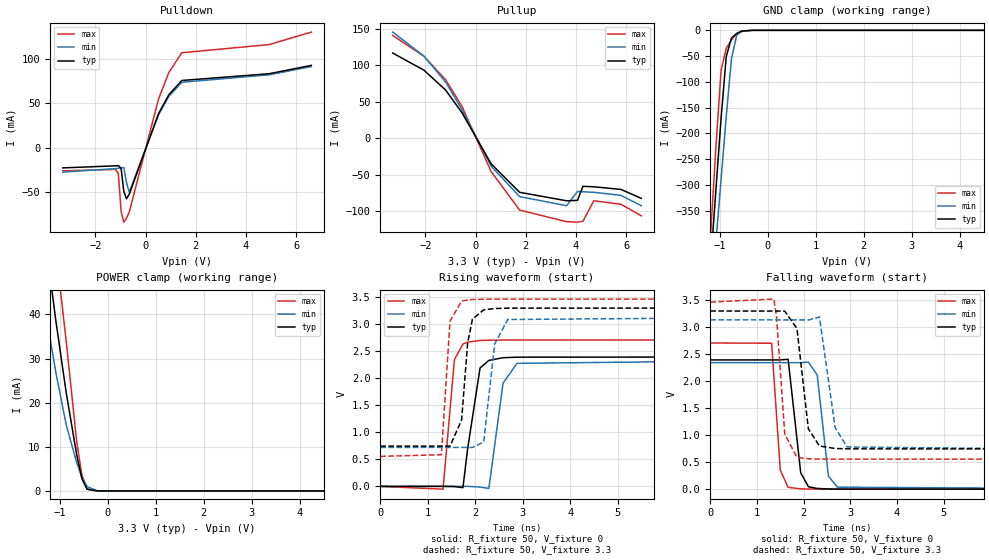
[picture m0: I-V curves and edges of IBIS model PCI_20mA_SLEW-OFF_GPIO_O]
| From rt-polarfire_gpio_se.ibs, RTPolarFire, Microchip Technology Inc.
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|   Model PCI_20mA_SLEW-OFF_GPIO_O
[Model]   PCI_20mA_SLEW-OFF_GPIO_O
Model_type   Output
Polarity   Non-Inverting
Enable   Active-High
Cref =   5p
Rref =   25
|   typ   min   max
C_comp_pullup   2.605e-12   2.605e-12   2.76e-12
C_comp_pulldown  2.605e-12   2.605e-12   2.76e-12
| Vmeas and Vref depend on the measuring edge
| Rising Edge, uncomment the following
Vmeas =   0.9405V
Vref =   0.000V
| Falling Edge, uncomment the following
|Vmeas =   2.0295V
|Vref =   3.300V
[Model Spec]
Vmeas_rising   0.9405V   0.8934V   0.9875V
Vref_rising   0.000V   0.000V   0.000V
Vmeas_falling   2.0295V   1.9280V   2.1309V
Vref_falling   3.300V   3.135V   3.465V
[Temperature Range]  25C   125C   -55C
[Voltage Range]  3.3   3.135   3.465
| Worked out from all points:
|   slope of the pulldown table from 0 to 0.495 V, typ, clamps not added: 13.4 ohm
|   slope of the pullup table from 0 to 0.495 V, typ, clamps not added: 17.3 ohm
|   GND clamp passes 1 mA (typ) near -0.51 V on its own axis
|   POWER clamp passes 1 mA (typ) near -0.46 V on its own axis
|   rising waveform, R_fixture 50, V_fixture 0: 20-80 % time 180ps typ, 197ps min, 133ps max; typ from 0 V to 2.39 V
|   rising waveform, R_fixture 50, V_fixture 3.3: 20-80 % time 145ps typ, 176ps min, 105ps max; typ from 0.745 V to 3.3 V
|   falling waveform, R_fixture 50, V_fixture 0: 20-80 % time 128ps typ, 151ps min, 93.3ps max; typ from 2.39 V to 0 V
|   falling waveform, R_fixture 50, V_fixture 3.3: 20-80 % time 192ps typ, 204ps min, 137ps max; typ from 3.3 V to 0.745 V
[GND Clamp]
| Voltage   I(typ)   I(min)   I(max)
-3.3V     -3.213A    -2.953A    -3.676A
-1.191V   -450mA     -534.3mA   -393.2mA
-1.083V   -310.2mA   -411.6mA   -227.5mA
-974.5mV  -170.4mA   -288.9mA   -76.97mA
-866.2mV  -50.48mA   -166.3mA   -34.78mA
-758mV    -15.08mA   -54.7mA    -18.33mA
-649.7mV  -5.883mA   -9.683mA   -6.874mA
-541.4mV  -1.389mA   -1.864mA   -1.426mA
-324.8mV  -3.553uA   -16.68uA   -1.172uA
6.6V      0A         0A         0A
[POWER Clamp]
| Voltage   I(typ)   I(min)   I(max)
-3.3V     320.3mA    256.6mA    387.1mA
-1.624V   89.11mA    65.97mA    116.9mA
-1.408V   67.23mA    48.87mA    90.32mA
-1.299V   57.08mA    41.04mA    77.84mA
-1.191V   47.51mA    33.68mA    65.79mA
-1.083V   38.51mA    26.79mA    54.52mA
-866.2mV  22.14mA    14.9mA     33.75mA
-649.7mV  8.213mA    6.429mA    11.19mA
-541.4mV  2.791mA    3.18mA     3.642mA
-433.1mV  359.8uA    981.3uA    499.4uA
-216.6mV  159.8nA    8.88uA     59.07nA
6.6V      0A         0A         0A
[Pullup]
| Voltage   I(typ)   I(min)   I(max)
-3.3V     117mA      145.7mA    141.1mA
-2.057V   93.5mA     112.8mA    112.5mA
-1.191V   66.14mA    77.19mA    80.37mA
-541.4mV  35.17mA    39.57mA    43.91mA
618.8mV   -34.87mA   -38.07mA   -45.43mA
1.753V    -73.94mA   -79.81mA   -98.31mA
3.625V    -85.57mA   -92.33mA   -114.2mA
4.058V    -84.98mA   -72.83mA   -114.9mA
4.275V    -65.71mA   -73.19mA   -113.6mA
4.708V    -66.38mA   -73.95mA   -85.52mA
5.79V     -69.97mA   -78.11mA   -90.3mA
6.6V      -82.26mA   -92.3mA    -106.2mA
[Pulldown]
| Voltage   I(typ)   I(min)   I(max)
-3.3V     -22.95mA   -27.7mA    -26.21mA
-1.191V   -20.65mA   -23.8mA    -24.73mA
-1.083V   -20.45mA   -23.29mA   -29.63mA
-974.5mV  -23.56mA   -22.74mA   -72.15mA
-866.2mV  -49.58mA   -22.71mA   -84.24mA
-758mV    -57.79mA   -39.9mA    -79.68mA
-649.7mV  -52.66mA   -50.34mA   -72.76mA
515.6mV   38.32mA    37.03mA    54.75mA
928.1mV   59.63mA    57.85mA    84.81mA
1.444V    75.7mA     73.69mA    107mA
4.924V    83.32mA    82.08mA    116.2mA
6.6V      92.71mA    91.43mA    130.3mA
[Ramp]
dV/dt_r   1.43642/0.180403n  1.40571/0.196944n  1.62438/0.132698n
dV/dt_f   1.53328/0.192092n  1.44881/0.204484n  1.74554/0.137438n
R_load = 50
[Rising Waveform]
R_fixture = 50
V_fixture = 0
V_fixture_min = 0
V_fixture_max = 0
| Time   V(typ)   V(min)   V(max)
0s        32.7nV     45.66nV    84.14nV
1.322ns   738.8uV    593.8uV    -51.47mV
1.562ns   -3.682mV   701.6uV    2.346V
1.741ns   -23.01mV   782uV      2.633V
1.84ns    694.5mV    826.4uV    2.669V
2.102ns   2.191V     -12.84mV   2.699V
2.287ns   2.33V      -37.77mV   2.704V
2.586ns   2.38V      1.91V      2.707V
2.88ns    2.39V      2.276V     2.707V
10ns      2.394V     2.343V     2.707V
[Rising Waveform]
R_fixture = 50
V_fixture = 3.3
V_fixture_min = 3.135
V_fixture_max = 3.465
| Time   V(typ)   V(min)   V(max)
0s        744.5mV    720.3mV    555.8mV
1.287ns   744.8mV    720.9mV    585.4mV
1.469ns   744.9mV    721mV      3.057V
1.713ns   1.229V     721.1mV    3.428V
1.84ns    2.649V     721.1mV    3.448V
1.941ns   3.093V     719.8mV    3.456V
2.178ns   3.265V     819.6mV    3.463V
2.41ns    3.29V      2.637V     3.464V
2.685ns   3.297V     3.087V     3.464V
10ns      3.3V       3.135V     3.465V
[Falling Waveform]
R_fixture = 50
V_fixture = 0
V_fixture_min = 0
V_fixture_max = 0
| Time   V(typ)   V(min)   V(max)
0s        2.394V     2.343V     2.707V
1.314ns   2.394V     2.343V     2.703V
1.499ns   2.394V     2.343V     354.8mV
1.668ns   2.405V     2.343V     33.62mV
1.937ns   303.7mV    2.343V     6.067mV
2.103ns   44.1mV     2.354V     2.356mV
2.291ns   13.39mV    2.114V     931.6uV
2.53ns    4.007mV    242.8mV    287.8uV
2.723ns   1.596mV    36.96mV    264.3uV
10ns      499.5nV    3.384uV    69.15nV
[Falling Waveform]
R_fixture = 50
V_fixture = 3.3
V_fixture_min = 3.135
V_fixture_max = 3.465
| Time   V(typ)   V(min)   V(max)
0s        3.3V       3.135V     3.465V
1.362ns   3.299V     3.135V     3.521V
1.418ns   3.299V     3.134V     3.206V
1.595ns   3.298V     3.134V     1.024V
1.857ns   2.974V     3.134V     587mV
2.101ns   1.118V     3.133V     562.9mV
2.338ns   799.5mV    3.19V      557.7mV
2.674ns   753.4mV    1.144V     556.4mV
2.929ns   747.2mV    781.5mV    556.4mV
10ns      744.5mV    720.3mV    555.8mV
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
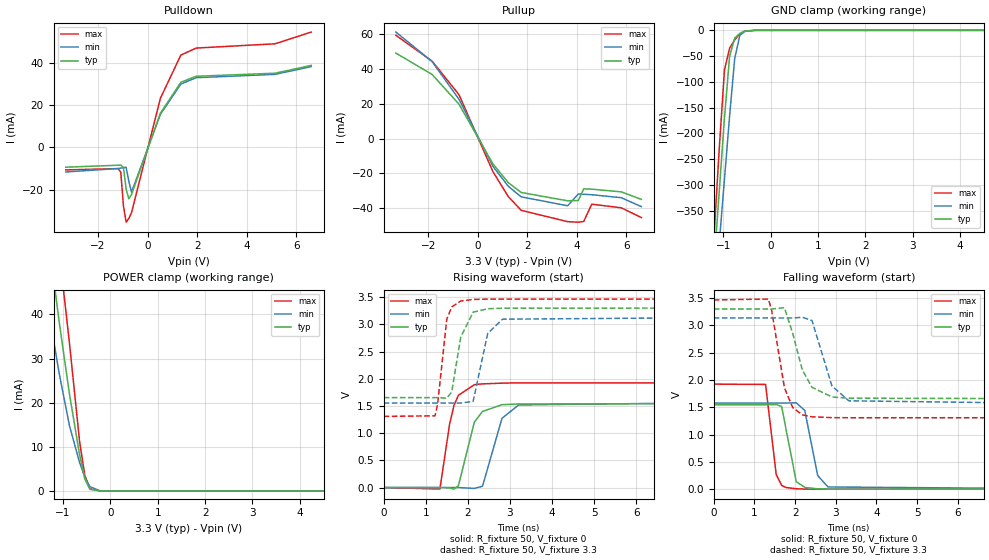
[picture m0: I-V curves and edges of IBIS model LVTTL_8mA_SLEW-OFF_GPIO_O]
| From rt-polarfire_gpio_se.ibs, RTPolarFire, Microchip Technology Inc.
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|   Model LVTTL_8mA_SLEW-OFF_GPIO_O
[Model]   LVTTL_8mA_SLEW-OFF_GPIO_O
Model_type   Output
Polarity   Non-Inverting
Enable   Active-High
Vmeas =   1.65
Cref =   5p
Rref =   1M
|   typ   min   max
C_comp_pullup   2.605e-12   2.605e-12   2.76e-12
C_comp_pulldown  2.605e-12   2.605e-12   2.76e-12
[Temperature Range]  25C   125C   -55C
[Voltage Range]  3.3   3.135   3.465
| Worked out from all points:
|   slope of the pulldown table from 0 to 0.495 V, typ, clamps not added: 31.7 ohm
|   slope of the pullup table from 0 to 0.495 V, typ, clamps not added: 41.2 ohm
|   GND clamp passes 1 mA (typ) near -0.51 V on its own axis
|   POWER clamp passes 1 mA (typ) near -0.46 V on its own axis
|   rising waveform, R_fixture 50, V_fixture 0: 20-80 % time 318ps typ, 351ps min, 255ps max; typ from 0 V to 1.55 V
|   rising waveform, R_fixture 50, V_fixture 3.3: 20-80 % time 225ps typ, 251ps min, 172ps max; typ from 1.65 V to 3.3 V
|   falling waveform, R_fixture 50, V_fixture 0: 20-80 % time 188ps typ, 234ps min, 146ps max; typ from 1.55 V to 0 V
|   falling waveform, R_fixture 50, V_fixture 3.3: 20-80 % time 392ps typ, 406ps min, 318ps max; typ from 3.3 V to 1.65 V
[GND Clamp]
| Voltage   I(typ)   I(min)   I(max)
-3.3V     -3.213A    -2.953A    -3.676A
-1.191V   -450mA     -534.3mA   -393.2mA
-1.083V   -310.2mA   -411.6mA   -227.5mA
-974.5mV  -170.4mA   -288.9mA   -76.97mA
-866.2mV  -50.48mA   -166.3mA   -34.78mA
-758mV    -15.08mA   -54.7mA    -18.33mA
-649.7mV  -5.883mA   -9.683mA   -6.874mA
-541.4mV  -1.389mA   -1.864mA   -1.426mA
-324.8mV  -3.553uA   -16.68uA   -1.172uA
6.6V      0A         0A         0A
[POWER Clamp]
| Voltage   I(typ)   I(min)   I(max)
-3.3V     320.3mA    256.6mA    387.1mA
-1.624V   89.11mA    65.97mA    116.9mA
-1.408V   67.23mA    48.87mA    90.32mA
-1.299V   57.08mA    41.04mA    77.84mA
-1.191V   47.51mA    33.68mA    65.79mA
-1.083V   38.51mA    26.79mA    54.52mA
-866.2mV  22.14mA    14.9mA     33.75mA
-649.7mV  8.213mA    6.429mA    11.19mA
-541.4mV  2.791mA    3.18mA     3.642mA
-433.1mV  359.8uA    981.3uA    499.4uA
-216.6mV  159.8nA    8.88uA     59.07nA
6.6V      0A         0A         0A
[Pullup]
| Voltage   I(typ)   I(min)   I(max)
-3.3V     49.01mA    61.08mA    59.23mA
-1.841V   36.8mA     44.17mA    44.41mA
-758mV    19.77mA    22.59mA    25.23mA
618.8mV   -14.64mA   -16.01mA   -19.11mA
1.238V    -25.28mA   -27.44mA   -33.37mA
1.753V    -30.9mA    -33.39mA   -41.12mA
3.625V    -35.67mA   -38.52mA   -47.62mA
4.058V    -35.49mA   -31.76mA   -47.93mA
4.275V    -28.78mA   -31.92mA   -47.51mA
4.599V    -29mA      -32.17mA   -37.61mA
5.79V     -30.53mA   -33.88mA   -39.68mA
6.6V      -34.85mA   -39.01mA   -45.28mA
[Pulldown]
| Voltage   I(typ)   I(min)   I(max)
-3.3V     -9.313mA   -11.56mA   -10.59mA
-1.191V   -8.379mA   -9.941mA   -9.988mA
-1.083V   -8.301mA   -9.731mA   -11.63mA
-974.5mV  -9.371mA   -9.502mA   -27.6mA
-866.2mV  -19.57mA   -9.359mA   -35.26mA
-758mV    -24.21mA   -15.94mA   -33.52mA
-649.7mV  -22.21mA   -21.08mA   -30.78mA
515.6mV   16.17mA    15.64mA    23.21mA
1.341V    30.74mA    29.91mA    43.59mA
1.959V    33.59mA    32.92mA    46.9mA
5.141V    35.03mA    34.49mA    48.92mA
6.6V      38.71mA    38.17mA    54.44mA
[Ramp]
dV/dt_r   0.927342/0.318482n  0.946258/0.350581n  1.15407/0.255484n
dV/dt_f   0.987634/0.391609n  0.948714/0.405637n  1.29419/0.317893n
R_load = 50
[Rising Waveform]
R_fixture = 50
V_fixture = 0
V_fixture_min = 0
V_fixture_max = 0
| Time   V(typ)   V(min)   V(max)
0s        62.35nV    86.49nV    169.2nV
1.336ns   -722.6uV   439.6uV    -26.56mV
1.565ns   -4.928mV   514.9uV    1.16V
1.67ns    -29.5mV    549.4uV    1.51V
1.775ns   32.86mV    584uV      1.696V
2.154ns   1.202V     -15.79mV   1.891V
2.348ns   1.399V     24.14mV    1.906V
2.81ns    1.523V     1.272V     1.919V
3.206ns   1.537V     1.519V     1.925V
10ns      1.546V     1.577V     1.923V
[Rising Waveform]
R_fixture = 50
V_fixture = 3.3
V_fixture_min = 3.135
V_fixture_max = 3.465
| Time   V(typ)   V(min)   V(max)
0s        1.654V     1.554V     1.308V
1.221ns   1.653V     1.554V     1.319V
1.28ns    1.653V     1.554V     1.524V
1.5ns     1.643V     1.554V     3.097V
1.617ns   1.758V     1.554V     3.32V
1.831ns   2.767V     1.554V     3.429V
2.125ns   3.224V     1.583V     3.458V
2.471ns   3.287V     2.832V     3.464V
2.823ns   3.297V     3.095V     3.465V
10ns      3.3V       3.135V     3.465V
[Falling Waveform]
R_fixture = 50
V_fixture = 0
V_fixture_min = 0
V_fixture_max = 0
| Time   V(typ)   V(min)   V(max)
0s        1.546V     1.577V     1.923V
1.274ns   1.546V     1.577V     1.918V
1.535ns   1.549V     1.577V     268.1mV
1.67ns    1.515V     1.577V     68.33mV
1.773ns   1.111V     1.577V     30.6mV
2.028ns   137.5mV    1.582V     7.279mV
2.238ns   31.68mV    1.441V     2.229mV
2.555ns   6.17mV     249.3mV    715.9uV
2.808ns   2.093mV    40.29mV    691.6uV
10ns      656.8nV    996.2nV    65.11nV
[Falling Waveform]
R_fixture = 50
V_fixture = 3.3
V_fixture_min = 3.135
V_fixture_max = 3.465
| Time   V(typ)   V(min)   V(max)
0s        3.3V       3.135V     3.465V
1.344ns   3.299V     3.135V     3.481V
1.422ns   3.299V     3.135V     3.278V
1.738ns   3.323V     3.134V     1.854V
1.941ns   2.851V     3.134V     1.494V
2.177ns   2.182V     3.148V     1.362V
2.415ns   1.865V     3.088V     1.325V
2.905ns   1.688V     1.89V      1.31V
3.319ns   1.666V     1.618V     1.308V
10ns      1.654V     1.554V     1.308V
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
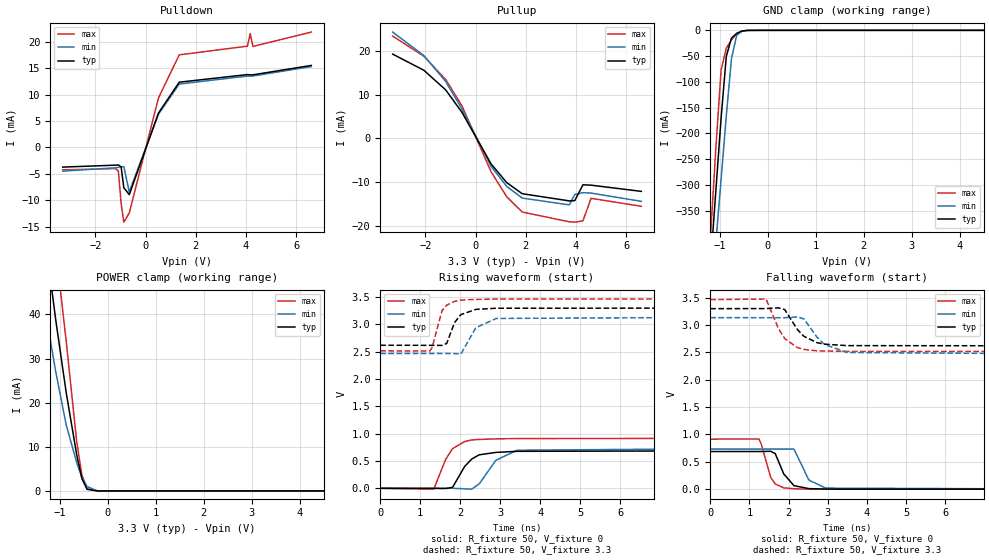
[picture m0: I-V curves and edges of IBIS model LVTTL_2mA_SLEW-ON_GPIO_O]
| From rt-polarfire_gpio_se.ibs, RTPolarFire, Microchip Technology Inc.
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|   Model LVTTL_2mA_SLEW-ON_GPIO_O
[Model]   LVTTL_2mA_SLEW-ON_GPIO_O
Model_type   Output
Polarity   Non-Inverting
Enable   Active-High
Vmeas =   1.65
Cref =   5p
Rref =   1M
|   typ   min   max
C_comp_pullup   2.605e-12   2.605e-12   2.76e-12
C_comp_pulldown  2.605e-12   2.605e-12   2.76e-12
[Temperature Range]  25C   125C   -55C
[Voltage Range]  3.3   3.135   3.465
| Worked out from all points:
|   slope of the pulldown table from 0 to 0.495 V, typ, clamps not added: 78.7 ohm
|   slope of the pullup table from 0 to 0.495 V, typ, clamps not added: 102 ohm
|   GND clamp passes 1 mA (typ) near -0.51 V on its own axis
|   POWER clamp passes 1 mA (typ) near -0.46 V on its own axis
|   rising waveform, R_fixture 50, V_fixture 0: 20-80 % time 399ps typ, 482ps min, 349ps max; typ from 0 V to 0.688 V
|   rising waveform, R_fixture 50, V_fixture 3.3: 20-80 % time 273ps typ, 335ps min, 228ps max; typ from 2.62 V to 3.3 V
|   falling waveform, R_fixture 50, V_fixture 0: 20-80 % time 283ps typ, 293ps min, 232ps max; typ from 0.688 V to 0 V
|   falling waveform, R_fixture 50, V_fixture 3.3: 20-80 % time 463ps typ, 510ps min, 411ps max; typ from 3.3 V to 2.62 V
[GND Clamp]
| Voltage   I(typ)   I(min)   I(max)
-3.3V     -3.213A    -2.953A    -3.676A
-1.191V   -450mA     -534.3mA   -393.2mA
-1.083V   -310.2mA   -411.6mA   -227.5mA
-974.5mV  -170.4mA   -288.9mA   -76.97mA
-866.2mV  -50.48mA   -166.3mA   -34.78mA
-758mV    -15.08mA   -54.7mA    -18.33mA
-649.7mV  -5.883mA   -9.683mA   -6.874mA
-541.4mV  -1.389mA   -1.864mA   -1.426mA
-433.1mV  -123uA     -242.9uA   -102.9uA
-108.3mV  -6.015nA   -50.2nA    -17.55nA
6.6V      0A         0A         0A
[POWER Clamp]
| Voltage   I(typ)   I(min)   I(max)
-3.3V     320.3mA    256.6mA    387.1mA
-1.624V   89.11mA    65.97mA    116.9mA
-1.408V   67.23mA    48.87mA    90.32mA
-1.299V   57.08mA    41.04mA    77.84mA
-1.191V   47.51mA    33.68mA    65.79mA
-1.083V   38.51mA    26.79mA    54.52mA
-866.2mV  22.14mA    14.9mA     33.75mA
-649.7mV  8.213mA    6.429mA    11.19mA
-541.4mV  2.791mA    3.18mA     3.642mA
-433.1mV  359.8uA    981.3uA    499.4uA
-216.6mV  159.8nA    8.88uA     59.07nA
6.6V      0A         0A         0A
[Pullup]
| Voltage   I(typ)   I(min)   I(max)
-3.3V     19.29mA    24.34mA    23.42mA
-2.057V   15.58mA    18.94mA    18.79mA
-1.191V   11.1mA     13.02mA    13.49mA
-541.4mV  5.944mA    6.707mA    7.425mA
618.8mV   -5.885mA   -6.429mA   -7.68mA
1.238V    -10.15mA   -11.01mA   -13.4mA
1.856V    -12.7mA    -13.7mA    -16.9mA
3.733V    -14.35mA   -15.27mA   -19.14mA
3.95V     -14.29mA   -12.89mA   -19.23mA
4.275V    -10.66mA   -12.46mA   -18.92mA
4.599V    -10.74mA   -12.56mA   -13.76mA
6.6V      -12.17mA   -14.45mA   -15.59mA
[Pulldown]
| Voltage   I(typ)   I(min)   I(max)
-3.3V     -3.739mA   -4.496mA   -4.257mA
-1.191V   -3.367mA   -3.865mA   -4.017mA
-1.083V   -3.336mA   -3.784mA   -4.528mA
-974.5mV  -3.682mA   -3.697mA   -10.54mA
-866.2mV  -7.63mA    -3.651mA   -14.16mA
-649.7mV  -8.948mA   -8.42mA    -12.42mA
515.6mV   6.515mA    6.284mA    9.374mA
1.341V    12.33mA    11.98mA    17.5mA
4.058V    13.77mA    13.49mA    19.15mA
4.166V    13.72mA    13.49mA    21.52mA
4.275V    13.72mA    13.5mA     19.1mA
6.6V      15.5mA     15.29mA    21.81mA
[Ramp]
dV/dt_r   0.412647/0.399265n  0.439639/0.482224n  0.548645/0.348717n
dV/dt_f   0.408761/0.462875n  0.400051/0.510466n  0.569027/0.410653n
R_load = 50
[Rising Waveform]
R_fixture = 50
V_fixture = 0
V_fixture_min = 0
V_fixture_max = 0
| Time   V(typ)   V(min)   V(max)
0s        102.4nV    141.1nV    300.9nV
1.338ns   -699.2uV   698.8uV    -15.06mV
1.632ns   -4.186mV   852.3uV    528.5mV
1.806ns   17.64mV    943.1uV    727.4mV
2.111ns   403.4mV    -9.759mV   857.3mV
2.285ns   536.2mV    -15.58mV   885.3mV
2.472ns   613.9mV    81.38mV    894.4mV
2.887ns   657mV      513.1mV    905mV
3.416ns   677.5mV    697.4mV    911.1mV
10ns      687.7mV    732.7mV    914.4mV
[Rising Waveform]
R_fixture = 50
V_fixture = 3.3
V_fixture_min = 3.135
V_fixture_max = 3.465
| Time   V(typ)   V(min)   V(max)
0s        2.619V     2.468V     2.517V
1.239ns   2.618V     2.468V     2.513V
1.295ns   2.618V     2.468V     2.579V
1.543ns   2.616V     2.468V     3.254V
1.66ns    2.653V     2.468V     3.354V
1.853ns   3.032V     2.468V     3.422V
2.012ns   3.18V      2.456V     3.447V
2.386ns   3.276V     2.939V     3.459V
2.896ns   3.297V     3.11V      3.465V
10ns      3.3V       3.135V     3.465V
[Falling Waveform]
R_fixture = 50
V_fixture = 0
V_fixture_min = 0
V_fixture_max = 0
| Time   V(typ)   V(min)   V(max)
0s        687.8mV    732.9mV    914.4mV
1.238ns   688mV      733.2mV    918mV
1.295ns   688.1mV    733.2mV    838mV
1.543ns   692.9mV    733.3mV    215.9mV
1.658ns   650.6mV    733.3mV    95.12mV
1.874ns   279.3mV    733.3mV    24.52mV
2.136ns   63.83mV    731.9mV    7.072mV
2.516ns   10.02mV    167.4mV    823.9uV
2.945ns   1.937mV    19.1mV     193.5nV
10ns      1.07uV     675nV      692.8nV
[Falling Waveform]
R_fixture = 50
V_fixture = 3.3
V_fixture_min = 3.135
V_fixture_max = 3.465
| Time   V(typ)   V(min)   V(max)
0s        3.3V       3.135V     3.465V
1.424ns   3.301V     3.134V     3.475V
1.735ns   3.315V     3.134V     2.944V
1.899ns   3.284V     3.134V     2.753V
2.224ns   2.918V     3.148V     2.587V
2.39ns    2.794V     3.113V     2.555V
2.724ns   2.678V     2.778V     2.528V
2.908ns   2.651V     2.65V      2.525V
3.49ns    2.624V     2.498V     2.52V
10ns      2.619V     2.468V     2.517V
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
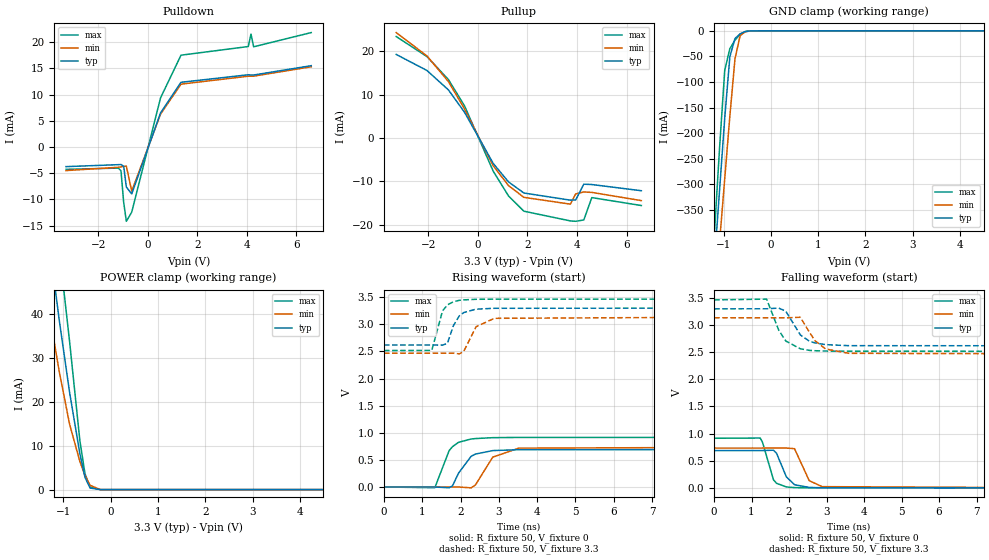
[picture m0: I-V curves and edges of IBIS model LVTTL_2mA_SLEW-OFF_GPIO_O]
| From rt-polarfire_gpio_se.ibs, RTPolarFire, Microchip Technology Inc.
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|   Model LVTTL_2mA_SLEW-OFF_GPIO_O
[Model]   LVTTL_2mA_SLEW-OFF_GPIO_O
Model_type   Output
Polarity   Non-Inverting
Enable   Active-High
Vmeas =   1.65
Cref =   5p
Rref =   1M
|   typ   min   max
C_comp_pullup   2.605e-12   2.605e-12   2.76e-12
C_comp_pulldown  2.605e-12   2.605e-12   2.76e-12
[Temperature Range]  25C   125C   -55C
[Voltage Range]  3.3   3.135   3.465
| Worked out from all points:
|   slope of the pulldown table from 0 to 0.495 V, typ, clamps not added: 78.7 ohm
|   slope of the pullup table from 0 to 0.495 V, typ, clamps not added: 102 ohm
|   GND clamp passes 1 mA (typ) near -0.51 V on its own axis
|   POWER clamp passes 1 mA (typ) near -0.46 V on its own axis
|   rising waveform, R_fixture 50, V_fixture 0: 20-80 % time 366ps typ, 429ps min, 334ps max; typ from 0 V to 0.688 V
|   rising waveform, R_fixture 50, V_fixture 3.3: 20-80 % time 263ps typ, 328ps min, 220ps max; typ from 2.62 V to 3.3 V
|   falling waveform, R_fixture 50, V_fixture 0: 20-80 % time 276ps typ, 273ps min, 224ps max; typ from 0.688 V to 0 V
|   falling waveform, R_fixture 50, V_fixture 3.3: 20-80 % time 419ps typ, 431ps min, 381ps max; typ from 3.3 V to 2.62 V
[GND Clamp]
| Voltage   I(typ)   I(min)   I(max)
-3.3V     -3.213A    -2.953A    -3.676A
-1.191V   -450mA     -534.3mA   -393.2mA
-1.083V   -310.2mA   -411.6mA   -227.5mA
-974.5mV  -170.4mA   -288.9mA   -76.97mA
-866.2mV  -50.48mA   -166.3mA   -34.78mA
-758mV    -15.08mA   -54.7mA    -18.33mA
-649.7mV  -5.883mA   -9.683mA   -6.874mA
-541.4mV  -1.389mA   -1.864mA   -1.426mA
-433.1mV  -123uA     -242.9uA   -102.9uA
-108.3mV  -6.015nA   -50.2nA    -17.55nA
6.6V      0A         0A         0A
[POWER Clamp]
| Voltage   I(typ)   I(min)   I(max)
-3.3V     320.3mA    256.6mA    387.1mA
-1.624V   89.11mA    65.97mA    116.9mA
-1.408V   67.23mA    48.87mA    90.32mA
-1.299V   57.08mA    41.04mA    77.84mA
-1.191V   47.51mA    33.68mA    65.79mA
-1.083V   38.51mA    26.79mA    54.52mA
-866.2mV  22.14mA    14.9mA     33.75mA
-649.7mV  8.213mA    6.429mA    11.19mA
-541.4mV  2.791mA    3.18mA     3.642mA
-433.1mV  359.8uA    981.3uA    499.4uA
-216.6mV  159.8nA    8.88uA     59.07nA
6.6V      0A         0A         0A
[Pullup]
| Voltage   I(typ)   I(min)   I(max)
-3.3V     19.29mA    24.34mA    23.42mA
-2.057V   15.58mA    18.94mA    18.79mA
-1.191V   11.1mA     13.02mA    13.49mA
-541.4mV  5.944mA    6.707mA    7.425mA
618.8mV   -5.885mA   -6.429mA   -7.68mA
1.238V    -10.15mA   -11.01mA   -13.4mA
1.856V    -12.7mA    -13.7mA    -16.9mA
3.733V    -14.35mA   -15.27mA   -19.14mA
3.95V     -14.29mA   -12.89mA   -19.23mA
4.275V    -10.66mA   -12.46mA   -18.92mA
4.599V    -10.74mA   -12.56mA   -13.76mA
6.6V      -12.17mA   -14.45mA   -15.59mA
[Pulldown]
| Voltage   I(typ)   I(min)   I(max)
-3.3V     -3.739mA   -4.496mA   -4.257mA
-1.191V   -3.367mA   -3.865mA   -4.017mA
-1.083V   -3.336mA   -3.784mA   -4.528mA
-974.5mV  -3.682mA   -3.697mA   -10.54mA
-866.2mV  -7.63mA    -3.651mA   -14.16mA
-649.7mV  -8.948mA   -8.42mA    -12.42mA
515.6mV   6.515mA    6.284mA    9.374mA
1.341V    12.33mA    11.98mA    17.5mA
4.058V    13.77mA    13.49mA    19.15mA
4.166V    13.72mA    13.49mA    21.52mA
4.275V    13.72mA    13.5mA     19.1mA
6.6V      15.5mA     15.29mA    21.81mA
[Ramp]
dV/dt_r   0.412661/0.366321n  0.439675/0.429222n  0.548636/0.334481n
dV/dt_f   0.408767/0.418814n  0.400054/0.431471n  0.56906/0.380593n
R_load = 50
[Rising Waveform]
R_fixture = 50
V_fixture = 0
V_fixture_min = 0
V_fixture_max = 0
| Time   V(typ)   V(min)   V(max)
0s        102.4nV    141.2nV    300.9nV
1.328ns   -749.7uV   87.49uV    -13.26mV
1.702ns   -13.89mV   112.1uV    671.9mV
1.791ns   22.24mV    117.9uV    745.1mV
1.946ns   254.5mV    128.1uV    824mV
2.276ns   565.9mV    -15.92mV   885.4mV
2.389ns   607.5mV    38.93mV    893.2mV
2.84ns    671.7mV    550.1mV    909.7mV
3.52ns    687.9mV    716.6mV    914.5mV
10ns      687.8mV    732.8mV    914.4mV
[Rising Waveform]
R_fixture = 50
V_fixture = 3.3
V_fixture_min = 3.135
V_fixture_max = 3.465
| Time   V(typ)   V(min)   V(max)
0s        2.619V     2.468V     2.517V
1.248ns   2.618V     2.468V     2.518V
1.529ns   2.617V     2.468V     3.247V
1.656ns   2.648V     2.468V     3.358V
1.815ns   2.979V     2.468V     3.418V
1.968ns   3.157V     2.456V     3.443V
2.081ns   3.217V     2.5V       3.451V
2.403ns   3.28V      2.955V     3.462V
2.883ns   3.296V     3.111V     3.464V
10ns      3.3V       3.135V     3.465V
[Falling Waveform]
R_fixture = 50
V_fixture = 0
V_fixture_min = 0
V_fixture_max = 0
| Time   V(typ)   V(min)   V(max)
0s        687.8mV    732.9mV    914.4mV
1.231ns   688.1mV    733.5mV    918.5mV
1.292ns   688.1mV    733.5mV    839.7mV
1.584ns   694mV      733.7mV    149.4mV
1.665ns   639.9mV    733.7mV    84.77mV
1.928ns   202.6mV    733.8mV    16.61mV
2.146ns   57.58mV    722mV      4.942mV
2.537ns   7.953mV    132.9mV    518.6uV
2.882ns   1.573mV    22.32mV    494.6uV
10ns      534.1nV    3.759uV    203.4nV
[Falling Waveform]
R_fixture = 50
V_fixture = 3.3
V_fixture_min = 3.135
V_fixture_max = 3.465
| Time   V(typ)   V(min)   V(max)
0s        3.3V       3.135V     3.465V
1.401ns   3.301V     3.135V     3.479V
1.724ns   3.314V     3.134V     2.907V
1.914ns   3.256V     3.134V     2.706V
2.3ns     2.82V      3.145V     2.564V
2.544ns   2.702V     2.868V     2.534V
2.694ns   2.671V     2.711V     2.528V
2.976ns   2.64V      2.56V      2.522V
3.596ns   2.621V     2.48V      2.519V
10ns      2.619V     2.468V     2.517V
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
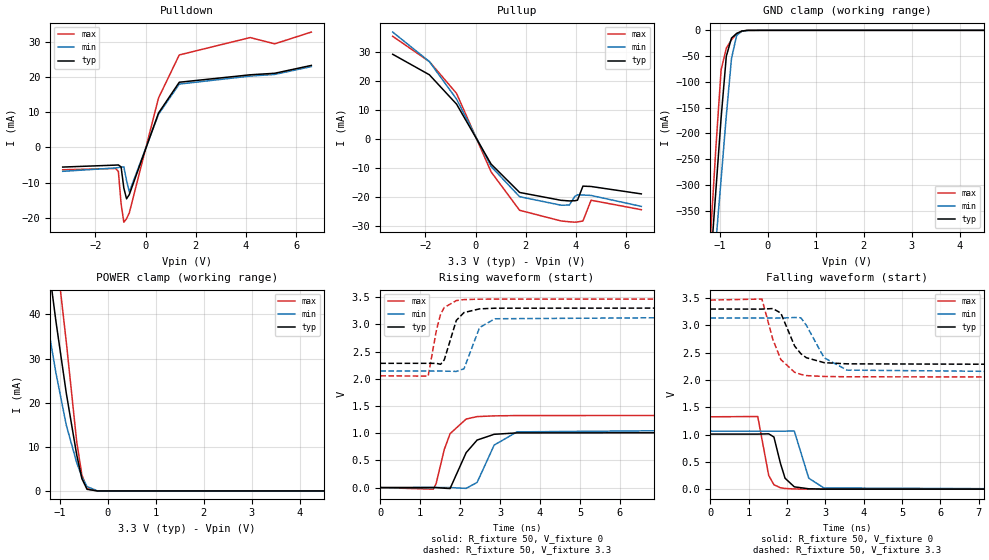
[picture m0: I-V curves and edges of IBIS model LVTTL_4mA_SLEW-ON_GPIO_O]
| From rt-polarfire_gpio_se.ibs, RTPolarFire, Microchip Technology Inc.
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|   Model LVTTL_4mA_SLEW-ON_GPIO_O
[Model]   LVTTL_4mA_SLEW-ON_GPIO_O
Model_type   Output
Polarity   Non-Inverting
Enable   Active-High
Vmeas =   1.65
Cref =   5p
Rref =   1M
|   typ   min   max
C_comp_pullup   2.605e-12   2.605e-12   2.76e-12
C_comp_pulldown  2.605e-12   2.605e-12   2.76e-12
[Temperature Range]  25C   125C   -55C
[Voltage Range]  3.3   3.135   3.465
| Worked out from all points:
|   slope of the pulldown table from 0 to 0.495 V, typ, clamps not added: 52.5 ohm
|   slope of the pullup table from 0 to 0.495 V, typ, clamps not added: 68.4 ohm
|   GND clamp passes 1 mA (typ) near -0.51 V on its own axis
|   POWER clamp passes 1 mA (typ) near -0.46 V on its own axis
|   rising waveform, R_fixture 50, V_fixture 0: 20-80 % time 399ps typ, 445ps min, 345ps max; typ from 0 V to 1.01 V
|   rising waveform, R_fixture 50, V_fixture 3.3: 20-80 % time 275ps typ, 310ps min, 222ps max; typ from 2.28 V to 3.3 V
|   falling waveform, R_fixture 50, V_fixture 0: 20-80 % time 226ps typ, 263ps min, 179ps max; typ from 1.01 V to 0 V
|   falling waveform, R_fixture 50, V_fixture 3.3: 20-80 % time 444ps typ, 516ps min, 401ps max; typ from 3.3 V to 2.28 V
[GND Clamp]
| Voltage   I(typ)   I(min)   I(max)
-3.3V     -3.213A    -2.953A    -3.676A
-1.191V   -450mA     -534.3mA   -393.2mA
-1.083V   -310.2mA   -411.6mA   -227.5mA
-974.5mV  -170.4mA   -288.9mA   -76.97mA
-866.2mV  -50.48mA   -166.3mA   -34.78mA
-758mV    -15.08mA   -54.7mA    -18.33mA
-649.7mV  -5.883mA   -9.683mA   -6.874mA
-541.4mV  -1.389mA   -1.864mA   -1.426mA
-433.1mV  -123uA     -242.9uA   -102.9uA
-108.3mV  -6.015nA   -50.2nA    -17.55nA
6.6V      0A         0A         0A
[POWER Clamp]
| Voltage   I(typ)   I(min)   I(max)
-3.3V     320.3mA    256.6mA    387.1mA
-1.624V   89.11mA    65.97mA    116.9mA
-1.408V   67.23mA    48.87mA    90.32mA
-1.299V   57.08mA    41.04mA    77.84mA
-1.191V   47.51mA    33.68mA    65.79mA
-1.083V   38.51mA    26.79mA    54.52mA
-866.2mV  22.14mA    14.9mA     33.75mA
-649.7mV  8.213mA    6.429mA    11.19mA
-541.4mV  2.791mA    3.18mA     3.642mA
-433.1mV  359.8uA    981.3uA    499.4uA
-216.6mV  159.8nA    8.88uA     59.07nA
6.6V      0A         0A         0A
[Pullup]
| Voltage   I(typ)   I(min)   I(max)
-3.3V     29.06mA    36.71mA    35.25mA
-1.841V   22mA       26.56mA    26.55mA
-758mV    11.88mA    13.59mA    15.58mA
618.8mV   -8.81mA    -9.622mA   -11.5mA
1.753V    -18.58mA   -20.04mA   -24.72mA
3.408V    -21.29mA   -22.98mA   -28.41mA
3.733V    -21.5mA    -22.92mA   -28.69mA
3.95V     -21.43mA   -19.97mA   -28.83mA
4.058V    -21.25mA   -19.36mA   -28.75mA
4.275V    -16.4mA    -19.46mA   -28.42mA
4.599V    -16.52mA   -19.61mA   -21.26mA
6.6V      -19.07mA   -23.38mA   -24.52mA
[Pulldown]
| Voltage   I(typ)   I(min)   I(max)
-3.3V     -5.571mA   -6.776mA   -6.334mA
-1.191V   -5.015mA   -5.825mA   -5.974mA
-1.083V   -4.968mA   -5.703mA   -6.818mA
-974.5mV  -5.532mA   -5.57mA    -16.01mA
-866.2mV  -11.51mA   -5.506mA   -21.2mA
-758mV    -14.57mA   -9.382mA   -20.2mA
-649.7mV  -13.39mA   -12.63mA   -18.59mA
515.6mV   9.754mA    9.406mA    14.02mA
1.341V    18.48mA    17.96mA    26.22mA
4.166V    20.59mA    20.23mA    31.15mA
5.141V    21.02mA    20.7mA     29.37mA
6.6V      23.25mA    22.92mA    32.7mA
[Ramp]
dV/dt_r   0.605268/0.399125n  0.637881/0.44472n  0.795438/0.344913n
dV/dt_f   0.609728/0.443928n  0.595968/0.516012n  0.846508/0.400802n
R_load = 50
[Rising Waveform]
R_fixture = 50
V_fixture = 0
V_fixture_min = 0
V_fixture_max = 0
| Time   V(typ)   V(min)   V(max)
0s        84.25nV    116.6nV    238.6nV
1.327ns   808uV      670.1uV    -29.1mV
1.396ns   850uV      704.9uV    66.21mV
1.603ns   -11.51mV   809.4uV    700.7mV
1.748ns   -17.71mV   882.6uV    991.5mV
2.15ns    641.7mV    -14.78mV   1.26V
2.425ns   873.5mV    95.2mV     1.305V
2.852ns   979.3mV    781mV      1.318V
3.424ns   1.005V     1.024V     1.324V
10ns      1.009V     1.063V     1.326V
[Rising Waveform]
R_fixture = 50
V_fixture = 3.3
V_fixture_min = 3.135
V_fixture_max = 3.465
| Time   V(typ)   V(min)   V(max)
0s        2.284V     2.142V     2.054V
1.199ns   2.284V     2.142V     2.049V
1.407ns   2.283V     2.142V     2.897V
1.511ns   2.266V     2.142V     3.188V
1.602ns   2.347V     2.141V     3.31V
1.904ns   3.073V     2.135V     3.437V
2.096ns   3.217V     2.184V     3.455V
2.486ns   3.285V     2.941V     3.463V
2.872ns   3.297V     3.103V     3.464V
10ns      3.3V       3.135V     3.465V
[Falling Waveform]
R_fixture = 50
V_fixture = 0
V_fixture_min = 0
V_fixture_max = 0
| Time   V(typ)   V(min)   V(max)
0s        1.009V     1.063V     1.326V
1.238ns   1.009V     1.063V     1.331V
1.524ns   1.014V     1.063V     250.6mV
1.66ns    955.1mV    1.063V     81.43mV
1.83ns    472.2mV    1.063V     25.46mV
1.951ns   199.6mV    1.063V     13.04mV
2.191ns   42.81mV    1.065V     3.979mV
2.569ns   6.823mV    200.5mV    606.4uV
2.963ns   1.044mV    22.38mV    11.67uV
10ns      663.1nV    1.862uV    174.9nV
[Falling Waveform]
R_fixture = 50
V_fixture = 3.3
V_fixture_min = 3.135
V_fixture_max = 3.465
| Time   V(typ)   V(min)   V(max)
0s        3.3V       3.135V     3.465V
1.347ns   3.299V     3.135V     3.483V
1.632ns   3.309V     3.134V     2.744V
1.84ns    3.226V     3.134V     2.375V
2.199ns   2.623V     3.145V     2.141V
2.364ns   2.481V     3.14V      2.103V
2.506ns   2.408V     3.001V     2.081V
2.968ns   2.318V     2.408V     2.065V
3.566ns   2.296V     2.181V     2.059V
10ns      2.284V     2.142V     2.054V
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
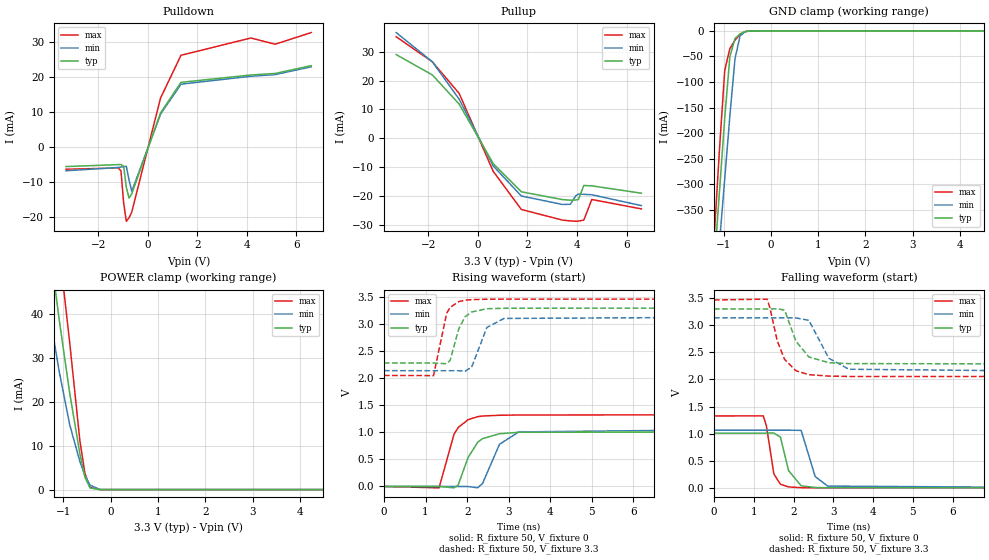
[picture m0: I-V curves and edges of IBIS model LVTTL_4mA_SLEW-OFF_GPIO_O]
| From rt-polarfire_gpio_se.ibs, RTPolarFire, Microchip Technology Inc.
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|   Model LVTTL_4mA_SLEW-OFF_GPIO_O
[Model]   LVTTL_4mA_SLEW-OFF_GPIO_O
Model_type   Output
Polarity   Non-Inverting
Enable   Active-High
Vmeas =   1.65
Cref =   5p
Rref =   1M
|   typ   min   max
C_comp_pullup   2.605e-12   2.605e-12   2.76e-12
C_comp_pulldown  2.605e-12   2.605e-12   2.76e-12
[Temperature Range]  25C   125C   -55C
[Voltage Range]  3.3   3.135   3.465
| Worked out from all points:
|   slope of the pulldown table from 0 to 0.495 V, typ, clamps not added: 52.5 ohm
|   slope of the pullup table from 0 to 0.495 V, typ, clamps not added: 68.4 ohm
|   GND clamp passes 1 mA (typ) near -0.51 V on its own axis
|   POWER clamp passes 1 mA (typ) near -0.46 V on its own axis
|   rising waveform, R_fixture 50, V_fixture 0: 20-80 % time 367ps typ, 406ps min, 319ps max; typ from 0 V to 1.01 V
|   rising waveform, R_fixture 50, V_fixture 3.3: 20-80 % time 265ps typ, 300ps min, 212ps max; typ from 2.28 V to 3.3 V
|   falling waveform, R_fixture 50, V_fixture 0: 20-80 % time 211ps typ, 246ps min, 165ps max; typ from 1.01 V to 0 V
|   falling waveform, R_fixture 50, V_fixture 3.3: 20-80 % time 391ps typ, 464ps min, 363ps max; typ from 3.3 V to 2.28 V
[GND Clamp]
| Voltage   I(typ)   I(min)   I(max)
-3.3V     -3.213A    -2.953A    -3.676A
-1.191V   -450mA     -534.3mA   -393.2mA
-1.083V   -310.2mA   -411.6mA   -227.5mA
-974.5mV  -170.4mA   -288.9mA   -76.97mA
-866.2mV  -50.48mA   -166.3mA   -34.78mA
-758mV    -15.08mA   -54.7mA    -18.33mA
-649.7mV  -5.883mA   -9.683mA   -6.874mA
-541.4mV  -1.389mA   -1.864mA   -1.426mA
-433.1mV  -123uA     -242.9uA   -102.9uA
-108.3mV  -6.015nA   -50.2nA    -17.55nA
6.6V      0A         0A         0A
[POWER Clamp]
| Voltage   I(typ)   I(min)   I(max)
-3.3V     320.3mA    256.6mA    387.1mA
-1.624V   89.11mA    65.97mA    116.9mA
-1.408V   67.23mA    48.87mA    90.32mA
-1.299V   57.08mA    41.04mA    77.84mA
-1.191V   47.51mA    33.68mA    65.79mA
-1.083V   38.51mA    26.79mA    54.52mA
-866.2mV  22.14mA    14.9mA     33.75mA
-649.7mV  8.213mA    6.429mA    11.19mA
-541.4mV  2.791mA    3.18mA     3.642mA
-433.1mV  359.8uA    981.3uA    499.4uA
-216.6mV  159.8nA    8.88uA     59.07nA
6.6V      0A         0A         0A
[Pullup]
| Voltage   I(typ)   I(min)   I(max)
-3.3V     29.06mA    36.71mA    35.25mA
-1.841V   22mA       26.56mA    26.55mA
-758mV    11.88mA    13.59mA    15.58mA
618.8mV   -8.81mA    -9.622mA   -11.5mA
1.753V    -18.58mA   -20.04mA   -24.72mA
3.408V    -21.29mA   -22.98mA   -28.41mA
3.733V    -21.5mA    -22.92mA   -28.69mA
3.95V     -21.43mA   -19.97mA   -28.83mA
4.058V    -21.25mA   -19.36mA   -28.75mA
4.275V    -16.4mA    -19.46mA   -28.42mA
4.599V    -16.52mA   -19.61mA   -21.26mA
6.6V      -19.07mA   -23.38mA   -24.52mA
[Pulldown]
| Voltage   I(typ)   I(min)   I(max)
-3.3V     -5.571mA   -6.776mA   -6.334mA
-1.191V   -5.015mA   -5.825mA   -5.974mA
-1.083V   -4.968mA   -5.703mA   -6.818mA
-974.5mV  -5.532mA   -5.57mA    -16.01mA
-866.2mV  -11.51mA   -5.506mA   -21.2mA
-758mV    -14.57mA   -9.382mA   -20.2mA
-649.7mV  -13.39mA   -12.63mA   -18.59mA
515.6mV   9.754mA    9.406mA    14.02mA
1.341V    18.48mA    17.96mA    26.22mA
4.166V    20.59mA    20.23mA    31.15mA
5.141V    21.02mA    20.7mA     29.37mA
6.6V      23.25mA    22.92mA    32.7mA
[Ramp]
dV/dt_r   0.605265/0.366908n  0.637891/0.406036n  0.795425/0.319266n
dV/dt_f   0.60978/0.39101n  0.595826/0.464402n  0.846543/0.362924n
R_load = 50
[Rising Waveform]
R_fixture = 50
V_fixture = 0
V_fixture_min = 0
V_fixture_max = 0
| Time   V(typ)   V(min)   V(max)
0s        84.25nV    116.7nV    238.6nV
1.325ns   843.8uV    -373.1uV   -25.79mV
1.685ns   -25.86mV   -474.6uV   966.5mV
1.785ns   27.37mV    -502.7uV   1.09V
2.022ns   534.7mV    -1.868mV   1.235V
2.254ns   817.6mV    -23.79mV   1.291V
2.37ns    884.2mV    53.45mV    1.303V
2.778ns   974.9mV    780.9mV    1.317V
3.242ns   1.002V     1.009V     1.322V
10ns      1.009V     1.063V     1.326V
[Rising Waveform]
R_fixture = 50
V_fixture = 3.3
V_fixture_min = 3.135
V_fixture_max = 3.465
| Time   V(typ)   V(min)   V(max)
0s        2.284V     2.142V     2.054V
1.192ns   2.283V     2.141V     2.05V
1.509ns   2.27V      2.141V     3.205V
1.592ns   2.334V     2.141V     3.312V
1.798ns   2.914V     2.141V     3.419V
1.949ns   3.136V     2.13V      3.445V
2.11ns    3.228V     2.209V     3.456V
2.474ns   3.287V     2.94V      3.463V
2.888ns   3.296V     3.108V     3.465V
10ns      3.3V       3.135V     3.465V
[Falling Waveform]
R_fixture = 50
V_fixture = 0
V_fixture_min = 0
V_fixture_max = 0
| Time   V(typ)   V(min)   V(max)
0s        1.009V     1.063V     1.326V
1.238ns   1.009V     1.063V     1.327V
1.318ns   1.009V     1.063V     1.139V
1.504ns   1.011V     1.063V     256.6mV
1.67ns    934.1mV    1.063V     65.26mV
1.873ns   319.6mV    1.063V     17.19mV
2.19ns    38.34mV    1.06V      3.334mV
2.544ns   7.152mV    207.7mV    672.7uV
2.859ns   1.822mV    32.26mV    644.4uV
10ns      1.187uV    -2.251uV   1.012uV
[Falling Waveform]
R_fixture = 50
V_fixture = 3.3
V_fixture_min = 3.135
V_fixture_max = 3.465
| Time   V(typ)   V(min)   V(max)
0s        3.3V       3.135V     3.465V
1.334ns   3.299V     3.135V     3.48V
1.404ns   3.299V     3.134V     3.323V
1.589ns   3.302V     3.134V     2.711V
1.775ns   3.277V     3.134V     2.367V
2.057ns   2.706V     3.134V     2.16V
2.384ns   2.413V     3.089V     2.087V
2.888ns   2.308V     2.389V     2.061V
3.392ns   2.291V     2.187V     2.054V
10ns      2.284V     2.142V     2.054V
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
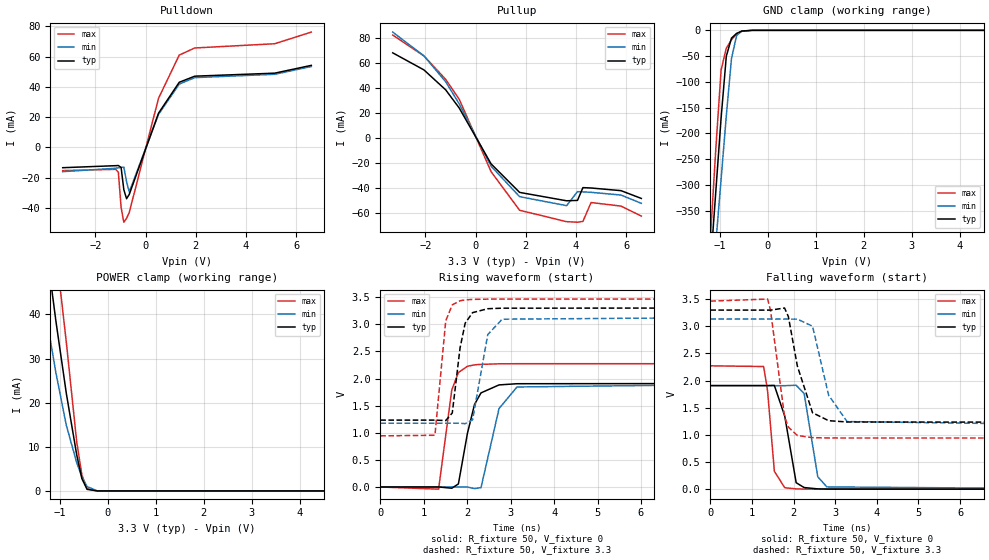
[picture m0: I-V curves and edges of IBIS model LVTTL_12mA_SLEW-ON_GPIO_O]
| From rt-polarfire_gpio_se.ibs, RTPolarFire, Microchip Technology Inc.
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|   Model LVTTL_12mA_SLEW-ON_GPIO_O
[Model]   LVTTL_12mA_SLEW-ON_GPIO_O
Model_type   Output
Polarity   Non-Inverting
Enable   Active-High
Vmeas =   1.65
Cref =   5p
Rref =   1M
|   typ   min   max
C_comp_pullup   2.605e-12   2.605e-12   2.76e-12
C_comp_pulldown  2.605e-12   2.605e-12   2.76e-12
[Temperature Range]  25C   125C   -55C
[Voltage Range]  3.3   3.135   3.465
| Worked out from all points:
|   slope of the pulldown table from 0 to 0.495 V, typ, clamps not added: 22.7 ohm
|   slope of the pullup table from 0 to 0.495 V, typ, clamps not added: 29.5 ohm
|   GND clamp passes 1 mA (typ) near -0.51 V on its own axis
|   POWER clamp passes 1 mA (typ) near -0.46 V on its own axis
|   rising waveform, R_fixture 50, V_fixture 0: 20-80 % time 293ps typ, 322ps min, 217ps max; typ from 0 V to 1.91 V
|   rising waveform, R_fixture 50, V_fixture 3.3: 20-80 % time 205ps typ, 244ps min, 153ps max; typ from 1.23 V to 3.3 V
|   falling waveform, R_fixture 50, V_fixture 0: 20-80 % time 195ps typ, 218ps min, 143ps max; typ from 1.91 V to 0 V
|   falling waveform, R_fixture 50, V_fixture 3.3: 20-80 % time 350ps typ, 384ps min, 255ps max; typ from 3.3 V to 1.23 V
[GND Clamp]
| Voltage   I(typ)   I(min)   I(max)
-3.3V     -3.213A    -2.953A    -3.676A
-1.191V   -450mA     -534.3mA   -393.2mA
-1.083V   -310.2mA   -411.6mA   -227.5mA
-974.5mV  -170.4mA   -288.9mA   -76.97mA
-866.2mV  -50.48mA   -166.3mA   -34.78mA
-758mV    -15.08mA   -54.7mA    -18.33mA
-649.7mV  -5.883mA   -9.683mA   -6.874mA
-541.4mV  -1.389mA   -1.864mA   -1.426mA
-324.8mV  -3.553uA   -16.68uA   -1.172uA
6.6V      0A         0A         0A
[POWER Clamp]
| Voltage   I(typ)   I(min)   I(max)
-3.3V     320.3mA    256.6mA    387.1mA
-1.624V   89.11mA    65.97mA    116.9mA
-1.408V   67.23mA    48.87mA    90.32mA
-1.299V   57.08mA    41.04mA    77.84mA
-1.191V   47.51mA    33.68mA    65.79mA
-1.083V   38.51mA    26.79mA    54.52mA
-866.2mV  22.14mA    14.9mA     33.75mA
-649.7mV  8.213mA    6.429mA    11.19mA
-541.4mV  2.791mA    3.18mA     3.642mA
-433.1mV  359.8uA    981.3uA    499.4uA
-216.6mV  159.8nA    8.88uA     59.07nA
6.6V      0A         0A         0A
[Pullup]
| Voltage   I(typ)   I(min)   I(max)
-3.3V     68.42mA    85.02mA    82.67mA
-2.057V   54.76mA    66mA       65.95mA
-1.191V   38.81mA    45.28mA    47.19mA
-649.7mV  24.23mA    27.51mA    31.21mA
618.8mV   -20.47mA   -22.34mA   -26.7mA
1.753V    -43.26mA   -46.67mA   -57.54mA
3.625V    -49.97mA   -53.87mA   -66.69mA
4.058V    -49.66mA   -42.65mA   -67.1mA
4.275V    -39.44mA   -42.86mA   -66.44mA
4.599V    -39.74mA   -43.19mA   -51.37mA
5.79V     -41.86mA   -45.38mA   -54.22mA
6.6V      -48.08mA   -52.01mA   -62.21mA
[Pulldown]
| Voltage   I(typ)   I(min)   I(max)
-3.3V     -13.44mA   -16.05mA   -15.36mA
-1.191V   -12.1mA    -13.8mA    -14.51mA
-1.083V   -11.99mA   -13.51mA   -16.51mA
-974.5mV  -13.34mA   -13.19mA   -39.74mA
-866.2mV  -27.94mA   -13.07mA   -49.44mA
-758mV    -33.94mA   -22.54mA   -46.94mA
-649.7mV  -31.06mA   -29.46mA   -43.03mA
515.6mV   22.6mA     21.8mA     32.41mA
1.341V    43mA       41.8mA     60.98mA
1.959V    47.03mA    46.07mA    65.66mA
5.141V    49.02mA    48.28mA    68.46mA
6.6V      54.17mA    53.41mA    76.16mA
[Ramp]
dV/dt_r   1.14513/0.293085n  1.14431/0.322193n  1.36379/0.216957n
dV/dt_f   1.2401/0.349781n  1.17517/0.384319n  1.51351/0.255478n
R_load = 50
[Rising Waveform]
R_fixture = 50
V_fixture = 0
V_fixture_min = 0
V_fixture_max = 0
| Time   V(typ)   V(min)   V(max)
0s        49.36nV    68.84nV    130.7nV
1.342ns   822.1uV    554.7uV    -40.16mV
1.645ns   -22.76mV   680uV      1.787V
1.798ns   56.13mV    743.2uV    2.109V
2.006ns   989.6mV    -390.7uV   2.226V
2.169ns   1.522V     -29.14mV   2.252V
2.318ns   1.735V     -12.72mV   2.261V
2.733ns   1.882V     1.446V     2.271V
3.147ns   1.904V     1.844V     2.273V
10ns      1.909V     1.907V     2.273V
[Rising Waveform]
R_fixture = 50
V_fixture = 3.3
V_fixture_min = 3.135
V_fixture_max = 3.465
| Time   V(typ)   V(min)   V(max)
0s        1.233V     1.176V     942.5mV
1.258ns   1.233V     1.176V     953.9mV
1.507ns   1.225V     1.176V     3.065V
1.657ns   1.365V     1.176V     3.358V
1.836ns   2.564V     1.176V     3.434V
1.954ns   3.021V     1.167V     3.449V
2.125ns   3.215V     1.24V      3.459V
2.474ns   3.287V     2.811V     3.464V
2.806ns   3.297V     3.094V     3.465V
10ns      3.3V       3.135V     3.465V
[Falling Waveform]
R_fixture = 50
V_fixture = 0
V_fixture_min = 0
V_fixture_max = 0
| Time   V(typ)   V(min)   V(max)
0s        1.909V     1.907V     2.273V
1.282ns   1.909V     1.907V     2.26V
1.376ns   1.909V     1.907V     1.812V
1.539ns   1.912V     1.907V     330.1mV
1.789ns   1.345V     1.907V     26.02mV
2.063ns   118.5mV    1.915V     5.113mV
2.254ns   30.05mV    1.761V     2.026mV
2.582ns   4.959mV    228.5mV    671uV
2.799ns   2.002mV    41.98mV    651.4uV
10ns      602.2nV    2.1uV      -46.19nV
[Falling Waveform]
R_fixture = 50
V_fixture = 3.3
V_fixture_min = 3.135
V_fixture_max = 3.465
| Time   V(typ)   V(min)   V(max)
0s        3.3V       3.135V     3.465V
1.378ns   3.299V     3.134V     3.503V
1.445ns   3.299V     3.134V     3.303V
1.784ns   3.338V     3.134V     1.335V
1.876ns   3.179V     3.134V     1.143V
2.091ns   2.27V      3.133V     989.2mV
2.456ns   1.408V     3.003V     949.8mV
2.842ns   1.262V     1.733V     943.6mV
3.284ns   1.238V     1.246V     942.6mV
10ns      1.233V     1.176V     942.5mV
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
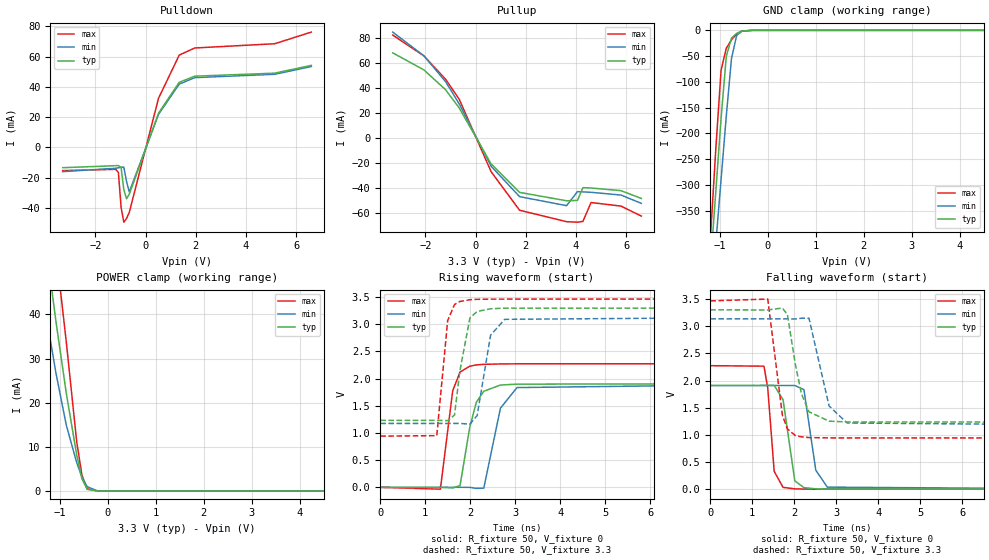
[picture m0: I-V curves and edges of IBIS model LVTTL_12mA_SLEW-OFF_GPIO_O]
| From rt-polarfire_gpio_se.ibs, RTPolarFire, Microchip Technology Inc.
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|   Model LVTTL_12mA_SLEW-OFF_GPIO_O
[Model]   LVTTL_12mA_SLEW-OFF_GPIO_O
Model_type   Output
Polarity   Non-Inverting
Enable   Active-High
Vmeas =   1.65
Cref =   5p
Rref =   1M
|   typ   min   max
C_comp_pullup   2.605e-12   2.605e-12   2.76e-12
C_comp_pulldown  2.605e-12   2.605e-12   2.76e-12
[Temperature Range]  25C   125C   -55C
[Voltage Range]  3.3   3.135   3.465
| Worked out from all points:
|   slope of the pulldown table from 0 to 0.495 V, typ, clamps not added: 22.7 ohm
|   slope of the pullup table from 0 to 0.495 V, typ, clamps not added: 29.5 ohm
|   GND clamp passes 1 mA (typ) near -0.51 V on its own axis
|   POWER clamp passes 1 mA (typ) near -0.46 V on its own axis
|   rising waveform, R_fixture 50, V_fixture 0: 20-80 % time 270ps typ, 289ps min, 203ps max; typ from 0 V to 1.91 V
|   rising waveform, R_fixture 50, V_fixture 3.3: 20-80 % time 189ps typ, 228ps min, 141ps max; typ from 1.23 V to 3.3 V
|   falling waveform, R_fixture 50, V_fixture 0: 20-80 % time 173ps typ, 195ps min, 127ps max; typ from 1.91 V to 0 V
|   falling waveform, R_fixture 50, V_fixture 3.3: 20-80 % time 308ps typ, 328ps min, 226ps max; typ from 3.3 V to 1.23 V
[GND Clamp]
| Voltage   I(typ)   I(min)   I(max)
-3.3V     -3.213A    -2.953A    -3.676A
-1.191V   -450mA     -534.3mA   -393.2mA
-1.083V   -310.2mA   -411.6mA   -227.5mA
-974.5mV  -170.4mA   -288.9mA   -76.97mA
-866.2mV  -50.48mA   -166.3mA   -34.78mA
-758mV    -15.08mA   -54.7mA    -18.33mA
-649.7mV  -5.883mA   -9.683mA   -6.874mA
-541.4mV  -1.389mA   -1.864mA   -1.426mA
-324.8mV  -3.553uA   -16.68uA   -1.172uA
6.6V      0A         0A         0A
[POWER Clamp]
| Voltage   I(typ)   I(min)   I(max)
-3.3V     320.3mA    256.6mA    387.1mA
-1.624V   89.11mA    65.97mA    116.9mA
-1.408V   67.23mA    48.87mA    90.32mA
-1.299V   57.08mA    41.04mA    77.84mA
-1.191V   47.51mA    33.68mA    65.79mA
-1.083V   38.51mA    26.79mA    54.52mA
-866.2mV  22.14mA    14.9mA     33.75mA
-649.7mV  8.213mA    6.429mA    11.19mA
-541.4mV  2.791mA    3.18mA     3.642mA
-433.1mV  359.8uA    981.3uA    499.4uA
-216.6mV  159.8nA    8.88uA     59.07nA
6.6V      0A         0A         0A
[Pullup]
| Voltage   I(typ)   I(min)   I(max)
-3.3V     68.42mA    85.02mA    82.67mA
-2.057V   54.76mA    66mA       65.95mA
-1.191V   38.81mA    45.28mA    47.19mA
-649.7mV  24.23mA    27.51mA    31.21mA
618.8mV   -20.47mA   -22.34mA   -26.7mA
1.753V    -43.26mA   -46.67mA   -57.54mA
3.625V    -49.97mA   -53.87mA   -66.69mA
4.058V    -49.66mA   -42.65mA   -67.1mA
4.275V    -39.44mA   -42.86mA   -66.44mA
4.599V    -39.74mA   -43.19mA   -51.37mA
5.79V     -41.86mA   -45.38mA   -54.22mA
6.6V      -48.08mA   -52.01mA   -62.21mA
[Pulldown]
| Voltage   I(typ)   I(min)   I(max)
-3.3V     -13.44mA   -16.05mA   -15.36mA
-1.191V   -12.1mA    -13.8mA    -14.51mA
-1.083V   -11.99mA   -13.51mA   -16.51mA
-974.5mV  -13.34mA   -13.19mA   -39.74mA
-866.2mV  -27.94mA   -13.07mA   -49.44mA
-758mV    -33.94mA   -22.54mA   -46.94mA
-649.7mV  -31.06mA   -29.46mA   -43.03mA
515.6mV   22.6mA     21.8mA     32.41mA
1.341V    43mA       41.8mA     60.98mA
1.959V    47.03mA    46.07mA    65.66mA
5.141V    49.02mA    48.28mA    68.46mA
6.6V      54.17mA    53.41mA    76.16mA
[Ramp]
dV/dt_r   1.14514/0.269635n  1.14431/0.289013n  1.36378/0.202975n
dV/dt_f   1.2401/0.307596n  1.17517/0.3281n  1.51351/0.226016n
R_load = 50
[Rising Waveform]
R_fixture = 50
V_fixture = 0
V_fixture_min = 0
V_fixture_max = 0
| Time   V(typ)   V(min)   V(max)
0s        49.37nV    68.85nV    130.7nV
1.335ns   726.1uV    657.7uV    -33.53mV
1.609ns   -10.41mV   792.7uV    1.778V
1.772ns   33.39mV    873uV      2.121V
1.986ns   1.1V       254.4uV    2.229V
2.133ns   1.565V     -19.42mV   2.253V
2.299ns   1.768V     -14.45mV   2.264V
2.669ns   1.883V     1.457V     2.271V
3.037ns   1.899V     1.836V     2.273V
10ns      1.909V     1.907V     2.273V
[Rising Waveform]
R_fixture = 50
V_fixture = 3.3
V_fixture_min = 3.135
V_fixture_max = 3.465
| Time   V(typ)   V(min)   V(max)
0s        1.233V     1.176V     942.5mV
1.255ns   1.233V     1.176V     951.4mV
1.497ns   1.228V     1.176V     3.071V
1.649ns   1.33V      1.176V     3.365V
1.766ns   2.132V     1.176V     3.42V
1.991ns   3.118V     1.164V     3.453V
2.151ns   3.237V     1.321V     3.46V
2.451ns   3.287V     2.802V     3.464V
2.765ns   3.297V     3.092V     3.464V
10ns      3.3V       3.135V     3.465V
[Falling Waveform]
R_fixture = 50
V_fixture = 0
V_fixture_min = 0
V_fixture_max = 0
| Time   V(typ)   V(min)   V(max)
0s        1.909V     1.907V     2.273V
1.277ns   1.909V     1.908V     2.264V
1.366ns   1.909V     1.908V     1.871V
1.52ns    1.91V      1.908V     328.3mV
1.731ns   1.648V     1.908V     32.86mV
2.011ns   153.1mV    1.908V     6.246mV
2.228ns   28.49mV    1.832V     1.883mV
2.51ns    6.193mV    350.6mV    599.3uV
2.783ns   1.912mV    37.27mV    577.5uV
10ns      103.8nV    3.461uV    30.82nV
[Falling Waveform]
R_fixture = 50
V_fixture = 3.3
V_fixture_min = 3.135
V_fixture_max = 3.465
| Time   V(typ)   V(min)   V(max)
0s        3.3V       3.135V     3.465V
1.368ns   3.299V     3.135V     3.499V
1.715ns   3.334V     3.134V     1.362V
1.835ns   3.213V     3.134V     1.109V
2.023ns   2.301V     3.133V     986.7mV
2.168ns   1.759V     3.146V     963.6mV
2.348ns   1.424V     3.146V     950.1mV
2.826ns   1.252V     1.532V     943.4mV
3.253ns   1.237V     1.218V     942.7mV
10ns      1.233V     1.176V     942.5mV
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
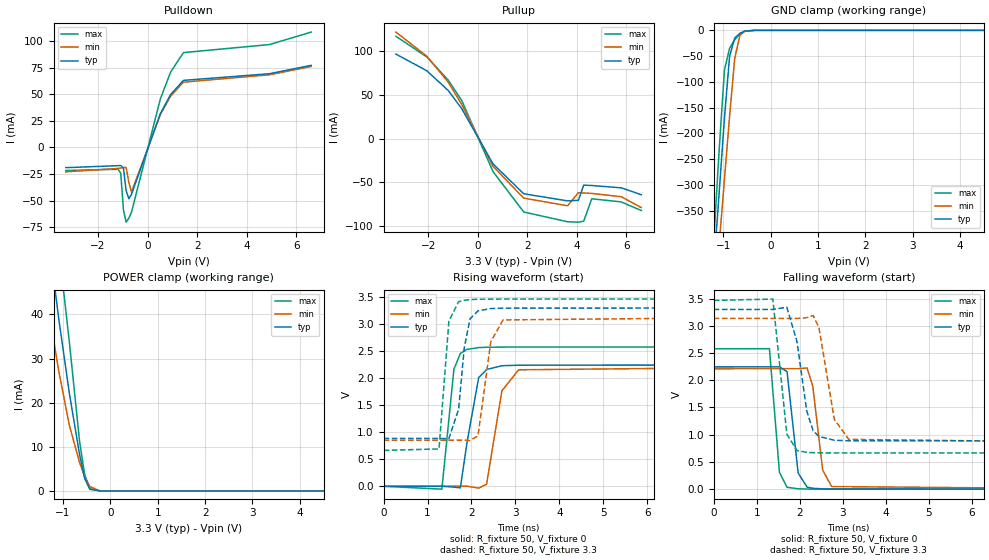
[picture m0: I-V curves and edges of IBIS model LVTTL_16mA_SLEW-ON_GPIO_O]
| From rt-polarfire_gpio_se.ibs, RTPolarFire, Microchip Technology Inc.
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|   Model LVTTL_16mA_SLEW-ON_GPIO_O
[Model]   LVTTL_16mA_SLEW-ON_GPIO_O
Model_type   Output
Polarity   Non-Inverting
Enable   Active-High
Vmeas =   1.65
Cref =   5p
Rref =   1M
|   typ   min   max
C_comp_pullup   2.605e-12   2.605e-12   2.76e-12
C_comp_pulldown  2.605e-12   2.605e-12   2.76e-12
[Temperature Range]  25C   125C   -55C
[Voltage Range]  3.3   3.135   3.465
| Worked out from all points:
|   slope of the pulldown table from 0 to 0.495 V, typ, clamps not added: 16 ohm
|   slope of the pullup table from 0 to 0.495 V, typ, clamps not added: 20.7 ohm
|   GND clamp passes 1 mA (typ) near -0.51 V on its own axis
|   POWER clamp passes 1 mA (typ) near -0.46 V on its own axis
|   rising waveform, R_fixture 50, V_fixture 0: 20-80 % time 230ps typ, 258ps min, 166ps max; typ from 0 V to 2.25 V
|   rising waveform, R_fixture 50, V_fixture 3.3: 20-80 % time 178ps typ, 219ps min, 128ps max; typ from 0.886 V to 3.3 V
|   falling waveform, R_fixture 50, V_fixture 0: 20-80 % time 161ps typ, 189ps min, 118ps max; typ from 2.25 V to 0 V
|   falling waveform, R_fixture 50, V_fixture 3.3: 20-80 % time 266ps typ, 289ps min, 188ps max; typ from 3.3 V to 0.886 V
[GND Clamp]
| Voltage   I(typ)   I(min)   I(max)
-3.3V     -3.213A    -2.953A    -3.676A
-1.191V   -450mA     -534.3mA   -393.2mA
-1.083V   -310.2mA   -411.6mA   -227.5mA
-974.5mV  -170.4mA   -288.9mA   -76.97mA
-866.2mV  -50.48mA   -166.3mA   -34.78mA
-758mV    -15.08mA   -54.7mA    -18.33mA
-649.7mV  -5.883mA   -9.683mA   -6.874mA
-541.4mV  -1.389mA   -1.864mA   -1.426mA
-324.8mV  -3.553uA   -16.68uA   -1.172uA
6.6V      0A         0A         0A
[POWER Clamp]
| Voltage   I(typ)   I(min)   I(max)
-3.3V     320.3mA    256.6mA    387.1mA
-1.624V   89.11mA    65.97mA    116.9mA
-1.408V   67.23mA    48.87mA    90.32mA
-1.299V   57.08mA    41.04mA    77.84mA
-1.191V   47.51mA    33.68mA    65.79mA
-1.083V   38.51mA    26.79mA    54.52mA
-866.2mV  22.14mA    14.9mA     33.75mA
-649.7mV  8.213mA    6.429mA    11.19mA
-541.4mV  2.791mA    3.18mA     3.642mA
-433.1mV  359.8uA    981.3uA    499.4uA
-216.6mV  159.8nA    8.88uA     59.07nA
6.6V      0A         0A         0A
[Pullup]
| Voltage   I(typ)   I(min)   I(max)
-3.3V     96.7mA     121.9mA    117.1mA
-2.057V   77.69mA    94.34mA    93.54mA
-1.191V   55.09mA    64.6mA     66.93mA
-649.7mV  34.39mA    39.18mA    43.79mA
618.8mV   -29.1mA    -31.83mA   -37.93mA
1.856V    -63.18mA   -68.18mA   -84.08mA
3.625V    -71.34mA   -76.94mA   -95.22mA
4.058V    -70.72mA   -62mA      -95.73mA
4.275V    -53.34mA   -62.31mA   -94.51mA
4.599V    -53.73mA   -62.8mA    -68.94mA
5.79V     -56.41mA   -66.57mA   -72.51mA
6.6V      -64.26mA   -79.04mA   -82.43mA
[Pulldown]
| Voltage   I(typ)   I(min)   I(max)
-3.3V     -18.99mA   -22.92mA   -21.67mA
-1.191V   -17.09mA   -19.69mA   -20.45mA
-1.083V   -16.93mA   -19.27mA   -24.29mA
-974.5mV  -19.39mA   -18.82mA   -58.87mA
-866.2mV  -40.74mA   -18.76mA   -70.29mA
-758mV    -48.24mA   -32.79mA   -66.58mA
-649.7mV  -44.03mA   -41.99mA   -60.89mA
515.6mV   32.05mA    30.96mA    45.84mA
928.1mV   49.81mA    48.32mA    70.9mA
1.444V    63.16mA    61.48mA    89.29mA
4.924V    69.44mA    68.42mA    96.89mA
6.6V      77.31mA    76.24mA    108.6mA
[Ramp]
dV/dt_r   1.34716/0.230165n  1.32688/0.257736n  1.54626/0.165524n
dV/dt_f   1.44849/0.266104n  1.369/0.28897n  1.68016/0.187817n
R_load = 50
[Rising Waveform]
R_fixture = 50
V_fixture = 0
V_fixture_min = 0
V_fixture_max = 0
| Time   V(typ)   V(min)   V(max)
0s        37.81nV    52.78nV    98.13nV
1.326ns   914.1uV    549uV      -53.4mV
1.6ns     -15.29mV   662.4uV    2.168V
1.747ns   -29.4mV    723.3uV    2.458V
1.898ns   809.5mV    1.408mV    2.534V
2.164ns   2.01V      -33.05mV   2.567V
2.344ns   2.161V     37.58mV    2.573V
2.693ns   2.231V     1.767V     2.576V
3.074ns   2.241V     2.156V     2.577V
10ns      2.245V     2.211V     2.577V
[Rising Waveform]
R_fixture = 50
V_fixture = 3.3
V_fixture_min = 3.135
V_fixture_max = 3.465
| Time   V(typ)   V(min)   V(max)
0s        885.8mV    853.3mV    664.7mV
1.261ns   885.1mV    853.2mV    690.8mV
1.486ns   881.3mV    853.2mV    3.06V
1.707ns   1.425V     853.2mV    3.416V
1.836ns   2.567V     853.2mV    3.443V
1.968ns   3.1V       845.7mV    3.455V
2.149ns   3.247V     934.8mV    3.462V
2.44ns    3.289V     2.676V     3.464V
2.719ns   3.297V     3.079V     3.465V
10ns      3.3V       3.135V     3.465V
[Falling Waveform]
R_fixture = 50
V_fixture = 0
V_fixture_min = 0
V_fixture_max = 0
| Time   V(typ)   V(min)   V(max)
0s        2.245V     2.211V     2.577V
1.295ns   2.246V     2.212V     2.579V
1.528ns   2.246V     2.212V     307.7mV
1.705ns   2.158V     2.212V     34.51mV
1.963ns   297.2mV    2.212V     6.953mV
2.171ns   37.63mV    2.225V     2.28mV
2.304ns   17.04mV    1.889V     1.028mV
2.534ns   5.095mV    351mV      363.9uV
2.742ns   1.766mV    48.16mV    309.6uV
10ns      495.6nV    2.981uV    -50.28nV
[Falling Waveform]
R_fixture = 50
V_fixture = 3.3
V_fixture_min = 3.135
V_fixture_max = 3.465
| Time   V(typ)   V(min)   V(max)
0s        3.3V       3.135V     3.465V
1.374ns   3.299V     3.134V     3.49V
1.7ns     3.34V      3.134V     1.012V
1.936ns   2.71V      3.134V     708.9mV
2.162ns   1.44V      3.148V     676.2mV
2.311ns   1.072V     3.19V      670mV
2.446ns   967.4mV    2.972V     667.1mV
2.804ns   898.9mV    1.284V     665.4mV
3.141ns   888.2mV    914.1mV    665.4mV
10ns      885.8mV    853.3mV    664.7mV
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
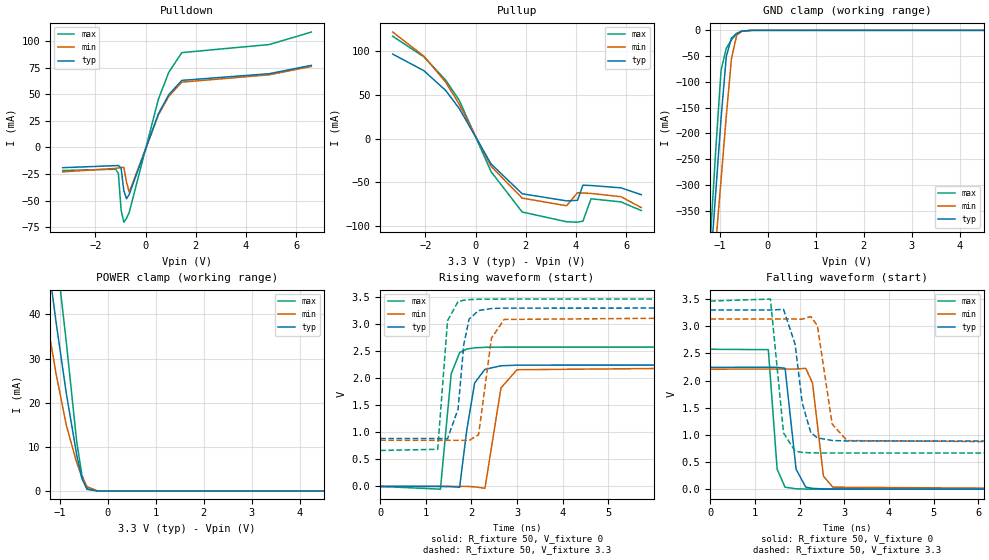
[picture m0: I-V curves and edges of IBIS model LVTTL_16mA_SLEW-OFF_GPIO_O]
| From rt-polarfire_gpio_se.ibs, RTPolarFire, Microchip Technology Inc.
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|   Model LVTTL_16mA_SLEW-OFF_GPIO_O
[Model]   LVTTL_16mA_SLEW-OFF_GPIO_O
Model_type   Output
Polarity   Non-Inverting
Enable   Active-High
Vmeas =   1.65
Cref =   5p
Rref =   1M
|   typ   min   max
C_comp_pullup   2.605e-12   2.605e-12   2.76e-12
C_comp_pulldown  2.605e-12   2.605e-12   2.76e-12
[Temperature Range]  25C   125C   -55C
[Voltage Range]  3.3   3.135   3.465
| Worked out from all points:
|   slope of the pulldown table from 0 to 0.495 V, typ, clamps not added: 16 ohm
|   slope of the pullup table from 0 to 0.495 V, typ, clamps not added: 20.7 ohm
|   GND clamp passes 1 mA (typ) near -0.51 V on its own axis
|   POWER clamp passes 1 mA (typ) near -0.46 V on its own axis
|   rising waveform, R_fixture 50, V_fixture 0: 20-80 % time 208ps typ, 229ps min, 152ps max; typ from 0 V to 2.25 V
|   rising waveform, R_fixture 50, V_fixture 3.3: 20-80 % time 164ps typ, 202ps min, 118ps max; typ from 0.886 V to 3.3 V
|   falling waveform, R_fixture 50, V_fixture 0: 20-80 % time 144ps typ, 164ps min, 105ps max; typ from 2.25 V to 0 V
|   falling waveform, R_fixture 50, V_fixture 3.3: 20-80 % time 230ps typ, 238ps min, 164ps max; typ from 3.3 V to 0.886 V
[GND Clamp]
| Voltage   I(typ)   I(min)   I(max)
-3.3V     -3.213A    -2.953A    -3.676A
-1.191V   -450mA     -534.3mA   -393.2mA
-1.083V   -310.2mA   -411.6mA   -227.5mA
-974.5mV  -170.4mA   -288.9mA   -76.97mA
-866.2mV  -50.48mA   -166.3mA   -34.78mA
-758mV    -15.08mA   -54.7mA    -18.33mA
-649.7mV  -5.883mA   -9.683mA   -6.874mA
-541.4mV  -1.389mA   -1.864mA   -1.426mA
-324.8mV  -3.553uA   -16.68uA   -1.172uA
6.6V      0A         0A         0A
[POWER Clamp]
| Voltage   I(typ)   I(min)   I(max)
-3.3V     320.3mA    256.6mA    387.1mA
-1.624V   89.11mA    65.97mA    116.9mA
-1.408V   67.23mA    48.87mA    90.32mA
-1.299V   57.08mA    41.04mA    77.84mA
-1.191V   47.51mA    33.68mA    65.79mA
-1.083V   38.51mA    26.79mA    54.52mA
-866.2mV  22.14mA    14.9mA     33.75mA
-649.7mV  8.213mA    6.429mA    11.19mA
-541.4mV  2.791mA    3.18mA     3.642mA
-433.1mV  359.8uA    981.3uA    499.4uA
-216.6mV  159.8nA    8.88uA     59.07nA
6.6V      0A         0A         0A
[Pullup]
| Voltage   I(typ)   I(min)   I(max)
-3.3V     96.7mA     121.9mA    117.1mA
-2.057V   77.69mA    94.34mA    93.54mA
-1.191V   55.09mA    64.6mA     66.93mA
-649.7mV  34.39mA    39.18mA    43.79mA
618.8mV   -29.1mA    -31.83mA   -37.93mA
1.856V    -63.18mA   -68.18mA   -84.08mA
3.625V    -71.34mA   -76.94mA   -95.22mA
4.058V    -70.72mA   -62mA      -95.73mA
4.275V    -53.34mA   -62.31mA   -94.51mA
4.599V    -53.73mA   -62.8mA    -68.94mA
5.79V     -56.41mA   -66.57mA   -72.51mA
6.6V      -64.26mA   -79.04mA   -82.43mA
[Pulldown]
| Voltage   I(typ)   I(min)   I(max)
-3.3V     -18.99mA   -22.92mA   -21.67mA
-1.191V   -17.09mA   -19.69mA   -20.45mA
-1.083V   -16.93mA   -19.27mA   -24.29mA
-974.5mV  -19.39mA   -18.82mA   -58.87mA
-866.2mV  -40.74mA   -18.76mA   -70.29mA
-758mV    -48.24mA   -32.79mA   -66.58mA
-649.7mV  -44.03mA   -41.99mA   -60.89mA
515.6mV   32.05mA    30.96mA    45.84mA
928.1mV   49.81mA    48.32mA    70.9mA
1.444V    63.16mA    61.48mA    89.29mA
4.924V    69.44mA    68.42mA    96.89mA
6.6V      77.31mA    76.24mA    108.6mA
[Ramp]
dV/dt_r   1.34716/0.207758n  1.32689/0.228954n  1.54626/0.152075n
dV/dt_f   1.44849/0.23043n  1.36901/0.238458n  1.68015/0.16379n
R_load = 50
[Rising Waveform]
R_fixture = 50
V_fixture = 0
V_fixture_min = 0
V_fixture_max = 0
| Time   V(typ)   V(min)   V(max)
0s        37.81nV    52.79nV    98.12nV
1.319ns   832uV      496.2uV    -50.72mV
1.555ns   -4.605mV   584.9uV    2.083V
1.74ns    -15.44mV   654.5uV    2.476V
1.896ns   1.037V     1.185mV    2.541V
2.069ns   1.914V     -8.314mV   2.563V
2.295ns   2.165V     -33.6mV    2.573V
2.646ns   2.231V     1.822V     2.576V
2.998ns   2.243V     2.158V     2.577V
10ns      2.245V     2.211V     2.577V
[Rising Waveform]
R_fixture = 50
V_fixture = 3.3
V_fixture_min = 3.135
V_fixture_max = 3.465
| Time   V(typ)   V(min)   V(max)
0s        885.8mV    853.3mV    664.7mV
1.259ns   885.3mV    853.2mV    686.9mV
1.475ns   883mV      853.2mV    3.065V
1.706ns   1.431V     853.1mV    3.42V
1.831ns   2.62V      853.1mV    3.444V
1.947ns   3.094V     849.6mV    3.455V
2.155ns   3.253V     955.9mV    3.462V
2.439ns   3.29V      2.744V     3.464V
2.717ns   3.297V     3.088V     3.465V
10ns      3.3V       3.135V     3.465V
[Falling Waveform]
R_fixture = 50
V_fixture = 0
V_fixture_min = 0
V_fixture_max = 0
| Time   V(typ)   V(min)   V(max)
0s        2.245V     2.211V     2.577V
1.3ns     2.246V     2.212V     2.57V
1.497ns   2.246V     2.212V     369.2mV
1.675ns   2.227V     2.212V     35.91mV
1.922ns   366.7mV    2.212V     7.155mV
2.137ns   38.29mV    2.227V     2.216mV
2.289ns   15.15mV    1.956V     919.4uV
2.534ns   4.367mV    240.5mV    833.1uV
2.745ns   1.654mV    35.82mV    809.6uV
10ns      69.69nV    2.667uV    66.36nV
[Falling Waveform]
R_fixture = 50
V_fixture = 3.3
V_fixture_min = 3.135
V_fixture_max = 3.465
| Time   V(typ)   V(min)   V(max)
0s        3.3V       3.135V     3.465V
1.347ns   3.3V       3.135V     3.502V
1.64ns    3.312V     3.135V     1.037V
1.899ns   2.671V     3.134V     699.9mV
2.06ns    1.585V     3.132V     678mV
2.251ns   1.041V     3.181V     669.4mV
2.4ns     945mV      3.008V     667.1mV
2.73ns    896.2mV    1.198V     665.7mV
3.062ns   888.5mV    894.8mV    665.7mV
10ns      885.9mV    853.3mV    664.7mV
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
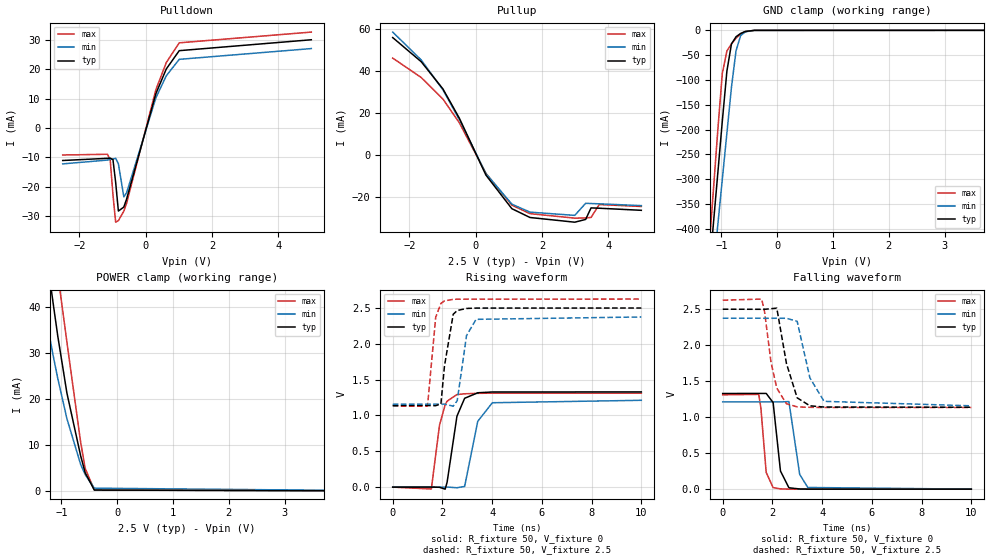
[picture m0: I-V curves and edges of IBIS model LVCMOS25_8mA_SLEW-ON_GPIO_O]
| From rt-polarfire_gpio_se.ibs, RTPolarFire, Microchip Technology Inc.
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|   Model LVCMOS25_8mA_SLEW-ON_GPIO_O
[Model]   LVCMOS25_8mA_SLEW-ON_GPIO_O
Model_type   Output
Polarity   Non-Inverting
Enable   Active-High
Vmeas =   1.25
Cref =   5p
Rref =   1M
|   typ   min   max
C_comp_pullup   2.605e-12   2.605e-12   2.76e-12
C_comp_pulldown  2.605e-12   2.605e-12   2.76e-12
[Temperature Range]  25C   125C   -55C
[Voltage Range]  2.5   2.375   2.625
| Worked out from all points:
|   slope of the pulldown table from 0 to 0.375 V, typ, clamps not added: 27.6 ohm
|   slope of the pullup table from 0 to 0.375 V, typ, clamps not added: 33.1 ohm
|   GND clamp passes 1 mA (typ) near -0.51 V on its own axis
|   POWER clamp passes 1 mA (typ) near -0.47 V on its own axis
|   rising waveform, R_fixture 50, V_fixture 0: 20-80 % time 368ps typ, 440ps min, 327ps max; typ from 0 V to 1.33 V
|   rising waveform, R_fixture 50, V_fixture 2.5: 20-80 % time 252ps typ, 308ps min, 214ps max; typ from 1.14 V to 2.5 V
|   falling waveform, R_fixture 50, V_fixture 0: 20-80 % time 243ps typ, 276ps min, 184ps max; typ from 1.33 V to 0 V
|   falling waveform, R_fixture 50, V_fixture 2.5: 20-80 % time 455ps typ, 538ps min, 414ps max; typ from 2.5 V to 1.14 V
[GND Clamp]
| Voltage   I(typ)   I(min)   I(max)
-2.5V     -2.154A    -2.028A    -2.413A
-1.23V    -500.9mA   -578.9mA   -453.4mA
-1.148V   -394.9mA   -486mA     -327.9mA
-1.066V   -289mA     -393mA     -202.4mA
-984.4mV  -183.1mA   -300.1mA   -86.85mA
-902.3mV  -82.21mA   -207.2mA   -41.59mA
-820.3mV  -27.37mA   -114.5mA   -27.29mA
-738.3mV  -12.87mA   -40.96mA   -15.82mA
-656.2mV  -6.285mA   -10.74mA   -7.396mA
-574.2mV  -2.342mA   -3.102mA   -2.493mA
-410.2mV  -62.85uA   -143.8uA   -47.39uA
5V        0A         0A         0A
[POWER Clamp]
| Voltage   I(typ)   I(min)   I(max)
-2.5V     191.3mA    149.5mA    238.1mA
-1.559V   79.6mA     58.4mA     105.4mA
-1.395V   63.37mA    46mA       85.27mA
-1.312V   55.59mA    40.21mA    75.31mA
-1.23V    48.04mA    34.68mA    65.5mA
-1.148V   40.77mA    29.43mA    56.09mA
-1.066V   33.71mA    24.49mA    47.24mA
-902.3mV  21.31mA    15.73mA    32.4mA
-656.2mV  7.665mA    5.781mA    10.63mA
-574.2mV  3.929mA    3.551mA    4.901mA
-410.2mV  189.8uA    599.4uA    178.9uA
5V        0A         0A         0A
[Pullup]
| Voltage   I(typ)   I(min)   I(max)
-2.5V     55.91mA    58.52mA    46.13mA
-1.641V   44.41mA    45.26mA    36.88mA
-984.4mV  31.41mA    31mA       26.59mA
-492.2mV  17.56mA    16.84mA    15.36mA
312.5mV   -9.641mA   -8.923mA   -8.839mA
1.094V    -25.65mA   -23.49mA   -23.96mA
1.641V    -29.85mA   -27.3mA    -28.02mA
2.992V    -32.09mA   -28.84mA   -30.16mA
3.32V     -30.78mA   -23.1mA    -30.06mA
3.484V    -25.28mA   -23.19mA   -29.82mA
3.73V     -25.43mA   -23.33mA   -23.68mA
5V        -26.43mA   -24.2mA    -24.6mA
[Pulldown]
| Voltage   I(typ)   I(min)   I(max)
-2.5V     -11.02mA   -12.17mA   -9.146mA
-1.148V   -10.28mA   -10.87mA   -8.91mA
-1.066V   -10.22mA   -10.69mA   -10.98mA
-984.4mV  -10.71mA   -10.5mA    -22.57mA
-902.3mV  -18.47mA   -10.29mA   -31.94mA
-820.3mV  -28.16mA   -12.12mA   -31.42mA
-656.2mV  -26.81mA   -23.34mA   -28.17mA
-574.2mV  -24.16mA   -22.01mA   -25.59mA
312.5mV   11.69mA    10.29mA    13.04mA
625mV     20.03mA    17.72mA    22.21mA
1.016V    26.23mA    23.29mA    28.89mA
5V        29.93mA    26.94mA    32.53mA
[Ramp]
dV/dt_r   0.797444/0.367991n  0.727439/0.43974n  0.786886/0.326725n
dV/dt_f   0.81699/0.454794n  0.730232/0.538366n  0.894846/0.414257n
R_load = 50
[Rising Waveform]
R_fixture = 50
V_fixture = 0
V_fixture_min = 0
V_fixture_max = 0
| Time   V(typ)   V(min)   V(max)
0s        15.23nV    65.48nV    18.54nV
1.554ns   678.2uV    642.3uV    -25.66mV
1.883ns   -2.121mV   778.3uV    865.9mV
2.11ns    -28.39mV   872.1uV    1.15V
2.189ns   70.21mV    904.8uV    1.2V
2.584ns   990.5mV    -8.753mV   1.292V
2.893ns   1.24V      9.588mV    1.303V
3.42ns    1.317V     918.1mV    1.309V
4.008ns   1.328V     1.178V     1.312V
10ns      1.329V     1.212V     1.311V
[Rising Waveform]
R_fixture = 50
V_fixture = 2.5
V_fixture_min = 2.375
V_fixture_max = 2.625
| Time   V(typ)   V(min)   V(max)
0s        1.138V     1.158V     1.134V
1.4ns     1.139V     1.158V     1.133V
1.73ns    1.137V     1.159V     2.372V
1.939ns   1.161V     1.159V     2.563V
2.082ns   1.691V     1.159V     2.6V
2.434ns   2.413V     1.13V      2.621V
2.596ns   2.465V     1.207V     2.623V
2.97ns    2.494V     2.116V     2.624V
3.355ns   2.499V     2.342V     2.624V
10ns      2.5V       2.375V     2.625V
[Falling Waveform]
R_fixture = 50
V_fixture = 0
V_fixture_min = 0
V_fixture_max = 0
| Time   V(typ)   V(min)   V(max)
0s        1.329V     1.212V     1.311V
1.449ns   1.33V      1.212V     1.317V
1.535ns   1.33V      1.212V     1.13V
1.749ns   1.33V      1.212V     232.8mV
2.028ns   1.203V     1.212V     21.13mV
2.323ns   252.6mV    1.212V     3.904mV
2.663ns   19.41mV    1.217V     643uV
3.097ns   2.78mV     204.9mV    499.3uV
3.422ns   785.1uV    23.52mV    475.8uV
10ns      1.624uV    3.067uV    698.2nV
[Falling Waveform]
R_fixture = 50
V_fixture = 2.5
V_fixture_min = 2.375
V_fixture_max = 2.625
| Time   V(typ)   V(min)   V(max)
0s        2.5V       2.375V     2.625V
1.568ns   2.499V     2.375V     2.641V
1.685ns   2.499V     2.374V     2.462V
1.943ns   2.507V     2.374V     1.762V
2.176ns   2.515V     2.374V     1.403V
2.564ns   1.746V     2.374V     1.187V
2.995ns   1.269V     2.332V     1.143V
3.507ns   1.158V     1.546V     1.137V
4.077ns   1.141V     1.22V      1.135V
10ns      1.138V     1.158V     1.134V
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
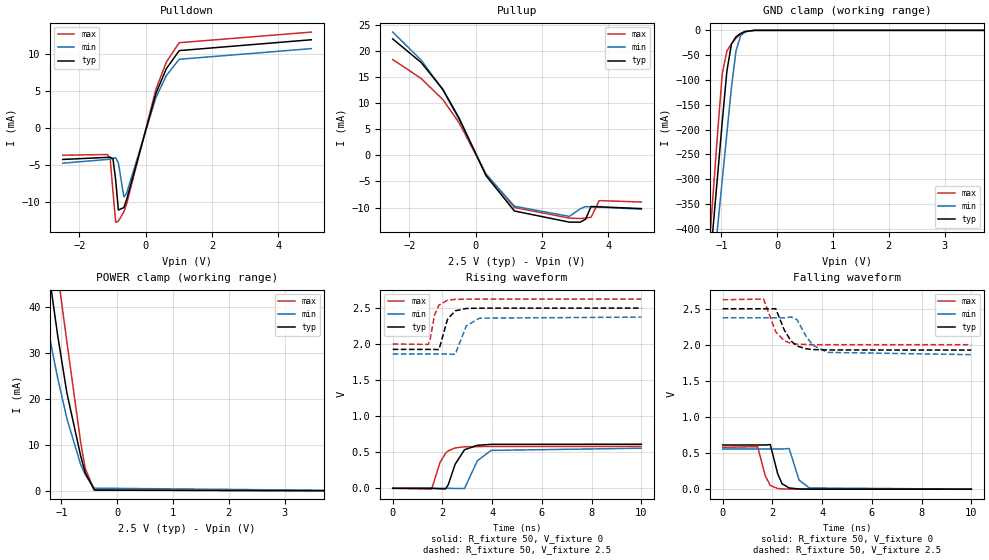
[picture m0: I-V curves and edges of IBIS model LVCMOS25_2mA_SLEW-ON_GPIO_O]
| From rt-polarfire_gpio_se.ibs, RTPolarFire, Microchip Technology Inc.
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|   Model LVCMOS25_2mA_SLEW-ON_GPIO_O
[Model]   LVCMOS25_2mA_SLEW-ON_GPIO_O
Model_type   Output
Polarity   Non-Inverting
Enable   Active-High
Vmeas =   1.25
Cref =   5p
Rref =   1M
|   typ   min   max
C_comp_pullup   2.605e-12   2.605e-12   2.76e-12
C_comp_pulldown  2.605e-12   2.605e-12   2.76e-12
[Temperature Range]  25C   125C   -55C
[Voltage Range]  2.5   2.375   2.625
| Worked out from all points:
|   slope of the pulldown table from 0 to 0.375 V, typ, clamps not added: 68.5 ohm
|   slope of the pullup table from 0 to 0.375 V, typ, clamps not added: 82.3 ohm
|   GND clamp passes 1 mA (typ) near -0.51 V on its own axis
|   POWER clamp passes 1 mA (typ) near -0.47 V on its own axis
|   rising waveform, R_fixture 50, V_fixture 0: 20-80 % time 443ps typ, 491ps min, 374ps max; typ from 0 V to 0.612 V
|   rising waveform, R_fixture 50, V_fixture 2.5: 20-80 % time 323ps typ, 369ps min, 252ps max; typ from 1.93 V to 2.5 V
|   falling waveform, R_fixture 50, V_fixture 0: 20-80 % time 270ps typ, 304ps min, 265ps max; typ from 0.612 V to 0 V
|   falling waveform, R_fixture 50, V_fixture 2.5: 20-80 % time 498ps typ, 611ps min, 436ps max; typ from 2.5 V to 1.93 V
[GND Clamp]
| Voltage   I(typ)   I(min)   I(max)
-2.5V     -2.154A    -2.028A    -2.413A
-1.23V    -500.9mA   -578.9mA   -453.4mA
-1.148V   -394.9mA   -486mA     -327.9mA
-1.066V   -289mA     -393mA     -202.4mA
-984.4mV  -183.1mA   -300.1mA   -86.85mA
-902.3mV  -82.21mA   -207.2mA   -41.59mA
-820.3mV  -27.37mA   -114.5mA   -27.29mA
-738.3mV  -12.87mA   -40.96mA   -15.82mA
-656.2mV  -6.285mA   -10.74mA   -7.396mA
-574.2mV  -2.342mA   -3.102mA   -2.493mA
-410.2mV  -62.85uA   -143.8uA   -47.39uA
5V        0A         0A         0A
[POWER Clamp]
| Voltage   I(typ)   I(min)   I(max)
-2.5V     191.3mA    149.5mA    238.1mA
-1.559V   79.6mA     58.4mA     105.4mA
-1.395V   63.37mA    46mA       85.27mA
-1.312V   55.59mA    40.21mA    75.31mA
-1.23V    48.04mA    34.68mA    65.5mA
-1.148V   40.77mA    29.43mA    56.09mA
-1.066V   33.71mA    24.49mA    47.24mA
-902.3mV  21.31mA    15.73mA    32.4mA
-656.2mV  7.665mA    5.781mA    10.63mA
-574.2mV  3.929mA    3.551mA    4.901mA
-410.2mV  189.8uA    599.4uA    178.9uA
5V        0A         0A         0A
[Pullup]
| Voltage   I(typ)   I(min)   I(max)
-2.5V     22.26mA    23.57mA    18.32mA
-1.641V   17.75mA    18.22mA    14.69mA
-984.4mV  12.59mA    12.48mA    10.63mA
-492.2mV  7.057mA    6.778mA    6.167mA
312.5mV   -3.874mA   -3.584mA   -3.572mA
1.172V    -10.66mA   -9.748mA   -9.981mA
2.828V    -12.79mA   -11.69mA   -12.02mA
3.156V    -12.8mA    -10.25mA   -12.1mA
3.32V     -12.22mA   -9.816mA   -12mA
3.484V    -9.804mA   -9.857mA   -11.86mA
3.73V     -9.86mA    -9.92mA    -8.668mA
5V        -10.2mA    -10.3mA    -8.938mA
[Pulldown]
| Voltage   I(typ)   I(min)   I(max)
-2.5V     -4.252mA   -4.758mA   -3.676mA
-1.148V   -3.97mA    -4.25mA    -3.583mA
-1.066V   -3.946mA   -4.182mA   -4.258mA
-984.4mV  -4.157mA   -4.108mA   -8.591mA
-902.3mV  -7.055mA   -4.027mA   -12.76mA
-820.3mV  -11.11mA   -4.713mA   -12.62mA
-656.2mV  -10.78mA   -9.317mA   -11.36mA
-574.2mV  -9.731mA   -8.852mA   -10.34mA
312.5mV   4.706mA    4.139mA    5.267mA
625mV     8.048mA    7.115mA    8.942mA
1.016V    10.51mA    9.332mA    11.58mA
5V        11.98mA    10.78mA    13.02mA
[Ramp]
dV/dt_r   0.367135/0.443285n  0.333758/0.491248n  0.348653/0.373674n
dV/dt_f   0.343513/0.497822n  0.306579/0.610953n  0.373865/0.435902n
R_load = 50
[Rising Waveform]
R_fixture = 50
V_fixture = 0
V_fixture_min = 0
V_fixture_max = 0
| Time   V(typ)   V(min)   V(max)
0s        25.93nV    108.4nV    32.28nV
1.566ns   854.9uV    -287.7uV   -11.93mV
1.902ns   -6.935mV   -349.5uV   358.1mV
2.129ns   -7.727mV   -391.2uV   488.2mV
2.237ns   51.19mV    -411uV     519.3mV
2.51ns    333.4mV    -2.294mV   559.9mV
2.888ns   534.9mV    -2.673mV   576.4mV
3.403ns   596.2mV    381.5mV    579.1mV
3.956ns   609.7mV    525.5mV    580mV
10ns      611.9mV    556.3mV    581.1mV
[Rising Waveform]
R_fixture = 50
V_fixture = 2.5
V_fixture_min = 2.375
V_fixture_max = 2.625
| Time   V(typ)   V(min)   V(max)
0s        1.927V     1.863V     2.002V
1.43ns    1.927V     1.863V     1.996V
1.503ns   1.927V     1.863V     2.062V
1.681ns   1.926V     1.863V     2.403V
1.862ns   1.924V     1.863V     2.542V
2.202ns   2.342V     1.863V     2.609V
2.513ns   2.462V     1.857V     2.621V
2.959ns   2.494V     2.252V     2.624V
3.488ns   2.499V     2.36V      2.625V
10ns      2.5V       2.375V     2.625V
[Falling Waveform]
R_fixture = 50
V_fixture = 0
V_fixture_min = 0
V_fixture_max = 0
| Time   V(typ)   V(min)   V(max)
0s        611.9mV    556.2mV    581.1mV
1.405ns   611.9mV    556.2mV    588mV
1.711ns   611.9mV    556.2mV    185.1mV
1.913ns   617.8mV    556.2mV    51.43mV
2.21ns    215.9mV    556.2mV    9.433mV
2.387ns   74.05mV    556.2mV    4.121mV
2.674ns   16.92mV    562.4mV    1.156mV
3.072ns   2.799mV    124.4mV    301uV
3.487ns   668uV      16.89mV    283uV
10ns      1.268uV    4.381uV    365.8nV
[Falling Waveform]
R_fixture = 50
V_fixture = 2.5
V_fixture_min = 2.375
V_fixture_max = 2.625
| Time   V(typ)   V(min)   V(max)
0s        2.5V       2.375V     2.625V
1.644ns   2.499V     2.375V     2.634V
2.133ns   2.5V       2.374V     2.18V
2.48ns    2.202V     2.374V     2.056V
2.746ns   2.054V     2.387V     2.02V
2.992ns   1.983V     2.348V     2.01V
3.359ns   1.945V     2.115V     2.005V
3.623ns   1.935V     1.995V     2.002V
4.218ns   1.929V     1.895V     2.002V
10ns      1.927V     1.864V     2.002V
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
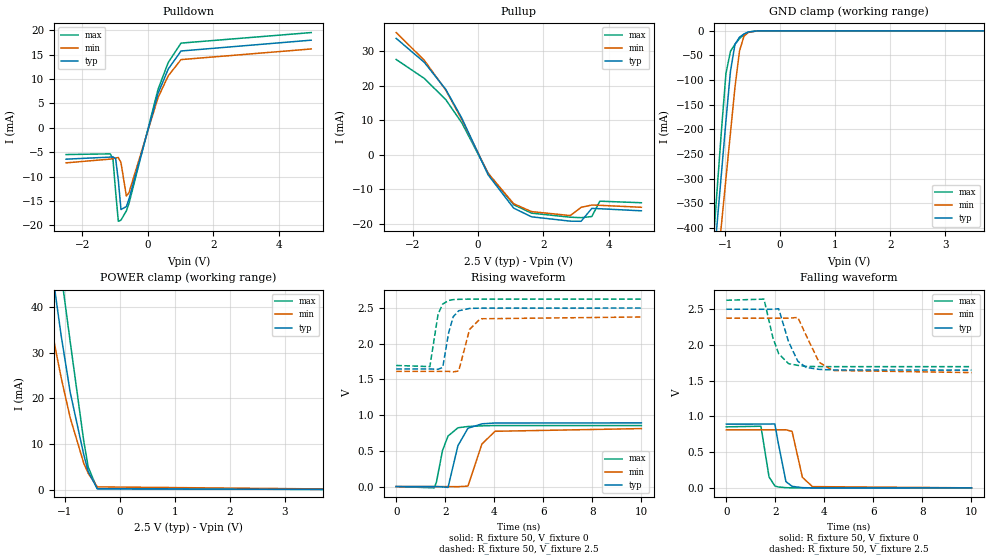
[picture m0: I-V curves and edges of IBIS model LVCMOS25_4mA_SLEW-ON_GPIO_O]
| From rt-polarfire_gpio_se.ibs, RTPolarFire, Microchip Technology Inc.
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|   Model LVCMOS25_4mA_SLEW-ON_GPIO_O
[Model]   LVCMOS25_4mA_SLEW-ON_GPIO_O
Model_type   Output
Polarity   Non-Inverting
Enable   Active-High
Vmeas =   1.25
Cref =   5p
Rref =   1M
|   typ   min   max
C_comp_pullup   2.605e-12   2.605e-12   2.76e-12
C_comp_pulldown  2.605e-12   2.605e-12   2.76e-12
[Temperature Range]  25C   125C   -55C
[Voltage Range]  2.5   2.375   2.625
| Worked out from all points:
|   slope of the pulldown table from 0 to 0.375 V, typ, clamps not added: 45.8 ohm
|   slope of the pullup table from 0 to 0.375 V, typ, clamps not added: 55 ohm
|   GND clamp passes 1 mA (typ) near -0.51 V on its own axis
|   POWER clamp passes 1 mA (typ) near -0.47 V on its own axis
|   rising waveform, R_fixture 50, V_fixture 0: 20-80 % time 419ps typ, 502ps min, 366ps max; typ from 0 V to 0.892 V
|   rising waveform, R_fixture 50, V_fixture 2.5: 20-80 % time 291ps typ, 353ps min, 255ps max; typ from 1.65 V to 2.5 V
|   falling waveform, R_fixture 50, V_fixture 0: 20-80 % time 250ps typ, 309ps min, 205ps max; typ from 0.892 V to 0 V
|   falling waveform, R_fixture 50, V_fixture 2.5: 20-80 % time 492ps typ, 606ps min, 430ps max; typ from 2.5 V to 1.65 V
[GND Clamp]
| Voltage   I(typ)   I(min)   I(max)
-2.5V     -2.154A    -2.028A    -2.413A
-1.23V    -500.9mA   -578.9mA   -453.4mA
-1.148V   -394.9mA   -486mA     -327.9mA
-1.066V   -289mA     -393mA     -202.4mA
-984.4mV  -183.1mA   -300.1mA   -86.85mA
-902.3mV  -82.21mA   -207.2mA   -41.59mA
-820.3mV  -27.37mA   -114.5mA   -27.29mA
-738.3mV  -12.87mA   -40.96mA   -15.82mA
-656.2mV  -6.285mA   -10.74mA   -7.396mA
-574.2mV  -2.342mA   -3.102mA   -2.493mA
-410.2mV  -62.85uA   -143.8uA   -47.39uA
5V        0A         0A         0A
[POWER Clamp]
| Voltage   I(typ)   I(min)   I(max)
-2.5V     191.3mA    149.5mA    238.1mA
-1.559V   79.6mA     58.4mA     105.4mA
-1.395V   63.37mA    46mA       85.27mA
-1.312V   55.59mA    40.21mA    75.31mA
-1.23V    48.04mA    34.68mA    65.5mA
-1.148V   40.77mA    29.43mA    56.09mA
-1.066V   33.71mA    24.49mA    47.24mA
-902.3mV  21.31mA    15.73mA    32.4mA
-656.2mV  7.665mA    5.781mA    10.63mA
-574.2mV  3.929mA    3.551mA    4.901mA
-410.2mV  189.8uA    599.4uA    178.9uA
5V        0A         0A         0A
[Pullup]
| Voltage   I(typ)   I(min)   I(max)
-2.5V     33.62mA    35.3mA     27.53mA
-1.641V   26.71mA    27.3mA     22.06mA
-984.4mV  18.9mA     18.7mA     15.94mA
-492.2mV  10.57mA    10.16mA    9.235mA
312.5mV   -5.798mA   -5.376mA   -5.337mA
1.094V    -15.4mA    -14.13mA   -14.41mA
1.641V    -17.91mA   -16.4mA    -16.85mA
2.828V    -19.16mA   -17.55mA   -18.02mA
3.156V    -19.2mA    -15.17mA   -18.15mA
3.484V    -15.48mA   -14.5mA    -17.82mA
3.73V     -15.57mA   -14.59mA   -13.39mA
5V        -16.17mA   -15.15mA   -13.84mA
[Pulldown]
| Voltage   I(typ)   I(min)   I(max)
-2.5V     -6.418mA   -7.171mA   -5.47mA
-1.148V   -5.991mA   -6.404mA   -5.329mA
-1.066V   -5.955mA   -6.302mA   -6.421mA
-984.4mV  -6.289mA   -6.19mA    -13.05mA
-902.3mV  -10.75mA   -6.068mA   -19.15mA
-820.3mV  -16.74mA   -7.131mA   -18.91mA
-656.2mV  -16.13mA   -13.98mA   -17mA
-574.2mV  -14.55mA   -13.25mA   -15.46mA
312.5mV   7.039mA    6.195mA    7.88mA
625mV     12.05mA    10.66mA    13.39mA
1.016V    15.75mA    13.99mA    17.37mA
5V        17.97mA    16.17mA    19.53mA
[Ramp]
dV/dt_r   0.535034/0.418696n  0.487047/0.502073n  0.512258/0.366468n
dV/dt_f   0.511775/0.492134n  0.457165/0.606083n  0.557426/0.429998n
R_load = 50
[Rising Waveform]
R_fixture = 50
V_fixture = 0
V_fixture_min = 0
V_fixture_max = 0
| Time   V(typ)   V(min)   V(max)
0s        21.03nV    89nV       25.85nV
1.554ns   -523uV     -481.6uV   -18.45mV
1.642ns   -552.6uV   -508.9uV   63.95mV
1.889ns   -5.074mV   -585.5uV   504.9mV
2.114ns   -12.18mV   -655.2uV   707.7mV
2.519ns   573.7mV    -2.18mV    823.2mV
2.926ns   816.2mV    6.673mV    841mV
3.496ns   878.5mV    596.4mV    850.1mV
4.032ns   889.9mV    773.9mV    854.5mV
10ns      891.7mV    811.7mV    853.8mV
[Rising Waveform]
R_fixture = 50
V_fixture = 2.5
V_fixture_min = 2.375
V_fixture_max = 2.625
| Time   V(typ)   V(min)   V(max)
0s        1.647V     1.613V     1.696V
1.373ns   1.647V     1.613V     1.68V
1.709ns   1.642V     1.613V     2.417V
1.897ns   1.669V     1.613V     2.556V
2.139ns   2.154V     1.613V     2.606V
2.327ns   2.379V     1.606V     2.618V
2.55ns    2.462V     1.619V     2.622V
2.995ns   2.495V     2.203V     2.625V
3.431ns   2.499V     2.35V      2.625V
10ns      2.5V       2.375V     2.625V
[Falling Waveform]
R_fixture = 50
V_fixture = 0
V_fixture_min = 0
V_fixture_max = 0
| Time   V(typ)   V(min)   V(max)
0s        891.7mV    811.7mV    853.8mV
1.411ns   892.4mV    811.7mV    862.4mV
1.742ns   892.6mV    811.7mV    152.6mV
1.979ns   895mV      811.7mV    28.11mV
2.106ns   649.3mV    811.7mV    12.89mV
2.431ns   87.39mV    813mV      2.767mV
2.682ns   21.12mV    789.7mV    695.8uV
3.103ns   2.77mV     147.7mV    18.75uV
3.511ns   299.6uV    17.58mV    17.67uV
10ns      985.3nV    5.3uV      528.9nV
[Falling Waveform]
R_fixture = 50
V_fixture = 2.5
V_fixture_min = 2.375
V_fixture_max = 2.625
| Time   V(typ)   V(min)   V(max)
0s        2.5V       2.375V     2.625V
1.537ns   2.499V     2.374V     2.641V
1.9ns     2.499V     2.374V     2.1V
2.134ns   2.507V     2.374V     1.878V
2.539ns   2.044V     2.374V     1.738V
2.915ns   1.772V     2.385V     1.714V
3.258ns   1.685V     2.131V     1.7V
3.784ns   1.658V     1.758V     1.697V
4.336ns   1.65V      1.643V     1.696V
10ns      1.647V     1.613V     1.696V
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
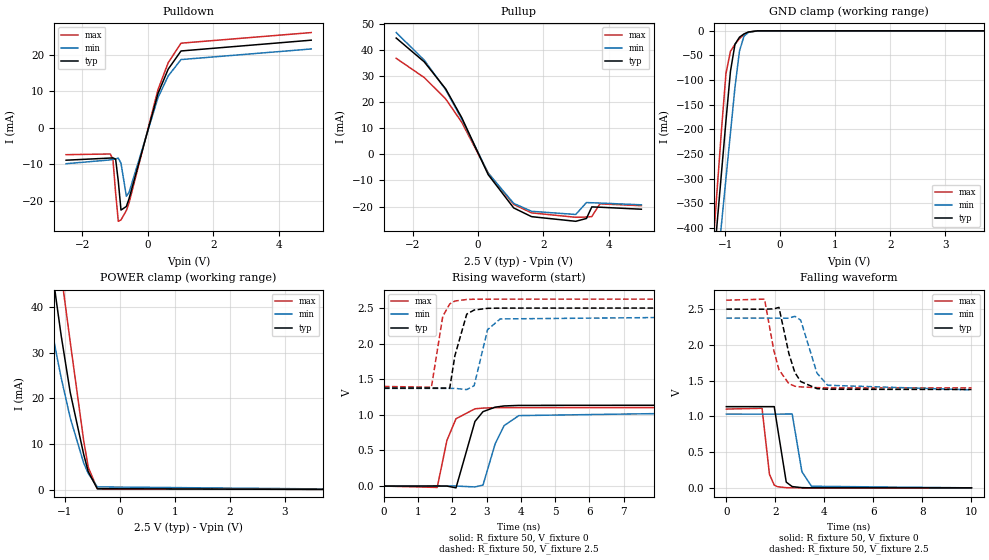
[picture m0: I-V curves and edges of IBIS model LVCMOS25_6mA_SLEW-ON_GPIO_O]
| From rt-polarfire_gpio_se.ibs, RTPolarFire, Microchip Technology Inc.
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|   Model LVCMOS25_6mA_SLEW-ON_GPIO_O
[Model]   LVCMOS25_6mA_SLEW-ON_GPIO_O
Model_type   Output
Polarity   Non-Inverting
Enable   Active-High
Vmeas =   1.25
Cref =   5p
Rref =   1M
|   typ   min   max
C_comp_pullup   2.605e-12   2.605e-12   2.76e-12
C_comp_pulldown  2.605e-12   2.605e-12   2.76e-12
[Temperature Range]  25C   125C   -55C
[Voltage Range]  2.5   2.375   2.625
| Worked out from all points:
|   slope of the pulldown table from 0 to 0.375 V, typ, clamps not added: 34.4 ohm
|   slope of the pullup table from 0 to 0.375 V, typ, clamps not added: 41.3 ohm
|   GND clamp passes 1 mA (typ) near -0.51 V on its own axis
|   POWER clamp passes 1 mA (typ) near -0.47 V on its own axis
|   rising waveform, R_fixture 50, V_fixture 0: 20-80 % time 394ps typ, 455ps min, 341ps max; typ from 0 V to 1.14 V
|   rising waveform, R_fixture 50, V_fixture 2.5: 20-80 % time 259ps typ, 297ps min, 226ps max; typ from 1.38 V to 2.5 V
|   falling waveform, R_fixture 50, V_fixture 0: 20-80 % time 244ps typ, 299ps min, 189ps max; typ from 1.14 V to 0 V
|   falling waveform, R_fixture 50, V_fixture 2.5: 20-80 % time 484ps typ, 580ps min, 429ps max; typ from 2.5 V to 1.38 V
[GND Clamp]
| Voltage   I(typ)   I(min)   I(max)
-2.5V     -2.154A    -2.028A    -2.413A
-1.23V    -500.9mA   -578.9mA   -453.4mA
-1.148V   -394.9mA   -486mA     -327.9mA
-1.066V   -289mA     -393mA     -202.4mA
-984.4mV  -183.1mA   -300.1mA   -86.85mA
-902.3mV  -82.21mA   -207.2mA   -41.59mA
-820.3mV  -27.37mA   -114.5mA   -27.29mA
-738.3mV  -12.87mA   -40.96mA   -15.82mA
-656.2mV  -6.285mA   -10.74mA   -7.396mA
-574.2mV  -2.342mA   -3.102mA   -2.493mA
-410.2mV  -62.85uA   -143.8uA   -47.39uA
5V        0A         0A         0A
[POWER Clamp]
| Voltage   I(typ)   I(min)   I(max)
-2.5V     191.3mA    149.5mA    238.1mA
-1.559V   79.6mA     58.4mA     105.4mA
-1.395V   63.37mA    46mA       85.27mA
-1.312V   55.59mA    40.21mA    75.31mA
-1.23V    48.04mA    34.68mA    65.5mA
-1.148V   40.77mA    29.43mA    56.09mA
-1.066V   33.71mA    24.49mA    47.24mA
-902.3mV  21.31mA    15.73mA    32.4mA
-656.2mV  7.665mA    5.781mA    10.63mA
-574.2mV  3.929mA    3.551mA    4.901mA
-410.2mV  189.8uA    599.4uA    178.9uA
5V        0A         0A         0A
[Pullup]
| Voltage   I(typ)   I(min)   I(max)
-2.5V     44.71mA    46.81mA    36.92mA
-1.641V   35.55mA    36.22mA    29.52mA
-984.4mV  25.15mA    24.81mA    21.29mA
-492.2mV  14.07mA    13.49mA    12.3mA
312.5mV   -7.724mA   -7.142mA   -7.098mA
1.094V    -20.54mA   -18.79mA   -19.18mA
1.641V    -23.89mA   -21.83mA   -22.43mA
2.992V    -25.67mA   -23.05mA   -24.13mA
3.32V     -24.58mA   -18.48mA   -24.05mA
3.484V    -20.14mA   -18.55mA   -23.86mA
3.73V     -20.26mA   -18.66mA   -18.96mA
5V        -21.03mA   -19.34mA   -19.68mA
[Pulldown]
| Voltage   I(typ)   I(min)   I(max)
-2.5V     -8.854mA   -9.811mA   -7.342mA
-1.148V   -8.264mA   -8.766mA   -7.153mA
-1.066V   -8.214mA   -8.624mA   -8.697mA
-984.4mV  -8.557mA   -8.47mA    -17.78mA
-902.3mV  -14.63mA   -8.3mA     -25.55mA
-820.3mV  -22.48mA   -9.656mA   -25.18mA
-656.2mV  -21.5mA    -18.69mA   -22.6mA
-574.2mV  -19.39mA   -17.66mA   -20.54mA
312.5mV   9.376mA    8.254mA    10.47mA
625mV     16.05mA    14.2mA     17.81mA
1.016V    21mA       18.65mA    23.13mA
5V        23.95mA    21.55mA    26.03mA
[Ramp]
dV/dt_r   0.681421/0.393607n  0.619126/0.454709n  0.661218/0.341423n
dV/dt_f   0.674518/0.483712n  0.602245/0.580292n  0.735818/0.428847n
R_load = 50
[Rising Waveform]
R_fixture = 50
V_fixture = 0
V_fixture_min = 0
V_fixture_max = 0
| Time   V(typ)   V(min)   V(max)
0s        17.65nV    75.39nV    21.59nV
1.555ns   875.4uV    540.3uV    -19.17mV
1.839ns   289.7uV    639uV      641.5mV
2.104ns   -25.01mV   731uV      945.7mV
2.657ns   907.6mV    -12.27mV   1.085V
2.892ns   1.045V     13.89mV    1.095V
3.247ns   1.108V     593.2mV    1.101V
3.507ns   1.125V     848.2mV    1.101V
3.937ns   1.133V     989.5mV    1.102V
10ns      1.136V     1.032V     1.102V
[Rising Waveform]
R_fixture = 50
V_fixture = 2.5
V_fixture_min = 2.375
V_fixture_max = 2.625
| Time   V(typ)   V(min)   V(max)
0s        1.376V     1.371V     1.399V
1.386ns   1.376V     1.372V     1.388V
1.717ns   1.376V     1.372V     2.383V
1.921ns   1.375V     1.372V     2.558V
2.071ns   1.83V      1.372V     2.598V
2.417ns   2.414V     1.355V     2.62V
2.633ns   2.472V     1.409V     2.624V
3.026ns   2.496V     2.197V     2.624V
3.395ns   2.499V     2.347V     2.625V
10ns      2.5V       2.375V     2.625V
[Falling Waveform]
R_fixture = 50
V_fixture = 0
V_fixture_min = 0
V_fixture_max = 0
| Time   V(typ)   V(min)   V(max)
0s        1.136V     1.032V     1.102V
1.457ns   1.136V     1.031V     1.113V
1.759ns   1.136V     1.031V     189.6mV
1.954ns   1.136V     1.031V     38.87mV
2.085ns   848.8mV    1.031V     16.02mV
2.444ns   80.2mV     1.033V     2.252mV
2.686ns   17.88mV    1.033V     906.3uV
3.082ns   2.923mV    226.8mV    -65.25uV
3.473ns   475.9uV    22.31mV    -61.53uV
10ns      1.363uV    4.606uV    573.9nV
[Falling Waveform]
R_fixture = 50
V_fixture = 2.5
V_fixture_min = 2.375
V_fixture_max = 2.625
| Time   V(typ)   V(min)   V(max)
0s        2.5V       2.375V     2.625V
1.558ns   2.499V     2.375V     2.64V
1.934ns   2.504V     2.374V     1.927V
2.147ns   2.524V     2.374V     1.652V
2.552ns   1.877V     2.373V     1.457V
2.795ns   1.614V     2.4V       1.422V
3.034ns   1.487V     2.345V     1.412V
3.696ns   1.388V     1.606V     1.402V
4.133ns   1.379V     1.435V     1.398V
10ns      1.376V     1.371V     1.399V
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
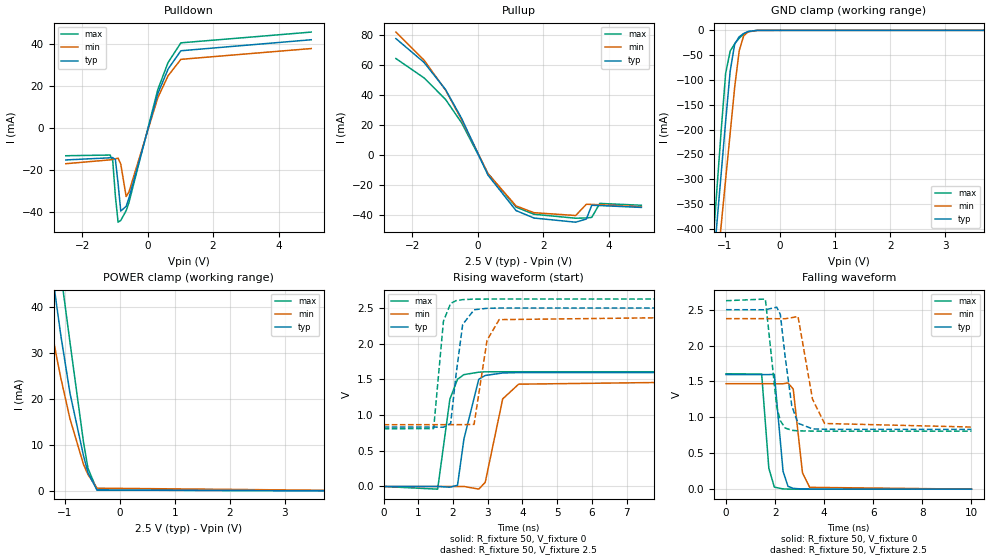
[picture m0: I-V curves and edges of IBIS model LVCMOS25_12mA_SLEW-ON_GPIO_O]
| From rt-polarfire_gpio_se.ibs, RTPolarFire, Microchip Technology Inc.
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|   Model LVCMOS25_12mA_SLEW-ON_GPIO_O
[Model]   LVCMOS25_12mA_SLEW-ON_GPIO_O
Model_type   Output
Polarity   Non-Inverting
Enable   Active-High
Vmeas =   1.25
Cref =   5p
Rref =   1M
|   typ   min   max
C_comp_pullup   2.605e-12   2.605e-12   2.76e-12
C_comp_pulldown  2.605e-12   2.605e-12   2.76e-12
[Temperature Range]  25C   125C   -55C
[Voltage Range]  2.5   2.375   2.625
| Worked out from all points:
|   slope of the pulldown table from 0 to 0.375 V, typ, clamps not added: 19.8 ohm
|   slope of the pullup table from 0 to 0.375 V, typ, clamps not added: 23.7 ohm
|   GND clamp passes 1 mA (typ) near -0.51 V on its own axis
|   POWER clamp passes 1 mA (typ) near -0.47 V on its own axis
|   rising waveform, R_fixture 50, V_fixture 0: 20-80 % time 296ps typ, 366ps min, 269ps max; typ from 0 V to 1.6 V
|   rising waveform, R_fixture 50, V_fixture 2.5: 20-80 % time 229ps typ, 276ps min, 184ps max; typ from 0.833 V to 2.5 V
|   falling waveform, R_fixture 50, V_fixture 0: 20-80 % time 210ps typ, 269ps min, 180ps max; typ from 1.6 V to 0 V
|   falling waveform, R_fixture 50, V_fixture 2.5: 20-80 % time 366ps typ, 456ps min, 317ps max; typ from 2.5 V to 0.833 V
[GND Clamp]
| Voltage   I(typ)   I(min)   I(max)
-2.5V     -2.154A    -2.028A    -2.413A
-1.23V    -500.9mA   -578.9mA   -453.4mA
-1.148V   -394.9mA   -486mA     -327.9mA
-1.066V   -289mA     -393mA     -202.4mA
-984.4mV  -183.1mA   -300.1mA   -86.85mA
-902.3mV  -82.21mA   -207.2mA   -41.59mA
-820.3mV  -27.37mA   -114.5mA   -27.29mA
-738.3mV  -12.87mA   -40.96mA   -15.82mA
-656.2mV  -6.285mA   -10.74mA   -7.396mA
-574.2mV  -2.342mA   -3.102mA   -2.493mA
-410.2mV  -62.85uA   -143.8uA   -47.39uA
5V        0A         0A         0A
[POWER Clamp]
| Voltage   I(typ)   I(min)   I(max)
-2.5V     191.3mA    149.5mA    238.1mA
-1.559V   79.6mA     58.4mA     105.4mA
-1.395V   63.37mA    46mA       85.27mA
-1.312V   55.59mA    40.21mA    75.31mA
-1.23V    48.04mA    34.68mA    65.5mA
-1.148V   40.77mA    29.43mA    56.09mA
-1.066V   33.71mA    24.49mA    47.24mA
-902.3mV  21.31mA    15.73mA    32.4mA
-656.2mV  7.665mA    5.781mA    10.63mA
-574.2mV  3.929mA    3.551mA    4.901mA
-410.2mV  189.8uA    599.4uA    178.9uA
5V        0A         0A         0A
[Pullup]
| Voltage   I(typ)   I(min)   I(max)
-2.5V     77.74mA    82.08mA    64.41mA
-1.641V   61.82mA    63.38mA    51.5mA
-984.4mV  43.73mA    43.34mA    37.13mA
-492.2mV  24.44mA    23.52mA    21.45mA
312.5mV   -13.44mA   -12.47mA   -12.35mA
1.172V    -37.16mA   -34.04mA   -34.81mA
1.719V    -42.12mA   -38.55mA   -39.59mA
2.992V    -44.89mA   -40.43mA   -42.24mA
3.32V     -42.78mA   -32.91mA   -42.06mA
3.484V    -33.59mA   -33.04mA   -41.7mA
3.73V     -33.78mA   -33.25mA   -32.34mA
5V        -35.02mA   -34.62mA   -33.59mA
[Pulldown]
| Voltage   I(typ)   I(min)   I(max)
-2.5V     -15.27mA   -17.06mA   -13.27mA
-1.148V   -14.25mA   -15.23mA   -12.94mA
-1.066V   -14.16mA   -14.99mA   -15.57mA
-984.4mV  -15.08mA   -14.72mA   -32.54mA
-902.3mV  -26.47mA   -14.42mA   -44.87mA
-820.3mV  -39.57mA   -17.22mA   -44.04mA
-656.2mV  -37.32mA   -32.66mA   -39.4mA
-574.2mV  -33.6mA    -30.67mA   -35.75mA
312.5mV   16.27mA    14.35mA    18.22mA
625mV     27.94mA    24.74mA    31.05mA
1.016V    36.65mA    32.56mA    40.41mA
5V        41.89mA    37.71mA    45.53mA
[Ramp]
dV/dt_r   0.957456/0.296222n  0.881546/0.365612n  0.96434/0.268759n
dV/dt_f   1.0004/0.365865n  0.905863/0.455827n  1.09002/0.317441n
R_load = 50
[Rising Waveform]
R_fixture = 50
V_fixture = 0
V_fixture_min = 0
V_fixture_max = 0
| Time   V(typ)   V(min)   V(max)
0s        11.97nV    51.88nV    14.39nV
1.556ns   668.8uV    351.4uV    -37.46mV
1.908ns   -9.888mV   430.9uV    1.222V
2.129ns   17.51mV    480.8uV    1.502V
2.313ns   663.8mV    522.3uV    1.567V
2.74ns    1.501V     -36.8mV    1.601V
2.927ns   1.555V     57.64mV    1.606V
3.431ns   1.59V      1.227V     1.607V
3.89ns    1.595V     1.433V     1.607V
10ns      1.596V     1.469V     1.607V
[Rising Waveform]
R_fixture = 50
V_fixture = 2.5
V_fixture_min = 2.375
V_fixture_max = 2.625
| Time   V(typ)   V(min)   V(max)
0s        832.7mV    865.2mV    808.3mV
1.441ns   832.4mV    865.7mV    811.1mV
1.723ns   830.1mV    865.8mV    2.315V
1.931ns   883.9mV    865.9mV    2.565V
2.087ns   1.568V     865.9mV    2.603V
2.277ns   2.269V     866.1mV    2.617V
2.606ns   2.475V     869.4mV    2.624V
2.98ns    2.496V     2.049V     2.625V
3.329ns   2.499V     2.337V     2.625V
10ns      2.5V       2.375V     2.625V
[Falling Waveform]
R_fixture = 50
V_fixture = 0
V_fixture_min = 0
V_fixture_max = 0
| Time   V(typ)   V(min)   V(max)
0s        1.596V     1.469V     1.607V
1.451ns   1.596V     1.469V     1.603V
1.743ns   1.596V     1.469V     292mV
1.968ns   1.599V     1.468V     27.98mV
2.323ns   247.6mV    1.468V     3.519mV
2.523ns   39.18mV    1.48V      1.226mV
2.737ns   11.2mV     1.395V     893.7uV
3.114ns   2.03mV     228.4mV    847.3uV
3.407ns   684.2uV    25.4mV     811.2uV
10ns      560.1nV    3.948uV    27.48nV
[Falling Waveform]
R_fixture = 50
V_fixture = 2.5
V_fixture_min = 2.375
V_fixture_max = 2.625
| Time   V(typ)   V(min)   V(max)
0s        2.5V       2.375V     2.625V
1.602ns   2.499V     2.375V     2.648V
2.065ns   2.535V     2.374V     1.145V
2.21ns    2.437V     2.374V     954.5mV
2.411ns   1.837V     2.374V     851.3mV
2.679ns   1.158V     2.389V     820mV
2.933ns   917.9mV    2.406V     812.3mV
3.524ns   839.9mV    1.253V     808.6mV
4.015ns   833.9mV    914.9mV    808.2mV
10ns      832.7mV    865.2mV    808.3mV
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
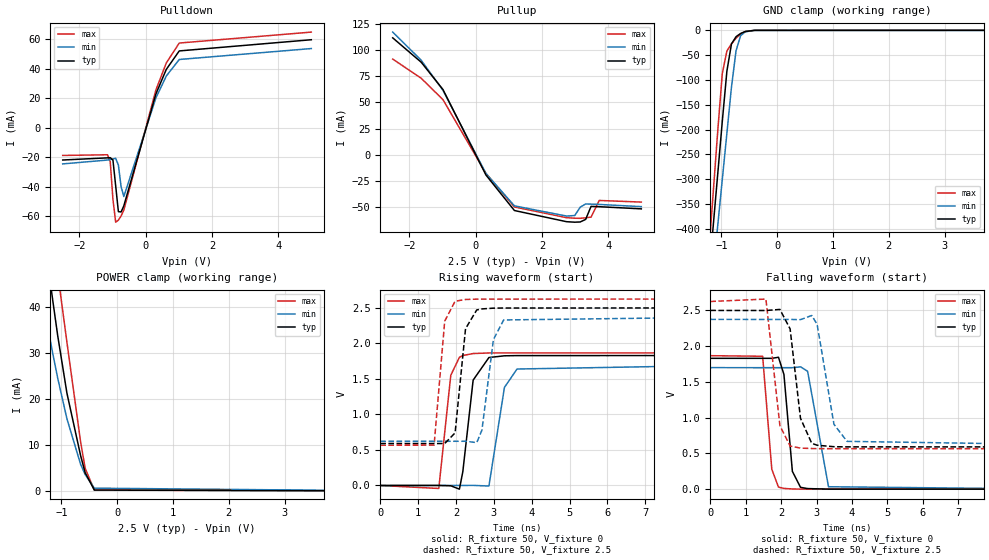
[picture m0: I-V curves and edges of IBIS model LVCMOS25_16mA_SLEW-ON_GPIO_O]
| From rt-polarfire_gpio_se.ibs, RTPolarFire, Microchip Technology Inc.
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|   Model LVCMOS25_16mA_SLEW-ON_GPIO_O
[Model]   LVCMOS25_16mA_SLEW-ON_GPIO_O
Model_type   Output
Polarity   Non-Inverting
Enable   Active-High
Vmeas =   1.25
Cref =   5p
Rref =   1M
|   typ   min   max
C_comp_pullup   2.605e-12   2.605e-12   2.76e-12
C_comp_pulldown  2.605e-12   2.605e-12   2.76e-12
[Temperature Range]  25C   125C   -55C
[Voltage Range]  2.5   2.375   2.625
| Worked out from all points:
|   slope of the pulldown table from 0 to 0.375 V, typ, clamps not added: 14 ohm
|   slope of the pullup table from 0 to 0.375 V, typ, clamps not added: 16.7 ohm
|   GND clamp passes 1 mA (typ) near -0.51 V on its own axis
|   POWER clamp passes 1 mA (typ) near -0.47 V on its own axis
|   rising waveform, R_fixture 50, V_fixture 0: 20-80 % time 231ps typ, 280ps min, 202ps max; typ from 0 V to 1.83 V
|   rising waveform, R_fixture 50, V_fixture 2.5: 20-80 % time 208ps typ, 250ps min, 158ps max; typ from 0.591 V to 2.5 V
|   falling waveform, R_fixture 50, V_fixture 0: 20-80 % time 182ps typ, 237ps min, 149ps max; typ from 1.83 V to 0 V
|   falling waveform, R_fixture 50, V_fixture 2.5: 20-80 % time 272ps typ, 348ps min, 237ps max; typ from 2.5 V to 0.591 V
[GND Clamp]
| Voltage   I(typ)   I(min)   I(max)
-2.5V     -2.154A    -2.028A    -2.413A
-1.23V    -500.9mA   -578.9mA   -453.4mA
-1.148V   -394.9mA   -486mA     -327.9mA
-1.066V   -289mA     -393mA     -202.4mA
-984.4mV  -183.1mA   -300.1mA   -86.85mA
-902.3mV  -82.21mA   -207.2mA   -41.59mA
-820.3mV  -27.37mA   -114.5mA   -27.29mA
-738.3mV  -12.87mA   -40.96mA   -15.82mA
-656.2mV  -6.285mA   -10.74mA   -7.396mA
-574.2mV  -2.342mA   -3.102mA   -2.493mA
-410.2mV  -62.85uA   -143.8uA   -47.39uA
5V        0A         0A         0A
[POWER Clamp]
| Voltage   I(typ)   I(min)   I(max)
-2.5V     191.3mA    149.5mA    238.1mA
-1.559V   79.6mA     58.4mA     105.4mA
-1.395V   63.37mA    46mA       85.27mA
-1.312V   55.59mA    40.21mA    75.31mA
-1.23V    48.04mA    34.68mA    65.5mA
-1.148V   40.77mA    29.43mA    56.09mA
-1.066V   33.71mA    24.49mA    47.24mA
-902.3mV  21.31mA    15.73mA    32.4mA
-656.2mV  7.665mA    5.781mA    10.63mA
-574.2mV  3.929mA    3.551mA    4.901mA
-410.2mV  189.8uA    599.4uA    178.9uA
5V        0A         0A         0A
[Pullup]
| Voltage   I(typ)   I(min)   I(max)
-2.5V     111.6mA    117.1mA    91.37mA
-1.641V   88.39mA    90.27mA    73.1mA
-984.4mV  62.36mA    61.65mA    52.73mA
312.5mV   -19.13mA   -17.73mA   -17.55mA
1.172V    -52.99mA   -48.54mA   -49.6mA
2.746V    -63.65mA   -58.27mA   -59.81mA
2.992V    -64.11mA   -57.76mA   -60.31mA
3.156V    -63.9mA    -49.84mA   -60.42mA
3.32V     -61.47mA   -46.73mA   -59.92mA
3.484V    -49.07mA   -46.91mA   -59.28mA
3.73V     -49.35mA   -47.2mA    -43.4mA
5V        -51.4mA    -49.28mA   -44.94mA
[Pulldown]
| Voltage   I(typ)   I(min)   I(max)
-2.5V     -21.8mA    -24.45mA   -18.71mA
-1.148V   -20.34mA   -21.82mA   -18.24mA
-1.066V   -20.22mA   -21.47mA   -23.02mA
-984.4mV  -21.89mA   -21.08mA   -48.54mA
-902.3mV  -39.28mA   -20.66mA   -64mA
-820.3mV  -56.85mA   -25.18mA   -62.59mA
-738.3mV  -57.05mA   -39.96mA   -59.76mA
-656.2mV  -52.91mA   -46.58mA   -55.8mA
312.5mV   23.07mA    20.37mA    25.78mA
625mV     39.7mA     35.19mA    44.07mA
1.016V    52.23mA    46.42mA    57.57mA
5V        59.82mA    53.84mA    65.01mA
[Ramp]
dV/dt_r   1.09823/0.231334n  1.01996/0.280189n  1.11997/0.202472n
dV/dt_f   1.1454/0.272269n  1.05182/0.34815n  1.23508/0.236867n
R_load = 50
[Rising Waveform]
R_fixture = 50
V_fixture = 0
V_fixture_min = 0
V_fixture_max = 0
| Time   V(typ)   V(min)   V(max)
0s        9.068nV    39.59nV    10.85nV
1.546ns   623.5uV    621.1uV    -42.01mV
1.863ns   -3.976mV   748.4uV    1.552V
2.091ns   -51.72mV   840uV      1.805V
2.181ns   193.9mV    876.1uV    1.83V
2.454ns   1.484V     1.542mV    1.858V
2.871ns   1.802V     -7.547mV   1.866V
3.281ns   1.826V     1.381V     1.867V
3.613ns   1.829V     1.64V      1.867V
10ns      1.83V      1.7V       1.867V
[Rising Waveform]
R_fixture = 50
V_fixture = 2.5
V_fixture_min = 2.375
V_fixture_max = 2.625
| Time   V(typ)   V(min)   V(max)
0s        591mV      622mV      566.5mV
1.422ns   590.8mV    622.4mV    568.4mV
1.702ns   590.7mV    622.5mV    2.313V
1.977ns   741mV      622.6mV    2.595V
2.253ns   2.208V     622.7mV    2.619V
2.549ns   2.472V     603.7mV    2.624V
2.686ns   2.486V     779.7mV    2.624V
2.989ns   2.497V     2.054V     2.624V
3.261ns   2.499V     2.331V     2.624V
10ns      2.5V       2.375V     2.625V
[Falling Waveform]
R_fixture = 50
V_fixture = 0
V_fixture_min = 0
V_fixture_max = 0
| Time   V(typ)   V(min)   V(max)
0s        1.83V      1.7V       1.867V
1.478ns   1.83V      1.699V     1.859V
1.736ns   1.83V      1.699V     278.7mV
1.925ns   1.845V     1.699V     28.67mV
2.079ns   1.604V     1.699V     10.38mV
2.317ns   249.1mV    1.699V     2.674mV
2.547ns   25.59mV    1.711V     750.6uV
2.747ns   8.235mV    1.649V     706.3uV
3.337ns   627.2uV    33.93mV    648.9uV
10ns      206nV      3.318uV    -14.57nV
[Falling Waveform]
R_fixture = 50
V_fixture = 2.5
V_fixture_min = 2.375
V_fixture_max = 2.625
| Time   V(typ)   V(min)   V(max)
0s        2.5V       2.375V     2.625V
1.57ns    2.499V     2.374V     2.659V
1.965ns   2.514V     2.374V     888.3mV
2.253ns   2.242V     2.374V     603mV
2.546ns   991.7mV    2.371V     574.4mV
2.864ns   641.1mV    2.429V     568.3mV
3.016ns   614.7mV    2.304V     566.8mV
3.491ns   593.9mV    906.8mV    566.8mV
3.859ns   591.8mV    668.7mV    566.8mV
10ns      591mV      622mV      566.5mV
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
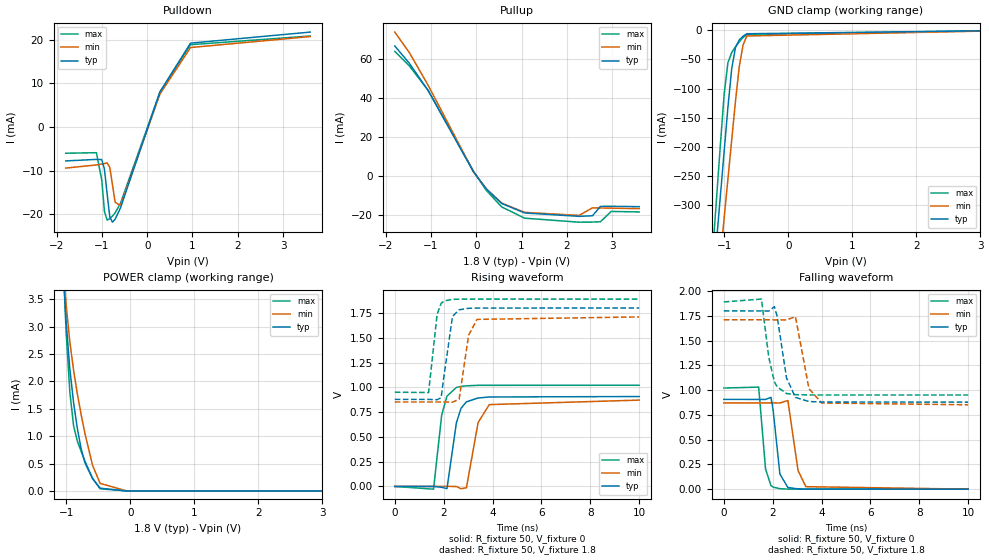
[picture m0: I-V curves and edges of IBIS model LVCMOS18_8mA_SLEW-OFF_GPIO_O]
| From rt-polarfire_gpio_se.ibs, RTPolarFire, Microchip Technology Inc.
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|   Model LVCMOS18_8mA_SLEW-OFF_GPIO_O
[Model]   LVCMOS18_8mA_SLEW-OFF_GPIO_O
Model_type   Output
Polarity   Non-Inverting
Enable   Active-High
Vmeas =   0.9
Cref =   5p
Rref =   1M
|   typ   min   max
C_comp_pullup   2.605e-12   2.605e-12   2.76e-12
C_comp_pulldown  2.605e-12   2.605e-12   2.76e-12
[Temperature Range]  25C   125C   -55C
[Voltage Range]  1.8   1.71   1.89
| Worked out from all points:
|   slope of the pulldown table from 0 to 0.27 V, typ, clamps not added: 34.9 ohm
|   slope of the pullup table from 0 to 0.27 V, typ, clamps not added: 33.9 ohm
|   GND clamp passes 1 mA (typ) near -0.52 V on its own axis
|   POWER clamp passes 1 mA (typ) near -0.81 V on its own axis
|   rising waveform, R_fixture 50, V_fixture 0: 20-80 % time 357ps typ, 417ps min, 305ps max; typ from 0 V to 0.907 V
|   rising waveform, R_fixture 50, V_fixture 1.8: 20-80 % time 264ps typ, 317ps min, 230ps max; typ from 0.878 V to 1.8 V
|   falling waveform, R_fixture 50, V_fixture 0: 20-80 % time 230ps typ, 285ps min, 183ps max; typ from 0.907 V to 0 V
|   falling waveform, R_fixture 50, V_fixture 1.8: 20-80 % time 368ps typ, 391ps min, 333ps max; typ from 1.8 V to 0.878 V
[GND Clamp]
| Voltage   I(typ)   I(min)   I(max)
-1.8V     -1.238A    -1.225A    -1.327A
-1.181V   -437.3mA   -523.2mA   -378.1mA
-1.122V   -361mA     -456.2mA   -287.7mA
-1.063V   -284.7mA   -389.3mA   -197.3mA
-1.004V   -208.5mA   -322.4mA   -110.3mA
-945mV    -132.4mA   -255.5mA   -55.69mA
-885.9mV  -66.33mA   -188.6mA   -38.3mA
-826.9mV  -29.63mA   -121.9mA   -28.32mA
-767.8mV  -16.36mA   -62.59mA   -19.64mA
-708.7mV  -10.12mA   -25.53mA   -12.4mA
-649.7mV  -5.882mA   -9.682mA   -6.873mA
3.6V      0A         0A         0A
[POWER Clamp]
| Voltage   I(typ)   I(min)   I(max)
-1.8V     45.61mA    34mA       62.13mA
-1.063V   4.301mA    4.351mA    4.537mA
-1.004V   3.099mA    3.407mA    2.918mA
-945mV    2.226mA    2.718mA    1.799mA
-885.9mV  1.604mA    2.194mA    1.183mA
-826.9mV  1.131mA    1.765mA    904.1uA
-767.8mV  765.5uA    1.388mA    720.7uA
-708.7mV  512.4uA    1.046mA    541.9uA
-590.6mV  225.1uA    468.8uA    230.2uA
-472.5mV  50.43uA    137.9uA    39.22uA
-59.06mV  411.6pA    7.346nA    87.23nA
3.6V      0A         0A         0A
[Pullup]
| Voltage   I(typ)   I(min)   I(max)
-1.8V     66.93mA    74.07mA    64.14mA
-1.477V   57.94mA    63.48mA    56.62mA
-1.063V   43.98mA    46.69mA    44.07mA
-59.06mV  2.017mA    2.039mA    2.32mA
225mV     -6.802mA   -6.745mA   -7.553mA
562.5mV   -14.19mA   -14mA      -15.98mA
1.069V    -19.09mA   -18.77mA   -21.77mA
2.272V    -20.83mA   -20.35mA   -23.84mA
2.568V    -20.53mA   -16.45mA   -23.77mA
2.745V    -15.68mA   -16.51mA   -23.6mA
2.981V    -15.64mA   -16.61mA   -18.3mA
3.6V      -15.85mA   -16.86mA   -18.55mA
[Pulldown]
| Voltage   I(typ)   I(min)   I(max)
-1.8V     -7.803mA   -9.44mA    -6.039mA
-1.122V   -7.452mA   -8.722mA   -5.916mA
-1.004V   -7.497mA   -8.508mA   -12.21mA
-945mV    -9.727mA   -8.39mA    -19.38mA
-885.9mV  -15.31mA   -8.264mA   -21.35mA
-826.9mV  -20.64mA   -9.278mA   -21.03mA
-767.8mV  -21.84mA   -13.27mA   -20.45mA
-708.7mV  -21.14mA   -17.28mA   -19.69mA
-590.6mV  -18.57mA   -18.02mA   -17.51mA
281.2mV   8.019mA    7.536mA    7.984mA
956.3mV   19.19mA    18.18mA    18.83mA
3.6V      21.72mA    20.7mA     20.82mA
[Ramp]
dV/dt_r   0.543994/0.35722n  0.522482/0.416882n  0.612384/0.305255n
dV/dt_f   0.552949/0.36822n  0.514969/0.39086n  0.56363/0.333288n
R_load = 50
[Rising Waveform]
R_fixture = 50
V_fixture = 0
V_fixture_min = 0
V_fixture_max = 0
| Time   V(typ)   V(min)   V(max)
0s        15.84nV    40.24nV    21.01nV
1.587ns   -846.4uV   661.3uV    -27.53mV
1.919ns   -8.376mV   799.6uV    720.5mV
2.135ns   -22.19mV   889.6uV    910.2mV
2.52ns    641mV      -800.3uV   998.5mV
2.713ns   789.2mV    -22.73mV   1.009V
2.931ns   853.1mV    -13.98mV   1.015V
3.41ns    892.1mV    644.9mV    1.02V
3.868ns   902.4mV    825.5mV    1.02V
10ns      906.7mV    870.8mV    1.021V
[Rising Waveform]
R_fixture = 50
V_fixture = 1.8
V_fixture_min = 1.71
V_fixture_max = 1.89
| Time   V(typ)   V(min)   V(max)
0s        878.4mV    851.7mV    950.6mV
1.383ns   877.9mV    851.6mV    947.1mV
1.732ns   874.7mV    851.6mV    1.734V
1.897ns   895.8mV    851.6mV    1.846V
2.024ns   1.133V     851.6mV    1.872V
2.363ns   1.715V     849.9mV    1.887V
2.634ns   1.782V     880.2mV    1.889V
3.022ns   1.797V     1.526V     1.89V
3.368ns   1.799V     1.685V     1.89V
10ns      1.8V       1.71V      1.89V
[Falling Waveform]
R_fixture = 50
V_fixture = 0
V_fixture_min = 0
V_fixture_max = 0
| Time   V(typ)   V(min)   V(max)
0s        906.6mV    870.9mV    1.021V
1.427ns   905.8mV    870.3mV    1.03V
1.708ns   905.7mV    870.2mV    203.4mV
1.929ns   926.7mV    870.2mV    36.77mV
2.017ns   801.7mV    870.1mV    20.86mV
2.295ns   152.5mV    870mV      4.632mV
2.622ns   16.85mV    894.9mV    924.2uV
3.038ns   2.905mV    187.3mV    136.9uV
3.358ns   964.6uV    25.27mV    -26.87uV
10ns      337.4nV    1.646uV    -540.1nV
[Falling Waveform]
R_fixture = 50
V_fixture = 1.8
V_fixture_min = 1.71
V_fixture_max = 1.89
| Time   V(typ)   V(min)   V(max)
0s        1.8V       1.71V      1.89V
1.541ns   1.799V     1.71V      1.919V
1.84ns    1.798V     1.71V      1.332V
2.071ns   1.842V     1.709V     1.083V
2.181ns   1.747V     1.709V     1.034V
2.566ns   1.123V     1.709V     965.2mV
2.932ns   926.3mV    1.741V     953.6mV
3.485ns   884.4mV    1.014V     951.2mV
4.005ns   879.7mV    869.9mV    950.4mV
10ns      878.4mV    851.7mV    950.6mV
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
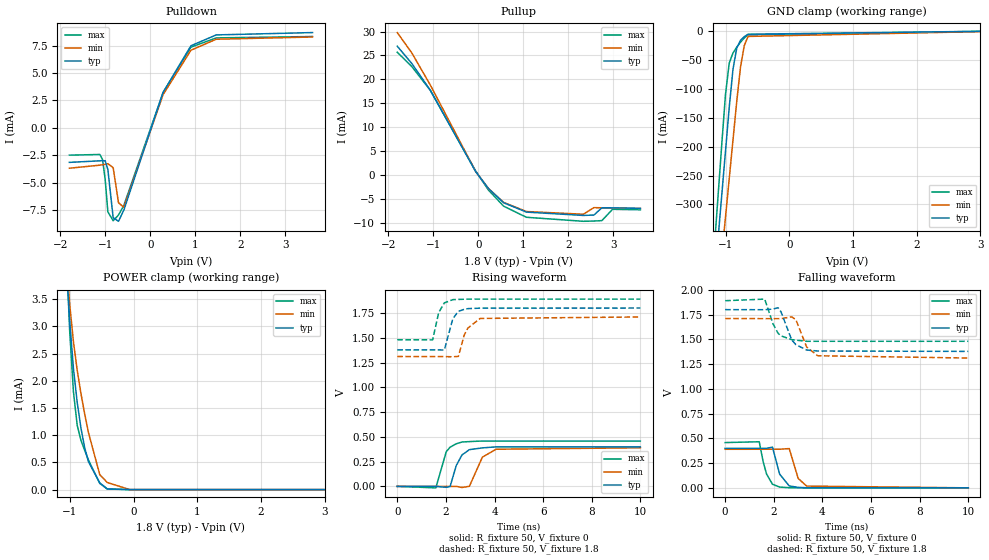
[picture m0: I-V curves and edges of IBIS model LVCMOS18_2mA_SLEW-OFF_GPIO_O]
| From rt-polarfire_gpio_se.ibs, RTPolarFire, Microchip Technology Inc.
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|   Model LVCMOS18_2mA_SLEW-OFF_GPIO_O
[Model]   LVCMOS18_2mA_SLEW-OFF_GPIO_O
Model_type   Output
Polarity   Non-Inverting
Enable   Active-High
Vmeas =   0.9
Cref =   5p
Rref =   1M
|   typ   min   max
C_comp_pullup   2.605e-12   2.605e-12   2.76e-12
C_comp_pulldown  2.605e-12   2.605e-12   2.76e-12
[Temperature Range]  25C   125C   -55C
[Voltage Range]  1.8   1.71   1.89
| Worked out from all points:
|   slope of the pulldown table from 0 to 0.27 V, typ, clamps not added: 86.6 ohm
|   slope of the pullup table from 0 to 0.27 V, typ, clamps not added: 84.3 ohm
|   GND clamp passes 1 mA (typ) near -0.52 V on its own axis
|   POWER clamp passes 1 mA (typ) near -0.81 V on its own axis
|   rising waveform, R_fixture 50, V_fixture 0: 20-80 % time 398ps typ, 475ps min, 353ps max; typ from 0 V to 0.399 V
|   rising waveform, R_fixture 50, V_fixture 1.8: 20-80 % time 285ps typ, 397ps min, 248ps max; typ from 1.38 V to 1.8 V
|   falling waveform, R_fixture 50, V_fixture 0: 20-80 % time 308ps typ, 299ps min, 288ps max; typ from 0.399 V to 0 V
|   falling waveform, R_fixture 50, V_fixture 1.8: 20-80 % time 445ps typ, 463ps min, 392ps max; typ from 1.8 V to 1.38 V
[GND Clamp]
| Voltage   I(typ)   I(min)   I(max)
-1.8V     -1.238A    -1.225A    -1.327A
-1.181V   -437.3mA   -523.2mA   -378.1mA
-1.122V   -361mA     -456.2mA   -287.7mA
-1.063V   -284.7mA   -389.3mA   -197.3mA
-1.004V   -208.5mA   -322.4mA   -110.3mA
-945mV    -132.4mA   -255.5mA   -55.69mA
-885.9mV  -66.33mA   -188.6mA   -38.3mA
-826.9mV  -29.63mA   -121.9mA   -28.32mA
-767.8mV  -16.36mA   -62.59mA   -19.64mA
-708.7mV  -10.12mA   -25.53mA   -12.4mA
-649.7mV  -5.882mA   -9.682mA   -6.873mA
3.6V      0A         0A         0A
[POWER Clamp]
| Voltage   I(typ)   I(min)   I(max)
-1.8V     45.61mA    34mA       62.13mA
-1.063V   4.301mA    4.351mA    4.537mA
-1.004V   3.099mA    3.407mA    2.918mA
-945mV    2.226mA    2.718mA    1.799mA
-885.9mV  1.604mA    2.194mA    1.183mA
-826.9mV  1.131mA    1.765mA    904.1uA
-767.8mV  765.5uA    1.388mA    720.7uA
-708.7mV  512.4uA    1.046mA    541.9uA
-531.6mV  123.5uA    275.3uA    113.6uA
-413.4mV  12.94uA    130.5uA    10.43uA
-59.06mV  411.5pA    7.346nA    72.69nA
3.6V      0A         0A         0A
[Pullup]
| Voltage   I(typ)   I(min)   I(max)
-1.8V     26.94mA    29.78mA    25.68mA
-1.477V   23.34mA    25.54mA    22.7mA
-1.063V   17.72mA    18.8mA     17.7mA
-59.06mV  811.8uA    820.8uA    945.5uA
225mV     -2.733mA   -2.711mA   -3.035mA
562.5mV   -5.692mA   -5.62mA    -6.411mA
1.069V    -7.641mA   -7.522mA   -8.72mA
2.332V    -8.336mA   -8.083mA   -9.558mA
2.568V    -8.253mA   -6.714mA   -9.501mA
2.745V    -6.743mA   -6.742mA   -9.417mA
2.981V    -6.755mA   -6.786mA   -7.062mA
3.6V      -6.855mA   -6.886mA   -7.155mA
[Pulldown]
| Voltage   I(typ)   I(min)   I(max)
-1.8V     -3.136mA   -3.669mA   -2.478mA
-1.122V   -2.994mA   -3.391mA   -2.418mA
-1.063V   -2.981mA   -3.351mA   -2.878mA
-1.004V   -2.993mA   -3.309mA   -4.712mA
-945mV    -3.783mA   -3.264mA   -7.642mA
-826.9mV  -8.174mA   -3.615mA   -8.453mA
-708.7mV  -8.503mA   -6.808mA   -7.929mA
-590.6mV  -7.483mA   -7.233mA   -7.064mA
281.2mV   3.23mA     3.027mA    3.219mA
900mV     7.483mA    7.078mA    7.356mA
1.462V    8.472mA    8.079mA    8.201mA
3.6V      8.686mA    8.282mA    8.327mA
[Ramp]
dV/dt_r   0.239231/0.397911n  0.233742/0.475108n  0.27432/0.353201n
dV/dt_f   0.252982/0.445005n  0.239648/0.463313n  0.246191/0.392247n
R_load = 50
[Rising Waveform]
R_fixture = 50
V_fixture = 0
V_fixture_min = 0
V_fixture_max = 0
| Time   V(typ)   V(min)   V(max)
0s        25.24nV    63.27nV    33.46nV
1.586ns   -343uV     -145.7uV   -14.91mV
2.016ns   -9.387mV   -185.2uV   350.4mV
2.175ns   -118.5uV   -199.8uV   396.1mV
2.427ns   210.9mV    -223uV     430mV
2.665ns   317.8mV    -11.17mV   448.1mV
2.967ns   370.8mV    1.021mV    452.2mV
3.5ns     388.5mV    294.9mV    457.8mV
4.064ns   398.8mV    374.9mV    457.7mV
10ns      398.7mV    389.6mV    457.2mV
[Rising Waveform]
R_fixture = 50
V_fixture = 1.8
V_fixture_min = 1.71
V_fixture_max = 1.89
| Time   V(typ)   V(min)   V(max)
0s        1.378V     1.311V     1.48V
1.455ns   1.378V     1.31V      1.479V
1.704ns   1.378V     1.31V      1.754V
1.936ns   1.376V     1.31V      1.852V
2.288ns   1.694V     1.308V     1.885V
2.515ns   1.767V     1.312V     1.887V
2.753ns   1.787V     1.526V     1.889V
2.902ns   1.794V     1.597V     1.89V
3.409ns   1.799V     1.695V     1.89V
10ns      1.8V       1.71V      1.89V
[Falling Waveform]
R_fixture = 50
V_fixture = 0
V_fixture_min = 0
V_fixture_max = 0
| Time   V(typ)   V(min)   V(max)
0s        398.7mV    389.6mV    457.2mV
1.402ns   399mV      389.9mV    465.6mV
1.571ns   399.1mV    389.9mV    255.9mV
1.704ns   399.1mV    390mV      139.2mV
1.947ns   411.2mV    390mV      36.16mV
2.24ns    139.1mV    390.1mV    8.057mV
2.635ns   19.5mV     396.6mV    1.226mV
3.003ns   4.51mV     95.34mV    361uV
3.352ns   1.022mV    17.79mV    -113.6uV
10ns      1.026uV    4.801uV    -228.3nV
[Falling Waveform]
R_fixture = 50
V_fixture = 1.8
V_fixture_min = 1.71
V_fixture_max = 1.89
| Time   V(typ)   V(min)   V(max)
0s        1.8V       1.71V      1.89V
1.628ns   1.799V     1.709V     1.906V
1.967ns   1.806V     1.709V     1.657V
2.177ns   1.819V     1.709V     1.561V
2.298ns   1.778V     1.709V     1.535V
2.734ns   1.496V     1.727V     1.497V
2.909ns   1.446V     1.699V     1.492V
3.353ns   1.392V     1.422V     1.48V
3.805ns   1.382V     1.334V     1.48V
10ns      1.378V     1.311V     1.48V
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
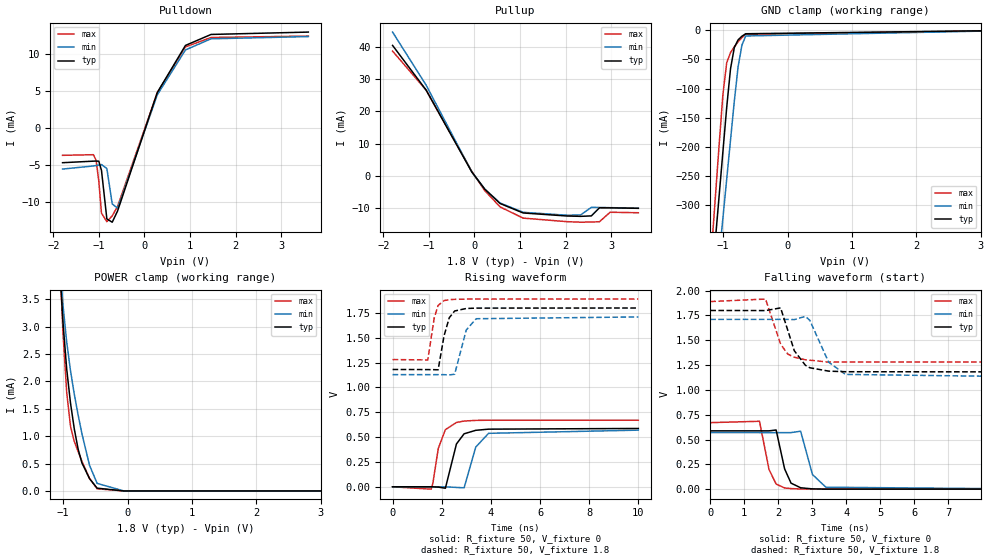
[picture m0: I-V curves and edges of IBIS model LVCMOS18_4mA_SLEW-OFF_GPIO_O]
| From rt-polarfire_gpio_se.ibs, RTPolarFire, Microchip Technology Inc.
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|   Model LVCMOS18_4mA_SLEW-OFF_GPIO_O
[Model]   LVCMOS18_4mA_SLEW-OFF_GPIO_O
Model_type   Output
Polarity   Non-Inverting
Enable   Active-High
Vmeas =   0.9
Cref =   5p
Rref =   1M
|   typ   min   max
C_comp_pullup   2.605e-12   2.605e-12   2.76e-12
C_comp_pulldown  2.605e-12   2.605e-12   2.76e-12
[Temperature Range]  25C   125C   -55C
[Voltage Range]  1.8   1.71   1.89
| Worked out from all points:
|   slope of the pulldown table from 0 to 0.27 V, typ, clamps not added: 57.9 ohm
|   slope of the pullup table from 0 to 0.27 V, typ, clamps not added: 56.2 ohm
|   GND clamp passes 1 mA (typ) near -0.52 V on its own axis
|   POWER clamp passes 1 mA (typ) near -0.81 V on its own axis
|   rising waveform, R_fixture 50, V_fixture 0: 20-80 % time 391ps typ, 463ps min, 352ps max; typ from 0 V to 0.587 V
|   rising waveform, R_fixture 50, V_fixture 1.8: 20-80 % time 314ps typ, 371ps min, 221ps max; typ from 1.18 V to 1.8 V
|   falling waveform, R_fixture 50, V_fixture 0: 20-80 % time 237ps typ, 290ps min, 250ps max; typ from 0.587 V to 0 V
|   falling waveform, R_fixture 50, V_fixture 1.8: 20-80 % time 400ps typ, 498ps min, 398ps max; typ from 1.8 V to 1.18 V
[GND Clamp]
| Voltage   I(typ)   I(min)   I(max)
-1.8V     -1.238A    -1.225A    -1.327A
-1.181V   -437.3mA   -523.2mA   -378.1mA
-1.122V   -361mA     -456.2mA   -287.7mA
-1.063V   -284.7mA   -389.3mA   -197.3mA
-1.004V   -208.5mA   -322.4mA   -110.3mA
-945mV    -132.4mA   -255.5mA   -55.69mA
-885.9mV  -66.33mA   -188.6mA   -38.3mA
-826.9mV  -29.63mA   -121.9mA   -28.32mA
-767.8mV  -16.36mA   -62.59mA   -19.64mA
-708.7mV  -10.12mA   -25.53mA   -12.4mA
-649.7mV  -5.882mA   -9.682mA   -6.873mA
3.6V      0A         0A         0A
[POWER Clamp]
| Voltage   I(typ)   I(min)   I(max)
-1.8V     45.61mA    34mA       62.13mA
-1.063V   4.301mA    4.351mA    4.537mA
-1.004V   3.099mA    3.407mA    2.918mA
-945mV    2.226mA    2.718mA    1.799mA
-885.9mV  1.604mA    2.194mA    1.183mA
-826.9mV  1.131mA    1.765mA    904.1uA
-767.8mV  765.5uA    1.388mA    720.7uA
-708.7mV  512.4uA    1.046mA    541.9uA
-590.6mV  225.1uA    468.8uA    230.2uA
-472.5mV  50.43uA    137.9uA    39.22uA
-59.06mV  411.5pA    7.346nA    87.23nA
3.6V      0A         0A         0A
[Pullup]
| Voltage   I(typ)   I(min)   I(max)
-1.8V     40.36mA    44.48mA    38.6mA
-1.063V   26.55mA    28.08mA    26.54mA
-59.06mV  1.217mA    1.226mA    1.397mA
225mV     -4.098mA   -4.053mA   -4.543mA
562.5mV   -8.54mA    -8.405mA   -9.6mA
1.069V    -11.47mA   -11.26mA   -13.06mA
2.036V    -12.41mA   -12.17mA   -14.16mA
2.332V    -12.51mA   -12.08mA   -14.32mA
2.568V    -12.37mA   -9.728mA   -14.27mA
2.745V    -9.879mA   -9.765mA   -14.18mA
2.981V    -9.884mA   -9.828mA   -11.24mA
3.6V      -10.03mA   -9.968mA   -11.4mA
[Pulldown]
| Voltage   I(typ)   I(min)   I(max)
-1.8V     -4.669mA   -5.53mA    -3.669mA
-1.122V   -4.459mA   -5.111mA   -3.585mA
-1.063V   -4.44mA    -5.051mA   -4.34mA
-1.004V   -4.469mA   -4.987mA   -7.138mA
-945mV    -5.704mA   -4.919mA   -11.51mA
-826.9mV  -12.29mA   -5.465mA   -12.66mA
-708.7mV  -12.73mA   -10.26mA   -11.87mA
-590.6mV  -11.2mA    -10.83mA   -10.57mA
281.2mV   4.836mA    4.532mA    4.816mA
900mV     11.22mA    10.61mA    11.02mA
1.462V    12.71mA    12.12mA    12.3mA
3.6V      13.03mA    12.42mA    12.49mA
[Ramp]
dV/dt_r   0.352358/0.39114n  0.342183/0.463171n  0.40212/0.352417n
dV/dt_f   0.371254/0.399559n  0.348385/0.498442n  0.365259/0.397639n
R_load = 50
[Rising Waveform]
R_fixture = 50
V_fixture = 0
V_fixture_min = 0
V_fixture_max = 0
| Time   V(typ)   V(min)   V(max)
0s        21.05nV    53.17nV    27.92nV
1.57ns    -510.4uV   -469.7uV   -24.02mV
1.638ns   -532.5uV   -490.1uV   32.99mV
1.86ns    -3.214mV   -556.5uV   385.6mV
2.149ns   -14.65mV   -643uV     575.3mV
2.599ns   430.9mV    -6.668mV   647.4mV
2.911ns   533.5mV    -10.16mV   661.8mV
3.385ns   568.6mV    400mV      668.5mV
3.907ns   580.2mV    538.2mV    670.2mV
10ns      587.3mV    570.3mV    670.2mV
[Rising Waveform]
R_fixture = 50
V_fixture = 1.8
V_fixture_min = 1.71
V_fixture_max = 1.89
| Time   V(typ)   V(min)   V(max)
0s        1.181V     1.129V     1.281V
1.432ns   1.18V      1.129V     1.277V
1.695ns   1.179V     1.129V     1.701V
1.854ns   1.178V     1.129V     1.826V
2.095ns   1.52V      1.129V     1.875V
2.307ns   1.702V     1.126V     1.884V
2.526ns   1.77V      1.133V     1.887V
2.997ns   1.795V     1.578V     1.89V
3.402ns   1.799V     1.692V     1.89V
10ns      1.8V       1.71V      1.89V
[Falling Waveform]
R_fixture = 50
V_fixture = 0
V_fixture_min = 0
V_fixture_max = 0
| Time   V(typ)   V(min)   V(max)
0s        587.2mV    570.3mV    670.2mV
1.446ns   587.3mV    569.8mV    683.7mV
1.726ns   587.4mV    569.7mV    198mV
1.935ns   595.9mV    569.7mV    51.53mV
2.184ns   204.7mV    569.6mV    12.05mV
2.373ns   60.5mV     569.5mV    5.695mV
2.655ns   14mV       583.8mV    1.503mV
3.003ns   2.64mV     147.2mV    87.25uV
3.397ns   786.1uV    19.53mV    -137.6uV
10ns      1.496uV    1.773uV    -709.4nV
[Falling Waveform]
R_fixture = 50
V_fixture = 1.8
V_fixture_min = 1.71
V_fixture_max = 1.89
| Time   V(typ)   V(min)   V(max)
0s        1.8V       1.71V      1.89V
1.624ns   1.799V     1.71V      1.915V
2.067ns   1.826V     1.71V      1.461V
2.275ns   1.603V     1.71V      1.361V
2.47ns    1.394V     1.708V     1.329V
2.795ns   1.248V     1.741V     1.303V
2.924ns   1.223V     1.701V     1.299V
3.478ns   1.189V     1.279V     1.28V
3.972ns   1.183V     1.156V     1.281V
10ns      1.181V     1.129V     1.281V
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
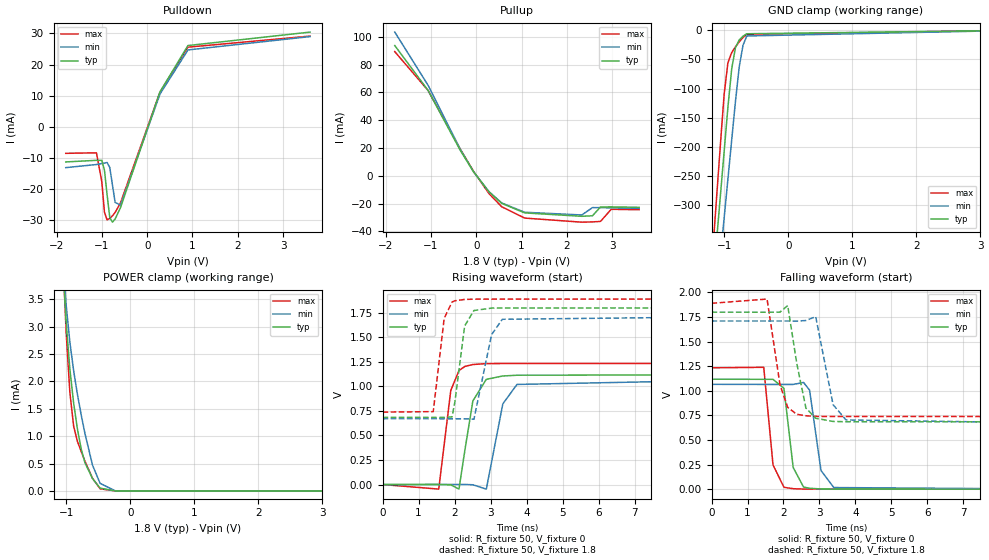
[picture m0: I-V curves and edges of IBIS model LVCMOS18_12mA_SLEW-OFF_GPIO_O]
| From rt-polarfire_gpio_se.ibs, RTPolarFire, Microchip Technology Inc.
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|   Model LVCMOS18_12mA_SLEW-OFF_GPIO_O
[Model]   LVCMOS18_12mA_SLEW-OFF_GPIO_O
Model_type   Output
Polarity   Non-Inverting
Enable   Active-High
Vmeas =   0.9
Cref =   5p
Rref =   1M
|   typ   min   max
C_comp_pullup   2.605e-12   2.605e-12   2.76e-12
C_comp_pulldown  2.605e-12   2.605e-12   2.76e-12
[Temperature Range]  25C   125C   -55C
[Voltage Range]  1.8   1.71   1.89
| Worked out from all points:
|   slope of the pulldown table from 0 to 0.27 V, typ, clamps not added: 25 ohm
|   slope of the pullup table from 0 to 0.27 V, typ, clamps not added: 24.2 ohm
|   GND clamp passes 1 mA (typ) near -0.52 V on its own axis
|   POWER clamp passes 1 mA (typ) near -0.81 V on its own axis
|   rising waveform, R_fixture 50, V_fixture 0: 20-80 % time 301ps typ, 342ps min, 247ps max; typ from 0 V to 1.12 V
|   rising waveform, R_fixture 50, V_fixture 1.8: 20-80 % time 230ps typ, 306ps min, 188ps max; typ from 0.684 V to 1.8 V
|   falling waveform, R_fixture 50, V_fixture 0: 20-80 % time 217ps typ, 246ps min, 177ps max; typ from 1.12 V to 0 V
|   falling waveform, R_fixture 50, V_fixture 1.8: 20-80 % time 283ps typ, 328ps min, 283ps max; typ from 1.8 V to 0.684 V
[GND Clamp]
| Voltage   I(typ)   I(min)   I(max)
-1.8V     -1.238A    -1.225A    -1.327A
-1.181V   -437.3mA   -523.2mA   -378.1mA
-1.122V   -361mA     -456.2mA   -287.7mA
-1.063V   -284.7mA   -389.3mA   -197.3mA
-1.004V   -208.5mA   -322.4mA   -110.3mA
-945mV    -132.4mA   -255.5mA   -55.69mA
-885.9mV  -66.33mA   -188.6mA   -38.3mA
-826.9mV  -29.63mA   -121.9mA   -28.32mA
-767.8mV  -16.36mA   -62.59mA   -19.64mA
-708.7mV  -10.12mA   -25.53mA   -12.4mA
-649.7mV  -5.882mA   -9.682mA   -6.873mA
3.6V      0A         0A         0A
[POWER Clamp]
| Voltage   I(typ)   I(min)   I(max)
-1.8V     45.61mA    34mA       62.13mA
-1.063V   4.301mA    4.351mA    4.537mA
-1.004V   3.099mA    3.407mA    2.918mA
-945mV    2.226mA    2.718mA    1.799mA
-885.9mV  1.604mA    2.194mA    1.183mA
-826.9mV  1.131mA    1.765mA    904.1uA
-767.8mV  765.5uA    1.388mA    720.7uA
-708.7mV  512.4uA    1.046mA    541.9uA
-590.6mV  225.1uA    468.8uA    230.2uA
-472.5mV  50.43uA    137.9uA    39.22uA
-236.2mV  31.79nA    2.799uA    286.2nA
3.6V      0A         0A         0A
[Pullup]
| Voltage   I(typ)   I(min)   I(max)
-1.8V     93.7mA     103.4mA    89.33mA
-1.063V   61.42mA    65.07mA    61.36mA
-354.4mV  18.39mA    19.13mA    19.29mA
-59.06mV  2.816mA    2.843mA    3.141mA
281.2mV   -11.55mA   -11.44mA   -12.84mA
562.5mV   -19.84mA   -19.56mA   -22.31mA
1.069V    -26.72mA   -26.26mA   -30.45mA
2.332V    -29.17mA   -28.22mA   -33.41mA
2.568V    -28.79mA   -22.89mA   -33.19mA
2.745V    -22.47mA   -22.95mA   -32.87mA
2.981V    -22.39mA   -23.1mA    -24.13mA
3.6V      -22.71mA   -23.44mA   -24.44mA
[Pulldown]
| Voltage   I(typ)   I(min)   I(max)
-1.8V     -11.28mA   -13.11mA   -8.516mA
-1.122V   -10.76mA   -12.11mA   -8.349mA
-1.004V   -10.76mA   -11.81mA   -17.55mA
-945mV    -13.88mA   -11.65mA   -27.42mA
-885.9mV  -21.9mA    -11.47mA   -29.89mA
-826.9mV  -29.15mA   -13.09mA   -29.41mA
-767.8mV  -30.63mA   -18.75mA   -28.58mA
-708.7mV  -29.59mA   -24.29mA   -27.5mA
-590.6mV  -25.96mA   -25.13mA   -24.42mA
281.2mV   11.21mA    10.51mA    11.13mA
900mV     26.1mA     24.69mA    25.58mA
3.6V      30.42mA    28.98mA    29.14mA
[Ramp]
dV/dt_r   0.670621/0.301311n  0.639435/0.342135n  0.740278/0.246713n
dV/dt_f   0.669523/0.283156n  0.623581/0.327939n  0.691057/0.282837n
R_load = 50
[Rising Waveform]
R_fixture = 50
V_fixture = 0
V_fixture_min = 0
V_fixture_max = 0
| Time   V(typ)   V(min)   V(max)
0s        12.66nV    32.43nV    16.84nV
1.561ns   857.6uV    493.9uV    -46.34mV
1.895ns   -3.045mV   599.5uV    958mV
2.123ns   -46.08mV   671.7uV    1.162V
2.29ns    357.5mV    724.5uV    1.204V
2.509ns   852.1mV    -2.388mV   1.223V
2.882ns   1.072V     -47.17mV   1.232V
3.341ns   1.106V     821.9mV    1.233V
3.734ns   1.114V     1.02V      1.233V
10ns      1.118V     1.066V     1.234V
[Rising Waveform]
R_fixture = 50
V_fixture = 1.8
V_fixture_min = 1.71
V_fixture_max = 1.89
| Time   V(typ)   V(min)   V(max)
0s        684.1mV    670.7mV    738.2mV
1.408ns   683.9mV    670.3mV    742.9mV
1.712ns   683.8mV    670.2mV    1.694V
1.931ns   689mV      670.1mV    1.86V
2.012ns   848.4mV    670.1mV    1.873V
2.28ns    1.615V     670mV      1.886V
2.538ns   1.773V     665.6mV    1.889V
3.029ns   1.798V     1.528V     1.889V
3.327ns   1.799V     1.684V     1.889V
10ns      1.8V       1.71V      1.89V
[Falling Waveform]
R_fixture = 50
V_fixture = 0
V_fixture_min = 0
V_fixture_max = 0
| Time   V(typ)   V(min)   V(max)
0s        1.118V     1.066V     1.234V
1.452ns   1.117V     1.065V     1.239V
1.71ns    1.117V     1.065V     246.9mV
2.014ns   1.025V     1.065V     19.22mV
2.271ns   220.8mV    1.065V     4.65mV
2.559ns   21.63mV    1.085V     1.173mV
2.727ns   8.853mV    1.008V     688.3uV
3.045ns   2.255mV    189.8mV    32.71uV
3.401ns   362.6uV    16.43mV    31.06uV
10ns      899.5nV    6.37uV     593.2nV
[Falling Waveform]
R_fixture = 50
V_fixture = 1.8
V_fixture_min = 1.71
V_fixture_max = 1.89
| Time   V(typ)   V(min)   V(max)
0s        1.8V       1.71V      1.89V
1.544ns   1.799V     1.71V      1.933V
1.904ns   1.8V       1.71V      1.062V
2.119ns   1.867V     1.71V      831.6mV
2.369ns   1.283V     1.709V     761.1mV
2.625ns   824.9mV    1.715V     746.3mV
2.898ns   721mV      1.754V     740.1mV
3.381ns   688.7mV    859.6mV    739.1mV
3.741ns   685.7mV    703.9mV    738.8mV
10ns      684.1mV    670.7mV    738.2mV
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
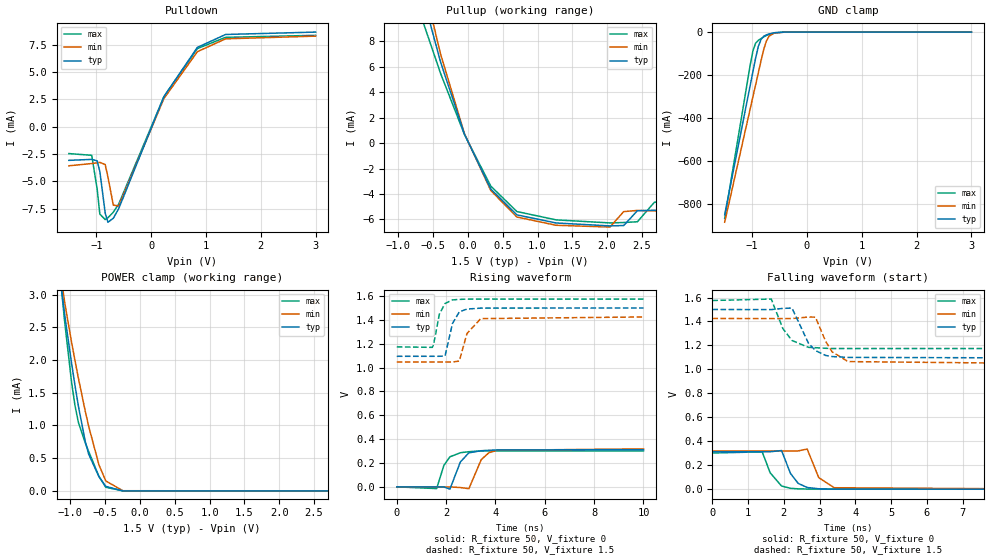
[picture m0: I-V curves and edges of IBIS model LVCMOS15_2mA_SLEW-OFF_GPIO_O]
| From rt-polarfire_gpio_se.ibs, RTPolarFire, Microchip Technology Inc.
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|   Model LVCMOS15_2mA_SLEW-OFF_GPIO_O
[Model]   LVCMOS15_2mA_SLEW-OFF_GPIO_O
Model_type   Output
Polarity   Non-Inverting
Enable   Active-High
Vmeas =   0.75
Cref =   5p
Rref =   1M
|   typ   min   max
C_comp_pullup   2.605e-12   2.605e-12   2.76e-12
C_comp_pulldown  2.605e-12   2.605e-12   2.76e-12
[Temperature Range]  25C   125C   -55C
[Voltage Range]  1.5   1.425   1.575
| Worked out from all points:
|   slope of the pulldown table from 0 to 0.225 V, typ, clamps not added: 84.8 ohm
|   slope of the pullup table from 0 to 0.225 V, typ, clamps not added: 84.7 ohm
|   GND clamp passes 1 mA (typ) near -0.52 V on its own axis
|   POWER clamp passes 1 mA (typ) near -0.84 V on its own axis
|   rising waveform, R_fixture 50, V_fixture 0: 20-80 % time 421ps typ, 449ps min, 363ps max; typ from 0 V to 0.312 V
|   rising waveform, R_fixture 50, V_fixture 1.5: 20-80 % time 301ps typ, 404ps min, 267ps max; typ from 1.09 V to 1.5 V
|   falling waveform, R_fixture 50, V_fixture 0: 20-80 % time 324ps typ, 305ps min, 298ps max; typ from 0.312 V to 0 V
|   falling waveform, R_fixture 50, V_fixture 1.5: 20-80 % time 429ps typ, 425ps min, 384ps max; typ from 1.5 V to 1.09 V
[GND Clamp]
| Voltage   I(typ)   I(min)   I(max)
-1.5V     -849.7mA   -884.3mA   -866.2mA
-1.034V   -246.6mA   -355.8mA   -152.2mA
-984.4mV  -183.1mA   -300.1mA   -86.85mA
-935.2mV  -119.9mA   -244.3mA   -51.18mA
-885.9mV  -66.33mA   -188.6mA   -38.3mA
-836.7mV  -33.59mA   -133mA     -29.88mA
-787.5mV  -19.44mA   -80.26mA   -22.39mA
-738.3mV  -12.87mA   -40.96mA   -15.82mA
-689.1mV  -8.545mA   -18.39mA   -10.35mA
-590.6mV  -2.947mA   -3.965mA   -3.201mA
-393.7mV  -37.64uA   -97.05uA   -25.54uA
3V        0A         0A         0A
[POWER Clamp]
| Voltage   I(typ)   I(min)   I(max)
-1.5V     10.9mA     9.514mA    12.44mA
-1.181V   3.55mA     3.619mA    3.649mA
-1.083V   2.694mA    2.882mA    2.584mA
-984.4mV  1.956mA    2.276mA    1.667mA
-935.2mV  1.615mA    1.995mA    1.306mA
-885.9mV  1.297mA    1.724mA    1.047mA
-787.5mV  756.7uA    1.22mA     734.9uA
-738.3mV  562.1uA    988.5uA    604.8uA
-590.6mV  217.4uA    399.3uA    223.5uA
-492.2mV  69.4uA     152.5uA    55.95uA
-246.1mV  138.9nA    3.06uA     38.13nA
3V        0A         0A         0A
[Pullup]
| Voltage   I(typ)   I(min)   I(max)
-1.5V     28.19mA    32.3mA     22.21mA
-1.083V   20.35mA    22.65mA    16.54mA
-393.7mV  6.373mA    7.003mA    5.481mA
-49.22mV  687.4uA    724uA      661.4uA
328.1mV   -3.607mA   -3.725mA   -3.379mA
703.1mV   -5.639mA   -5.808mA   -5.377mA
1.266V    -6.276mA   -6.456mA   -6.032mA
2.041V    -6.508mA   -6.597mA   -6.272mA
2.238V    -6.476mA   -5.383mA   -6.24mA
2.435V    -5.314mA   -5.291mA   -6.181mA
2.681V    -5.276mA   -5.327mA   -4.639mA
3V        -5.318mA   -5.369mA   -4.672mA
[Pulldown]
| Voltage   I(typ)   I(min)   I(max)
-1.5V     -3.075mA   -3.572mA   -2.455mA
-1.083V   -2.985mA   -3.365mA   -2.614mA
-984.4mV  -3.121mA   -3.295mA   -5.676mA
-935.2mV  -4.081mA   -3.257mA   -7.984mA
-836.7mV  -7.901mA   -3.46mA    -8.483mA
-787.5mV  -8.722mA   -4.593mA   -8.311mA
-689.1mV  -8.363mA   -7.168mA   -7.811mA
-590.6mV  -7.483mA   -7.233mA   -7.064mA
234.4mV   2.752mA    2.577mA    2.747mA
843.8mV   7.243mA    6.851mA    7.129mA
1.359V    8.423mA    8.025mA    8.162mA
3V        8.641mA    8.272mA    8.345mA
[Ramp]
dV/dt_r   0.187103/0.420555n  0.19113/0.448574n  0.181069/0.363484n
dV/dt_f   0.242793/0.428966n  0.226646/0.425377n  0.240701/0.38409n
R_load = 50
[Rising Waveform]
R_fixture = 50
V_fixture = 0
V_fixture_min = 0
V_fixture_max = 0
| Time   V(typ)   V(min)   V(max)
0s        23.55nV    60.81nV    31.39nV
1.615ns   -830.8uV   -485.3uV   -14.57mV
1.909ns   -982.1uV   -573.7uV   179.8mV
2.153ns   -19.46mV   -647uV     251.8mV
2.577ns   208.7mV    -5.644mV   286mV
2.922ns   285.4mV    -15.53mV   295mV
3.423ns   302.9mV    228.4mV    301.1mV
3.734ns   306.6mV    286.1mV    301.1mV
4.059ns   309.4mV    306.7mV    301.1mV
10ns      311.8mV    318.5mV    301.8mV
[Rising Waveform]
R_fixture = 50
V_fixture = 1.5
V_fixture_min = 1.425
V_fixture_max = 1.575
| Time   V(typ)   V(min)   V(max)
0s        1.095V     1.047V     1.174V
1.44ns    1.095V     1.047V     1.17V
1.489ns   1.095V     1.047V     1.19V
1.726ns   1.095V     1.047V     1.448V
1.956ns   1.098V     1.047V     1.538V
2.258ns   1.37V      1.047V     1.568V
2.535ns   1.468V     1.055V     1.572V
2.845ns   1.491V     1.286V     1.575V
3.404ns   1.499V     1.411V     1.575V
10ns      1.5V       1.425V     1.575V
[Falling Waveform]
R_fixture = 50
V_fixture = 0
V_fixture_min = 0
V_fixture_max = 0
| Time   V(typ)   V(min)   V(max)
0s        311.8mV    318.5mV    301.8mV
1.394ns   312.3mV    318.9mV    311.5mV
1.617ns   312.3mV    319mV      136.9mV
1.936ns   322.5mV    319mV      26.26mV
2.186ns   131.5mV    319.1mV    7.175mV
2.403ns   47.89mV    319.2mV    2.774mV
2.653ns   14.04mV    335.2mV    1.114mV
2.977ns   3.262mV    95.98mV    -14.17uV
3.41ns    431.1uV    11.92mV    -16.59uV
10ns      1.291uV    4.09uV     -387.1nV
[Falling Waveform]
R_fixture = 50
V_fixture = 1.5
V_fixture_min = 1.425
V_fixture_max = 1.575
| Time   V(typ)   V(min)   V(max)
0s        1.5V       1.425V     1.575V
1.648ns   1.499V     1.424V     1.587V
1.972ns   1.509V     1.424V     1.341V
2.228ns   1.512V     1.424V     1.241V
2.688ns   1.219V     1.437V     1.184V
2.884ns   1.157V     1.436V     1.181V
3.171ns   1.116V     1.233V     1.176V
3.353ns   1.107V     1.146V     1.174V
3.797ns   1.1V       1.065V     1.174V
10ns      1.095V     1.047V     1.174V
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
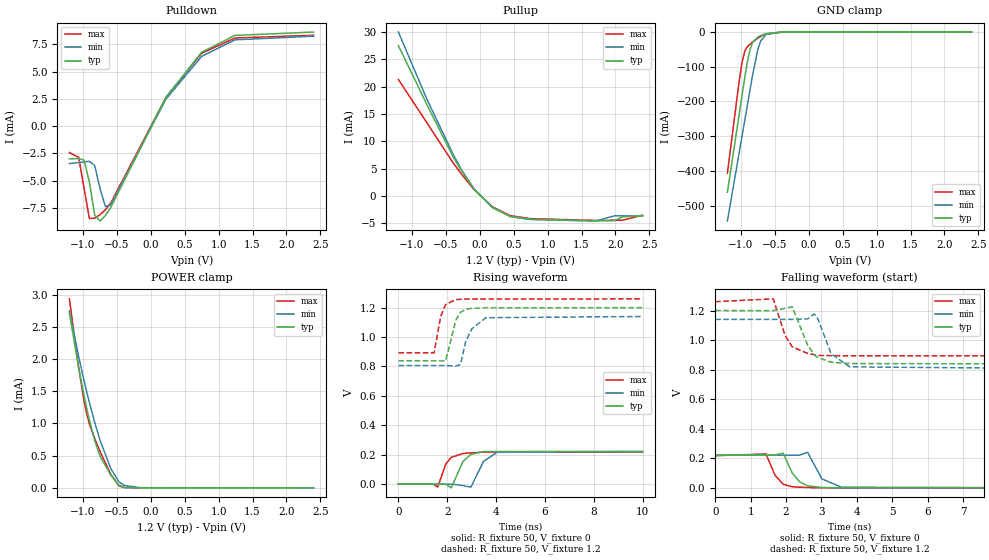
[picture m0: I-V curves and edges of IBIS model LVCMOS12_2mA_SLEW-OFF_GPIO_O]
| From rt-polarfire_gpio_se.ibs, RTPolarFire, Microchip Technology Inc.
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|   Model LVCMOS12_2mA_SLEW-OFF_GPIO_O
[Model]   LVCMOS12_2mA_SLEW-OFF_GPIO_O
Model_type   Output
Polarity   Non-Inverting
Enable   Active-High
Vmeas =   0.6
Cref =   5p
Rref =   1M
|   typ   min   max
C_comp_pullup   2.605e-12   2.605e-12   2.76e-12
C_comp_pulldown  2.605e-12   2.605e-12   2.76e-12
[Temperature Range]  25C   125C   -55C
[Voltage Range]  1.2   1.14   1.26
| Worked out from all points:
|   slope of the pulldown table from 0 to 0.18 V, typ, clamps not added: 83 ohm
|   slope of the pullup table from 0 to 0.18 V, typ, clamps not added: 86.5 ohm
|   GND clamp passes 1 mA (typ) near -0.52 V on its own axis
|   POWER clamp passes 1 mA (typ) near -0.89 V on its own axis
|   rising waveform, R_fixture 50, V_fixture 0: 20-80 % time 401ps typ, 441ps min, 355ps max; typ from 0 V to 0.222 V
|   rising waveform, R_fixture 50, V_fixture 1.2: 20-80 % time 324ps typ, 439ps min, 268ps max; typ from 0.839 V to 1.2 V
|   falling waveform, R_fixture 50, V_fixture 0: 20-80 % time 351ps typ, 337ps min, 295ps max; typ from 0.222 V to 0 V
|   falling waveform, R_fixture 50, V_fixture 1.2: 20-80 % time 385ps typ, 383ps min, 354ps max; typ from 1.2 V to 0.839 V
[GND Clamp]
| Voltage   I(typ)   I(min)   I(max)
-1.2V     -461.6mA   -544.4mA   -406.8mA
-1.024V   -233.9mA   -344.7mA   -137.6mA
-984.4mV  -183.1mA   -300.1mA   -86.85mA
-945mV    -132.4mA   -255.5mA   -55.69mA
-905.6mV  -85.65mA   -210.9mA   -42.32mA
-866.2mV  -50.48mA   -166.3mA   -34.78mA
-826.9mV  -29.63mA   -121.9mA   -28.32mA
-748.1mV  -13.93mA   -47.49mA   -17.05mA
-708.7mV  -10.12mA   -25.53mA   -12.4mA
-630mV    -4.768mA   -7.139mA   -5.445mA
-393.7mV  -37.64uA   -97.05uA   -25.54uA
2.4V      0A         0A         0A
[POWER Clamp]
| Voltage   I(typ)   I(min)   I(max)
-1.2V     2.715mA    2.748mA    2.936mA
-1.063V   1.865mA    2.037mA    1.863mA
-984.4mV  1.435mA    1.667mA    1.351mA
-945mV    1.238mA    1.493mA    1.151mA
-905.6mV  1.055mA    1.327mA    995uA
-826.9mV  734.5uA    1.017mA    763.7uA
-748.1mV  493.1uA    740.4uA    565.4uA
-590.6mV  198.3uA    300.1uA    209.7uA
-472.5mV  46.9uA     96.39uA    34.24uA
-393.7mV  7.199uA    38.25uA    3.725uA
-157.5mV  27.24nA    2.66uA     137.5nA
2.4V      0A         0A         0A
[Pullup]
| Voltage   I(typ)   I(min)   I(max)
-1.2V     27.53mA    30.03mA    21.33mA
-787.5mV  16.92mA    17.93mA    13.54mA
-393.7mV  7.172mA    7.638mA    6.056mA
-275.6mV  4.676mA    4.9mA      4.06mA
-78.75mV  1.158mA    1.179mA    1.058mA
187.5mV   -2.153mA   -2.149mA   -2.021mA
450mV     -3.789mA   -3.795mA   -3.632mA
750mV     -4.311mA   -4.324mA   -4.184mA
1.712V    -4.614mA   -4.594mA   -4.505mA
1.988V    -4.533mA   -3.661mA   -4.485mA
2.106V    -3.839mA   -3.671mA   -4.471mA
2.4V      -3.666mA   -3.703mA   -3.552mA
[Pulldown]
| Voltage   I(typ)   I(min)   I(max)
-1.2V     -3.01mA    -3.44mA    -2.425mA
-1.063V   -2.981mA   -3.351mA   -2.878mA
-984.4mV  -3.121mA   -3.295mA   -5.676mA
-905.6mV  -5.132mA   -3.233mA   -8.493mA
-826.9mV  -8.174mA   -3.615mA   -8.453mA
-748.1mV  -8.716mA   -5.757mA   -8.137mA
-669.4mV  -8.208mA   -7.386mA   -7.683mA
-590.6mV  -7.483mA   -7.233mA   -7.064mA
225mV     2.654mA    2.485mA    2.65mA
750mV     6.782mA    6.403mA    6.686mA
1.239V    8.326mA    7.918mA    8.088mA
2.4V      8.637mA    8.254mA    8.341mA
[Ramp]
dV/dt_r   0.13305/0.400691n  0.132644/0.441498n  0.130247/0.354564n
dV/dt_f   0.216628/0.384966n  0.200319/0.382658n  0.219907/0.354103n
R_load = 50
[Rising Waveform]
R_fixture = 50
V_fixture = 0
V_fixture_min = 0
V_fixture_max = 0
| Time   V(typ)   V(min)   V(max)
0s        21.82nV    58.39nV    29nV
1.431ns   -661.3uV   -299.8uV   -440.2uV
1.609ns   -743.5uV   -337.1uV   -21.15mV
1.941ns   -1.663mV   -406.6uV   136.5mV
2.165ns   -26.03mV   -453.6uV   181.4mV
2.645ns   153.6mV    -10.18mV   207.6mV
2.967ns   201.6mV    -21.81mV   212.5mV
3.488ns   220.8mV    154.6mV    216.8mV
4.04ns    220.9mV    215.7mV    216.8mV
10ns      221.8mV    221.1mV    217.1mV
[Rising Waveform]
R_fixture = 50
V_fixture = 1.2
V_fixture_min = 1.14
V_fixture_max = 1.26
| Time   V(typ)   V(min)   V(max)
0s        838.9mV    806.1mV    893.5mV
1.465ns   838.3mV    805.9mV    893.4mV
1.729ns   838.2mV    805.9mV    1.139V
1.935ns   837.2mV    805.9mV    1.222V
2.35ns    1.115V     802.6mV    1.255V
2.547ns   1.169V     813.3mV    1.257V
2.76ns    1.189V     971.9mV    1.259V
3.012ns   1.196V     1.057V     1.259V
3.581ns   1.199V     1.132V     1.259V
10ns      1.2V       1.14V      1.26V
[Falling Waveform]
R_fixture = 50
V_fixture = 0
V_fixture_min = 0
V_fixture_max = 0
| Time   V(typ)   V(min)   V(max)
0s        221.8mV    221.1mV    217.1mV
1.434ns   222.1mV    221.1mV    229.1mV
1.688ns   222.2mV    221.1mV    85.68mV
1.919ns   234.3mV    221mV      24mV
2.181ns   97.91mV    221mV      7.085mV
2.386ns   40.25mV    221mV      4.032mV
2.61ns    13.3mV     240.4mV    2.065mV
3.013ns   1.87mV     60.21mV    -330.2uV
3.563ns   -56.34uV   4.316mV    -303.7uV
10ns      -1.494uV   -9.139uV   6.358uV
[Falling Waveform]
R_fixture = 50
V_fixture = 1.2
V_fixture_min = 1.14
V_fixture_max = 1.26
| Time   V(typ)   V(min)   V(max)
0s        1.2V       1.14V      1.26V
1.639ns   1.199V     1.14V      1.279V
1.974ns   1.215V     1.14V      1.031V
2.176ns   1.225V     1.14V      954.4mV
2.606ns   968.2mV    1.143V     910.1mV
2.802ns   898.6mV    1.177V     901.1mV
2.907ns   880.9mV    1.139V     896.2mV
3.274ns   849.9mV    908.2mV    894.8mV
3.793ns   841mV      818.9mV    893.7mV
10ns      839mV      806.1mV    893.5mV
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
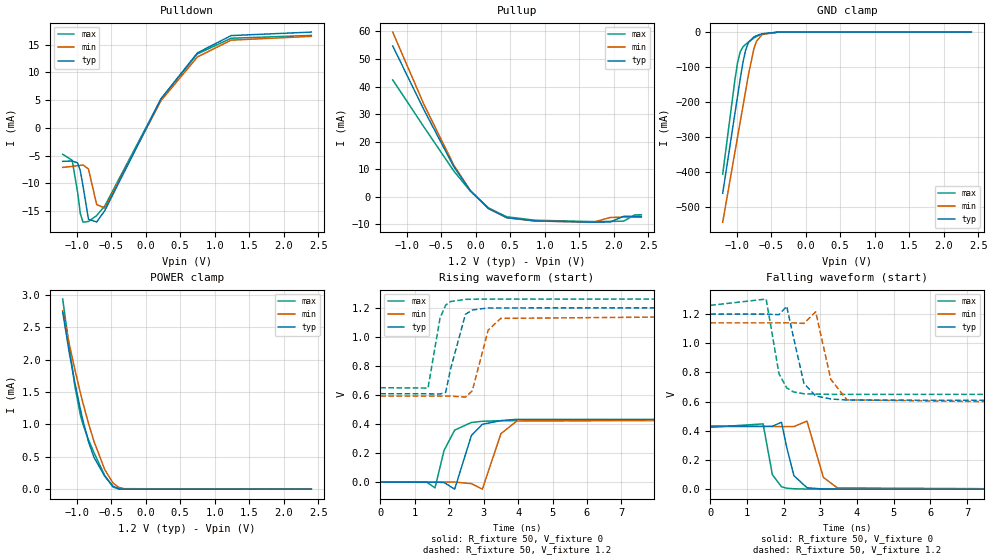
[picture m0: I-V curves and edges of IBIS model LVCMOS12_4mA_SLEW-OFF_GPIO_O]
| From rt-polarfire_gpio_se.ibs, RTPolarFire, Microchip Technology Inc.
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|   Model LVCMOS12_4mA_SLEW-OFF_GPIO_O
[Model]   LVCMOS12_4mA_SLEW-OFF_GPIO_O
Model_type   Output
Polarity   Non-Inverting
Enable   Active-High
Vmeas =   0.6
Cref =   5p
Rref =   1M
|   typ   min   max
C_comp_pullup   2.605e-12   2.605e-12   2.76e-12
C_comp_pulldown  2.605e-12   2.605e-12   2.76e-12
[Temperature Range]  25C   125C   -55C
[Voltage Range]  1.2   1.14   1.26
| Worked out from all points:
|   slope of the pulldown table from 0 to 0.18 V, typ, clamps not added: 41.7 ohm
|   slope of the pullup table from 0 to 0.18 V, typ, clamps not added: 43.4 ohm
|   GND clamp passes 1 mA (typ) near -0.52 V on its own axis
|   POWER clamp passes 1 mA (typ) near -0.89 V on its own axis
|   rising waveform, R_fixture 50, V_fixture 0: 20-80 % time 364ps typ, 398ps min, 340ps max; typ from 0 V to 0.432 V
|   rising waveform, R_fixture 50, V_fixture 1.2: 20-80 % time 323ps typ, 375ps min, 264ps max; typ from 0.609 V to 1.2 V
|   falling waveform, R_fixture 50, V_fixture 0: 20-80 % time 255ps typ, 315ps min, 191ps max; typ from 0.432 V to 0 V
|   falling waveform, R_fixture 50, V_fixture 1.2: 20-80 % time 311ps typ, 314ps min, 264ps max; typ from 1.2 V to 0.608 V
[GND Clamp]
| Voltage   I(typ)   I(min)   I(max)
-1.2V     -461.6mA   -544.4mA   -406.8mA
-1.024V   -233.9mA   -344.7mA   -137.6mA
-984.4mV  -183.1mA   -300.1mA   -86.85mA
-945mV    -132.4mA   -255.5mA   -55.69mA
-905.6mV  -85.65mA   -210.9mA   -42.32mA
-866.2mV  -50.48mA   -166.3mA   -34.78mA
-826.9mV  -29.63mA   -121.9mA   -28.32mA
-748.1mV  -13.93mA   -47.49mA   -17.05mA
-708.7mV  -10.12mA   -25.53mA   -12.4mA
-630mV    -4.768mA   -7.139mA   -5.445mA
-393.7mV  -37.64uA   -97.05uA   -25.54uA
2.4V      0A         0A         0A
[POWER Clamp]
| Voltage   I(typ)   I(min)   I(max)
-1.2V     2.73mA     2.755mA    2.936mA
-1.103V   2.096mA    2.232mA    2.178mA
-1.024V   1.644mA    1.848mA    1.59mA
-945mV    1.238mA    1.493mA    1.151mA
-905.6mV  1.055mA    1.327mA    995uA
-826.9mV  734.5uA    1.017mA    763.7uA
-748.1mV  493.1uA    740.4uA    565.4uA
-590.6mV  198.3uA    300.1uA    209.7uA
-472.5mV  46.9uA     96.39uA    34.24uA
-393.7mV  7.199uA    29.56uA    3.725uA
-315mV    557nA      7.444uA    150.8nA
2.4V      0A         0A         0A
[Pullup]
| Voltage   I(typ)   I(min)   I(max)
-1.2V     54.7mA     59.74mA    42.4mA
-748.1mV  31.55mA    33.5mA     25.34mA
-315mV    10.89mA    11.48mA    9.348mA
-78.75mV  2.306mA    2.351mA    2.106mA
187.5mV   -4.291mA   -4.288mA   -4.03mA
450mV     -7.565mA   -7.585mA   -7.252mA
862.5mV   -8.754mA   -8.787mA   -8.515mA
1.712V    -9.217mA   -9.191mA   -9.005mA
1.948V    -9.14mA    -7.514mA   -8.945mA
2.145V    -7.088mA   -7.389mA   -8.834mA
2.303V    -7.078mA   -7.424mA   -6.59mA
2.4V      -7.096mA   -7.446mA   -6.507mA
[Pulldown]
| Voltage   I(typ)   I(min)   I(max)
-1.2V     -6.012mA   -7.104mA   -4.745mA
-1.063V   -5.953mA   -6.92mA    -5.827mA
-984.4mV  -6.289mA   -6.8mA     -11.57mA
-945mV    -7.716mA   -6.737mA   -15.42mA
-905.6mV  -10.49mA   -6.67mA    -16.98mA
-826.9mV  -16.46mA   -7.399mA   -16.85mA
-708.7mV  -16.94mA   -13.79mA   -15.79mA
-590.6mV  -14.89mA   -14.44mA   -14.05mA
225mV     5.282mA    4.956mA    5.271mA
750mV     13.53mA    12.79mA    13.34mA
1.239V    16.65mA    15.83mA    16.17mA
2.4V      17.28mA    16.51mA    16.68mA
[Ramp]
dV/dt_r   0.259234/0.364259n  0.257761/0.397931n  0.25455/0.339783n
dV/dt_f   0.354905/0.310705n  0.328674/0.31406n  0.36621/0.26382n
R_load = 50
[Rising Waveform]
R_fixture = 50
V_fixture = 0
V_fixture_min = 0
V_fixture_max = 0
| Time   V(typ)   V(min)   V(max)
0s        15.63nV    42.24nV    20.77nV
1.352ns   -709.5uV   421.8uV    -891.2uV
1.589ns   -833.9uV   495.8uV    -39.38mV
1.851ns   -2.09mV    577.5uV    218.1mV
2.159ns   -48.23mV   673.6uV    358.2mV
2.645ns   321.1mV    -10.21mV   410.7mV
2.963ns   398.1mV    -48.23mV   418.9mV
3.501ns   423.6mV    333.5mV    422.8mV
3.969ns   432.4mV    421.6mV    423.4mV
10ns      432.1mV    429.6mV    424.3mV
[Rising Waveform]
R_fixture = 50
V_fixture = 1.2
V_fixture_min = 1.14
V_fixture_max = 1.26
| Time   V(typ)   V(min)   V(max)
0s        608.5mV    592.2mV    649.7mV
1.386ns   607.9mV    592.3mV    647.7mV
1.734ns   606.4mV    592.3mV    1.128V
1.897ns   617.2mV    592.3mV    1.218V
2.037ns   775.6mV    592.3mV    1.243V
2.472ns   1.155V     585.3mV    1.258V
2.67ns    1.185V     628.5mV    1.259V
3.132ns   1.199V     1.046V     1.26V
3.497ns   1.199V     1.127V     1.26V
10ns      1.2V       1.14V      1.26V
[Falling Waveform]
R_fixture = 50
V_fixture = 0
V_fixture_min = 0
V_fixture_max = 0
| Time   V(typ)   V(min)   V(max)
0s        432mV      429.4mV    424.2mV
1.44ns    431.4mV    428.9mV    447.4mV
1.693ns   431.3mV    428.8mV    99.44mV
1.942ns   458.4mV    428.7mV    16.51mV
2.088ns   282.2mV    428.7mV    6.292mV
2.281ns   92.29mV    428.6mV    2.823mV
2.636ns   9.856mV    466.7mV    697.2uV
3.084ns   964uV      80.51mV    654.8uV
3.464ns   4.116uV    8.688mV    618.8uV
10ns      -2.69uV    -11.67uV   -412.1nV
[Falling Waveform]
R_fixture = 50
V_fixture = 1.2
V_fixture_min = 1.14
V_fixture_max = 1.26
| Time   V(typ)   V(min)   V(max)
0s        1.2V       1.14V      1.26V
1.524ns   1.2V       1.14V      1.303V
1.873ns   1.196V     1.14V      790.8mV
2.084ns   1.253V     1.14V      694mV
2.272ns   1.037V     1.14V      666.3mV
2.553ns   725.6mV    1.136V     653.9mV
2.873ns   639mV      1.216V     651.5mV
3.286ns   618.4mV    752.8mV    649.8mV
3.728ns   610.7mV    611.8mV    649.8mV
10ns      608.5mV    592.2mV    649.6mV
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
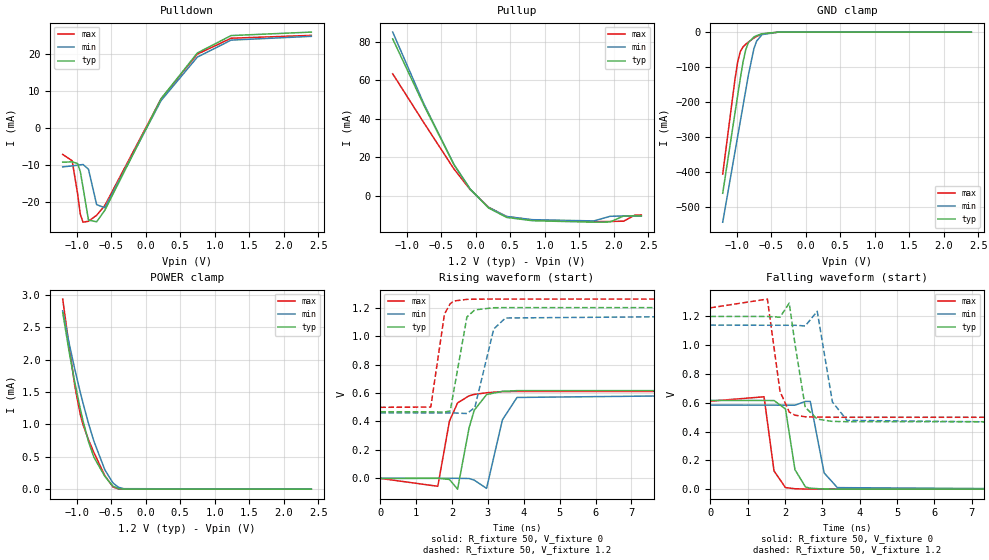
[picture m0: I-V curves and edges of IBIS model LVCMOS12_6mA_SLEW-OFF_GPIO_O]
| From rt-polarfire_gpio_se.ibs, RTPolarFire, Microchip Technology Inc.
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|   Model LVCMOS12_6mA_SLEW-OFF_GPIO_O
[Model]   LVCMOS12_6mA_SLEW-OFF_GPIO_O
Model_type   Output
Polarity   Non-Inverting
Enable   Active-High
Vmeas =   0.6
Cref =   5p
Rref =   1M
|   typ   min   max
C_comp_pullup   2.605e-12   2.605e-12   2.76e-12
C_comp_pulldown  2.605e-12   2.605e-12   2.76e-12
[Temperature Range]  25C   125C   -55C
[Voltage Range]  1.2   1.14   1.26
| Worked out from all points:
|   slope of the pulldown table from 0 to 0.18 V, typ, clamps not added: 27.9 ohm
|   slope of the pullup table from 0 to 0.18 V, typ, clamps not added: 29 ohm
|   GND clamp passes 1 mA (typ) near -0.52 V on its own axis
|   POWER clamp passes 1 mA (typ) near -0.89 V on its own axis
|   rising waveform, R_fixture 50, V_fixture 0: 20-80 % time 325ps typ, 354ps min, 327ps max; typ from 0 V to 0.617 V
|   rising waveform, R_fixture 50, V_fixture 1.2: 20-80 % time 268ps typ, 384ps min, 231ps max; typ from 0.468 V to 1.2 V
|   falling waveform, R_fixture 50, V_fixture 0: 20-80 % time 234ps typ, 272ps min, 184ps max; typ from 0.617 V to 0 V
|   falling waveform, R_fixture 50, V_fixture 1.2: 20-80 % time 239ps typ, 264ps min, 236ps max; typ from 1.2 V to 0.468 V
[GND Clamp]
| Voltage   I(typ)   I(min)   I(max)
-1.2V     -461.6mA   -544.4mA   -406.8mA
-1.024V   -233.9mA   -344.7mA   -137.6mA
-984.4mV  -183.1mA   -300.1mA   -86.85mA
-945mV    -132.4mA   -255.5mA   -55.69mA
-905.6mV  -85.65mA   -210.9mA   -42.32mA
-866.2mV  -50.48mA   -166.3mA   -34.78mA
-826.9mV  -29.63mA   -121.9mA   -28.32mA
-748.1mV  -13.93mA   -47.49mA   -17.05mA
-708.7mV  -10.12mA   -25.53mA   -12.4mA
-630mV    -4.768mA   -7.139mA   -5.445mA
-393.7mV  -37.64uA   -97.05uA   -25.54uA
2.4V      0A         0A         0A
[POWER Clamp]
| Voltage   I(typ)   I(min)   I(max)
-1.2V     2.73mA     2.755mA    2.936mA
-1.103V   2.096mA    2.232mA    2.178mA
-1.024V   1.644mA    1.848mA    1.59mA
-945mV    1.238mA    1.493mA    1.151mA
-905.6mV  1.055mA    1.327mA    995uA
-826.9mV  734.5uA    1.017mA    763.7uA
-748.1mV  493.1uA    740.4uA    565.4uA
-590.6mV  198.3uA    300.1uA    209.7uA
-472.5mV  46.9uA     96.39uA    34.24uA
-393.7mV  7.199uA    29.56uA    3.725uA
-315mV    556.7nA    7.444uA    150.8nA
2.4V      0A         0A         0A
[Pullup]
| Voltage   I(typ)   I(min)   I(max)
-1.2V     81.55mA    85.1mA     63.39mA
-748.1mV  46.99mA    47.73mA    37.88mA
-315mV    16.24mA    16.36mA    13.98mA
-78.75mV  3.443mA    3.354mA    3.151mA
187.5mV   -6.419mA   -6.126mA   -6.035mA
450mV     -11.33mA   -10.85mA   -10.87mA
825mV     -13.06mA   -12.52mA   -12.71mA
1.712V    -13.82mA   -13.16mA   -13.51mA
1.948V    -13.7mA    -10.76mA   -13.44mA
2.145V    -10.59mA   -10.57mA   -13.29mA
2.303V    -10.56mA   -10.62mA   -10.18mA
2.4V      -10.59mA   -10.65mA   -10.06mA
[Pulldown]
| Voltage   I(typ)   I(min)   I(max)
-1.2V     -9.275mA   -10.54mA   -7.169mA
-1.063V   -9.183mA   -10.27mA   -8.875mA
-984.4mV  -9.613mA   -10.09mA   -17.78mA
-945mV    -11.82mA   -9.995mA   -23.39mA
-905.6mV  -16.11mA   -9.896mA   -25.5mA
-826.9mV  -24.92mA   -11.17mA   -25.24mA
-708.7mV  -25.4mA    -20.76mA   -23.63mA
-590.6mV  -22.29mA   -21.58mA   -21mA
225mV     7.904mA    7.404mA    7.872mA
750mV     20.27mA    19.15mA    19.96mA
1.239V    24.97mA    23.74mA    24.25mA
2.4V      25.91mA    24.76mA    25.02mA
[Ramp]
dV/dt_r   0.370082/0.324914n  0.350979/0.354044n  0.366839/0.326678n
dV/dt_f   0.439032/0.238746n  0.407719/0.263973n  0.456271/0.235787n
R_load = 50
[Rising Waveform]
R_fixture = 50
V_fixture = 0
V_fixture_min = 0
V_fixture_max = 0
| Time   V(typ)   V(min)   V(max)
0s        12.16nV    33.14nV    16.19nV
1.603ns   867.6uV    572.4uV    -55.55mV
1.927ns   -7.481mV   688.1uV    402.4mV
2.154ns   -75.73mV   769.1uV    530.4mV
2.475ns   355.7mV    -972.6uV   580.3mV
2.618ns   478.7mV    -12.25mV   590.1mV
2.962ns   589mV      -70.08mV   601.7mV
3.403ns   611.5mV    411.3mV    610mV
3.81ns    616.6mV    568.7mV    610.3mV
10ns      616.8mV    585mV      611.4mV
[Rising Waveform]
R_fixture = 50
V_fixture = 1.2
V_fixture_min = 1.14
V_fixture_max = 1.26
| Time   V(typ)   V(min)   V(max)
0s        468.3mV    460.5mV    499.5mV
1.407ns   467.9mV    460.1mV    501.1mV
1.789ns   465.9mV    459.9mV    1.155V
1.948ns   473.9mV    459.9mV    1.227V
2.041ns   604.8mV    459.9mV    1.246V
2.414ns   1.134V     455.7mV    1.258V
2.634ns   1.184V     497.9mV    1.259V
3.162ns   1.199V     1.05V      1.26V
3.488ns   1.2V       1.127V     1.26V
10ns      1.2V       1.14V      1.26V
[Falling Waveform]
R_fixture = 50
V_fixture = 0
V_fixture_min = 0
V_fixture_max = 0
| Time   V(typ)   V(min)   V(max)
0s        616.8mV    584.2mV    611.4mV
1.439ns   616.1mV    583.8mV    641.9mV
1.706ns   615.9mV    583.7mV    126.7mV
2.013ns   557.1mV    583.6mV    10.77mV
2.267ns   135.2mV    583.5mV    2.832mV
2.549ns   14.96mV    610.1mV    619.4uV
2.677ns   6.523mV    609.7mV    351.6uV
3.048ns   777.4uV    112.7mV    -73.44uV
3.402ns   -129.7uV   10.52mV    -69.69uV
10ns      88.96nV    -26.67uV   176.3nV
[Falling Waveform]
R_fixture = 50
V_fixture = 1.2
V_fixture_min = 1.14
V_fixture_max = 1.26
| Time   V(typ)   V(min)   V(max)
0s        1.2V       1.14V      1.26V
1.529ns   1.2V       1.139V     1.321V
1.866ns   1.195V     1.139V     679.5mV
2.114ns   1.293V     1.139V     535.5mV
2.27ns    1.004V     1.139V     513.7mV
2.541ns   569.1mV    1.134V     503mV
2.863ns   486.7mV    1.236V     500.8mV
3.269ns   470.7mV    606mV      499.6mV
3.66ns    469mV      477.9mV    499.6mV
10ns      468.3mV    460.5mV    499.5mV
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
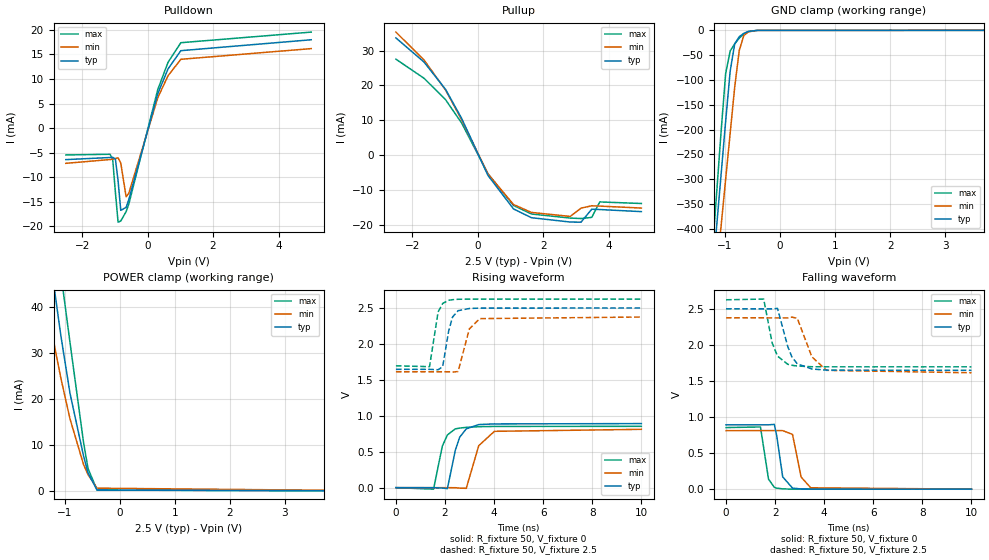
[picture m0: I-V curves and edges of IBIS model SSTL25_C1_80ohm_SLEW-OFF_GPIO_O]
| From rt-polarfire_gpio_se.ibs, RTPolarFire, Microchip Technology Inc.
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|   Model SSTL25_C1_80ohm_SLEW-OFF_GPIO_O
[Model]   SSTL25_C1_80ohm_SLEW-OFF_GPIO_O
Model_type   Output
Polarity   Non-Inverting
Enable   Active-High
Vmeas =   1.25
Cref =   5p
Rref =   50
Vref =   1.25
|   typ   min   max
C_comp_pullup   2.605e-12   2.605e-12   2.76e-12
C_comp_pulldown  2.605e-12   2.605e-12   2.76e-12
[Temperature Range]  25C   125C   -55C
[Voltage Range]  2.5   2.375   2.625
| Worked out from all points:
|   slope of the pulldown table from 0 to 0.375 V, typ, clamps not added: 45.8 ohm
|   slope of the pullup table from 0 to 0.375 V, typ, clamps not added: 55 ohm
|   GND clamp passes 1 mA (typ) near -0.51 V on its own axis
|   POWER clamp passes 1 mA (typ) near -0.47 V on its own axis
|   rising waveform, R_fixture 50, V_fixture 0: 20-80 % time 390ps typ, 451ps min, 347ps max; typ from 0 V to 0.892 V
|   rising waveform, R_fixture 50, V_fixture 2.5: 20-80 % time 281ps typ, 340ps min, 244ps max; typ from 1.65 V to 2.5 V
|   falling waveform, R_fixture 50, V_fixture 0: 20-80 % time 228ps typ, 287ps min, 188ps max; typ from 0.892 V to 0 V
|   falling waveform, R_fixture 50, V_fixture 2.5: 20-80 % time 453ps typ, 546ps min, 380ps max; typ from 2.5 V to 1.65 V
[GND Clamp]
| Voltage   I(typ)   I(min)   I(max)
-2.5V     -2.154A    -2.028A    -2.413A
-1.23V    -500.9mA   -578.9mA   -453.4mA
-1.148V   -394.9mA   -486mA     -327.9mA
-1.066V   -289mA     -393mA     -202.4mA
-984.4mV  -183.1mA   -300.1mA   -86.85mA
-902.3mV  -82.21mA   -207.2mA   -41.59mA
-820.3mV  -27.37mA   -114.5mA   -27.29mA
-738.3mV  -12.87mA   -40.96mA   -15.82mA
-656.2mV  -6.285mA   -10.74mA   -7.396mA
-574.2mV  -2.342mA   -3.102mA   -2.493mA
-410.2mV  -62.85uA   -143.8uA   -47.39uA
5V        0A         0A         0A
[POWER Clamp]
| Voltage   I(typ)   I(min)   I(max)
-2.5V     191.3mA    149.5mA    238.1mA
-1.559V   79.6mA     58.4mA     105.4mA
-1.395V   63.37mA    46mA       85.27mA
-1.312V   55.59mA    40.21mA    75.31mA
-1.23V    48.04mA    34.68mA    65.5mA
-1.148V   40.77mA    29.43mA    56.09mA
-1.066V   33.71mA    24.49mA    47.24mA
-902.3mV  21.31mA    15.73mA    32.4mA
-656.2mV  7.665mA    5.781mA    10.63mA
-574.2mV  3.929mA    3.551mA    4.901mA
-410.2mV  189.8uA    599.4uA    178.9uA
5V        0A         0A         0A
[Pullup]
| Voltage   I(typ)   I(min)   I(max)
-2.5V     33.62mA    35.3mA     27.53mA
-1.641V   26.71mA    27.3mA     22.06mA
-984.4mV  18.9mA     18.7mA     15.94mA
-492.2mV  10.57mA    10.16mA    9.235mA
312.5mV   -5.798mA   -5.376mA   -5.337mA
1.094V    -15.4mA    -14.13mA   -14.41mA
1.641V    -17.91mA   -16.4mA    -16.85mA
2.828V    -19.16mA   -17.55mA   -18.02mA
3.156V    -19.2mA    -15.17mA   -18.15mA
3.484V    -15.48mA   -14.5mA    -17.82mA
3.73V     -15.57mA   -14.59mA   -13.39mA
5V        -16.17mA   -15.15mA   -13.84mA
[Pulldown]
| Voltage   I(typ)   I(min)   I(max)
-2.5V     -6.418mA   -7.171mA   -5.47mA
-1.148V   -5.991mA   -6.404mA   -5.329mA
-1.066V   -5.955mA   -6.302mA   -6.421mA
-984.4mV  -6.289mA   -6.19mA    -13.05mA
-902.3mV  -10.75mA   -6.068mA   -19.15mA
-820.3mV  -16.74mA   -7.131mA   -18.91mA
-656.2mV  -16.13mA   -13.98mA   -17mA
-574.2mV  -14.55mA   -13.25mA   -15.46mA
312.5mV   7.039mA    6.195mA    7.88mA
625mV     12.05mA    10.66mA    13.39mA
1.016V    15.75mA    13.99mA    17.37mA
5V        17.97mA    16.17mA    19.53mA
[Ramp]
dV/dt_r   0.535015/0.390377n  0.487003/0.450946n  0.512225/0.347484n
dV/dt_f   0.511786/0.452645n  0.457188/0.545883n  0.557425/0.380153n
R_load = 50
[Rising Waveform]
R_fixture = 50
V_fixture = 0
V_fixture_min = 0
V_fixture_max = 0
| Time   V(typ)   V(min)   V(max)
0s        21.02nV    89.02nV    25.85nV
1.533ns   -465uV     -547.3uV   -21.13mV
1.89ns    -5.495mV   -674.7uV   577.4mV
2.097ns   -13.72mV   -748.6uV   733.3mV
2.421ns   521.2mV    -864.3uV   818.8mV
2.598ns   702mV      -6.72mV    828.9mV
2.866ns   818.3mV    -9.485mV   839.5mV
3.374ns   878.2mV    584.1mV    848.4mV
4.012ns   887.1mV    784mV      852.1mV
10ns      891.7mV    811.7mV    853.7mV
[Rising Waveform]
R_fixture = 50
V_fixture = 2.5
V_fixture_min = 2.375
V_fixture_max = 2.625
| Time   V(typ)   V(min)   V(max)
0s        1.647V     1.613V     1.696V
1.369ns   1.647V     1.613V     1.684V
1.718ns   1.641V     1.613V     2.445V
1.905ns   1.684V     1.613V     2.564V
2.146ns   2.176V     1.613V     2.608V
2.304ns   2.373V     1.609V     2.616V
2.533ns   2.463V     1.616V     2.622V
2.991ns   2.494V     2.209V     2.624V
3.419ns   2.499V     2.353V     2.625V
10ns      2.5V       2.375V     2.625V
[Falling Waveform]
R_fixture = 50
V_fixture = 0
V_fixture_min = 0
V_fixture_max = 0
| Time   V(typ)   V(min)   V(max)
0s        891.7mV    811.7mV    853.8mV
1.402ns   891.7mV    811.8mV    862.3mV
1.73ns    891.7mV    811.8mV    139.7mV
1.966ns   897.9mV    811.8mV    25.4mV
2.066ns   736.7mV    811.8mV    13.9mV
2.308ns   171.2mV    811.8mV    4.265mV
2.708ns   14.51mV    758.7mV    501uV
3.059ns   3.036mV    167.9mV    307.2uV
3.45ns    385.8uV    19.09mV    289.9uV
10ns      1.18uV     6.777uV    -46.02nV
[Falling Waveform]
R_fixture = 50
V_fixture = 2.5
V_fixture_min = 2.375
V_fixture_max = 2.625
| Time   V(typ)   V(min)   V(max)
0s        2.5V       2.375V     2.625V
1.534ns   2.499V     2.375V     2.635V
1.878ns   2.499V     2.374V     2.028V
2.096ns   2.506V     2.374V     1.845V
2.51ns    1.982V     2.374V     1.732V
2.684ns   1.832V     2.385V     1.717V
2.903ns   1.737V     2.368V     1.707V
3.497ns   1.666V     1.834V     1.697V
4.091ns   1.65V      1.647V     1.696V
10ns      1.647V     1.613V     1.696V
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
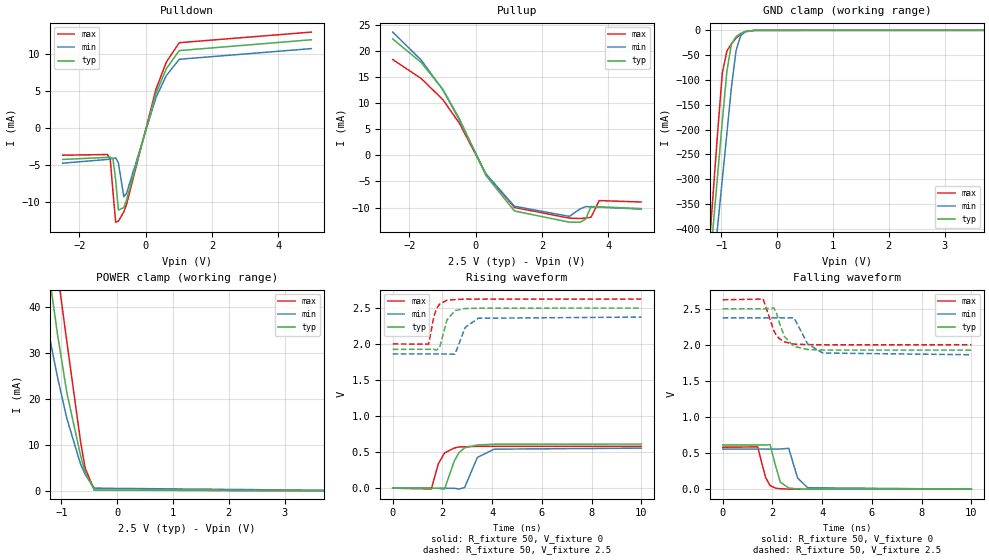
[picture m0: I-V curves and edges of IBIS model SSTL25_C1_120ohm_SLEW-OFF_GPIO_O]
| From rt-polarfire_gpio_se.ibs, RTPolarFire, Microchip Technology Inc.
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|   Model SSTL25_C1_120ohm_SLEW-OFF_GPIO_O
[Model]   SSTL25_C1_120ohm_SLEW-OFF_GPIO_O
Model_type   Output
Polarity   Non-Inverting
Enable   Active-High
Vmeas =   1.25
Cref =   5p
Rref =   50
Vref =   1.25
|   typ   min   max
C_comp_pullup   2.605e-12   2.605e-12   2.76e-12
C_comp_pulldown  2.605e-12   2.605e-12   2.76e-12
[Temperature Range]  25C   125C   -55C
[Voltage Range]  2.5   2.375   2.625
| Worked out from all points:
|   slope of the pulldown table from 0 to 0.375 V, typ, clamps not added: 68.5 ohm
|   slope of the pullup table from 0 to 0.375 V, typ, clamps not added: 82.3 ohm
|   GND clamp passes 1 mA (typ) near -0.51 V on its own axis
|   POWER clamp passes 1 mA (typ) near -0.47 V on its own axis
|   rising waveform, R_fixture 50, V_fixture 0: 20-80 % time 401ps typ, 444ps min, 349ps max; typ from 0 V to 0.612 V
|   rising waveform, R_fixture 50, V_fixture 2.5: 20-80 % time 314ps typ, 363ps min, 243ps max; typ from 1.93 V to 2.5 V
|   falling waveform, R_fixture 50, V_fixture 0: 20-80 % time 250ps typ, 286ps min, 257ps max; typ from 0.612 V to 0 V
|   falling waveform, R_fixture 50, V_fixture 2.5: 20-80 % time 413ps typ, 518ps min, 411ps max; typ from 2.5 V to 1.93 V
[GND Clamp]
| Voltage   I(typ)   I(min)   I(max)
-2.5V     -2.154A    -2.028A    -2.413A
-1.23V    -500.9mA   -578.9mA   -453.4mA
-1.148V   -394.9mA   -486mA     -327.9mA
-1.066V   -289mA     -393mA     -202.4mA
-984.4mV  -183.1mA   -300.1mA   -86.85mA
-902.3mV  -82.21mA   -207.2mA   -41.59mA
-820.3mV  -27.37mA   -114.5mA   -27.29mA
-738.3mV  -12.87mA   -40.96mA   -15.82mA
-656.2mV  -6.285mA   -10.74mA   -7.396mA
-574.2mV  -2.342mA   -3.102mA   -2.493mA
-410.2mV  -62.85uA   -143.8uA   -47.39uA
5V        0A         0A         0A
[POWER Clamp]
| Voltage   I(typ)   I(min)   I(max)
-2.5V     191.3mA    149.5mA    238.1mA
-1.559V   79.6mA     58.4mA     105.4mA
-1.395V   63.37mA    46mA       85.27mA
-1.312V   55.59mA    40.21mA    75.31mA
-1.23V    48.04mA    34.68mA    65.5mA
-1.148V   40.77mA    29.43mA    56.09mA
-1.066V   33.71mA    24.49mA    47.24mA
-902.3mV  21.31mA    15.73mA    32.4mA
-656.2mV  7.665mA    5.781mA    10.63mA
-574.2mV  3.929mA    3.551mA    4.901mA
-410.2mV  189.8uA    599.4uA    178.9uA
5V        0A         0A         0A
[Pullup]
| Voltage   I(typ)   I(min)   I(max)
-2.5V     22.26mA    23.57mA    18.32mA
-1.641V   17.75mA    18.22mA    14.69mA
-984.4mV  12.59mA    12.48mA    10.63mA
-492.2mV  7.057mA    6.778mA    6.167mA
312.5mV   -3.874mA   -3.584mA   -3.572mA
1.172V    -10.66mA   -9.748mA   -9.981mA
2.828V    -12.79mA   -11.69mA   -12.02mA
3.156V    -12.8mA    -10.25mA   -12.1mA
3.32V     -12.22mA   -9.816mA   -12mA
3.484V    -9.804mA   -9.857mA   -11.86mA
3.73V     -9.86mA    -9.92mA    -8.668mA
5V        -10.2mA    -10.3mA    -8.938mA
[Pulldown]
| Voltage   I(typ)   I(min)   I(max)
-2.5V     -4.252mA   -4.758mA   -3.676mA
-1.148V   -3.97mA    -4.25mA    -3.583mA
-1.066V   -3.946mA   -4.182mA   -4.258mA
-984.4mV  -4.157mA   -4.108mA   -8.591mA
-902.3mV  -7.055mA   -4.027mA   -12.76mA
-820.3mV  -11.11mA   -4.713mA   -12.62mA
-656.2mV  -10.78mA   -9.317mA   -11.36mA
-574.2mV  -9.731mA   -8.852mA   -10.34mA
312.5mV   4.706mA    4.139mA    5.267mA
625mV     8.048mA    7.115mA    8.942mA
1.016V    10.51mA    9.332mA    11.58mA
5V        11.98mA    10.78mA    13.02mA
[Ramp]
dV/dt_r   0.367183/0.40108n  0.333739/0.443987n  0.348676/0.348912n
dV/dt_f   0.343509/0.412673n  0.306953/0.518468n  0.373864/0.411368n
R_load = 50
[Rising Waveform]
R_fixture = 50
V_fixture = 0
V_fixture_min = 0
V_fixture_max = 0
| Time   V(typ)   V(min)   V(max)
0s        25.93nV    108.4nV    32.28nV
1.555ns   -567.1uV   -388.2uV   -10.23mV
1.833ns   -1.535mV   -457.6uV   336.8mV
2.082ns   -13.39mV   -519.8uV   488.6mV
2.476ns   375.5mV    -1.163mV   557.5mV
2.67ns    495mV      -12.06mV   572.1mV
2.894ns   560.4mV    10.6mV     575.6mV
3.405ns   600.5mV    426.4mV    581.1mV
4.08ns    610mV      541.9mV    581.1mV
10ns      612mV      556.2mV    581.1mV
[Rising Waveform]
R_fixture = 50
V_fixture = 2.5
V_fixture_min = 2.375
V_fixture_max = 2.625
| Time   V(typ)   V(min)   V(max)
0s        1.927V     1.863V     2.002V
1.444ns   1.928V     1.863V     2V
1.651ns   1.928V     1.863V     2.372V
1.759ns   1.915V     1.863V     2.49V
1.89ns    1.955V     1.863V     2.556V
2.18ns    2.334V     1.862V     2.609V
2.506ns   2.465V     1.86V      2.618V
2.911ns   2.493V     2.23V      2.625V
3.441ns   2.499V     2.359V     2.625V
10ns      2.5V       2.375V     2.625V
[Falling Waveform]
R_fixture = 50
V_fixture = 0
V_fixture_min = 0
V_fixture_max = 0
| Time   V(typ)   V(min)   V(max)
0s        611.9mV    556.2mV    581.1mV
1.406ns   612.1mV    556.4mV    586.1mV
1.721ns   612.2mV    556.4mV    165.6mV
1.903ns   618.4mV    556.4mV    50.56mV
2.124ns   327.2mV    556.4mV    13.6mV
2.317ns   97.02mV    556.4mV    5.43mV
2.655ns   15.9mV     566.2mV    1.3mV
3.012ns   3.501mV    154.6mV    -85.27uV
3.416ns   712.2uV    19.59mV    -80.31uV
10ns      78.72nV    6.111uV    500.8nV
[Falling Waveform]
R_fixture = 50
V_fixture = 2.5
V_fixture_min = 2.375
V_fixture_max = 2.625
| Time   V(typ)   V(min)   V(max)
0s        2.5V       2.375V     2.625V
1.626ns   2.499V     2.374V     2.635V
2.056ns   2.512V     2.374V     2.198V
2.152ns   2.454V     2.374V     2.139V
2.271ns   2.313V     2.374V     2.088V
2.485ns   2.115V     2.374V     2.042V
2.869ns   1.978V     2.375V     2.01V
3.417ns   1.936V     2.012V     2.004V
4.027ns   1.928V     1.887V     2.001V
10ns      1.927V     1.863V     2.002V
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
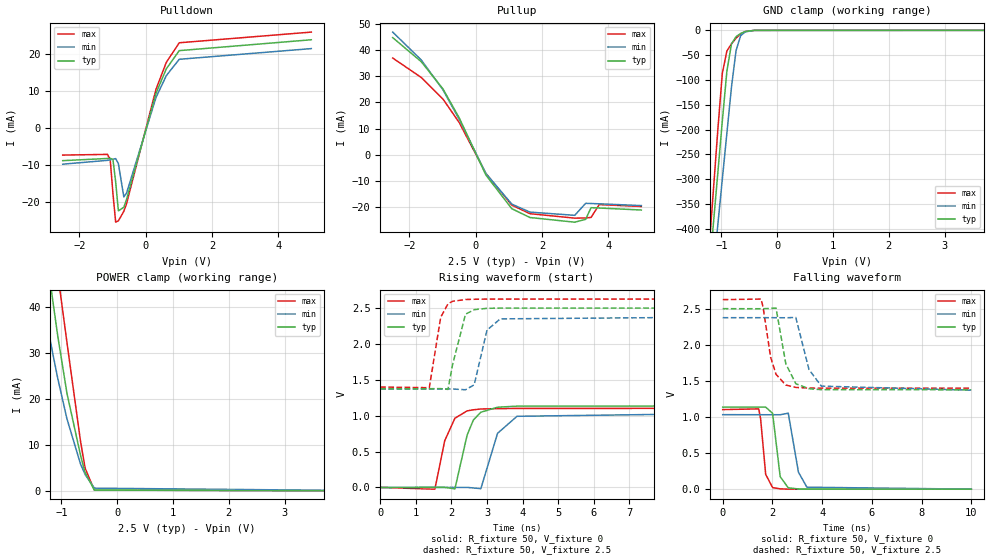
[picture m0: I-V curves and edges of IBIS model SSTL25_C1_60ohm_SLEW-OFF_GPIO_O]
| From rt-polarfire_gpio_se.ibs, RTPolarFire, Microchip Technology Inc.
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|   Model SSTL25_C1_60ohm_SLEW-OFF_GPIO_O
[Model]   SSTL25_C1_60ohm_SLEW-OFF_GPIO_O
Model_type   Output
Polarity   Non-Inverting
Enable   Active-High
Vmeas =   1.25
Cref =   5p
Rref =   50
Vref =   1.25
|   typ   min   max
C_comp_pullup   2.605e-12   2.605e-12   2.76e-12
C_comp_pulldown  2.605e-12   2.605e-12   2.76e-12
[Temperature Range]  25C   125C   -55C
[Voltage Range]  2.5   2.375   2.625
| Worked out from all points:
|   slope of the pulldown table from 0 to 0.375 V, typ, clamps not added: 34.4 ohm
|   slope of the pullup table from 0 to 0.375 V, typ, clamps not added: 41.3 ohm
|   GND clamp passes 1 mA (typ) near -0.51 V on its own axis
|   POWER clamp passes 1 mA (typ) near -0.47 V on its own axis
|   rising waveform, R_fixture 50, V_fixture 0: 20-80 % time 362ps typ, 406ps min, 331ps max; typ from 0 V to 1.14 V
|   rising waveform, R_fixture 50, V_fixture 2.5: 20-80 % time 246ps typ, 282ps min, 216ps max; typ from 1.38 V to 2.5 V
|   falling waveform, R_fixture 50, V_fixture 0: 20-80 % time 219ps typ, 273ps min, 174ps max; typ from 1.14 V to 0 V
|   falling waveform, R_fixture 50, V_fixture 2.5: 20-80 % time 404ps typ, 490ps min, 394ps max; typ from 2.5 V to 1.38 V
[GND Clamp]
| Voltage   I(typ)   I(min)   I(max)
-2.5V     -2.154A    -2.028A    -2.413A
-1.23V    -500.9mA   -578.9mA   -453.4mA
-1.148V   -394.9mA   -486mA     -327.9mA
-1.066V   -289mA     -393mA     -202.4mA
-984.4mV  -183.1mA   -300.1mA   -86.85mA
-902.3mV  -82.21mA   -207.2mA   -41.59mA
-820.3mV  -27.37mA   -114.5mA   -27.29mA
-738.3mV  -12.87mA   -40.96mA   -15.82mA
-656.2mV  -6.285mA   -10.74mA   -7.396mA
-574.2mV  -2.342mA   -3.102mA   -2.493mA
-410.2mV  -62.85uA   -143.8uA   -47.39uA
5V        0A         0A         0A
[POWER Clamp]
| Voltage   I(typ)   I(min)   I(max)
-2.5V     191.3mA    149.5mA    238.1mA
-1.559V   79.6mA     58.4mA     105.4mA
-1.395V   63.37mA    46mA       85.27mA
-1.312V   55.59mA    40.21mA    75.31mA
-1.23V    48.04mA    34.68mA    65.5mA
-1.148V   40.77mA    29.43mA    56.09mA
-1.066V   33.71mA    24.49mA    47.24mA
-902.3mV  21.31mA    15.73mA    32.4mA
-656.2mV  7.665mA    5.781mA    10.63mA
-574.2mV  3.929mA    3.551mA    4.901mA
-410.2mV  189.8uA    599.4uA    178.9uA
5V        0A         0A         0A
[Pullup]
| Voltage   I(typ)   I(min)   I(max)
-2.5V     44.71mA    46.81mA    36.92mA
-1.641V   35.55mA    36.22mA    29.52mA
-984.4mV  25.15mA    24.81mA    21.29mA
-492.2mV  14.07mA    13.49mA    12.3mA
312.5mV   -7.724mA   -7.142mA   -7.098mA
1.094V    -20.54mA   -18.79mA   -19.18mA
1.641V    -23.89mA   -21.83mA   -22.43mA
2.992V    -25.67mA   -23.05mA   -24.13mA
3.32V     -24.58mA   -18.48mA   -24.05mA
3.484V    -20.14mA   -18.55mA   -23.86mA
3.73V     -20.26mA   -18.66mA   -18.96mA
5V        -21.03mA   -19.34mA   -19.68mA
[Pulldown]
| Voltage   I(typ)   I(min)   I(max)
-2.5V     -8.854mA   -9.811mA   -7.342mA
-1.148V   -8.264mA   -8.766mA   -7.153mA
-1.066V   -8.214mA   -8.624mA   -8.697mA
-984.4mV  -8.557mA   -8.47mA    -17.78mA
-902.3mV  -14.63mA   -8.3mA     -25.55mA
-820.3mV  -22.48mA   -9.656mA   -25.18mA
-656.2mV  -21.5mA    -18.69mA   -22.6mA
-574.2mV  -19.39mA   -17.66mA   -20.54mA
312.5mV   9.376mA    8.254mA    10.47mA
625mV     16.05mA    14.2mA     17.81mA
1.016V    21mA       18.65mA    23.13mA
5V        23.95mA    21.55mA    26.03mA
[Ramp]
dV/dt_r   0.681422/0.361505n  0.61913/0.405704n  0.661225/0.331257n
dV/dt_f   0.674512/0.404351n  0.602181/0.489507n  0.735803/0.393528n
R_load = 50
[Rising Waveform]
R_fixture = 50
V_fixture = 0
V_fixture_min = 0
V_fixture_max = 0
| Time   V(typ)   V(min)   V(max)
0s        17.65nV    75.41nV    21.59nV
1.535ns   625.9uV    608.3uV    -23.96mV
1.812ns   583.1uV    718.1uV    651.6mV
2.098ns   -19.39mV   831.4uV    964.7mV
2.441ns   728.3mV    758.8uV    1.067V
2.616ns   938.8mV    -7.286mV   1.082V
2.827ns   1.048V     -17.02mV   1.093V
3.297ns   1.118V     754.4mV    1.098V
3.844ns   1.133V     991.4mV    1.101V
10ns      1.136V     1.032V     1.102V
[Rising Waveform]
R_fixture = 50
V_fixture = 2.5
V_fixture_min = 2.375
V_fixture_max = 2.625
| Time   V(typ)   V(min)   V(max)
0s        1.376V     1.371V     1.399V
1.378ns   1.376V     1.372V     1.39V
1.699ns   1.377V     1.372V     2.372V
1.903ns   1.366V     1.372V     2.558V
2.031ns   1.707V     1.372V     2.594V
2.396ns   2.414V     1.361V     2.619V
2.64ns    2.477V     1.43V      2.622V
3ns       2.496V     2.192V     2.625V
3.373ns   2.499V     2.349V     2.625V
10ns      2.5V       2.375V     2.625V
[Falling Waveform]
R_fixture = 50
V_fixture = 0
V_fixture_min = 0
V_fixture_max = 0
| Time   V(typ)   V(min)   V(max)
0s        1.136V     1.032V     1.102V
1.449ns   1.136V     1.031V     1.112V
1.524ns   1.136V     1.031V     976mV
1.729ns   1.136V     1.031V     204.4mV
2.007ns   1.05V      1.031V     21.97mV
2.312ns   173.6mV    1.031V     4.032mV
2.637ns   18.12mV    1.052V     542uV
3.047ns   2.81mV     234.9mV    140.5uV
3.386ns   764.4uV    27.18mV    -34.97uV
10ns      -1.222uV   6.693uV    453.9nV
[Falling Waveform]
R_fixture = 50
V_fixture = 2.5
V_fixture_min = 2.375
V_fixture_max = 2.625
| Time   V(typ)   V(min)   V(max)
0s        2.5V       2.375V     2.625V
1.545ns   2.499V     2.375V     2.633V
1.625ns   2.499V     2.375V     2.518V
1.928ns   2.504V     2.375V     1.826V
2.145ns   2.508V     2.375V     1.591V
2.538ns   1.737V     2.374V     1.442V
2.94ns    1.461V     2.378V     1.409V
3.471ns   1.391V     1.656V     1.4V
3.968ns   1.378V     1.427V     1.399V
10ns      1.376V     1.371V     1.399V
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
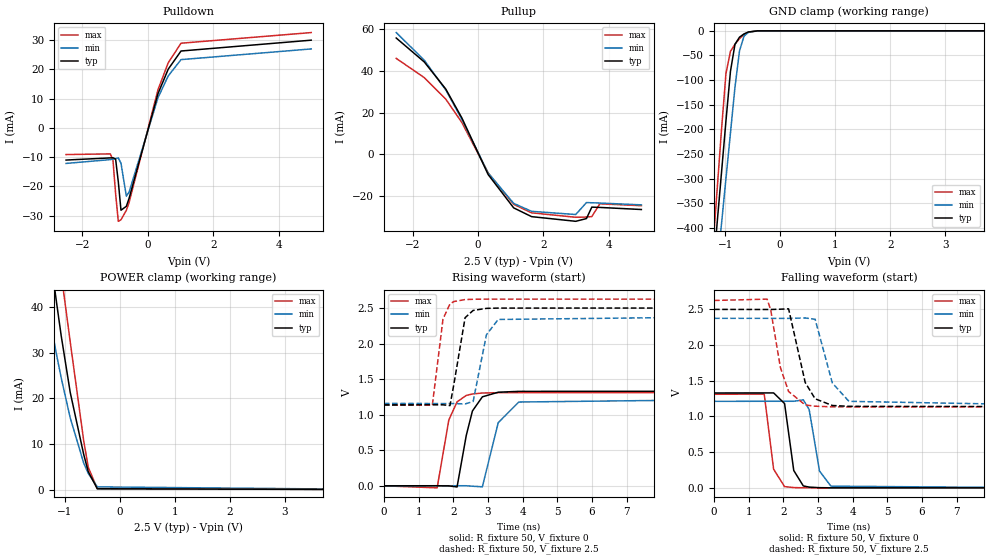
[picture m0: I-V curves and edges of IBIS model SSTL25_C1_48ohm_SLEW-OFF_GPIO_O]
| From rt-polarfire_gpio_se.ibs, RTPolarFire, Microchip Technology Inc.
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|   Model SSTL25_C1_48ohm_SLEW-OFF_GPIO_O
[Model]   SSTL25_C1_48ohm_SLEW-OFF_GPIO_O
Model_type   Output
Polarity   Non-Inverting
Enable   Active-High
Vmeas =   1.25
Cref =   5p
Rref =   50
Vref =   1.25
|   typ   min   max
C_comp_pullup   2.605e-12   2.605e-12   2.76e-12
C_comp_pulldown  2.605e-12   2.605e-12   2.76e-12
[Temperature Range]  25C   125C   -55C
[Voltage Range]  2.5   2.375   2.625
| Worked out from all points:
|   slope of the pulldown table from 0 to 0.375 V, typ, clamps not added: 27.6 ohm
|   slope of the pullup table from 0 to 0.375 V, typ, clamps not added: 33.1 ohm
|   GND clamp passes 1 mA (typ) near -0.51 V on its own axis
|   POWER clamp passes 1 mA (typ) near -0.47 V on its own axis
|   rising waveform, R_fixture 50, V_fixture 0: 20-80 % time 334ps typ, 389ps min, 304ps max; typ from 0 V to 1.33 V
|   rising waveform, R_fixture 50, V_fixture 2.5: 20-80 % time 235ps typ, 293ps min, 201ps max; typ from 1.14 V to 2.5 V
|   falling waveform, R_fixture 50, V_fixture 0: 20-80 % time 217ps typ, 244ps min, 167ps max; typ from 1.33 V to 0 V
|   falling waveform, R_fixture 50, V_fixture 2.5: 20-80 % time 398ps typ, 443ps min, 376ps max; typ from 2.5 V to 1.14 V
[GND Clamp]
| Voltage   I(typ)   I(min)   I(max)
-2.5V     -2.154A    -2.028A    -2.413A
-1.23V    -500.9mA   -578.9mA   -453.4mA
-1.148V   -394.9mA   -486mA     -327.9mA
-1.066V   -289mA     -393mA     -202.4mA
-984.4mV  -183.1mA   -300.1mA   -86.85mA
-902.3mV  -82.21mA   -207.2mA   -41.59mA
-820.3mV  -27.37mA   -114.5mA   -27.29mA
-738.3mV  -12.87mA   -40.96mA   -15.82mA
-656.2mV  -6.285mA   -10.74mA   -7.396mA
-574.2mV  -2.342mA   -3.102mA   -2.493mA
-410.2mV  -62.85uA   -143.8uA   -47.39uA
5V        0A         0A         0A
[POWER Clamp]
| Voltage   I(typ)   I(min)   I(max)
-2.5V     191.3mA    149.5mA    238.1mA
-1.559V   79.6mA     58.4mA     105.4mA
-1.395V   63.37mA    46mA       85.27mA
-1.312V   55.59mA    40.21mA    75.31mA
-1.23V    48.04mA    34.68mA    65.5mA
-1.148V   40.77mA    29.43mA    56.09mA
-1.066V   33.71mA    24.49mA    47.24mA
-902.3mV  21.31mA    15.73mA    32.4mA
-656.2mV  7.665mA    5.781mA    10.63mA
-574.2mV  3.929mA    3.551mA    4.901mA
-410.2mV  189.8uA    599.4uA    178.9uA
5V        0A         0A         0A
[Pullup]
| Voltage   I(typ)   I(min)   I(max)
-2.5V     55.91mA    58.52mA    46.13mA
-1.641V   44.41mA    45.26mA    36.88mA
-984.4mV  31.41mA    31mA       26.59mA
-492.2mV  17.56mA    16.84mA    15.36mA
312.5mV   -9.641mA   -8.923mA   -8.839mA
1.094V    -25.65mA   -23.49mA   -23.96mA
1.641V    -29.85mA   -27.3mA    -28.02mA
2.992V    -32.09mA   -28.84mA   -30.16mA
3.32V     -30.78mA   -23.1mA    -30.06mA
3.484V    -25.28mA   -23.19mA   -29.82mA
3.73V     -25.43mA   -23.33mA   -23.68mA
5V        -26.43mA   -24.2mA    -24.6mA
[Pulldown]
| Voltage   I(typ)   I(min)   I(max)
-2.5V     -11.02mA   -12.17mA   -9.146mA
-1.148V   -10.28mA   -10.87mA   -8.91mA
-1.066V   -10.22mA   -10.69mA   -10.98mA
-984.4mV  -10.71mA   -10.5mA    -22.57mA
-902.3mV  -18.47mA   -10.29mA   -31.94mA
-820.3mV  -28.16mA   -12.12mA   -31.42mA
-656.2mV  -26.81mA   -23.34mA   -28.17mA
-574.2mV  -24.16mA   -22.01mA   -25.59mA
312.5mV   11.69mA    10.29mA    13.04mA
625mV     20.03mA    17.72mA    22.21mA
1.016V    26.23mA    23.29mA    28.89mA
5V        29.93mA    26.94mA    32.53mA
[Ramp]
dV/dt_r   0.797442/0.33366n  0.727436/0.38857n  0.786873/0.304387n
dV/dt_f   0.816986/0.397806n  0.730251/0.442525n  0.894864/0.376041n
R_load = 50
[Rising Waveform]
R_fixture = 50
V_fixture = 0
V_fixture_min = 0
V_fixture_max = 0
| Time   V(typ)   V(min)   V(max)
0s        15.23nV    65.5nV     18.54nV
1.535ns   813.3uV    525.2uV    -28.98mV
1.872ns   -1.565mV   640.5uV    925.6mV
2.11ns    -16.19mV   722uV      1.18V
2.375ns   707.2mV    822.7uV    1.271V
2.553ns   1.052V     -5.972mV   1.291V
2.84ns    1.251V     -13.9mV    1.305V
3.298ns   1.316V     888.1mV    1.309V
3.891ns   1.328V     1.178V     1.311V
10ns      1.329V     1.212V     1.311V
[Rising Waveform]
R_fixture = 50
V_fixture = 2.5
V_fixture_min = 2.375
V_fixture_max = 2.625
| Time   V(typ)   V(min)   V(max)
0s        1.138V     1.158V     1.134V
1.397ns   1.139V     1.157V     1.135V
1.704ns   1.139V     1.157V     2.345V
1.905ns   1.128V     1.157V     2.557V
2.016ns   1.422V     1.157V     2.591V
2.342ns   2.364V     1.151V     2.619V
2.574ns   2.466V     1.186V     2.623V
2.957ns   2.495V     2.123V     2.625V
3.296ns   2.499V     2.339V     2.625V
10ns      2.5V       2.375V     2.625V
[Falling Waveform]
R_fixture = 50
V_fixture = 0
V_fixture_min = 0
V_fixture_max = 0
| Time   V(typ)   V(min)   V(max)
0s        1.329V     1.212V     1.311V
1.447ns   1.33V      1.213V     1.314V
1.718ns   1.33V      1.213V     261.3mV
2.034ns   1.181V     1.213V     17.49mV
2.299ns   242.9mV    1.213V     3.938mV
2.574ns   27.27mV    1.233V     1.032mV
2.743ns   10.69mV    1.098V     560.8uV
3.042ns   2.785mV    234.9mV    33.8uV
3.373ns   703uV      23.63mV    32.24uV
10ns      1.654uV    7.518uV    975.9nV
[Falling Waveform]
R_fixture = 50
V_fixture = 2.5
V_fixture_min = 2.375
V_fixture_max = 2.625
| Time   V(typ)   V(min)   V(max)
0s        2.5V       2.375V     2.625V
1.529ns   2.499V     2.375V     2.644V
1.634ns   2.499V     2.375V     2.493V
1.913ns   2.503V     2.374V     1.687V
2.15ns    2.508V     2.374V     1.349V
2.63ns    1.475V     2.38V      1.162V
2.915ns   1.248V     2.362V     1.144V
3.412ns   1.154V     1.468V     1.135V
3.89ns    1.142V     1.212V     1.134V
10ns      1.138V     1.158V     1.134V
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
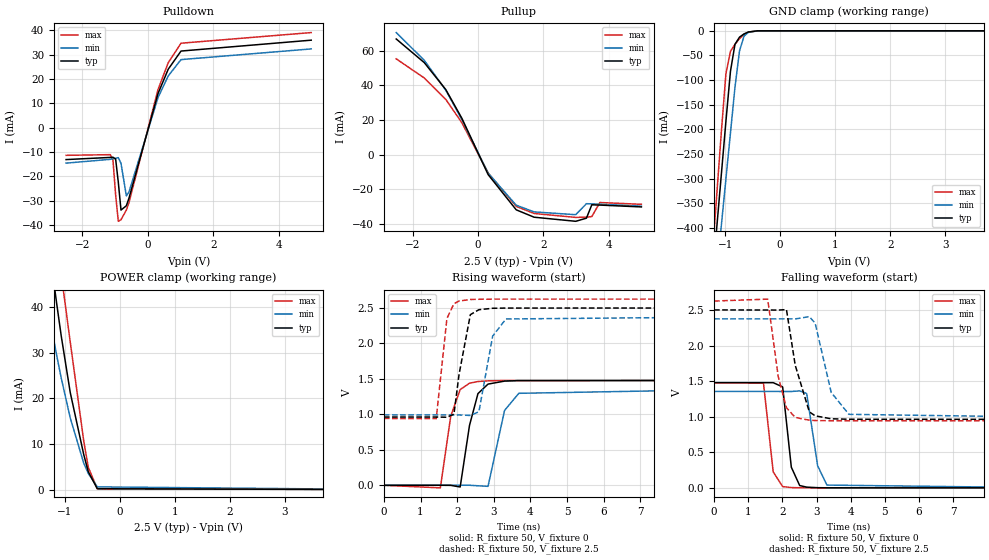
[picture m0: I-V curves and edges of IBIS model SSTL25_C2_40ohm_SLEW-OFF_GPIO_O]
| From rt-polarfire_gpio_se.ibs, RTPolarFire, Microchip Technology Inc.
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|   Model SSTL25_C2_40ohm_SLEW-OFF_GPIO_O
[Model]   SSTL25_C2_40ohm_SLEW-OFF_GPIO_O
Model_type   Output
Polarity   Non-Inverting
Enable   Active-High
Vmeas =   1.25
Cref =   5p
Rref =   50
Vref =   1.25
|   typ   min   max
C_comp_pullup   2.605e-12   2.605e-12   2.76e-12
C_comp_pulldown  2.605e-12   2.605e-12   2.76e-12
[Temperature Range]  25C   125C   -55C
[Voltage Range]  2.5   2.375   2.625
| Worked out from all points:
|   slope of the pulldown table from 0 to 0.375 V, typ, clamps not added: 23 ohm
|   slope of the pullup table from 0 to 0.375 V, typ, clamps not added: 27.6 ohm
|   GND clamp passes 1 mA (typ) near -0.51 V on its own axis
|   POWER clamp passes 1 mA (typ) near -0.47 V on its own axis
|   rising waveform, R_fixture 50, V_fixture 0: 20-80 % time 288ps typ, 346ps min, 277ps max; typ from 0 V to 1.48 V
|   rising waveform, R_fixture 50, V_fixture 2.5: 20-80 % time 221ps typ, 278ps min, 181ps max; typ from 0.963 V to 2.5 V
|   falling waveform, R_fixture 50, V_fixture 0: 20-80 % time 180ps typ, 238ps min, 158ps max; typ from 1.48 V to 0 V
|   falling waveform, R_fixture 50, V_fixture 2.5: 20-80 % time 342ps typ, 431ps min, 317ps max; typ from 2.5 V to 0.963 V
[GND Clamp]
| Voltage   I(typ)   I(min)   I(max)
-2.5V     -2.154A    -2.028A    -2.413A
-1.23V    -500.9mA   -578.9mA   -453.4mA
-1.148V   -394.9mA   -486mA     -327.9mA
-1.066V   -289mA     -393mA     -202.4mA
-984.4mV  -183.1mA   -300.1mA   -86.85mA
-902.3mV  -82.21mA   -207.2mA   -41.59mA
-820.3mV  -27.37mA   -114.5mA   -27.29mA
-738.3mV  -12.87mA   -40.96mA   -15.82mA
-656.2mV  -6.285mA   -10.74mA   -7.396mA
-574.2mV  -2.342mA   -3.102mA   -2.493mA
-410.2mV  -62.85uA   -143.8uA   -47.39uA
5V        0A         0A         0A
[POWER Clamp]
| Voltage   I(typ)   I(min)   I(max)
-2.5V     191.3mA    149.5mA    238.1mA
-1.559V   79.6mA     58.4mA     105.4mA
-1.395V   63.37mA    46mA       85.27mA
-1.312V   55.59mA    40.21mA    75.31mA
-1.23V    48.04mA    34.68mA    65.5mA
-1.148V   40.77mA    29.43mA    56.09mA
-1.066V   33.71mA    24.49mA    47.24mA
-902.3mV  21.31mA    15.73mA    32.4mA
-656.2mV  7.665mA    5.781mA    10.63mA
-574.2mV  3.929mA    3.551mA    4.901mA
-410.2mV  189.8uA    599.4uA    178.9uA
5V        0A         0A         0A
[Pullup]
| Voltage   I(typ)   I(min)   I(max)
-2.5V     66.67mA    70.36mA    55.21mA
-1.641V   53.03mA    54.35mA    44.16mA
-984.4mV  37.52mA    37.18mA    31.86mA
-492.2mV  20.98mA    20.18mA    18.41mA
312.5mV   -11.53mA   -10.69mA   -10.6mA
1.172V    -31.84mA   -29.17mA   -29.85mA
1.719V    -36.09mA   -33.03mA   -33.94mA
2.992V    -38.45mA   -34.64mA   -36.21mA
3.32V     -36.64mA   -28.29mA   -36.05mA
3.484V    -28.93mA   -28.4mA    -35.73mA
3.73V     -29.1mA    -28.58mA   -27.62mA
5V        -30.16mA   -29.73mA   -28.66mA
[Pulldown]
| Voltage   I(typ)   I(min)   I(max)
-2.5V     -13.11mA   -14.57mA   -11.37mA
-1.148V   -12.23mA   -13.01mA   -11.09mA
-1.066V   -12.16mA   -12.8mA    -13.26mA
-984.4mV  -12.87mA   -12.57mA   -27.53mA
-902.3mV  -22.41mA   -12.32mA   -38.45mA
-820.3mV  -33.84mA   -14.65mA   -37.79mA
-656.2mV  -32.07mA   -27.99mA   -33.84mA
-574.2mV  -28.89mA   -26.34mA   -30.72mA
312.5mV   13.99mA    12.32mA    15.65mA
625mV     23.99mA    21.23mA    26.66mA
1.016V    31.44mA    27.93mA    34.66mA
5V        35.91mA    32.32mA    39.03mA
[Ramp]
dV/dt_r   0.886572/0.28835n  0.812977/0.345819n  0.886401/0.277202n
dV/dt_f   0.922356/0.341587n  0.82958/0.431403n  1.00927/0.317091n
R_load = 50
[Rising Waveform]
R_fixture = 50
V_fixture = 0
V_fixture_min = 0
V_fixture_max = 0
| Time   V(typ)   V(min)   V(max)
0s        13.4nV     57.92nV    16.18nV
1.541ns   723uV      631.1uV    -36.14mV
1.825ns   -750.9uV   747.3uV    976.2mV
2.082ns   -24.11mV   852.6uV    1.349V
2.337ns   845mV      1.031mV    1.44V
2.568ns   1.293V     -6.734mV   1.463V
2.843ns   1.427V     -14.77mV   1.473V
3.294ns   1.469V     1.055V     1.477V
3.683ns   1.476V     1.297V     1.477V
10ns      1.478V     1.355V     1.477V
[Rising Waveform]
R_fixture = 50
V_fixture = 2.5
V_fixture_min = 2.375
V_fixture_max = 2.625
| Time   V(typ)   V(min)   V(max)
0s        962.7mV    992.3mV    942.9mV
1.428ns   962.6mV    992mV      939.9mV
1.72ns    959.6mV    991.9mV    2.352V
1.912ns   1.002V     991.9mV    2.56V
2.051ns   1.562V     991.8mV    2.598V
2.36ns    2.406V     984.9mV    2.62V
2.594ns   2.476V     1.037V     2.623V
2.968ns   2.496V     2.102V     2.625V
3.331ns   2.499V     2.345V     2.625V
10ns      2.5V       2.375V     2.625V
[Falling Waveform]
R_fixture = 50
V_fixture = 0
V_fixture_min = 0
V_fixture_max = 0
| Time   V(typ)   V(min)   V(max)
0s        1.478V     1.355V     1.477V
1.446ns   1.478V     1.355V     1.474V
1.731ns   1.478V     1.355V     224.3mV
2.008ns   1.418V     1.354V     17.85mV
2.261ns   290.6mV    1.354V     4.363mV
2.506ns   32.43mV    1.363V     1.167mV
2.711ns   10.12mV    1.326V     499.4uV
3.032ns   2.335mV    309.8mV    212.3uV
3.303ns   886uV      39.02mV    204.1uV
10ns      2.497uV    7.224uV    497.7nV
[Falling Waveform]
R_fixture = 50
V_fixture = 2.5
V_fixture_min = 2.375
V_fixture_max = 2.625
| Time   V(typ)   V(min)   V(max)
0s        2.5V       2.375V     2.625V
1.57ns    2.499V     2.375V     2.652V
1.878ns   2.498V     2.375V     1.563V
2.119ns   2.505V     2.375V     1.125V
2.375ns   1.724V     2.374V     990.1mV
2.788ns   1.068V     2.406V     950.5mV
2.959ns   1.012V     2.313V     945.9mV
3.428ns   970.7mV    1.342V     943.3mV
3.947ns   964mV      1.033V     942.9mV
10ns      962.7mV    992.4mV    942.9mV
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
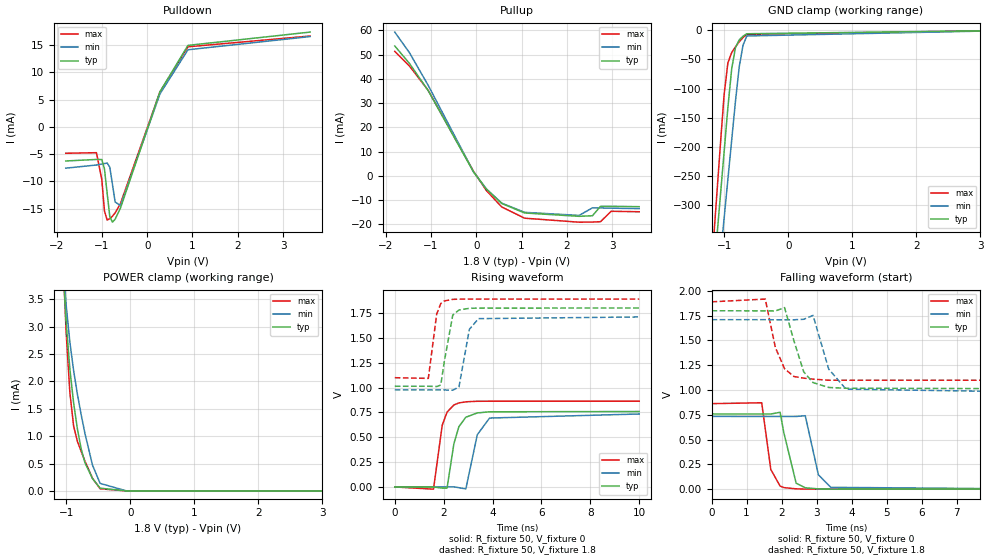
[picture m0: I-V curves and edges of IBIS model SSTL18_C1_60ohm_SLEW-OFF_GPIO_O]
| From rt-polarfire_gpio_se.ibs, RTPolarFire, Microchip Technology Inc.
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|   Model SSTL18_C1_60ohm_SLEW-OFF_GPIO_O
[Model]   SSTL18_C1_60ohm_SLEW-OFF_GPIO_O
Model_type   Output
Polarity   Non-Inverting
Enable   Active-High
Vmeas =   0.9
Cref =   5p
Rref =   50
Vref =   0.9
|   typ   min   max
C_comp_pullup   2.605e-12   2.605e-12   2.76e-12
C_comp_pulldown  2.605e-12   2.605e-12   2.76e-12
[Temperature Range]  25C   125C   -55C
[Voltage Range]  1.8   1.71   1.89
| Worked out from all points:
|   slope of the pulldown table from 0 to 0.27 V, typ, clamps not added: 43.5 ohm
|   slope of the pullup table from 0 to 0.27 V, typ, clamps not added: 42.3 ohm
|   GND clamp passes 1 mA (typ) near -0.52 V on its own axis
|   POWER clamp passes 1 mA (typ) near -0.81 V on its own axis
|   rising waveform, R_fixture 50, V_fixture 0: 20-80 % time 380ps typ, 433ps min, 333ps max; typ from 0 V to 0.759 V
|   rising waveform, R_fixture 50, V_fixture 1.8: 20-80 % time 278ps typ, 325ps min, 241ps max; typ from 1.01 V to 1.8 V
|   falling waveform, R_fixture 50, V_fixture 0: 20-80 % time 232ps typ, 280ps min, 190ps max; typ from 0.759 V to 0 V
|   falling waveform, R_fixture 50, V_fixture 1.8: 20-80 % time 398ps typ, 396ps min, 351ps max; typ from 1.8 V to 1.01 V
[GND Clamp]
| Voltage   I(typ)   I(min)   I(max)
-1.8V     -1.238A    -1.225A    -1.327A
-1.181V   -437.3mA   -523.2mA   -378.1mA
-1.122V   -361mA     -456.2mA   -287.7mA
-1.063V   -284.7mA   -389.3mA   -197.3mA
-1.004V   -208.5mA   -322.4mA   -110.3mA
-945mV    -132.4mA   -255.5mA   -55.69mA
-885.9mV  -66.33mA   -188.6mA   -38.3mA
-826.9mV  -29.63mA   -121.9mA   -28.32mA
-767.8mV  -16.36mA   -62.59mA   -19.64mA
-708.7mV  -10.12mA   -25.53mA   -12.4mA
-649.7mV  -5.882mA   -9.682mA   -6.873mA
3.6V      0A         0A         0A
[POWER Clamp]
| Voltage   I(typ)   I(min)   I(max)
-1.8V     45.61mA    34mA       62.13mA
-1.063V   4.301mA    4.351mA    4.537mA
-1.004V   3.099mA    3.407mA    2.918mA
-945mV    2.226mA    2.718mA    1.799mA
-885.9mV  1.604mA    2.194mA    1.183mA
-826.9mV  1.131mA    1.765mA    904.1uA
-767.8mV  765.5uA    1.388mA    720.7uA
-708.7mV  512.4uA    1.046mA    541.9uA
-590.6mV  225.1uA    468.8uA    230.2uA
-472.5mV  50.43uA    137.9uA    39.22uA
-59.06mV  410.7pA    7.346nA    87.23nA
3.6V      0A         0A         0A
[Pullup]
| Voltage   I(typ)   I(min)   I(max)
-1.8V     53.58mA    59.3mA     51.36mA
-1.477V   46.4mA     50.84mA    45.35mA
-1.063V   35.23mA    37.4mA     35.32mA
-59.06mV  1.616mA    1.633mA    1.859mA
225mV     -5.445mA   -5.399mA   -6.052mA
562.5mV   -11.35mA   -11.2mA    -12.79mA
1.069V    -15.27mA   -15.01mA   -17.42mA
2.272V    -16.65mA   -16.27mA   -19.07mA
2.568V    -16.41mA   -13.16mA   -19.01mA
2.745V    -12.54mA   -13.2mA    -18.87mA
2.981V    -12.51mA   -13.29mA   -14.57mA
3.6V      -12.68mA   -13.48mA   -14.77mA
[Pulldown]
| Voltage   I(typ)   I(min)   I(max)
-1.8V     -6.262mA   -7.579mA   -4.848mA
-1.122V   -5.98mA    -7.003mA   -4.741mA
-1.004V   -5.999mA   -6.831mA   -9.626mA
-945mV    -7.716mA   -6.737mA   -15.42mA
-885.9mV  -12.14mA   -6.635mA   -17.09mA
-826.9mV  -16.46mA   -7.4mA     -16.85mA
-767.8mV  -17.49mA   -10.57mA   -16.39mA
-708.7mV  -16.94mA   -13.79mA   -15.79mA
-590.6mV  -14.89mA   -14.44mA   -14.05mA
281.2mV   6.43mA     6.039mA    6.405mA
900mV     14.94mA    14.14mA    14.68mA
3.6V      17.38mA    16.56mA    16.66mA
[Ramp]
dV/dt_r   0.455262/0.379876n  0.44034/0.43269n  0.517694/0.333166n
dV/dt_f   0.472106/0.397857n  0.440398/0.395737n  0.474389/0.350653n
R_load = 50
[Rising Waveform]
R_fixture = 50
V_fixture = 0
V_fixture_min = 0
V_fixture_max = 0
| Time   V(typ)   V(min)   V(max)
0s        18.08nV    45.78nV    23.96nV
1.584ns   -732.7uV   614.4uV    -22.43mV
1.941ns   -11.51mV   752.8uV    620.5mV
2.139ns   -11.99mV   829.6uV    752.4mV
2.418ns   433.8mV    978.9uV    824.7mV
2.622ns   606mV      -7.791mV   845mV
2.908ns   701.4mV    -19.82mV   856.4mV
3.376ns   744.6mV    525.1mV    861.8mV
3.878ns   755.9mV    693mV      862.3mV
10ns      758.8mV    733.9mV    862.8mV
[Rising Waveform]
R_fixture = 50
V_fixture = 1.8
V_fixture_min = 1.71
V_fixture_max = 1.89
| Time   V(typ)   V(min)   V(max)
0s        1.013V     976mV      1.099V
1.373ns   1.013V     975.9mV    1.092V
1.716ns   1.01V      975.9mV    1.74V
1.883ns   1.025V     975.9mV    1.845V
2.022ns   1.255V     975.9mV    1.871V
2.372ns   1.728V     972.7mV    1.887V
2.626ns   1.78V      1.006V     1.889V
3.052ns   1.797V     1.585V     1.89V
3.425ns   1.799V     1.693V     1.89V
10ns      1.8V       1.71V      1.89V
[Falling Waveform]
R_fixture = 50
V_fixture = 0
V_fixture_min = 0
V_fixture_max = 0
| Time   V(typ)   V(min)   V(max)
0s        758.8mV    733.9mV    862.8mV
1.431ns   758.1mV    733.3mV    871.6mV
1.69ns    757.9mV    733.2mV    199.4mV
1.956ns   775.8mV    733.1mV    31.07mV
2.059ns   575.2mV    733mV      15.99mV
2.414ns   60.41mV    733.3mV    3.274mV
2.674ns   13.77mV    741.1mV    849.8uV
3.049ns   2.712mV    145.5mV    129.2uV
3.402ns   486.1uV    18.46mV    -77.39uV
10ns      460.5nV    8.394uV    1.849nV
[Falling Waveform]
R_fixture = 50
V_fixture = 1.8
V_fixture_min = 1.71
V_fixture_max = 1.89
| Time   V(typ)   V(min)   V(max)
0s        1.8V       1.71V      1.89V
1.533ns   1.799V     1.71V      1.918V
1.821ns   1.798V     1.709V     1.429V
2.083ns   1.832V     1.709V     1.215V
2.353ns   1.494V     1.709V     1.136V
2.631ns   1.183V     1.714V     1.12V
2.897ns   1.075V     1.753V     1.11V
3.343ns   1.026V     1.212V     1.099V
3.837ns   1.018V     1.009V     1.099V
10ns      1.013V     976mV      1.099V
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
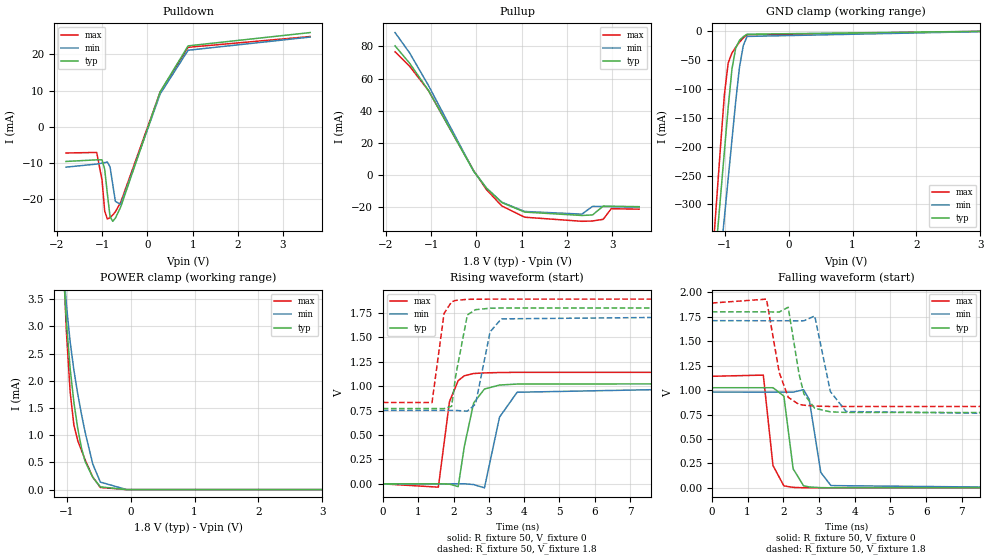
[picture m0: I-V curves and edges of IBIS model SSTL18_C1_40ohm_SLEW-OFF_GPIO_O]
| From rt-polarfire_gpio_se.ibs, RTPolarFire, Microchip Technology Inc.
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|   Model SSTL18_C1_40ohm_SLEW-OFF_GPIO_O
[Model]   SSTL18_C1_40ohm_SLEW-OFF_GPIO_O
Model_type   Output
Polarity   Non-Inverting
Enable   Active-High
Vmeas =   0.9
Cref =   5p
Rref =   50
Vref =   0.9
|   typ   min   max
C_comp_pullup   2.605e-12   2.605e-12   2.76e-12
C_comp_pulldown  2.605e-12   2.605e-12   2.76e-12
[Temperature Range]  25C   125C   -55C
[Voltage Range]  1.8   1.71   1.89
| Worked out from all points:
|   slope of the pulldown table from 0 to 0.27 V, typ, clamps not added: 29.1 ohm
|   slope of the pullup table from 0 to 0.27 V, typ, clamps not added: 28.3 ohm
|   GND clamp passes 1 mA (typ) near -0.52 V on its own axis
|   POWER clamp passes 1 mA (typ) near -0.81 V on its own axis
|   rising waveform, R_fixture 50, V_fixture 0: 20-80 % time 323ps typ, 372ps min, 272ps max; typ from 0 V to 1.02 V
|   rising waveform, R_fixture 50, V_fixture 1.8: 20-80 % time 238ps typ, 316ps min, 197ps max; typ from 0.77 V to 1.8 V
|   falling waveform, R_fixture 50, V_fixture 0: 20-80 % time 217ps typ, 249ps min, 183ps max; typ from 1.02 V to 0 V
|   falling waveform, R_fixture 50, V_fixture 1.8: 20-80 % time 304ps typ, 336ps min, 310ps max; typ from 1.8 V to 0.77 V
[GND Clamp]
| Voltage   I(typ)   I(min)   I(max)
-1.8V     -1.238A    -1.225A    -1.327A
-1.181V   -437.3mA   -523.2mA   -378.1mA
-1.122V   -361mA     -456.2mA   -287.7mA
-1.063V   -284.7mA   -389.3mA   -197.3mA
-1.004V   -208.5mA   -322.4mA   -110.3mA
-945mV    -132.4mA   -255.5mA   -55.69mA
-885.9mV  -66.33mA   -188.6mA   -38.3mA
-826.9mV  -29.63mA   -121.9mA   -28.32mA
-767.8mV  -16.36mA   -62.59mA   -19.64mA
-708.7mV  -10.12mA   -25.53mA   -12.4mA
-649.7mV  -5.882mA   -9.682mA   -6.873mA
3.6V      0A         0A         0A
[POWER Clamp]
| Voltage   I(typ)   I(min)   I(max)
-1.8V     45.61mA    34mA       62.13mA
-1.063V   4.301mA    4.351mA    4.537mA
-1.004V   3.099mA    3.407mA    2.918mA
-945mV    2.226mA    2.718mA    1.799mA
-885.9mV  1.604mA    2.194mA    1.183mA
-826.9mV  1.131mA    1.765mA    904.1uA
-767.8mV  765.5uA    1.388mA    720.7uA
-708.7mV  512.4uA    1.046mA    541.9uA
-590.6mV  225.1uA    468.8uA    230.2uA
-472.5mV  50.43uA    137.9uA    39.22uA
-59.06mV  411.5pA    7.346nA    87.23nA
3.6V      0A         0A         0A
[Pullup]
| Voltage   I(typ)   I(min)   I(max)
-1.8V     80.37mA    88.61mA    76.66mA
-1.477V   69.54mA    75.93mA    67.68mA
-1.063V   52.72mA    55.83mA    52.68mA
-59.06mV  2.417mA    2.44mA     2.773mA
225mV     -8.15mA    -8.078mA   -9.036mA
562.5mV   -17.01mA   -16.78mA   -19.13mA
1.069V    -22.9mA    -22.52mA   -26.09mA
2.332V    -24.99mA   -24.17mA   -28.62mA
2.568V    -24.67mA   -19.33mA   -28.44mA
2.804V    -19.18mA   -19.42mA   -27.38mA
2.981V    -19.26mA   -19.52mA   -20.8mA
3.6V      -19.54mA   -19.79mA   -21.08mA
[Pulldown]
| Voltage   I(typ)   I(min)   I(max)
-1.8V     -9.669mA   -11.25mA   -7.325mA
-1.122V   -9.224mA   -10.39mA   -7.169mA
-1.004V   -9.213mA   -10.14mA   -14.82mA
-945mV    -11.82mA   -9.995mA   -23.39mA
-885.9mV  -18.63mA   -9.846mA   -25.64mA
-826.9mV  -24.92mA   -11.17mA   -25.24mA
-767.8mV  -26.27mA   -15.98mA   -24.54mA
-708.7mV  -25.4mA    -20.76mA   -23.63mA
-590.6mV  -22.29mA   -21.58mA   -21mA
281.2mV   9.622mA    9.024mA    9.569mA
900mV     22.39mA    21.18mA    21.99mA
3.6V      26.08mA    24.84mA    24.98mA
[Ramp]
dV/dt_r   0.614657/0.323286n  0.587844/0.3725n  0.684483/0.272406n
dV/dt_f   0.617746/0.30398n  0.575032/0.336399n  0.634508/0.310503n
R_load = 50
[Rising Waveform]
R_fixture = 50
V_fixture = 0
V_fixture_min = 0
V_fixture_max = 0
| Time   V(typ)   V(min)   V(max)
0s        14.06nV    35.92nV    18.68nV
1.571ns   768.3uV    493.3uV    -33.83mV
1.887ns   -2.767mV   592.6uV    842.6mV
2.133ns   -28.21mV   669.8uV    1.056V
2.308ns   385.7mV    775.9uV    1.106V
2.571ns   828.2mV    -7.254mV   1.129V
2.876ns   970.3mV    -40.96mV   1.135V
3.303ns   1.011V     682.6mV    1.139V
3.801ns   1.021V     937.3mV    1.141V
10ns      1.024V     979.7mV    1.141V
[Rising Waveform]
R_fixture = 50
V_fixture = 1.8
V_fixture_min = 1.71
V_fixture_max = 1.89
| Time   V(typ)   V(min)   V(max)
0s        770.4mV    751.6mV    832.5mV
1.392ns   770mV      751.4mV    831.9mV
1.733ns   769.9mV    751.3mV    1.744V
1.947ns   793.4mV    751.3mV    1.863V
2.061ns   1.104V     751.2mV    1.877V
2.392ns   1.728V     743.9mV    1.888V
2.624ns   1.782V     816.8mV    1.889V
3.036ns   1.797V     1.555V     1.89V
3.352ns   1.799V     1.688V     1.89V
10ns      1.8V       1.71V      1.89V
[Falling Waveform]
R_fixture = 50
V_fixture = 0
V_fixture_min = 0
V_fixture_max = 0
| Time   V(typ)   V(min)   V(max)
0s        1.024V     979.8mV    1.141V
1.441ns   1.024V     979.1mV    1.153V
1.712ns   1.024V     979mV      227.8mV
2.017ns   938.2mV    978.9mV    20.32mV
2.276ns   195mV      978.8mV    4.972mV
2.568ns   21.34mV    1.004V     1.088mV
2.726ns   9.159mV    904.9mV    606.2uV
3.051ns   2.131mV    157.7mV    158.6uV
3.335ns   793.7uV    23.11mV    -21.24uV
10ns      755.1nV    4.798uV    449.4nV
[Falling Waveform]
R_fixture = 50
V_fixture = 1.8
V_fixture_min = 1.71
V_fixture_max = 1.89
| Time   V(typ)   V(min)   V(max)
0s        1.8V       1.71V      1.89V
1.53ns    1.8V       1.709V     1.93V
1.886ns   1.798V     1.709V     1.181V
2.138ns   1.847V     1.709V     925.8mV
2.441ns   1.165V     1.708V     852.8mV
2.579ns   959.8mV    1.709V     845.4mV
2.881ns   813.8mV    1.758V     836.3mV
3.319ns   777.1mV    984.5mV    832.5mV
3.761ns   771.5mV    780.5mV    832.5mV
10ns      770.4mV    751.6mV    832.5mV
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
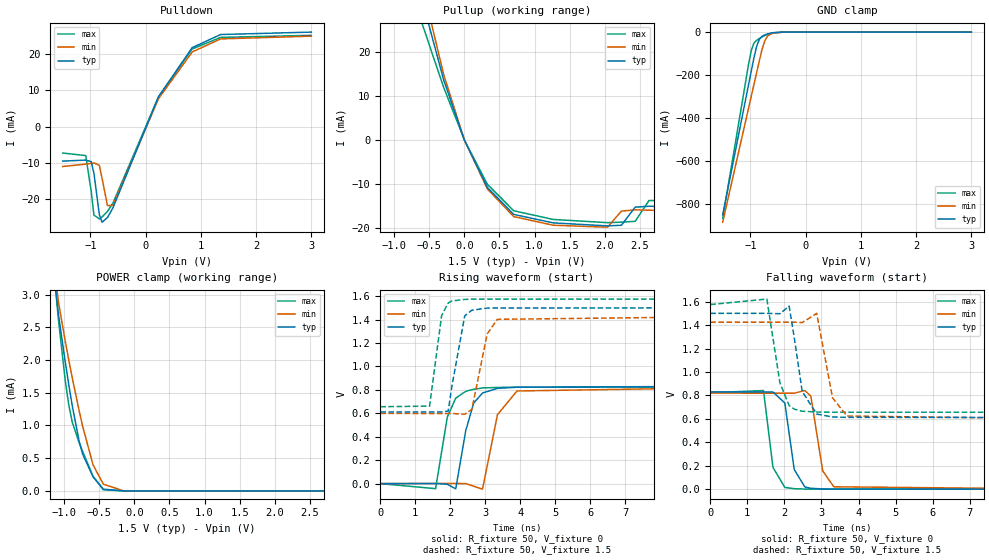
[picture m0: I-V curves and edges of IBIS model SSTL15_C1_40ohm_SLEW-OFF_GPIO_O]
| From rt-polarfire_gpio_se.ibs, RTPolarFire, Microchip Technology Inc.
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|   Model SSTL15_C1_40ohm_SLEW-OFF_GPIO_O
[Model]   SSTL15_C1_40ohm_SLEW-OFF_GPIO_O
Model_type   Output
Polarity   Non-Inverting
Enable   Active-High
Vmeas =   0.75
Cref =   5p
Rref =   50
Vref =   0.75
|   typ   min   max
C_comp_pullup   2.605e-12   2.605e-12   2.76e-12
C_comp_pulldown  2.605e-12   2.605e-12   2.76e-12
[Temperature Range]  25C   125C   -55C
[Voltage Range]  1.5   1.425   1.575
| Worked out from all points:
|   slope of the pulldown table from 0 to 0.225 V, typ, clamps not added: 28.5 ohm
|   slope of the pullup table from 0 to 0.225 V, typ, clamps not added: 28.4 ohm
|   GND clamp passes 1 mA (typ) near -0.52 V on its own axis
|   POWER clamp passes 1 mA (typ) near -0.84 V on its own axis
|   rising waveform, R_fixture 50, V_fixture 0: 20-80 % time 349ps typ, 371ps min, 319ps max; typ from 0 V to 0.83 V
|   rising waveform, R_fixture 50, V_fixture 1.5: 20-80 % time 256ps typ, 337ps min, 218ps max; typ from 0.611 V to 1.5 V
|   falling waveform, R_fixture 50, V_fixture 0: 20-80 % time 229ps typ, 254ps min, 185ps max; typ from 0.83 V to 0 V
|   falling waveform, R_fixture 50, V_fixture 1.5: 20-80 % time 269ps typ, 293ps min, 268ps max; typ from 1.5 V to 0.611 V
[GND Clamp]
| Voltage   I(typ)   I(min)   I(max)
-1.5V     -849.7mA   -884.3mA   -866.2mA
-1.034V   -246.6mA   -355.8mA   -152.2mA
-984.4mV  -183.1mA   -300.1mA   -86.85mA
-935.2mV  -119.9mA   -244.3mA   -51.18mA
-885.9mV  -66.33mA   -188.6mA   -38.3mA
-836.7mV  -33.59mA   -133mA     -29.88mA
-787.5mV  -19.44mA   -80.26mA   -22.39mA
-738.3mV  -12.87mA   -40.96mA   -15.82mA
-689.1mV  -8.545mA   -18.39mA   -10.35mA
-590.6mV  -2.947mA   -3.965mA   -3.201mA
-393.7mV  -37.64uA   -97.05uA   -25.54uA
3V        0A         0A         0A
[POWER Clamp]
| Voltage   I(typ)   I(min)   I(max)
-1.5V     10.9mA     9.514mA    12.44mA
-1.23V    4.091mA    4.166mA    4.314mA
-1.083V   2.694mA    2.882mA    2.611mA
-984.4mV  1.956mA    2.276mA    1.667mA
-935.2mV  1.615mA    1.995mA    1.306mA
-885.9mV  1.297mA    1.724mA    1.047mA
-787.5mV  756.7uA    1.22mA     734.9uA
-738.3mV  562.1uA    988.5uA    604.8uA
-590.6mV  217.4uA    399.3uA    223.5uA
-443mV    26.83uA    102.4uA    17.35uA
-147.7mV  138.9nA    118.7nA    456.7pA
3V        0A         0A         0A
[Pullup]
| Voltage   I(typ)   I(min)   I(max)
-1.5V     83.88mA    96.06mA    66.18mA
-1.083V   60.48mA    67.27mA    49.19mA
-295.3mV  13.68mA    14.91mA    11.99mA
0V        -138.7nA   14.08uA    24.92uA
328.1mV   -10.78mA   -11.12mA   -10.07mA
703.1mV   -16.9mA    -17.4mA    -16.07mA
1.266V    -18.83mA   -19.37mA   -18.05mA
2.041V    -19.52mA   -19.81mA   -18.78mA
2.238V    -19.38mA   -16.16mA   -18.67mA
2.435V    -15.25mA   -15.86mA   -18.48mA
2.632V    -15.04mA   -15.95mA   -13.74mA
3V        -15.17mA   -16.1mA    -13.76mA
[Pulldown]
| Voltage   I(typ)   I(min)   I(max)
-1.5V     -9.481mA   -10.95mA   -7.258mA
-1.083V   -9.197mA   -10.31mA   -7.961mA
-984.4mV  -9.613mA   -10.09mA   -17.78mA
-935.2mV  -12.77mA   -9.971mA   -24.28mA
-836.7mV  -24.21mA   -10.64mA   -25.34mA
-787.5mV  -26.24mA   -14.23mA   -24.8mA
-689.1mV  -24.96mA   -21.72mA   -23.27mA
-590.6mV  -22.29mA   -21.58mA   -21mA
234.4mV   8.197mA    7.68mA     8.163mA
843.8mV   21.66mA    20.48mA    21.3mA
1.359V    25.26mA    24.06mA    24.48mA
3V        25.93mA    24.81mA    25.04mA
[Ramp]
dV/dt_r   0.497983/0.348612n  0.491728/0.371315n  0.493662/0.318801n
dV/dt_f   0.533192/0.268755n  0.495594/0.293216n  0.551403/0.268375n
R_load = 50
[Rising Waveform]
R_fixture = 50
V_fixture = 0
V_fixture_min = 0
V_fixture_max = 0
| Time   V(typ)   V(min)   V(max)
0s        13.12nV    34.52nV    17.52nV
1.58ns    815.4uV    593.3uV    -43.22mV
1.914ns   -5.446mV   718.7uV    567.8mV
2.155ns   -45.14mV   809.2uV    729.5mV
2.442ns   453.4mV    260uV      788mV
2.668ns   687.7mV    -22.83mV   805.2mV
2.92ns    773.1mV    -47.49mV   816.2mV
3.347ns   813.1mV    588mV      820.7mV
3.905ns   822.8mV    790.6mV    822.6mV
10ns      830mV      819.5mV    822.8mV
[Rising Waveform]
R_fixture = 50
V_fixture = 1.5
V_fixture_min = 1.425
V_fixture_max = 1.575
| Time   V(typ)   V(min)   V(max)
0s        611.3mV    599mV      656mV
1.408ns   610.8mV    598.6mV    661.4mV
1.751ns   610.6mV    598.6mV    1.433V
1.941ns   619.6mV    598.5mV    1.542V
2.047ns   834.8mV    598.5mV    1.559V
2.412ns   1.432V     592.1mV    1.572V
2.615ns   1.48V      633.3mV    1.574V
3.053ns   1.498V     1.277V     1.575V
3.342ns   1.499V     1.402V     1.575V
10ns      1.5V       1.425V     1.575V
[Falling Waveform]
R_fixture = 50
V_fixture = 0
V_fixture_min = 0
V_fixture_max = 0
| Time   V(typ)   V(min)   V(max)
0s        830mV      819.5mV    822.8mV
1.436ns   829.2mV    819mV      841.5mV
1.691ns   829.1mV    818.9mV    185.6mV
2.012ns   735.4mV    818.8mV    14.63mV
2.265ns   167.8mV    818.7mV    4.086mV
2.552ns   18.46mV    841.7mV    1.149mV
2.713ns   7.821mV    793.4mV    450.1uV
3.033ns   1.554mV    156.3mV    57.55uV
3.332ns   637.9uV    20.33mV    55.1uV
10ns      645.2nV    4.565uV    458nV
[Falling Waveform]
R_fixture = 50
V_fixture = 1.5
V_fixture_min = 1.425
V_fixture_max = 1.575
| Time   V(typ)   V(min)   V(max)
0s        1.5V       1.425V     1.575V
1.526ns   1.5V       1.425V     1.622V
1.879ns   1.497V     1.425V     907.1mV
2.127ns   1.562V     1.425V     712.9mV
2.27ns    1.283V     1.425V     682mV
2.48ns    833.9mV    1.421V     665.1mV
2.871ns   640.8mV    1.5V       658.3mV
3.299ns   616.1mV    778.7mV    656.6mV
3.689ns   612.8mV    624.1mV    656.6mV
10ns      611.3mV    599mV      656mV
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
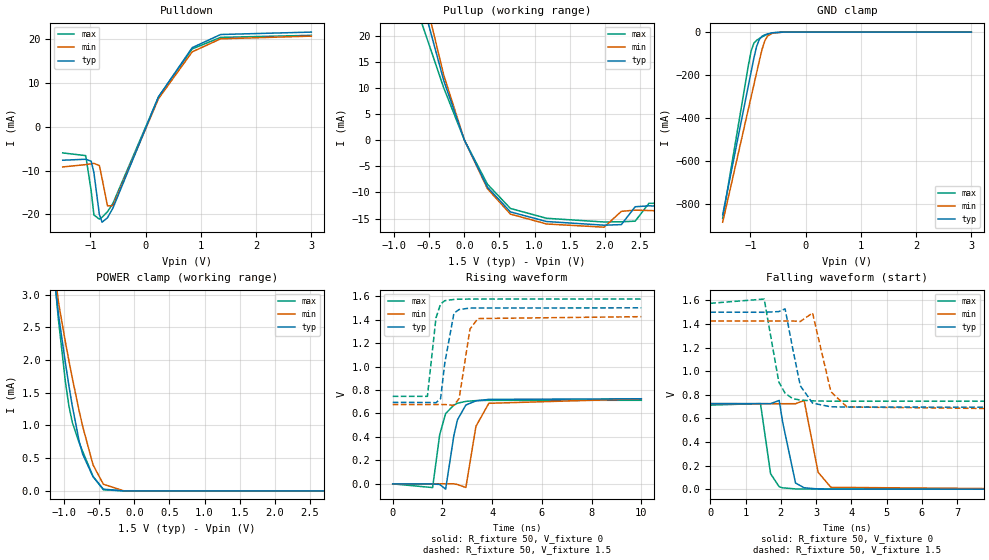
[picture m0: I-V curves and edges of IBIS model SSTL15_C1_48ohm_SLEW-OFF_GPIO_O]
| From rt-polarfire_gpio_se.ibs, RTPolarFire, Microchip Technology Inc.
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|   Model SSTL15_C1_48ohm_SLEW-OFF_GPIO_O
[Model]   SSTL15_C1_48ohm_SLEW-OFF_GPIO_O
Model_type   Output
Polarity   Non-Inverting
Enable   Active-High
Vmeas =   0.75
Cref =   5p
Rref =   50
Vref =   0.75
|   typ   min   max
C_comp_pullup   2.605e-12   2.605e-12   2.76e-12
C_comp_pulldown  2.605e-12   2.605e-12   2.76e-12
[Temperature Range]  25C   125C   -55C
[Voltage Range]  1.5   1.425   1.575
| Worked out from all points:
|   slope of the pulldown table from 0 to 0.225 V, typ, clamps not added: 34.2 ohm
|   slope of the pullup table from 0 to 0.225 V, typ, clamps not added: 34 ohm
|   GND clamp passes 1 mA (typ) near -0.52 V on its own axis
|   POWER clamp passes 1 mA (typ) near -0.84 V on its own axis
|   rising waveform, R_fixture 50, V_fixture 0: 20-80 % time 383ps typ, 406ps min, 342ps max; typ from 0 V to 0.725 V
|   rising waveform, R_fixture 50, V_fixture 1.5: 20-80 % time 280ps typ, 323ps min, 249ps max; typ from 0.694 V to 1.5 V
|   falling waveform, R_fixture 50, V_fixture 0: 20-80 % time 233ps typ, 290ps min, 187ps max; typ from 0.725 V to 0 V
|   falling waveform, R_fixture 50, V_fixture 1.5: 20-80 % time 324ps typ, 341ps min, 287ps max; typ from 1.5 V to 0.694 V
[GND Clamp]
| Voltage   I(typ)   I(min)   I(max)
-1.5V     -849.7mA   -884.3mA   -866.2mA
-1.034V   -246.6mA   -355.8mA   -152.2mA
-984.4mV  -183.1mA   -300.1mA   -86.85mA
-935.2mV  -119.9mA   -244.3mA   -51.18mA
-885.9mV  -66.33mA   -188.6mA   -38.3mA
-836.7mV  -33.59mA   -133mA     -29.88mA
-787.5mV  -19.44mA   -80.26mA   -22.39mA
-738.3mV  -12.87mA   -40.96mA   -15.82mA
-689.1mV  -8.545mA   -18.39mA   -10.35mA
-590.6mV  -2.947mA   -3.965mA   -3.201mA
-393.7mV  -37.64uA   -97.05uA   -25.54uA
3V        0A         0A         0A
[POWER Clamp]
| Voltage   I(typ)   I(min)   I(max)
-1.5V     10.9mA     9.514mA    12.44mA
-1.23V    4.091mA    4.166mA    4.314mA
-1.083V   2.694mA    2.882mA    2.611mA
-984.4mV  1.956mA    2.276mA    1.667mA
-935.2mV  1.615mA    1.995mA    1.306mA
-885.9mV  1.297mA    1.724mA    1.047mA
-787.5mV  756.7uA    1.22mA     734.9uA
-738.3mV  562.1uA    988.5uA    604.8uA
-590.6mV  217.4uA    399.3uA    223.5uA
-443mV    26.83uA    102.4uA    17.35uA
-147.7mV  138.9nA    118.7nA    456.7pA
3V        0A         0A         0A
[Pullup]
| Voltage   I(typ)   I(min)   I(max)
-1.5V     70.01mA    80.33mA    55.36mA
-1.083V   50.5mA     56.27mA    41.14mA
-295.3mV  11.42mA    12.47mA    10.03mA
0V        -138.7nA   11.81uA    20.9uA
328.1mV   -8.987mA   -9.285mA   -8.419mA
656.2mV   -13.72mA   -14.14mA   -13.06mA
1.172V    -15.56mA   -16.03mA   -14.94mA
1.992V    -16.26mA   -16.64mA   -15.65mA
2.238V    -16.15mA   -13.61mA   -15.61mA
2.435V    -12.73mA   -13.38mA   -15.49mA
2.632V    -12.56mA   -13.46mA   -12.07mA
3V        -12.67mA   -13.58mA   -12.11mA
[Pulldown]
| Voltage   I(typ)   I(min)   I(max)
-1.5V     -7.654mA   -9.189mA   -5.983mA
-1.083V   -7.43mA    -8.653mA   -6.6mA
-984.4mV  -7.883mA   -8.47mA    -14.66mA
-935.2mV  -10.5mA    -8.37mA    -20.15mA
-836.7mV  -20.02mA   -8.859mA   -21.11mA
-787.5mV  -21.8mA    -11.81mA   -20.67mA
-689.1mV  -20.78mA   -18.09mA   -19.4mA
-590.6mV  -18.57mA   -18.02mA   -17.51mA
234.4mV   6.831mA    6.414mA    6.81mA
843.8mV   18.05mA    17.09mA    17.76mA
1.359V    21.05mA    20.06mA    20.4mA
3V        21.6mA     20.68mA    20.86mA
[Ramp]
dV/dt_r   0.435212/0.383072n  0.434957/0.406429n  0.427402/0.342172n
dV/dt_f   0.483314/0.323801n  0.44909/0.341192n  0.497599/0.286961n
R_load = 50
[Rising Waveform]
R_fixture = 50
V_fixture = 0
V_fixture_min = 0
V_fixture_max = 0
| Time   V(typ)   V(min)   V(max)
0s        14.78nV    38.68nV    19.7nV
1.605ns   -664.3uV   620.5uV    -31.56mV
1.89ns    -5.019mV   730.6uV    419.3mV
2.13ns    -45.11mV   823.4uV    599.7mV
2.46ns    412.3mV    673.1uV    671.1mV
2.606ns   546.8mV    -5.697mV   687.3mV
2.943ns   672.2mV    -30.72mV   703.1mV
3.349ns   707.8mV    491.1mV    709.6mV
3.866ns   720mV      686.6mV    711.9mV
10ns      725.4mV    724.9mV    712.3mV
[Rising Waveform]
R_fixture = 50
V_fixture = 1.5
V_fixture_min = 1.425
V_fixture_max = 1.575
| Time   V(typ)   V(min)   V(max)
0s        694.5mV    676.5mV    745.7mV
1.396ns   693.9mV    676.3mV    746.1mV
1.741ns   691.6mV    676.3mV    1.415V
1.925ns   726mV      676.2mV    1.533V
2.094ns   1.029V     676.2mV    1.561V
2.464ns   1.455V     668.7mV    1.572V
2.673ns   1.486V     728.5mV    1.574V
3.107ns   1.498V     1.318V     1.575V
3.427ns   1.499V     1.409V     1.575V
10ns      1.5V       1.425V     1.575V
[Falling Waveform]
R_fixture = 50
V_fixture = 0
V_fixture_min = 0
V_fixture_max = 0
| Time   V(typ)   V(min)   V(max)
0s        725.3mV    724.8mV    712.3mV
1.423ns   724.6mV    724.3mV    725.4mV
1.71ns    724.5mV    724.2mV    130.5mV
1.953ns   752.1mV    724.2mV    20.8mV
2.052ns   567.4mV    724.1mV    11.33mV
2.417ns   51.74mV    724.2mV    2.169mV
2.661ns   11.87mV    751.6mV    964.6uV
3.057ns   1.915mV    143.1mV    912.5uV
3.419ns   343.5uV    15.66mV    865uV
10ns      645nV      6.795uV    628.5nV
[Falling Waveform]
R_fixture = 50
V_fixture = 1.5
V_fixture_min = 1.425
V_fixture_max = 1.575
| Time   V(typ)   V(min)   V(max)
0s        1.5V       1.425V     1.575V
1.528ns   1.499V     1.425V     1.611V
1.943ns   1.505V     1.425V     907.9mV
2.121ns   1.528V     1.425V     813.3mV
2.336ns   1.192V     1.425V     767mV
2.553ns   875.9mV    1.421V     755.1mV
2.899ns   729.2mV    1.493V     748.3mV
3.419ns   698mV      825.5mV    745.6mV
3.876ns   695.7mV    696.4mV    745.6mV
10ns      694.5mV    676.5mV    745.7mV
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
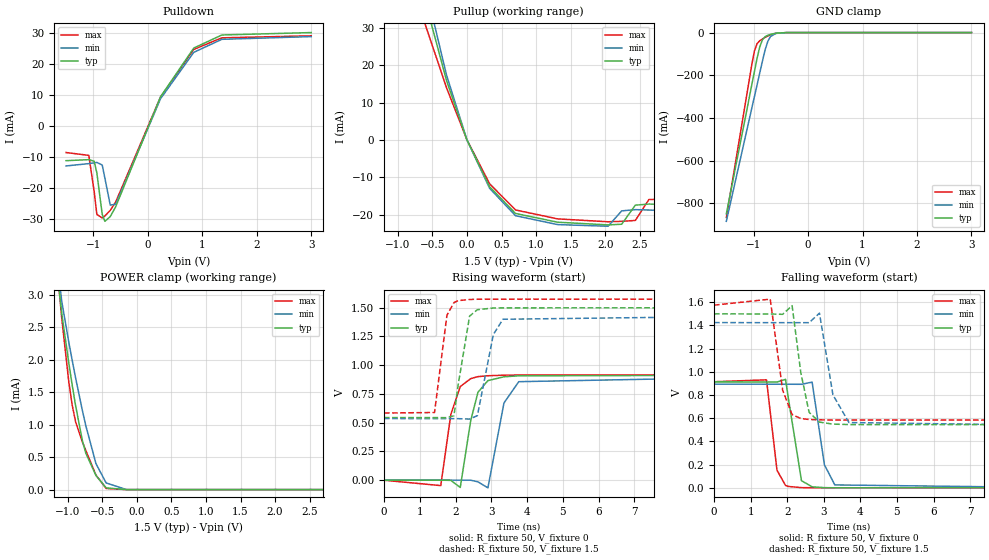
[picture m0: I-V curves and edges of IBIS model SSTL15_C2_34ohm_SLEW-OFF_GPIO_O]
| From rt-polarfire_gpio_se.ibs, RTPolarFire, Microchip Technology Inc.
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|   Model SSTL15_C2_34ohm_SLEW-OFF_GPIO_O
[Model]   SSTL15_C2_34ohm_SLEW-OFF_GPIO_O
Model_type   Output
Polarity   Non-Inverting
Enable   Active-High
Vmeas =   0.75
Cref =   5p
Rref =   50
Vref =   0.75
|   typ   min   max
C_comp_pullup   2.605e-12   2.605e-12   2.76e-12
C_comp_pulldown  2.605e-12   2.605e-12   2.76e-12
[Temperature Range]  25C   125C   -55C
[Voltage Range]  1.5   1.425   1.575
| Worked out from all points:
|   slope of the pulldown table from 0 to 0.225 V, typ, clamps not added: 24.5 ohm
|   slope of the pullup table from 0 to 0.225 V, typ, clamps not added: 24.4 ohm
|   GND clamp passes 1 mA (typ) near -0.52 V on its own axis
|   POWER clamp passes 1 mA (typ) near -0.84 V on its own axis
|   rising waveform, R_fixture 50, V_fixture 0: 20-80 % time 320ps typ, 340ps min, 299ps max; typ from 0 V to 0.913 V
|   rising waveform, R_fixture 50, V_fixture 1.5: 20-80 % time 240ps typ, 325ps min, 207ps max; typ from 0.545 V to 1.5 V
|   falling waveform, R_fixture 50, V_fixture 0: 20-80 % time 223ps typ, 255ps min, 181ps max; typ from 0.913 V to 0 V
|   falling waveform, R_fixture 50, V_fixture 1.5: 20-80 % time 248ps typ, 293ps min, 249ps max; typ from 1.5 V to 0.545 V
[GND Clamp]
| Voltage   I(typ)   I(min)   I(max)
-1.5V     -849.7mA   -884.3mA   -866.2mA
-1.034V   -246.6mA   -355.8mA   -152.2mA
-984.4mV  -183.1mA   -300.1mA   -86.85mA
-935.2mV  -119.9mA   -244.3mA   -51.18mA
-885.9mV  -66.33mA   -188.6mA   -38.3mA
-836.7mV  -33.59mA   -133mA     -29.88mA
-787.5mV  -19.44mA   -80.26mA   -22.39mA
-738.3mV  -12.87mA   -40.96mA   -15.82mA
-689.1mV  -8.545mA   -18.39mA   -10.35mA
-590.6mV  -2.947mA   -3.965mA   -3.201mA
-393.7mV  -37.64uA   -97.05uA   -25.54uA
3V        0A         0A         0A
[POWER Clamp]
| Voltage   I(typ)   I(min)   I(max)
-1.5V     10.9mA     9.514mA    12.44mA
-1.23V    4.091mA    4.166mA    4.314mA
-1.083V   2.694mA    2.882mA    2.611mA
-984.4mV  1.956mA    2.276mA    1.667mA
-935.2mV  1.615mA    1.995mA    1.306mA
-885.9mV  1.297mA    1.724mA    1.047mA
-787.5mV  756.7uA    1.22mA     734.9uA
-738.3mV  562.1uA    988.5uA    604.8uA
-590.6mV  217.4uA    399.3uA    223.5uA
-443mV    26.83uA    102.4uA    17.35uA
-147.7mV  138.9nA    118.7nA    456.7pA
3V        0A         0A         0A
[Pullup]
| Voltage   I(typ)   I(min)   I(max)
-1.5V     97.49mA    112mA      77.1mA
-1.083V   70.28mA    78.37mA    57.29mA
-295.3mV  15.91mA    17.37mA    13.97mA
0V        -138.7nA   16.37uA    28.91uA
328.1mV   -12.55mA   -12.97mA   -11.75mA
703.1mV   -19.7mA    -20.3mA    -18.76mA
1.312V    -22.04mA   -22.68mA   -21.15mA
2.041V    -22.76mA   -23.12mA   -21.92mA
2.238V    -22.58mA   -19.01mA   -21.8mA
2.435V    -17.48mA   -18.67mA   -21.57mA
2.632V    -17.18mA   -18.78mA   -15.95mA
3V        -17.33mA   -18.95mA   -15.96mA
[Pulldown]
| Voltage   I(typ)   I(min)   I(max)
-1.5V     -11.06mA   -12.76mA   -8.438mA
-1.083V   -10.73mA   -12.01mA   -9.352mA
-984.4mV  -11.24mA   -11.76mA   -21.01mA
-935.2mV  -15.01mA   -11.62mA   -28.41mA
-836.7mV  -28.35mA   -12.46mA   -29.52mA
-787.5mV  -30.61mA   -16.7mA    -28.89mA
-689.1mV  -29.08mA   -25.38mA   -27.08mA
-590.6mV  -25.96mA   -25.13mA   -24.42mA
234.4mV   9.546mA    8.942mA    9.494mA
843.8mV   25.25mA    23.88mA    24.82mA
1.359V    29.47mA    28.07mA    28.55mA
3V        30.25mA    28.95mA    29.21mA
[Ramp]
dV/dt_r   0.547789/0.320419n  0.536445/0.340383n  0.549/0.298749n
dV/dt_f   0.57295/0.247669n  0.533218/0.292755n  0.594321/0.248969n
R_load = 50
[Rising Waveform]
R_fixture = 50
V_fixture = 0
V_fixture_min = 0
V_fixture_max = 0
| Time   V(typ)   V(min)   V(max)
0s        11.81nV    31.17nV    15.79nV
1.588ns   786.5uV    497.8uV    -46.66mV
1.869ns   -1.184mV   585.9uV    572.8mV
2.133ns   -62.77mV   668.7uV    814.5mV
2.424ns   518mV      356.2uV    883.8mV
2.627ns   764.6mV    -13.93mV   900.9mV
2.905ns   866.3mV    -66.33mV   908.7mV
3.354ns   899.7mV    672.2mV    913.5mV
3.768ns   907.9mV    857.1mV    914.9mV
10ns      913mV      894.1mV    915mV
[Rising Waveform]
R_fixture = 50
V_fixture = 1.5
V_fixture_min = 1.425
V_fixture_max = 1.575
| Time   V(typ)   V(min)   V(max)
0s        545.1mV    536.3mV    584.5mV
1.413ns   544.5mV    535.7mV    588.8mV
1.76ns    544.1mV    535.6mV    1.435V
1.957ns   561mV      535.5mV    1.545V
2.074ns   830.1mV    535.5mV    1.562V
2.394ns   1.428V     531.9mV    1.572V
2.612ns   1.483V     561.9mV    1.574V
3.057ns   1.498V     1.267V     1.575V
3.325ns   1.499V     1.4V       1.575V
10ns      1.5V       1.425V     1.575V
[Falling Waveform]
R_fixture = 50
V_fixture = 0
V_fixture_min = 0
V_fixture_max = 0
| Time   V(typ)   V(min)   V(max)
0s        913mV      894mV      915mV
1.434ns   912.2mV    893.5mV    931.2mV
1.72ns    912mV      893.4mV    152.4mV
1.954ns   935.4mV    893.3mV    20.66mV
2.036ns   763.2mV    893.3mV    11.99mV
2.39ns    61.86mV    892.7mV    2.077mV
2.681ns   8.992mV    911.6mV    801.1uV
3.017ns   1.892mV    198.9mV    764.3uV
3.302ns   444.5uV    25.35mV    733.1uV
10ns      1.88uV     7.592uV    215.7nV
[Falling Waveform]
R_fixture = 50
V_fixture = 1.5
V_fixture_min = 1.425
V_fixture_max = 1.575
| Time   V(typ)   V(min)   V(max)
0s        1.5V       1.425V     1.575V
1.535ns   1.499V     1.424V     1.627V
1.876ns   1.496V     1.424V     840.9mV
2.133ns   1.571V     1.424V     632.4mV
2.371ns   994.9mV    1.424V     597.6mV
2.598ns   651.5mV    1.424V     589.3mV
2.882ns   566.8mV    1.506V     586.3mV
3.25ns    549.5mV    801.9mV    584.5mV
3.687ns   545.7mV    563.2mV    584.5mV
10ns      545.1mV    536.3mV    584.5mV
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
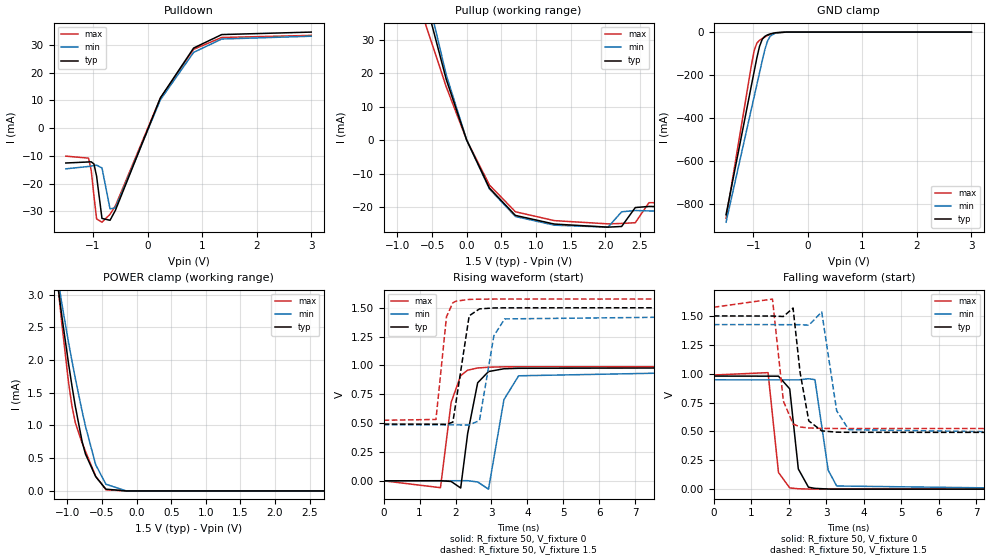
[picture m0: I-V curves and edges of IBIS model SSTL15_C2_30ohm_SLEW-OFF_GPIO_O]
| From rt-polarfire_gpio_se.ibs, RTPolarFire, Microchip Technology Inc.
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|   Model SSTL15_C2_30ohm_SLEW-OFF_GPIO_O
[Model]   SSTL15_C2_30ohm_SLEW-OFF_GPIO_O
Model_type   Output
Polarity   Non-Inverting
Enable   Active-High
Vmeas =   0.75
Cref =   5p
Rref =   50
Vref =   0.75
|   typ   min   max
C_comp_pullup   2.605e-12   2.605e-12   2.76e-12
C_comp_pulldown  2.605e-12   2.605e-12   2.76e-12
[Temperature Range]  25C   125C   -55C
[Voltage Range]  1.5   1.425   1.575
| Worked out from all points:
|   slope of the pulldown table from 0 to 0.225 V, typ, clamps not added: 21.5 ohm
|   slope of the pullup table from 0 to 0.225 V, typ, clamps not added: 21.3 ohm
|   GND clamp passes 1 mA (typ) near -0.52 V on its own axis
|   POWER clamp passes 1 mA (typ) near -0.84 V on its own axis
|   rising waveform, R_fixture 50, V_fixture 0: 20-80 % time 288ps typ, 323ps min, 268ps max; typ from 0 V to 0.979 V
|   rising waveform, R_fixture 50, V_fixture 1.5: 20-80 % time 246ps typ, 310ps min, 186ps max; typ from 0.491 V to 1.5 V
|   falling waveform, R_fixture 50, V_fixture 0: 20-80 % time 195ps typ, 251ps min, 169ps max; typ from 0.979 V to 0 V
|   falling waveform, R_fixture 50, V_fixture 1.5: 20-80 % time 217ps typ, 248ps min, 206ps max; typ from 1.5 V to 0.491 V
[GND Clamp]
| Voltage   I(typ)   I(min)   I(max)
-1.5V     -849.7mA   -884.3mA   -866.2mA
-1.034V   -246.6mA   -355.8mA   -152.2mA
-984.4mV  -183.1mA   -300.1mA   -86.85mA
-935.2mV  -119.9mA   -244.3mA   -51.18mA
-885.9mV  -66.33mA   -188.6mA   -38.3mA
-836.7mV  -33.59mA   -133mA     -29.88mA
-787.5mV  -19.44mA   -80.26mA   -22.39mA
-738.3mV  -12.87mA   -40.96mA   -15.82mA
-689.1mV  -8.545mA   -18.39mA   -10.35mA
-590.6mV  -2.947mA   -3.965mA   -3.201mA
-393.7mV  -37.64uA   -97.05uA   -25.54uA
3V        0A         0A         0A
[POWER Clamp]
| Voltage   I(typ)   I(min)   I(max)
-1.5V     10.9mA     9.514mA    12.44mA
-1.132V   3.099mA    3.218mA    3.095mA
-1.083V   2.694mA    2.882mA    2.585mA
-984.4mV  1.956mA    2.276mA    1.667mA
-935.2mV  1.615mA    1.995mA    1.306mA
-885.9mV  1.297mA    1.724mA    1.047mA
-787.5mV  756.7uA    1.22mA     734.9uA
-738.3mV  562.1uA    988.5uA    604.8uA
-590.6mV  217.4uA    399.3uA    223.5uA
-443mV    26.83uA    102.4uA    17.35uA
-147.7mV  138.9nA    118.7nA    456.7pA
3V        0A         0A         0A
[Pullup]
| Voltage   I(typ)   I(min)   I(max)
-1.5V     111.3mA    125.9mA    88.08mA
-1.132V   84.15mA    92.67mA    68.37mA
-295.3mV  18.15mA    19.51mA    15.94mA
0V        -138.7nA   18.35uA    32.98uA
328.1mV   -14.33mA   -14.58mA   -13.41mA
703.1mV   -22.51mA   -22.84mA   -21.42mA
1.266V    -25.1mA    -25.43mA   -24.07mA
2.041V    -26.02mA   -26.03mA   -25.04mA
2.238V    -25.82mA   -21.43mA   -24.92mA
2.435V    -20.16mA   -21.05mA   -24.69mA
2.632V    -19.82mA   -21.17mA   -18.7mA
3V        -20mA      -21.36mA   -18.73mA
[Pulldown]
| Voltage   I(typ)   I(min)   I(max)
-1.5V     -12.55mA   -14.65mA   -10.08mA
-1.083V   -12.17mA   -13.79mA   -10.79mA
-1.034V   -12.12mA   -13.64mA   -15.16mA
-984.4mV  -12.87mA   -13.49mA   -24.29mA
-935.2mV  -17.31mA   -13.33mA   -32.67mA
-836.7mV  -32.49mA   -14.33mA   -33.85mA
-689.1mV  -33.16mA   -29.06mA   -31.03mA
-590.6mV  -29.58mA   -28.68mA   -27.97mA
234.4mV   10.88mA    10.2mA     10.87mA
843.8mV   28.83mA    27.27mA    28.38mA
1.359V    33.68mA    32.08mA    32.63mA
3V        34.57mA    33.08mA    33.38mA
[Ramp]
dV/dt_r   0.587499/0.288311n  0.567986/0.323357n  0.593159/0.268416n
dV/dt_f   0.605181/0.217442n  0.564114/0.247622n  0.630036/0.205581n
R_load = 50
[Rising Waveform]
R_fixture = 50
V_fixture = 0
V_fixture_min = 0
V_fixture_max = 0
| Time   V(typ)   V(min)   V(max)
0s        10.75nV    28.42nV    14.32nV
1.581ns   714.8uV    672.3uV    -59.4mV
1.877ns   -5.552mV   798.1uV    679.1mV
2.143ns   -62.26mV   911.2uV    911.3mV
2.337ns   409.9mV    993.7uV    958.8mV
2.615ns   849.2mV    -9.903mV   977.7mV
2.917ns   946.9mV    -72.36mV   984.4mV
3.346ns   971mV      703.4mV    987.8mV
3.755ns   975.1mV    910.1mV    988.3mV
10ns      979.2mV    946.6mV    988.6mV
[Rising Waveform]
R_fixture = 50
V_fixture = 1.5
V_fixture_min = 1.425
V_fixture_max = 1.575
| Time   V(typ)   V(min)   V(max)
0s        491.4mV    484.8mV    524.9mV
1.455ns   490.6mV    484.8mV    531.7mV
1.748ns   489.3mV    484.7mV    1.422V
1.925ns   508.7mV    484.7mV    1.543V
2.014ns   685.7mV    484.7mV    1.557V
2.379ns   1.43V      483.6mV    1.572V
2.666ns   1.49V      522.4mV    1.574V
3.066ns   1.498V     1.257V     1.575V
3.367ns   1.499V     1.403V     1.575V
10ns      1.5V       1.425V     1.575V
[Falling Waveform]
R_fixture = 50
V_fixture = 0
V_fixture_min = 0
V_fixture_max = 0
| Time   V(typ)   V(min)   V(max)
0s        979.2mV    946.7mV    988.6mV
1.447ns   978.5mV    946.2mV    1.009V
1.725ns   978.2mV    946.1mV    144.8mV
2.025ns   868.6mV    946mV      10.7mV
2.254ns   175mV      945.9mV    3.604mV
2.524ns   17.06mV    956.2mV    1.027mV
2.697ns   6.918mV    948.3mV    474.2uV
3.05ns    1.395mV    164.4mV    47.45uV
3.277ns   407.1uV    27.59mV    45.91uV
10ns      -434.7nV   4.916uV    424.4nV
[Falling Waveform]
R_fixture = 50
V_fixture = 1.5
V_fixture_min = 1.425
V_fixture_max = 1.575
| Time   V(typ)   V(min)   V(max)
0s        1.5V       1.425V     1.575V
1.565ns   1.499V     1.425V     1.646V
1.856ns   1.495V     1.424V     762.7mV
2.114ns   1.568V     1.424V     564.8mV
2.302ns   1.009V     1.424V     538.2mV
2.533ns   591.2mV    1.42V      529.8mV
2.878ns   504.8mV    1.534V     526.2mV
3.277ns   493.6mV    678.3mV    525.2mV
3.599ns   492.2mV    515.2mV    525.2mV
10ns      491.4mV    484.8mV    524.9mV
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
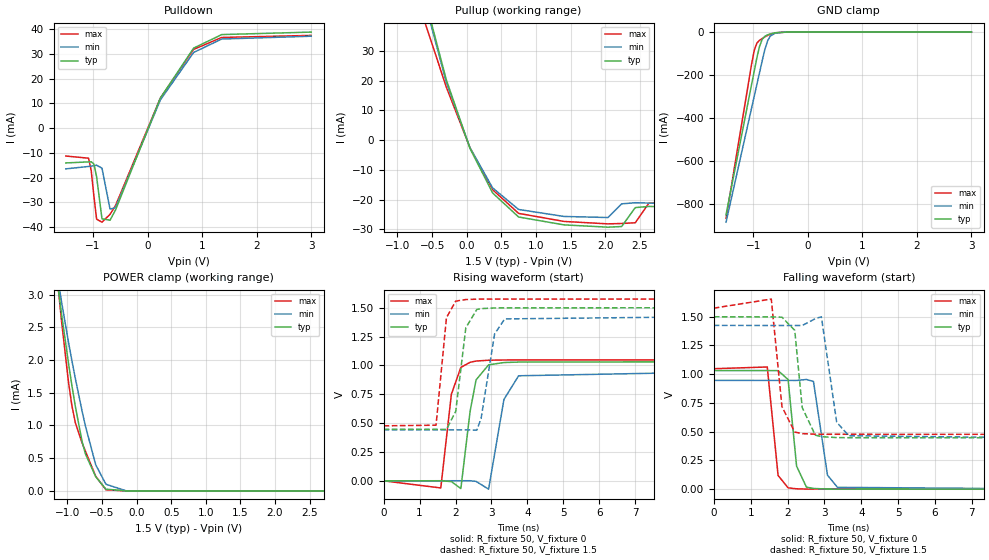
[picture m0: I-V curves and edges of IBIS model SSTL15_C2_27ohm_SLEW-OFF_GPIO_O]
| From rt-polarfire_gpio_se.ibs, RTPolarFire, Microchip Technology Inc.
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|   Model SSTL15_C2_27ohm_SLEW-OFF_GPIO_O
[Model]   SSTL15_C2_27ohm_SLEW-OFF_GPIO_O
Model_type   Output
Polarity   Non-Inverting
Enable   Active-High
Vmeas =   0.75
Cref =   5p
Rref =   50
Vref =   0.75
|   typ   min   max
C_comp_pullup   2.605e-12   2.605e-12   2.76e-12
C_comp_pulldown  2.605e-12   2.605e-12   2.76e-12
[Temperature Range]  25C   125C   -55C
[Voltage Range]  1.5   1.425   1.575
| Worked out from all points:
|   slope of the pulldown table from 0 to 0.225 V, typ, clamps not added: 19.1 ohm
|   slope of the pullup table from 0 to 0.225 V, typ, clamps not added: 19 ohm
|   GND clamp passes 1 mA (typ) near -0.52 V on its own axis
|   POWER clamp passes 1 mA (typ) near -0.84 V on its own axis
|   rising waveform, R_fixture 50, V_fixture 0: 20-80 % time 266ps typ, 323ps min, 251ps max; typ from 0 V to 1.03 V
|   rising waveform, R_fixture 50, V_fixture 1.5: 20-80 % time 245ps typ, 301ps min, 182ps max; typ from 0.447 V to 1.5 V
|   falling waveform, R_fixture 50, V_fixture 0: 20-80 % time 190ps typ, 251ps min, 164ps max; typ from 1.03 V to 0 V
|   falling waveform, R_fixture 50, V_fixture 1.5: 20-80 % time 209ps typ, 250ps min, 194ps max; typ from 1.5 V to 0.447 V
[GND Clamp]
| Voltage   I(typ)   I(min)   I(max)
-1.5V     -849.7mA   -884.3mA   -866.2mA
-1.034V   -246.6mA   -355.8mA   -152.2mA
-984.4mV  -183.1mA   -300.1mA   -86.85mA
-935.2mV  -119.9mA   -244.3mA   -51.18mA
-885.9mV  -66.33mA   -188.6mA   -38.3mA
-836.7mV  -33.59mA   -133mA     -29.88mA
-787.5mV  -19.44mA   -80.26mA   -22.39mA
-738.3mV  -12.87mA   -40.96mA   -15.82mA
-689.1mV  -8.545mA   -18.39mA   -10.35mA
-590.6mV  -2.947mA   -3.965mA   -3.201mA
-393.7mV  -37.64uA   -97.05uA   -25.54uA
3V        0A         0A         0A
[POWER Clamp]
| Voltage   I(typ)   I(min)   I(max)
-1.5V     10.9mA     9.514mA    12.44mA
-1.132V   3.099mA    3.218mA    3.095mA
-1.083V   2.694mA    2.882mA    2.585mA
-984.4mV  1.956mA    2.276mA    1.667mA
-935.2mV  1.615mA    1.995mA    1.306mA
-885.9mV  1.297mA    1.724mA    1.047mA
-787.5mV  756.7uA    1.22mA     734.9uA
-738.3mV  562.1uA    988.5uA    604.8uA
-590.6mV  217.4uA    399.3uA    223.5uA
-443mV    26.83uA    102.4uA    17.35uA
-147.7mV  138.9nA    118.7nA    456.7pA
3V        0A         0A         0A
[Pullup]
| Voltage   I(typ)   I(min)   I(max)
-1.5V     125mA      125.9mA    98.99mA
-1.132V   94.47mA    92.67mA    76.81mA
-295.3mV  20.38mA    19.51mA    17.91mA
46.88mV   -2.763mA   -2.497mA   -2.537mA
375mV     -17.79mA   -16.09mA   -16.69mA
750mV     -25.86mA   -23.32mA   -24.64mA
1.406V    -28.51mA   -25.67mA   -27.35mA
2.041V    -29.28mA   -26.03mA   -28.17mA
2.238V    -29.06mA   -21.43mA   -28.04mA
2.435V    -22.69mA   -21.05mA   -27.79mA
2.632V    -22.3mA    -21.17mA   -21.17mA
3V        -22.5mA    -21.36mA   -21.19mA
[Pulldown]
| Voltage   I(typ)   I(min)   I(max)
-1.5V     -14.06mA   -16.46mA   -11.26mA
-1.083V   -13.64mA   -15.49mA   -12.15mA
-1.034V   -13.59mA   -15.33mA   -17.18mA
-984.4mV  -14.5mA    -15.16mA   -27.53mA
-935.2mV  -19.64mA   -14.98mA   -36.82mA
-836.7mV  -36.66mA   -16.18mA   -38.04mA
-689.1mV  -37.23mA   -32.73mA   -34.86mA
-590.6mV  -33.19mA   -32.2mA    -31.41mA
234.4mV   12.21mA    11.46mA    12.2mA
843.8mV   32.4mA     30.65mA    31.9mA
1.359V    37.88mA    36.08mA    36.71mA
3V        38.89mA    37.22mA    37.55mA
[Ramp]
dV/dt_r   0.619455/0.266146n  0.568061/0.32343n  0.628935/0.250579n
dV/dt_f   0.631786/0.209055n  0.589692/0.249906n  0.658999/0.194297n
R_load = 50
[Rising Waveform]
R_fixture = 50
V_fixture = 0
V_fixture_min = 0
V_fixture_max = 0
| Time   V(typ)   V(min)   V(max)
0s        9.866nV    26.11nV    13.13nV
1.59ns    753.8uV    584.2uV    -61.62mV
1.885ns   -6.446mV   692.6uV    750.4mV
2.149ns   -66.78mV   789.6uV    982.9mV
2.406ns   602.2mV    890uV      1.027V
2.572ns   874.6mV    -4.821mV   1.038V
2.921ns   1.005V     -72.23mV   1.045V
3.348ns   1.025V     705.6mV    1.047V
3.757ns   1.029V     910.3mV    1.048V
10ns      1.032V     946.8mV    1.048V
[Rising Waveform]
R_fixture = 50
V_fixture = 1.5
V_fixture_min = 1.425
V_fixture_max = 1.575
| Time   V(typ)   V(min)   V(max)
0s        447mV      442.2mV    476.7mV
1.458ns   446.3mV    441.9mV    482.1mV
1.748ns   445.5mV    441.8mV    1.414V
2.006ns   602.2mV    441.8mV    1.557V
2.287ns   1.326V     441.7mV    1.571V
2.593ns   1.485V     439mV      1.574V
2.712ns   1.492V     540.1mV    1.575V
3.088ns   1.498V     1.273V     1.575V
3.37ns    1.499V     1.403V     1.575V
10ns      1.5V       1.425V     1.575V
[Falling Waveform]
R_fixture = 50
V_fixture = 0
V_fixture_min = 0
V_fixture_max = 0
| Time   V(typ)   V(min)   V(max)
0s        1.032V     946.7mV    1.048V
1.451ns   1.032V     946.2mV    1.063V
1.744ns   1.031V     946.1mV    119.1mV
2.016ns   954mV      946mV      11.28mV
2.246ns   200.3mV    945.9mV    3.076mV
2.513ns   17.64mV    954.5mV    861.2uV
2.704ns   6.089mV    936.7mV    560.8uV
3.084ns   1.023mV    121.5mV    531.6uV
3.355ns   349uV      15.97mV    510.8uV
10ns      1.539uV    4.445uV    122.5nV
[Falling Waveform]
R_fixture = 50
V_fixture = 1.5
V_fixture_min = 1.425
V_fixture_max = 1.575
| Time   V(typ)   V(min)   V(max)
0s        1.5V       1.425V     1.575V
1.56ns    1.499V     1.424V     1.654V
1.849ns   1.496V     1.424V     718.3mV
2.196ns   1.382V     1.424V     496.7mV
2.398ns   710.6mV    1.424V     483.3mV
2.752ns   470.4mV    1.483V     478.1mV
2.918ns   457mV      1.5V       477.6mV
3.333ns   448.8mV    583.1mV    477.6mV
3.661ns   447.8mV    464.7mV    477.5mV
10ns      447mV      442.2mV    476.7mV
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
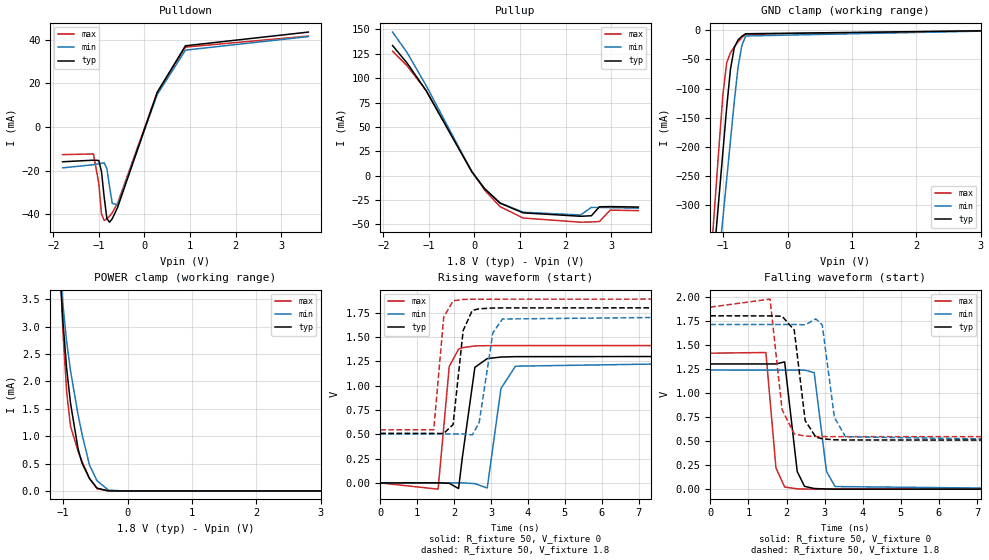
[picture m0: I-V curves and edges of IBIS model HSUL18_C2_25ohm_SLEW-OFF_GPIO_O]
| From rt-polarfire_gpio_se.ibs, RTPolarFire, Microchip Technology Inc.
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|   Model HSUL18_C2_25ohm_SLEW-OFF_GPIO_O
[Model]   HSUL18_C2_25ohm_SLEW-OFF_GPIO_O
Model_type   Output
Polarity   Non-Inverting
Enable   Active-High
Vmeas =   0.9
Cref =   5p
Rref =   50
Vref =   0.9
|   typ   min   max
C_comp_pullup   2.605e-12   2.605e-12   2.76e-12
C_comp_pulldown  2.605e-12   2.605e-12   2.76e-12
[Temperature Range]  25C   125C   -55C
[Voltage Range]  1.8   1.71   1.89
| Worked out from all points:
|   slope of the pulldown table from 0 to 0.27 V, typ, clamps not added: 17.6 ohm
|   slope of the pullup table from 0 to 0.27 V, typ, clamps not added: 17 ohm
|   GND clamp passes 1 mA (typ) near -0.52 V on its own axis
|   POWER clamp passes 1 mA (typ) near -0.81 V on its own axis
|   rising waveform, R_fixture 50, V_fixture 0: 20-80 % time 225ps typ, 264ps min, 184ps max; typ from 0 V to 1.3 V
|   rising waveform, R_fixture 50, V_fixture 1.8: 20-80 % time 211ps typ, 283ps min, 153ps max; typ from 0.509 V to 1.8 V
|   falling waveform, R_fixture 50, V_fixture 0: 20-80 % time 184ps typ, 217ps min, 161ps max; typ from 1.3 V to 0 V
|   falling waveform, R_fixture 50, V_fixture 1.8: 20-80 % time 229ps typ, 240ps min, 207ps max; typ from 1.8 V to 0.509 V
[GND Clamp]
| Voltage   I(typ)   I(min)   I(max)
-1.8V     -1.238A    -1.225A    -1.327A
-1.181V   -437.3mA   -523.2mA   -378.1mA
-1.122V   -361mA     -456.2mA   -287.7mA
-1.063V   -284.7mA   -389.3mA   -197.3mA
-1.004V   -208.5mA   -322.4mA   -110.3mA
-945mV    -132.4mA   -255.5mA   -55.69mA
-885.9mV  -66.33mA   -188.6mA   -38.3mA
-826.9mV  -29.63mA   -121.9mA   -28.32mA
-767.8mV  -16.36mA   -62.59mA   -19.64mA
-708.7mV  -10.12mA   -25.53mA   -12.4mA
-649.7mV  -5.882mA   -9.682mA   -6.873mA
3.6V      0A         0A         0A
[POWER Clamp]
| Voltage   I(typ)   I(min)   I(max)
-1.8V     45.61mA    34mA       62.13mA
-1.063V   4.301mA    4.351mA    4.537mA
-1.004V   3.099mA    3.407mA    2.918mA
-945mV    2.226mA    2.718mA    1.799mA
-885.9mV  1.604mA    2.194mA    1.183mA
-767.8mV  765.5uA    1.388mA    720.7uA
-708.7mV  512.4uA    1.046mA    541.9uA
-590.6mV  225.1uA    468.8uA    230.2uA
-472.5mV  50.43uA    184.8uA    39.22uA
-295.3mV  280.4nA    13.94uA    892.7nA
-59.06mV  411.5pA    7.346nA    109nA
3.6V      0A         0A         0A
[Pullup]
| Voltage   I(typ)   I(min)   I(max)
-1.8V     133.4mA    147.2mA    127.5mA
-1.477V   115.2mA    125.9mA    112.4mA
-1.063V   87.19mA    92.41mA    87.32mA
-59.06mV  3.999mA    4.04mA     4.529mA
225mV     -13.51mA   -13.39mA   -14.98mA
562.5mV   -28.25mA   -27.88mA   -31.79mA
1.069V    -38.14mA   -37.5mA    -43.47mA
2.332V    -41.65mA   -40.32mA   -47.72mA
2.568V    -41.12mA   -32.53mA   -47.46mA
2.745V    -31.93mA   -32.59mA   -47.05mA
2.981V    -31.74mA   -32.8mA    -35.37mA
3.6V      -32.19mA   -33.28mA   -35.85mA
[Pulldown]
| Voltage   I(typ)   I(min)   I(max)
-1.8V     -15.93mA   -18.71mA   -12.65mA
-1.122V   -15.2mA    -17.28mA   -12.34mA
-1.004V   -15.33mA   -16.85mA   -25.79mA
-945mV    -20.38mA   -16.62mA   -39.74mA
-885.9mV  -32.1mA    -16.37mA   -42.81mA
-826.9mV  -41.9mA    -19.02mA   -42.08mA
-767.8mV  -43.59mA   -27.26mA   -40.87mA
-708.7mV  -42.02mA   -34.96mA   -39.3mA
-590.6mV  -36.79mA   -35.7mA    -34.84mA
281.2mV   15.9mA     14.93mA    15.87mA
900mV     37.18mA    35.19mA    36.58mA
3.6V      43.45mA    41.4mA     41.63mA
[Ramp]
dV/dt_r   0.780228/0.225338n  0.741944/0.264311n  0.847388/0.184359n
dV/dt_f   0.774419/0.228918n  0.72379/0.240459n  0.807019/0.206974n
R_load = 50
[Rising Waveform]
R_fixture = 50
V_fixture = 0
V_fixture_min = 0
V_fixture_max = 0
| Time   V(typ)   V(min)   V(max)
0s        9.772nV    25.13nV    12.93nV
1.566ns   804.7uV    527.3uV    -64.33mV
1.868ns   -4.103mV   629uV      1.197V
2.121ns   -57.87mV   714.2uV    1.375V
2.22ns    253.7mV    747.6uV    1.39V
2.562ns   1.188V     -7.381mV   1.408V
2.897ns   1.278V     -52.83mV   1.411V
3.269ns   1.294V     971.1mV    1.412V
3.661ns   1.298V     1.2V       1.412V
10ns      1.3V       1.237V     1.412V
[Rising Waveform]
R_fixture = 50
V_fixture = 1.8
V_fixture_min = 1.71
V_fixture_max = 1.89
| Time   V(typ)   V(min)   V(max)
0s        509.3mV    503.7mV    545mV
1.448ns   508.8mV    503.4mV    546.8mV
1.718ns   508.7mV    503.3mV    1.703V
1.972ns   599.7mV    503.2mV    1.872V
2.245ns   1.567V     503.2mV    1.886V
2.493ns   1.774V     493mV      1.889V
2.678ns   1.79V      619.8mV    1.889V
3.049ns   1.798V     1.542V     1.889V
3.309ns   1.799V     1.685V     1.889V
10ns      1.8V       1.71V      1.89V
[Falling Waveform]
R_fixture = 50
V_fixture = 0
V_fixture_min = 0
V_fixture_max = 0
| Time   V(typ)   V(min)   V(max)
0s        1.3V       1.237V     1.412V
1.459ns   1.3V       1.236V     1.419V
1.723ns   1.3V       1.236V     220.8mV
1.951ns   1.322V     1.236V     22.35mV
2.281ns   182.5mV    1.236V     3.393mV
2.472ns   29.36mV    1.237V     1.41mV
2.726ns   6.995mV    1.21V      635.9uV
3.048ns   1.618mV    185.2mV    607.7uV
3.274ns   565.1uV    27.05mV    588uV
10ns      87.07nV    5.27uV     51.24nV
[Falling Waveform]
R_fixture = 50
V_fixture = 1.8
V_fixture_min = 1.71
V_fixture_max = 1.89
| Time   V(typ)   V(min)   V(max)
0s        1.8V       1.71V      1.89V
1.568ns   1.799V     1.71V      1.974V
1.883ns   1.796V     1.71V      827.6mV
2.203ns   1.652V     1.71V      573.7mV
2.489ns   712.7mV    1.706V     551.5mV
2.768ns   541.2mV    1.768V     546.8mV
2.937ns   523.5mV    1.706V     545.9mV
3.256ns   512.3mV    745.3mV    545.2mV
3.546ns   510.7mV    544.3mV    545.2mV
10ns      509.3mV    503.7mV    545mV
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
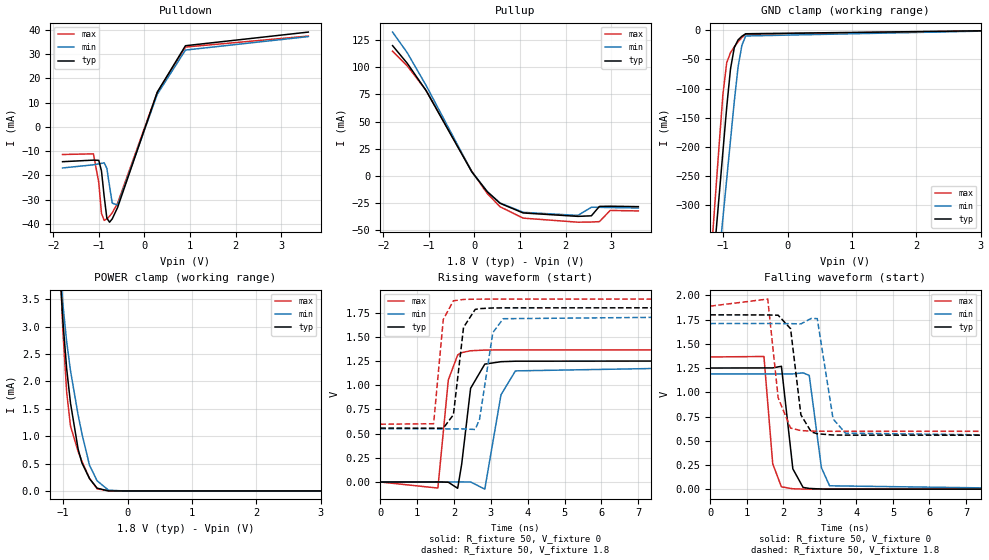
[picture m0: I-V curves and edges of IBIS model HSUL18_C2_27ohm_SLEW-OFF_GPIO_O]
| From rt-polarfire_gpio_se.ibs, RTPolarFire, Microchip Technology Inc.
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|   Model HSUL18_C2_27ohm_SLEW-OFF_GPIO_O
[Model]   HSUL18_C2_27ohm_SLEW-OFF_GPIO_O
Model_type   Output
Polarity   Non-Inverting
Enable   Active-High
Vmeas =   0.9
Cref =   5p
Rref =   50
Vref =   0.9
|   typ   min   max
C_comp_pullup   2.605e-12   2.605e-12   2.76e-12
C_comp_pulldown  2.605e-12   2.605e-12   2.76e-12
[Temperature Range]  25C   125C   -55C
[Voltage Range]  1.8   1.71   1.89
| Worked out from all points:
|   slope of the pulldown table from 0 to 0.27 V, typ, clamps not added: 19.5 ohm
|   slope of the pullup table from 0 to 0.27 V, typ, clamps not added: 18.9 ohm
|   GND clamp passes 1 mA (typ) near -0.52 V on its own axis
|   POWER clamp passes 1 mA (typ) near -0.81 V on its own axis
|   rising waveform, R_fixture 50, V_fixture 0: 20-80 % time 248ps typ, 290ps min, 202ps max; typ from 0 V to 1.25 V
|   rising waveform, R_fixture 50, V_fixture 1.8: 20-80 % time 224ps typ, 272ps min, 162ps max; typ from 0.557 V to 1.8 V
|   falling waveform, R_fixture 50, V_fixture 0: 20-80 % time 186ps typ, 239ps min, 159ps max; typ from 1.25 V to 0 V
|   falling waveform, R_fixture 50, V_fixture 1.8: 20-80 % time 236ps typ, 277ps min, 223ps max; typ from 1.8 V to 0.557 V
[GND Clamp]
| Voltage   I(typ)   I(min)   I(max)
-1.8V     -1.238A    -1.225A    -1.327A
-1.181V   -437.3mA   -523.2mA   -378.1mA
-1.122V   -361mA     -456.2mA   -287.7mA
-1.063V   -284.7mA   -389.3mA   -197.3mA
-1.004V   -208.5mA   -322.4mA   -110.3mA
-945mV    -132.4mA   -255.5mA   -55.69mA
-885.9mV  -66.33mA   -188.6mA   -38.3mA
-826.9mV  -29.63mA   -121.9mA   -28.32mA
-767.8mV  -16.36mA   -62.59mA   -19.64mA
-708.7mV  -10.12mA   -25.53mA   -12.4mA
-649.7mV  -5.882mA   -9.682mA   -6.873mA
3.6V      0A         0A         0A
[POWER Clamp]
| Voltage   I(typ)   I(min)   I(max)
-1.8V     45.61mA    34mA       62.13mA
-1.063V   4.301mA    4.351mA    4.537mA
-1.004V   3.099mA    3.407mA    2.918mA
-945mV    2.226mA    2.718mA    1.799mA
-885.9mV  1.604mA    2.194mA    1.183mA
-767.8mV  765.5uA    1.388mA    720.7uA
-708.7mV  512.4uA    1.046mA    541.9uA
-590.6mV  225.1uA    468.8uA    230.2uA
-472.5mV  50.43uA    184.8uA    39.22uA
-295.3mV  280.4nA    13.94uA    892.7nA
-59.06mV  411.5pA    7.346nA    109nA
3.6V      0A         0A         0A
[Pullup]
| Voltage   I(typ)   I(min)   I(max)
-1.8V     120mA      132.5mA    114.9mA
-1.477V   103.7mA    113.4mA    101.3mA
-1.063V   78.5mA     83.25mA    78.73mA
-59.06mV  3.603mA    3.64mA     4.084mA
281.2mV   -14.8mA    -14.66mA   -16.47mA
562.5mV   -25.45mA   -25.1mA    -28.63mA
1.069V    -34.34mA   -33.76mA   -39.12mA
2.272V    -37.49mA   -36.62mA   -42.86mA
2.568V    -36.97mA   -29.09mA   -42.71mA
2.745V    -28.29mA   -29.15mA   -42.35mA
2.981V    -28.12mA   -29.34mA   -32.04mA
3.6V      -28.51mA   -29.77mA   -32.47mA
[Pulldown]
| Voltage   I(typ)   I(min)   I(max)
-1.8V     -14.33mA   -16.91mA   -11.36mA
-1.122V   -13.68mA   -15.61mA   -11.09mA
-1.004V   -13.77mA   -15.23mA   -22.96mA
-945mV    -18.15mA   -15.02mA   -35.62mA
-885.9mV  -28.61mA   -14.79mA   -38.53mA
-826.9mV  -37.62mA   -17.04mA   -37.89mA
-767.8mV  -39.27mA   -24.42mA   -36.82mA
-708.7mV  -37.89mA   -31.41mA   -35.41mA
-590.6mV  -33.19mA   -32.2mA    -31.41mA
281.2mV   14.34mA    13.46mA    14.31mA
900mV     33.49mA    31.7mA     32.94mA
3.6V      39.11mA    37.26mA    37.47mA
[Ramp]
dV/dt_r   0.750703/0.247685n  0.714174/0.290202n  0.818765/0.201747n
dV/dt_f   0.745775/0.235611n  0.696255/0.276842n  0.775567/0.22325n
R_load = 50
[Rising Waveform]
R_fixture = 50
V_fixture = 0
V_fixture_min = 0
V_fixture_max = 0
| Time   V(typ)   V(min)   V(max)
0s        10.57nV    27.17nV    14nV
1.563ns   839.8uV    605.4uV    -62.34mV
1.846ns   -2.173mV   715uV      1.055V
2.1ns     -65.07mV   813.4uV    1.313V
2.209ns   186mV      855.6uV    1.337V
2.45ns    967.6mV    607.7uV    1.356V
2.835ns   1.218V     -73.79mV   1.363V
3.275ns   1.243V     901.3mV    1.365V
3.667ns   1.248V     1.148V     1.365V
10ns      1.251V     1.19V      1.365V
[Rising Waveform]
R_fixture = 50
V_fixture = 1.8
V_fixture_min = 1.71
V_fixture_max = 1.89
| Time   V(typ)   V(min)   V(max)
0s        557mV      549.6mV    597.4mV
1.447ns   556.2mV    549.1mV    602mV
1.709ns   556.1mV    549mV      1.68V
1.984ns   694.9mV    548.9mV    1.872V
2.259ns   1.598V     548.8mV    1.886V
2.575ns   1.783V     542.8mV    1.889V
2.693ns   1.791V     647.9mV    1.889V
3.053ns   1.798V     1.543V     1.89V
3.335ns   1.799V     1.687V     1.89V
10ns      1.8V       1.71V      1.89V
[Falling Waveform]
R_fixture = 50
V_fixture = 0
V_fixture_min = 0
V_fixture_max = 0
| Time   V(typ)   V(min)   V(max)
0s        1.251V     1.19V      1.365V
1.469ns   1.252V     1.19V      1.37V
1.709ns   1.252V     1.19V      262.9mV
1.947ns   1.269V     1.19V      24.1mV
2.26ns    210mV      1.19V      4.111mV
2.54ns    18mV       1.201V     1.187mV
2.709ns   7.742mV    1.175V     525.8uV
3.042ns   1.649mV    221.7mV    152.8uV
3.266ns   813.7uV    34.77mV    147.9uV
10ns      1.674uV    5.51uV     642.7nV
[Falling Waveform]
R_fixture = 50
V_fixture = 1.8
V_fixture_min = 1.71
V_fixture_max = 1.89
| Time   V(typ)   V(min)   V(max)
0s        1.8V       1.71V      1.89V
1.573ns   1.799V     1.71V      1.963V
1.858ns   1.796V     1.71V      943.6mV
2.198ns   1.657V     1.709V     630.7mV
2.481ns   767.2mV    1.707V     604.8mV
2.763ns   592mV      1.763V     599.5mV
2.928ns   571.9mV    1.761V     598.7mV
3.362ns   559.3mV    724.7mV    597.5mV
3.7ns     558mV      578.1mV    597.5mV
10ns      557mV      549.6mV    597.4mV
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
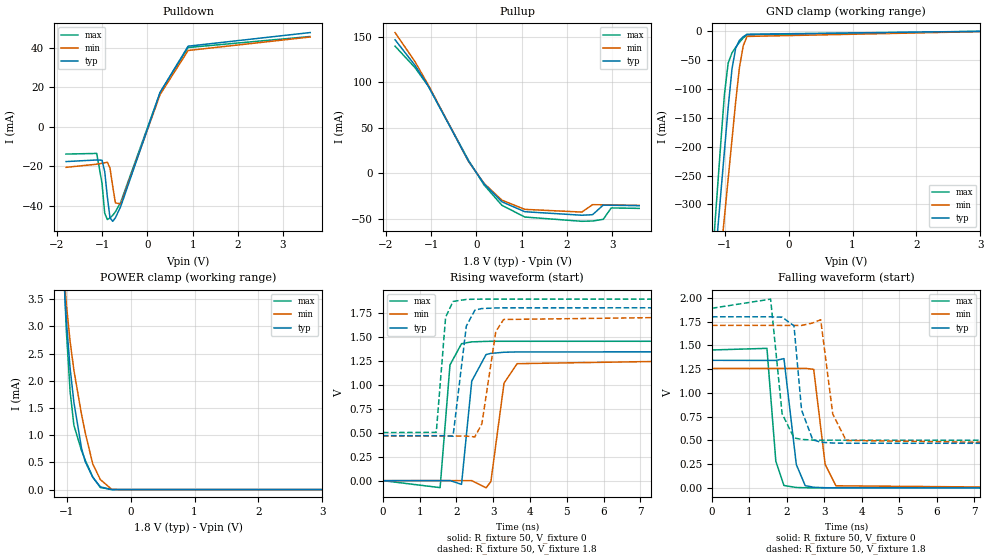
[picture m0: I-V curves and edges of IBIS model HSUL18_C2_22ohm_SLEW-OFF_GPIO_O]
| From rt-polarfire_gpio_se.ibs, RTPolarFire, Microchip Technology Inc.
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|   Model HSUL18_C2_22ohm_SLEW-OFF_GPIO_O
[Model]   HSUL18_C2_22ohm_SLEW-OFF_GPIO_O
Model_type   Output
Polarity   Non-Inverting
Enable   Active-High
Vmeas =   0.9
Cref =   5p
Rref =   50
Vref =   0.9
|   typ   min   max
C_comp_pullup   2.605e-12   2.605e-12   2.76e-12
C_comp_pulldown  2.605e-12   2.605e-12   2.76e-12
[Temperature Range]  25C   125C   -55C
[Voltage Range]  1.8   1.71   1.89
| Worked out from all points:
|   slope of the pulldown table from 0 to 0.27 V, typ, clamps not added: 16 ohm
|   slope of the pullup table from 0 to 0.27 V, typ, clamps not added: 15.5 ohm
|   GND clamp passes 1 mA (typ) near -0.52 V on its own axis
|   POWER clamp passes 1 mA (typ) near -0.81 V on its own axis
|   rising waveform, R_fixture 50, V_fixture 0: 20-80 % time 211ps typ, 260ps min, 167ps max; typ from 0 V to 1.34 V
|   rising waveform, R_fixture 50, V_fixture 1.8: 20-80 % time 201ps typ, 282ps min, 138ps max; typ from 0.469 V to 1.8 V
|   falling waveform, R_fixture 50, V_fixture 0: 20-80 % time 178ps typ, 212ps min, 152ps max; typ from 1.34 V to 0 V
|   falling waveform, R_fixture 50, V_fixture 1.8: 20-80 % time 199ps typ, 243ps min, 193ps max; typ from 1.8 V to 0.469 V
[GND Clamp]
| Voltage   I(typ)   I(min)   I(max)
-1.8V     -1.238A    -1.225A    -1.327A
-1.181V   -437.3mA   -523.2mA   -378.1mA
-1.122V   -361mA     -456.2mA   -287.7mA
-1.063V   -284.7mA   -389.3mA   -197.3mA
-1.004V   -208.5mA   -322.4mA   -110.3mA
-945mV    -132.4mA   -255.5mA   -55.69mA
-885.9mV  -66.33mA   -188.6mA   -38.3mA
-826.9mV  -29.63mA   -121.9mA   -28.32mA
-767.8mV  -16.36mA   -62.59mA   -19.64mA
-708.7mV  -10.12mA   -25.53mA   -12.4mA
-649.7mV  -5.882mA   -9.682mA   -6.873mA
3.6V      0A         0A         0A
[POWER Clamp]
| Voltage   I(typ)   I(min)   I(max)
-1.8V     45.61mA    34mA       62.13mA
-1.063V   4.301mA    4.351mA    4.537mA
-1.004V   3.099mA    3.407mA    2.918mA
-945mV    2.226mA    2.718mA    1.799mA
-885.9mV  1.604mA    2.194mA    1.183mA
-767.8mV  765.5uA    1.388mA    720.7uA
-708.7mV  512.4uA    1.046mA    541.9uA
-590.6mV  225.1uA    468.8uA    230.2uA
-472.5mV  50.43uA    184.8uA    39.22uA
-295.3mV  280.4nA    6.295uA    892.7nA
-177.2mV  3.654nA    330.8nA    286.2nA
3.6V      0A         0A         0A
[Pullup]
| Voltage   I(typ)   I(min)   I(max)
-1.8V     146.7mA    154.6mA    139.7mA
-1.358V   118.6mA    122.6mA    116.1mA
-1.063V   95.74mA    96.97mA    95.66mA
-177.2mV  13.64mA    13.35mA    14.65mA
168.8mV   -11.43mA   -10.83mA   -12.62mA
562.5mV   -31.06mA   -29.26mA   -34.89mA
1.069V    -41.96mA   -39.38mA   -47.79mA
2.332V    -45.83mA   -42.35mA   -52.48mA
2.568V    -45.24mA   -34.24mA   -52.15mA
2.804V    -34.71mA   -34.36mA   -50.33mA
2.981V    -34.87mA   -34.53mA   -37.81mA
3.6V      -35.36mA   -35.03mA   -38.3mA
[Pulldown]
| Voltage   I(typ)   I(min)   I(max)
-1.8V     -17.65mA   -20.57mA   -13.84mA
-1.122V   -16.84mA   -18.99mA   -13.52mA
-1.004V   -16.96mA   -18.52mA   -28.65mA
-945mV    -22.61mA   -18.27mA   -43.85mA
-885.9mV  -35.62mA   -17.99mA   -47.05mA
-826.9mV  -46.22mA   -21.05mA   -46.23mA
-767.8mV  -47.94mA   -30.17mA   -44.9mA
-708.7mV  -46.19mA   -38.55mA   -43.16mA
-590.6mV  -40.42mA   -39.2mA    -38.24mA
281.2mV   17.46mA    16.39mA    17.42mA
900mV     40.88mA    38.68mA    40.2mA
3.6V      47.78mA    45.54mA    45.79mA
[Ramp]
dV/dt_r   0.804991/0.210602n  0.754092/0.260112n  0.870845/0.166889n
dV/dt_f   0.798846/0.199102n  0.747182/0.243266n  0.833491/0.193098n
R_load = 50
[Rising Waveform]
R_fixture = 50
V_fixture = 0
V_fixture_min = 0
V_fixture_max = 0
| Time   V(typ)   V(min)   V(max)
0s        9.077nV    23.39nV    12.02nV
1.556ns   747.6uV    524.3uV    -72.66mV
1.824ns   845.5uV    614.6uV    1.204V
2.138ns   -38.67mV   720.5uV    1.426V
2.416ns   1.037V     770.4uV    1.445V
2.805ns   1.313V     -75.11mV   1.45V
2.936ns   1.325V     -9.902mV   1.451V
3.293ns   1.337V     1.016V     1.451V
3.649ns   1.34V      1.218V     1.451V
10ns      1.342V     1.257V     1.451V
[Rising Waveform]
R_fixture = 50
V_fixture = 1.8
V_fixture_min = 1.71
V_fixture_max = 1.89
| Time   V(typ)   V(min)   V(max)
0s        468.6mV    464.7mV    500.8mV
1.452ns   467.9mV    464.5mV    502.8mV
1.706ns   467.8mV    464.5mV    1.702V
1.907ns   462.1mV    464.5mV    1.866V
2.269ns   1.609V     464.4mV    1.887V
2.5ns     1.775V     455.1mV    1.889V
2.691ns   1.792V     591.3mV    1.89V
3.07ns    1.798V     1.553V     1.89V
3.281ns   1.799V     1.678V     1.89V
10ns      1.8V       1.71V      1.89V
[Falling Waveform]
R_fixture = 50
V_fixture = 0
V_fixture_min = 0
V_fixture_max = 0
| Time   V(typ)   V(min)   V(max)
0s        1.342V     1.257V     1.451V
1.47ns    1.341V     1.256V     1.468V
1.707ns   1.341V     1.256V     280.5mV
1.924ns   1.36V      1.256V     25.07mV
2.254ns   244.9mV    1.256V     3.846mV
2.492ns   22.9mV     1.258V     1.288mV
2.718ns   6.326mV    1.247V     228.8uV
3.024ns   1.475mV    245.8mV    196.9uV
3.312ns   474.3uV    21.7mV     188.8uV
10ns      115.1nV    2.014uV    235.8nV
[Falling Waveform]
R_fixture = 50
V_fixture = 1.8
V_fixture_min = 1.71
V_fixture_max = 1.89
| Time   V(typ)   V(min)   V(max)
0s        1.8V       1.71V      1.89V
1.568ns   1.8V       1.71V      1.986V
1.875ns   1.796V     1.709V     780mV
2.192ns   1.705V     1.709V     526mV
2.394ns   818.8mV    1.709V     509.9mV
2.692ns   505.5mV    1.735V     503mV
2.905ns   480.8mV    1.769V     501.7mV
3.226ns   471.8mV    777.6mV    501.7mV
3.584ns   469.4mV    498.6mV    501.6mV
10ns      468.6mV    464.7mV    500.8mV
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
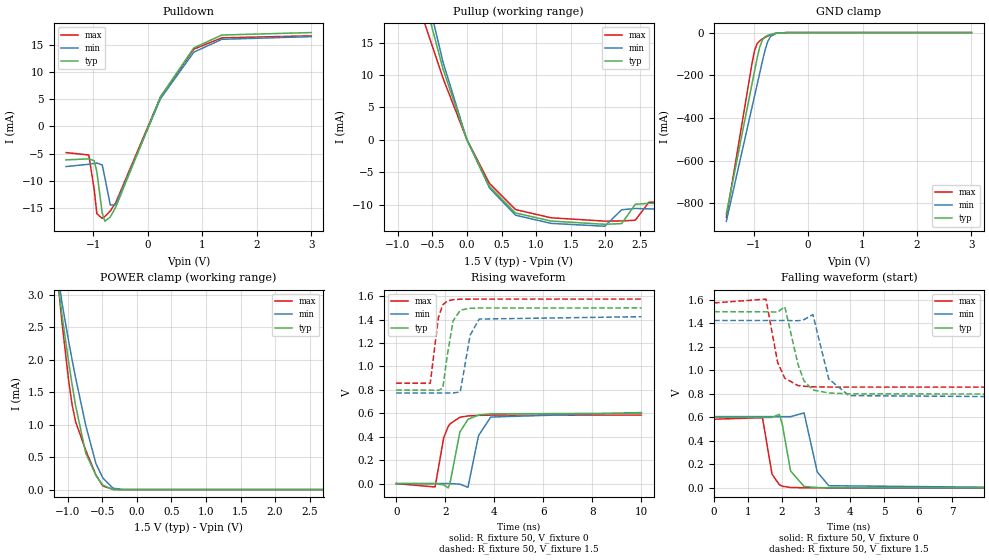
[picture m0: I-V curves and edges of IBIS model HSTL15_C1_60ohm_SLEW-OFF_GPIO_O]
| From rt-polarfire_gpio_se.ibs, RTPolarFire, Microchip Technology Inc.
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|   Model HSTL15_C1_60ohm_SLEW-OFF_GPIO_O
[Model]   HSTL15_C1_60ohm_SLEW-OFF_GPIO_O
Model_type   Output
Polarity   Non-Inverting
Enable   Active-High
Vmeas =   0.75
Cref =   5p
Rref =   50
Vref =   0.75
|   typ   min   max
C_comp_pullup   2.605e-12   2.605e-12   2.76e-12
C_comp_pulldown  2.605e-12   2.605e-12   2.76e-12
[Temperature Range]  25C   125C   -55C
[Voltage Range]  1.5   1.425   1.575
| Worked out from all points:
|   slope of the pulldown table from 0 to 0.225 V, typ, clamps not added: 42.6 ohm
|   slope of the pullup table from 0 to 0.225 V, typ, clamps not added: 42.5 ohm
|   GND clamp passes 1 mA (typ) near -0.52 V on its own axis
|   POWER clamp passes 1 mA (typ) near -0.84 V on its own axis
|   rising waveform, R_fixture 50, V_fixture 0: 20-80 % time 391ps typ, 437ps min, 349ps max; typ from 0 V to 0.601 V
|   rising waveform, R_fixture 50, V_fixture 1.5: 20-80 % time 296ps typ, 335ps min, 260ps max; typ from 0.799 V to 1.5 V
|   falling waveform, R_fixture 50, V_fixture 0: 20-80 % time 245ps typ, 293ps min, 191ps max; typ from 0.601 V to 0 V
|   falling waveform, R_fixture 50, V_fixture 1.5: 20-80 % time 353ps typ, 357ps min, 303ps max; typ from 1.5 V to 0.799 V
[GND Clamp]
| Voltage   I(typ)   I(min)   I(max)
-1.5V     -849.7mA   -884.3mA   -866.2mA
-1.034V   -246.6mA   -355.8mA   -152.2mA
-984.4mV  -183.1mA   -300.1mA   -86.85mA
-935.2mV  -119.9mA   -244.3mA   -51.18mA
-885.9mV  -66.33mA   -188.6mA   -38.3mA
-836.7mV  -33.59mA   -133mA     -29.88mA
-787.5mV  -19.44mA   -80.26mA   -22.39mA
-738.3mV  -12.87mA   -40.96mA   -15.82mA
-689.1mV  -8.545mA   -18.39mA   -10.35mA
-590.6mV  -2.947mA   -3.965mA   -3.201mA
-393.7mV  -37.64uA   -97.05uA   -25.54uA
3V        0A         0A         0A
[POWER Clamp]
| Voltage   I(typ)   I(min)   I(max)
-1.5V     10.9mA     9.514mA    12.44mA
-1.181V   3.55mA     3.619mA    3.648mA
-1.083V   2.694mA    2.882mA    2.583mA
-984.4mV  1.956mA    2.276mA    1.667mA
-935.2mV  1.615mA    1.995mA    1.306mA
-885.9mV  1.297mA    1.724mA    1.047mA
-738.3mV  562.1uA    988.5uA    604.8uA
-590.6mV  217.4uA    399.3uA    223.5uA
-492.2mV  69.4uA     180.6uA    55.95uA
-344.5mV  1.546uA    22.26uA    2.965uA
-196.9mV  138.9nA    703.2nA    3.319nA
3V        0A         0A         0A
[Pullup]
| Voltage   I(typ)   I(min)   I(max)
-1.5V     56.04mA    64.33mA    44.35mA
-1.083V   40.46mA    45.08mA    32.98mA
-344.5mV  10.89mA    11.93mA    9.477mA
0V        -138.7nA   9.483uA    26.22uA
328.1mV   -7.199mA   -7.435mA   -6.742mA
703.1mV   -11.27mA   -11.61mA   -10.74mA
1.219V    -12.51mA   -12.87mA   -12.01mA
1.992V    -13.01mA   -13.31mA   -12.52mA
2.238V    -12.9mA    -10.77mA   -12.49mA
2.435V    -9.92mA    -10.57mA   -12.38mA
2.632V    -9.767mA   -10.63mA   -9.606mA
3V        -9.852mA   -10.73mA   -9.639mA
[Pulldown]
| Voltage   I(typ)   I(min)   I(max)
-1.5V     -6.142mA   -7.378mA   -4.804mA
-1.083V   -5.962mA   -6.948mA   -5.246mA
-984.4mV  -6.289mA   -6.8mA     -11.57mA
-935.2mV  -8.329mA   -6.72mA    -16.06mA
-836.7mV  -15.95mA   -7.077mA   -16.91mA
-787.5mV  -17.45mA   -9.415mA   -16.56mA
-689.1mV  -16.66mA   -14.46mA   -15.55mA
-590.6mV  -14.89mA   -14.44mA   -14.05mA
234.4mV   5.478mA    5.14mA     5.465mA
843.8mV   14.46mA    13.68mA    14.23mA
1.359V    16.84mA    16.05mA    16.32mA
3V        17.29mA    16.54mA    16.69mA
[Ramp]
dV/dt_r   0.360363/0.390669n  0.364143/0.437426n  0.350873/0.348532n
dV/dt_f   0.420878/0.353422n  0.390782/0.35696n  0.430347/0.303342n
R_load = 50
[Rising Waveform]
R_fixture = 50
V_fixture = 0
V_fixture_min = 0
V_fixture_max = 0
| Time   V(typ)   V(min)   V(max)
0s        16.87nV    44nV       22.48nV
1.586ns   -621uV     446uV      -28.88mV
1.94ns    -11.25mV   545.5uV    394.3mV
2.122ns   -36.45mV   596.7uV    487.7mV
2.196ns   4.193mV    617.5uV    510.2mV
2.598ns   440.6mV    -5.109mV   566.4mV
2.926ns   548.1mV    -31.77mV   577.8mV
3.357ns   584.6mV    408.8mV    582.6mV
3.854ns   595.7mV    568.3mV    584.6mV
10ns      600.6mV    606.9mV    584.8mV
[Rising Waveform]
R_fixture = 50
V_fixture = 1.5
V_fixture_min = 1.425
V_fixture_max = 1.575
| Time   V(typ)   V(min)   V(max)
0s        798.6mV    773.7mV    857.8mV
1.388ns   797.9mV    773.6mV    856.3mV
1.72ns    796.2mV    773.6mV    1.417V
1.898ns   813.5mV    773.6mV    1.526V
2.086ns   1.098V     773.6mV    1.56V
2.32ns    1.389V     773.6mV    1.57V
2.613ns   1.481V     783mV      1.574V
3.015ns   1.497V     1.267V     1.575V
3.383ns   1.499V     1.405V     1.575V
10ns      1.5V       1.425V     1.575V
[Falling Waveform]
R_fixture = 50
V_fixture = 0
V_fixture_min = 0
V_fixture_max = 0
| Time   V(typ)   V(min)   V(max)
0s        600.6mV    606.9mV    584.8mV
1.423ns   599.8mV    606.4mV    597.2mV
1.703ns   599.6mV    606.4mV    117.3mV
1.919ns   625.5mV    606.3mV    26.54mV
2.002ns   545.9mV    606.3mV    14.43mV
2.25ns    143.4mV    606.2mV    3.205mV
2.645ns   12.06mV    638.6mV    665.1uV
3.033ns   2.354mV    135.6mV    -16.1uV
3.371ns   712.4uV    18.16mV    -15.33uV
10ns      -761.9nV   1.886uV    -214.6nV
[Falling Waveform]
R_fixture = 50
V_fixture = 1.5
V_fixture_min = 1.425
V_fixture_max = 1.575
| Time   V(typ)   V(min)   V(max)
0s        1.5V       1.425V     1.575V
1.525ns   1.499V     1.425V     1.607V
1.869ns   1.497V     1.425V     1.067V
2.079ns   1.542V     1.425V     934.3mV
2.468ns   1.051V     1.423V     870.5mV
2.642ns   911mV      1.432V     865.6mV
2.905ns   833.3mV    1.475V     860.1mV
3.371ns   807.8mV    927.8mV    858.3mV
3.964ns   800.7mV    785.5mV    857.7mV
10ns      798.5mV    773.7mV    857.8mV
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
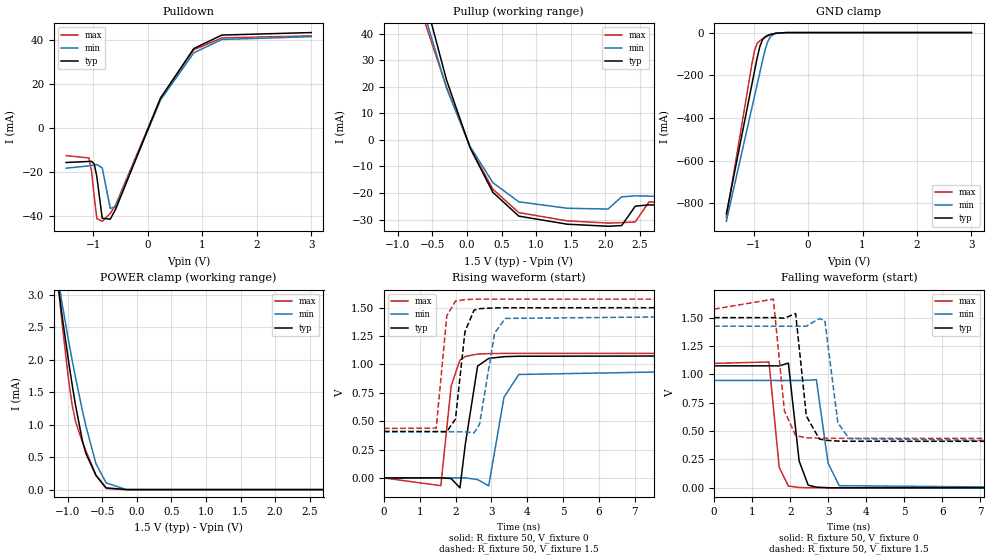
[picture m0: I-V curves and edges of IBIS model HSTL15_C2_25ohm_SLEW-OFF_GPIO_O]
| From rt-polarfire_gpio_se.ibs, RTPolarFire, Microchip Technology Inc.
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|   Model HSTL15_C2_25ohm_SLEW-OFF_GPIO_O
[Model]   HSTL15_C2_25ohm_SLEW-OFF_GPIO_O
Model_type   Output
Polarity   Non-Inverting
Enable   Active-High
Vmeas =   0.75
Cref =   5p
Rref =   50
Vref =   0.75
|   typ   min   max
C_comp_pullup   2.605e-12   2.605e-12   2.76e-12
C_comp_pulldown  2.605e-12   2.605e-12   2.76e-12
[Temperature Range]  25C   125C   -55C
[Voltage Range]  1.5   1.425   1.575
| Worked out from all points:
|   slope of the pulldown table from 0 to 0.225 V, typ, clamps not added: 17.2 ohm
|   slope of the pullup table from 0 to 0.225 V, typ, clamps not added: 17.1 ohm
|   GND clamp passes 1 mA (typ) near -0.52 V on its own axis
|   POWER clamp passes 1 mA (typ) near -0.84 V on its own axis
|   rising waveform, R_fixture 50, V_fixture 0: 20-80 % time 242ps typ, 324ps min, 228ps max; typ from 0 V to 1.07 V
|   rising waveform, R_fixture 50, V_fixture 1.5: 20-80 % time 223ps typ, 315ps min, 173ps max; typ from 0.41 V to 1.5 V
|   falling waveform, R_fixture 50, V_fixture 0: 20-80 % time 191ps typ, 234ps min, 169ps max; typ from 1.07 V to 0 V
|   falling waveform, R_fixture 50, V_fixture 1.5: 20-80 % time 202ps typ, 223ps min, 183ps max; typ from 1.5 V to 0.41 V
[GND Clamp]
| Voltage   I(typ)   I(min)   I(max)
-1.5V     -849.7mA   -884.3mA   -866.2mA
-1.034V   -246.6mA   -355.8mA   -152.2mA
-984.4mV  -183.1mA   -300.1mA   -86.85mA
-935.2mV  -119.9mA   -244.3mA   -51.18mA
-885.9mV  -66.33mA   -188.6mA   -38.3mA
-836.7mV  -33.59mA   -133mA     -29.88mA
-787.5mV  -19.44mA   -80.26mA   -22.39mA
-738.3mV  -12.87mA   -40.96mA   -15.82mA
-689.1mV  -8.545mA   -18.39mA   -10.35mA
-590.6mV  -2.947mA   -3.965mA   -3.201mA
-393.7mV  -37.64uA   -97.05uA   -25.54uA
3V        0A         0A         0A
[POWER Clamp]
| Voltage   I(typ)   I(min)   I(max)
-1.5V     10.9mA     9.514mA    12.44mA
-1.132V   3.099mA    3.218mA    3.095mA
-1.083V   2.694mA    2.882mA    2.585mA
-984.4mV  1.956mA    2.276mA    1.667mA
-935.2mV  1.616mA    1.995mA    1.306mA
-885.9mV  1.297mA    1.724mA    1.047mA
-787.5mV  756.7uA    1.22mA     734.9uA
-738.3mV  562.1uA    988.5uA    604.8uA
-590.6mV  217.4uA    399.3uA    223.5uA
-443mV    26.83uA    102.4uA    17.35uA
-147.7mV  138.9nA    118.7nA    456.7pA
3V        0A         0A         0A
[Pullup]
| Voltage   I(typ)   I(min)   I(max)
-1.5V     138.4mA    125.9mA    109.8mA
-1.132V   104.6mA    92.67mA    85.2mA
-295.3mV  22.56mA    19.51mA    19.86mA
46.88mV   -3.061mA   -2.497mA   -2.815mA
375mV     -19.73mA   -16.09mA   -18.54mA
750mV     -28.7mA    -23.32mA   -27.38mA
1.453V    -31.75mA   -25.74mA   -30.49mA
2.041V    -32.51mA   -26.03mA   -31.31mA
2.238V    -32.25mA   -21.43mA   -31.16mA
2.435V    -24.95mA   -21.05mA   -30.87mA
2.632V    -24.47mA   -21.17mA   -23.38mA
3V        -24.68mA   -21.36mA   -23.4mA
[Pulldown]
| Voltage   I(typ)   I(min)   I(max)
-1.5V     -15.62mA   -18.21mA   -12.53mA
-1.083V   -15.15mA   -17.14mA   -13.56mA
-1.034V   -15.09mA   -16.96mA   -19.27mA
-984.4mV  -16.19mA   -16.78mA   -30.88mA
-935.2mV  -22.06mA   -16.58mA   -41.01mA
-836.7mV  -40.87mA   -18.04mA   -42.25mA
-689.1mV  -41.28mA   -36.39mA   -38.68mA
-590.6mV  -36.79mA   -35.7mA    -34.84mA
234.4mV   13.54mA    12.7mA     13.53mA
843.8mV   35.96mA    34.02mA    35.42mA
1.359V    42.08mA    40.08mA    40.78mA
3V        43.21mA    41.35mA    41.72mA
[Ramp]
dV/dt_r   0.645281/0.242426n  0.567973/0.323876n  0.658283/0.228267n
dV/dt_f   0.65406/0.202177n  0.611203/0.222584n  0.683271/0.18342n
R_load = 50
[Rising Waveform]
R_fixture = 50
V_fixture = 0
V_fixture_min = 0
V_fixture_max = 0
| Time   V(typ)   V(min)   V(max)
0s        9.117nV    24.16nV    12.13nV
1.588ns   769.9uV    527.6uV    -67.83mV
1.877ns   -5.086mV   623.6uV    810.8mV
2.122ns   -87.26mV   705uV      1.038V
2.274ns   300.9mV    755.5uV    1.07V
2.615ns   984.9mV    -14.27mV   1.091V
2.925ns   1.053V     -69.79mV   1.095V
3.352ns   1.068V     710.9mV    1.097V
3.765ns   1.072V     911.3mV    1.097V
10ns      1.075V     946.6mV    1.097V
[Rising Waveform]
R_fixture = 50
V_fixture = 1.5
V_fixture_min = 1.425
V_fixture_max = 1.575
| Time   V(typ)   V(min)   V(max)
0s        409.9mV    406.3mV    436.2mV
1.46ns    409.2mV    406.2mV    439mV
1.756ns   408.2mV    406.2mV    1.43V
1.997ns   518.2mV    406.2mV    1.558V
2.262ns   1.289V     406.1mV    1.571V
2.517ns   1.478V     397.7mV    1.574V
2.669ns   1.491V     472.4mV    1.575V
3.092ns   1.498V     1.277V     1.575V
3.39ns    1.499V     1.405V     1.575V
10ns      1.5V       1.425V     1.575V
[Falling Waveform]
R_fixture = 50
V_fixture = 0
V_fixture_min = 0
V_fixture_max = 0
| Time   V(typ)   V(min)   V(max)
0s        1.075V     946.7mV    1.097V
1.443ns   1.075V     946.2mV    1.109V
1.713ns   1.075V     946.1mV    178.8mV
1.953ns   1.099V     946mV      16.4mV
2.236ns   236.9mV    945.9mV    3.134mV
2.473ns   23.92mV    948.7mV    1.055mV
2.689ns   6.335mV    953.3mV    577.2uV
2.996ns   1.32mV     218.2mV    553uV
3.29ns    418.4uV    19.15mV    529.8uV
10ns      -205.8nV   3.597uV    -44.98nV
[Falling Waveform]
R_fixture = 50
V_fixture = 1.5
V_fixture_min = 1.425
V_fixture_max = 1.575
| Time   V(typ)   V(min)   V(max)
0s        1.5V       1.425V     1.575V
1.558ns   1.5V       1.424V     1.663V
1.849ns   1.495V     1.424V     678.3mV
2.144ns   1.536V     1.424V     460.7mV
2.425ns   633.3mV    1.424V     441.6mV
2.765ns   431mV      1.491V     437.6mV
2.911ns   419.8mV    1.475V     437mV
3.253ns   412.3mV    574.2mV    436.4mV
3.544ns   410.8mV    434.2mV    436.4mV
10ns      409.9mV    406.3mV    436.2mV
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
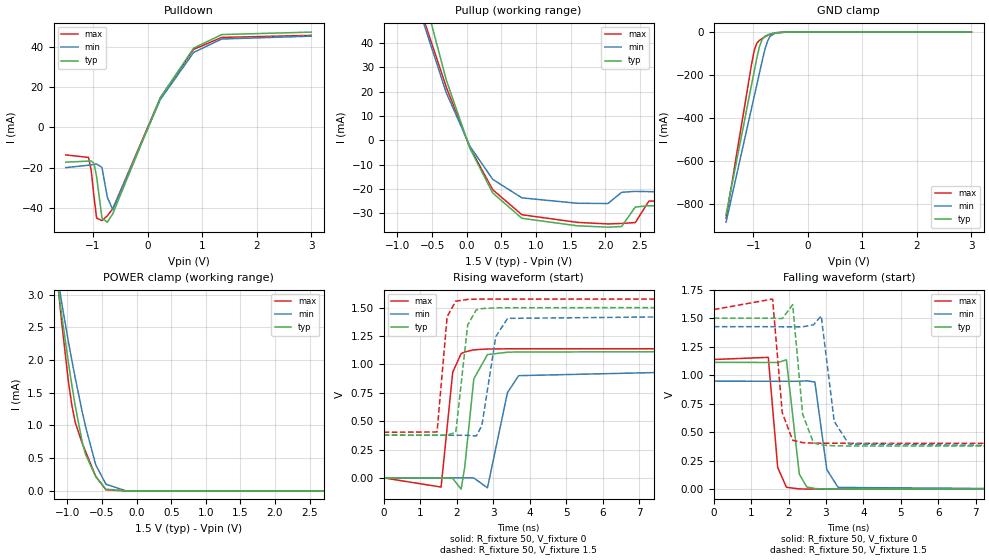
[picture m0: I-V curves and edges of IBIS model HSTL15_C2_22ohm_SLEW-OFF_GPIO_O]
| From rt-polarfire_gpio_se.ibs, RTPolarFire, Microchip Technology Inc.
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|   Model HSTL15_C2_22ohm_SLEW-OFF_GPIO_O
[Model]   HSTL15_C2_22ohm_SLEW-OFF_GPIO_O
Model_type   Output
Polarity   Non-Inverting
Enable   Active-High
Vmeas =   0.75
Cref =   5p
Rref =   50
Vref =   0.75
|   typ   min   max
C_comp_pullup   2.605e-12   2.605e-12   2.76e-12
C_comp_pulldown  2.605e-12   2.605e-12   2.76e-12
[Temperature Range]  25C   125C   -55C
[Voltage Range]  1.5   1.425   1.575
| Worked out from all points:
|   slope of the pulldown table from 0 to 0.225 V, typ, clamps not added: 15.7 ohm
|   slope of the pullup table from 0 to 0.225 V, typ, clamps not added: 15.6 ohm
|   GND clamp passes 1 mA (typ) near -0.52 V on its own axis
|   POWER clamp passes 1 mA (typ) near -0.84 V on its own axis
|   rising waveform, R_fixture 50, V_fixture 0: 20-80 % time 226ps typ, 322ps min, 206ps max; typ from 0 V to 1.11 V
|   rising waveform, R_fixture 50, V_fixture 1.5: 20-80 % time 216ps typ, 309ps min, 159ps max; typ from 0.378 V to 1.5 V
|   falling waveform, R_fixture 50, V_fixture 0: 20-80 % time 182ps typ, 230ps min, 160ps max; typ from 1.11 V to 0 V
|   falling waveform, R_fixture 50, V_fixture 1.5: 20-80 % time 177ps typ, 220ps min, 175ps max; typ from 1.5 V to 0.378 V
[GND Clamp]
| Voltage   I(typ)   I(min)   I(max)
-1.5V     -849.7mA   -884.3mA   -866.2mA
-1.034V   -246.6mA   -355.8mA   -152.2mA
-984.4mV  -183.1mA   -300.1mA   -86.85mA
-935.2mV  -119.9mA   -244.3mA   -51.18mA
-885.9mV  -66.33mA   -188.6mA   -38.3mA
-836.7mV  -33.59mA   -133mA     -29.88mA
-787.5mV  -19.44mA   -80.26mA   -22.39mA
-738.3mV  -12.87mA   -40.96mA   -15.82mA
-689.1mV  -8.545mA   -18.39mA   -10.35mA
-590.6mV  -2.947mA   -3.965mA   -3.201mA
-393.7mV  -37.64uA   -97.05uA   -25.54uA
3V        0A         0A         0A
[POWER Clamp]
| Voltage   I(typ)   I(min)   I(max)
-1.5V     10.9mA     9.514mA    12.44mA
-1.132V   3.099mA    3.218mA    3.095mA
-1.083V   2.694mA    2.882mA    2.585mA
-984.4mV  1.956mA    2.276mA    1.667mA
-935.2mV  1.615mA    1.995mA    1.306mA
-885.9mV  1.297mA    1.724mA    1.047mA
-787.5mV  756.7uA    1.22mA     734.9uA
-738.3mV  562.1uA    988.5uA    604.8uA
-590.6mV  217.4uA    399.3uA    223.5uA
-443mV    26.83uA    102.4uA    17.35uA
-147.7mV  138.9nA    118.7nA    456.7pA
3V        0A         0A         0A
[Pullup]
| Voltage   I(typ)   I(min)   I(max)
-1.5V     152.1mA    125.9mA    120.4mA
-1.132V   114.8mA    92.67mA    93.35mA
-295.3mV  24.76mA    19.51mA    21.77mA
46.88mV   -3.363mA   -2.497mA   -3.088mA
375mV     -21.69mA   -16.09mA   -20.35mA
796.9mV   -32.12mA   -23.72mA   -30.65mA
1.598V    -35.21mA   -25.94mA   -33.8mA
2.041V    -35.77mA   -26.03mA   -34.44mA
2.238V    -35.49mA   -21.43mA   -34.24mA
2.435V    -27.49mA   -21.05mA   -33.88mA
2.632V    -26.95mA   -21.17mA   -25.03mA
3V        -27.18mA   -21.36mA   -25.01mA
[Pulldown]
| Voltage   I(typ)   I(min)   I(max)
-1.5V     -17.31mA   -20.02mA   -13.71mA
-1.083V   -16.79mA   -18.84mA   -14.95mA
-1.034V   -16.73mA   -18.65mA   -21.4mA
-984.4mV  -17.91mA   -18.44mA   -34.26mA
-935.2mV  -24.48mA   -18.22mA   -45.19mA
-836.7mV  -45.13mA   -19.94mA   -46.42mA
-738.3mV  -47.24mA   -34.89mA   -44.08mA
-639.8mV  -43.06mA   -40.88mA   -40.54mA
234.4mV   14.87mA    13.95mA    14.85mA
843.8mV   39.53mA    37.39mA    38.93mA
1.359V    46.29mA    44.09mA    44.86mA
3V        47.53mA    45.49mA    45.9mA
[Ramp]
dV/dt_r   0.667036/0.225521n  0.568044/0.322042n  0.682269/0.206369n
dV/dt_f   0.673101/0.176675n  0.629512/0.220293n  0.703697/0.175174n
R_load = 50
[Rising Waveform]
R_fixture = 50
V_fixture = 0
V_fixture_min = 0
V_fixture_max = 0
| Time   V(typ)   V(min)   V(max)
0s        8.469nV    22.48nV    11.27nV
1.574ns   595.5uV    528.2uV    -80.29mV
1.892ns   -4.529mV   635uV      930.8mV
2.122ns   -99.05mV   712.2uV    1.094V
2.22ns    91.84mV    745uV      1.109V
2.47ns    872.6mV    -293.4uV   1.128V
2.844ns   1.086V     -87.58mV   1.135V
3.391ns   1.107V     750mV      1.137V
3.698ns   1.109V     900.5mV    1.137V
10ns      1.112V     946.7mV    1.137V
[Rising Waveform]
R_fixture = 50
V_fixture = 1.5
V_fixture_min = 1.425
V_fixture_max = 1.575
| Time   V(typ)   V(min)   V(max)
0s        378.2mV    375.8mV    402.2mV
1.463ns   377.6mV    375.5mV    404.6mV
1.739ns   377.5mV    375.5mV    1.419V
1.975ns   399.7mV    375.4mV    1.557V
2.303ns   1.348V     375.4mV    1.572V
2.538ns   1.48V      369mV      1.574V
2.691ns   1.491V     461.7mV    1.575V
3.072ns   1.498V     1.244V     1.575V
3.396ns   1.499V     1.405V     1.575V
10ns      1.5V       1.425V     1.575V
[Falling Waveform]
R_fixture = 50
V_fixture = 0
V_fixture_min = 0
V_fixture_max = 0
| Time   V(typ)   V(min)   V(max)
0s        1.112V     946.7mV    1.137V
1.458ns   1.111V     946.3mV    1.156V
1.71ns    1.111V     946.2mV    189.8mV
1.943ns   1.134V     946.1mV    16.71mV
2.288ns   130.7mV    946mV      2.155mV
2.488ns   19.24mV    950.1mV    870.1uV
2.704ns   5.296mV    939.7mV    526.5uV
3.023ns   1.274mV    171.6mV    503.5uV
3.325ns   225.7uV    15.13mV    481.7uV
10ns      196.7nV    3.682uV    7.041nV
[Falling Waveform]
R_fixture = 50
V_fixture = 1.5
V_fixture_min = 1.425
V_fixture_max = 1.575
| Time   V(typ)   V(min)   V(max)
0s        1.5V       1.425V     1.575V
1.573ns   1.499V     1.425V     1.667V
1.831ns   1.496V     1.424V     672mV
2.11ns    1.618V     1.424V     428.9mV
2.376ns   657.7mV    1.424V     408mV
2.667ns   406.3mV    1.441V     403.8mV
2.873ns   387.6mV    1.519V     402.9mV
3.221ns   380.3mV    594.5mV    402.4mV
3.61ns    378.8mV    395.8mV    402.3mV
10ns      378.2mV    375.8mV    402.2mV
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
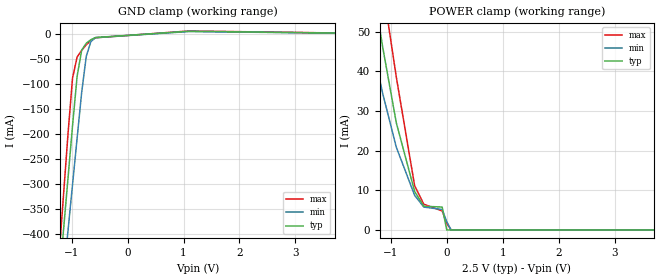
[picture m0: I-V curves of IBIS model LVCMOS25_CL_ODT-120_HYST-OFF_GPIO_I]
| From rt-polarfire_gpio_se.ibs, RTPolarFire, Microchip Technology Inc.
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|   Model LVCMOS25_CL_ODT-120_HYST-OFF_GPIO_I
[Model]   LVCMOS25_CL_ODT-120_HYST-OFF_GPIO_I
Model_type   Input
Vinl =   0.7
Vinh =   1.7
|   typ   min   max
C_comp_pullup   2.605e-12   2.605e-12   2.76e-12
C_comp_pulldown  2.605e-12   2.605e-12   2.76e-12
[Temperature Range]  25C   125C   -55C
[Voltage Range]  2.5   2.375   2.625
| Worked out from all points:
|   GND clamp passes 1 mA (typ) near -0.11 V on its own axis
|   POWER clamp passes 1 mA (typ) near -0.01 V on its own axis
[GND Clamp]
| Voltage   I(typ)   I(min)   I(max)
-2.5V     -2.156A    -2.03A     -2.415A
-1.23V    -502.5mA   -581mA     -452.4mA
-1.148V   -396.3mA   -488.1mA   -326.7mA
-1.066V   -290.3mA   -395.1mA   -201.8mA
-984.4mV  -184.4mA   -302.1mA   -88.76mA
-902.3mV  -84.93mA   -209.1mA   -46.29mA
-820.3mV  -32.45mA   -116.8mA   -32.87mA
-738.3mV  -18.55mA   -44.68mA   -21.76mA
-656.2mV  -11.66mA   -15.38mA   -13.06mA
-574.2mV  -7.219mA   -7.532mA   -7.681mA
1.094V    5.396mA    4.797mA    5.931mA
5V        0A         0A         0A
[POWER Clamp]
| Voltage   I(typ)   I(min)   I(max)
-2.5V     196.5mA    154.7mA    242.8mA
-1.559V   85.13mA    63.51mA    110.8mA
-1.477V   76.88mA    57.21mA    100.5mA
-1.312V   61.08mA    45.37mA    80.43mA
-1.148V   46.36mA    34.6mA     61.71mA
-902.3mV  27.07mA    20.9mA     38.61mA
-574.2mV  9.698mA    8.731mA    11.16mA
-410.2mV  5.994mA    5.784mA    6.496mA
-82.03mV  5.785mA    5.17mA     4.799mA
0V        0A         2.067mA    1.65mA
78.12mV   0A         0A         0A
5V        0A         0A         0A
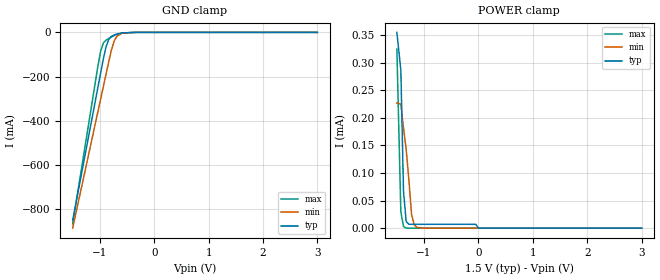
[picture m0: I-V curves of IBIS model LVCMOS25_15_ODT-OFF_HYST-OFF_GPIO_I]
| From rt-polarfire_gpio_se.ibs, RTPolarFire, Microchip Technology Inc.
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|   Model LVCMOS25_15_ODT-OFF_HYST-OFF_GPIO_I
[Model]   LVCMOS25_15_ODT-OFF_HYST-OFF_GPIO_I
Model_type   Input
Vinl =   0.7
Vinh =   1.7
|   typ   min   max
C_comp_pullup   2.605e-12   2.605e-12   2.76e-12
C_comp_pulldown  2.605e-12   2.605e-12   2.76e-12
[Temperature Range]  25C   125C   -55C
[Voltage Range]  1.5   1.425   1.575
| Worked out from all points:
|   GND clamp passes 1 mA (typ) near -0.53 V on its own axis
[GND Clamp]
| Voltage   I(typ)   I(min)   I(max)
-1.5V     -849.3mA   -884.2mA   -864.7mA
-1.034V   -245.6mA   -355.6mA   -149mA
-984.4mV  -181.9mA   -299.8mA   -83.61mA
-935.2mV  -118.6mA   -244.1mA   -47.97mA
-885.9mV  -64.84mA   -188.3mA   -35.49mA
-836.7mV  -32mA      -132.7mA   -27.56mA
-787.5mV  -17.96mA   -79.89mA   -20.54mA
-738.3mV  -11.65mA   -40.51mA   -14.41mA
-689.1mV  -7.607mA   -17.88mA   -9.349mA
-590.6mV  -2.494mA   -3.492mA   -2.83mA
-344.5mV  -5.072uA   -20.77uA   -2.078uA
3V        0A         0A         0A
[POWER Clamp]
| Voltage   I(typ)   I(min)   I(max)
-1.5V     355.1uA    227uA      324.7uA
-1.427V   286.8uA    225uA      29.67uA
-1.378V   67.3uA     181.8uA    2.834uA
-1.329V   12.04uA    142.6uA    193.3nA
-1.28V    6.97uA     88.6uA     12.72nA
-1.23V    6.97uA     24.93uA    1.6nA
-1.181V   6.97uA     6.249uA    751pA
-1.132V   6.97uA     1.446uA    662.5pA
-1.034V   6.97uA     71.61nA    566.4pA
-49.22mV  6.97uA     1.506nA    453pA
0V        0A         589.1pA    237.3pA
3V        0A         0A         0A
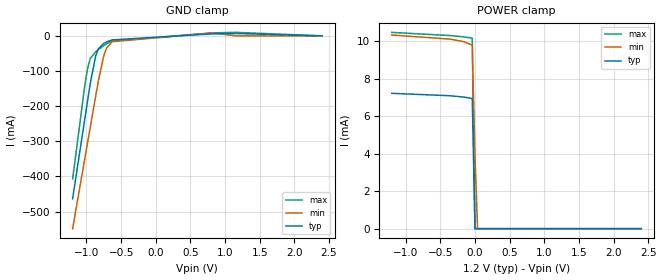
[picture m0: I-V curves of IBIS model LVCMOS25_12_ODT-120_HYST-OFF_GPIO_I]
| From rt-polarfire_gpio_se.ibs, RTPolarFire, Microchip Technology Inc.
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|   Model LVCMOS25_12_ODT-120_HYST-OFF_GPIO_I
[Model]   LVCMOS25_12_ODT-120_HYST-OFF_GPIO_I
Model_type   Input
Vinl =   0.7
Vinh =   1.7
|   typ   min   max
C_comp_pullup   2.605e-12   2.605e-12   2.76e-12
C_comp_pulldown  2.605e-12   2.605e-12   2.76e-12
[Temperature Range]  25C   125C   -55C
[Voltage Range]  1.2   1.14   1.26
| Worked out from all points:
|   GND clamp passes 1 mA (typ) near -0.09 V on its own axis
|   POWER clamp passes 1 mA (typ) near -0.01 V on its own axis
[GND Clamp]
| Voltage   I(typ)   I(min)   I(max)
-1.2V     -463.6mA   -548.7mA   -407.3mA
-1.024V   -235.7mA   -348.8mA   -140.9mA
-984.4mV  -185mA     -304.1mA   -92.54mA
-945mV    -134.8mA   -259.5mA   -64.14mA
-866.2mV  -55.66mA   -170.4mA   -45.07mA
-826.9mV  -36.15mA   -126.4mA   -38.7mA
-748.1mV  -21.12mA   -54.68mA   -27.16mA
-708.7mV  -17.17mA   -34.03mA   -22.27mA
-630mV    -11.32mA   -16.44mA   -14.68mA
825mV     5.97mA     8.45mA     8.809mA
1.163V    6.855mA    0A         10.01mA
2.4V      0A         0A         0A
[POWER Clamp]
| Voltage   I(typ)   I(min)   I(max)
-1.2V     7.22mA     10.33mA    10.47mA
-354.4mV  7.089mA    10.11mA    10.3mA
-157.5mV  7.018mA    9.97mA     10.23mA
-39.38mV  6.94mA     9.792mA    10.16mA
0V        0A         3.903mA    0A
37.5mV    0A         0A         0A
2.4V      0A         0A         0A
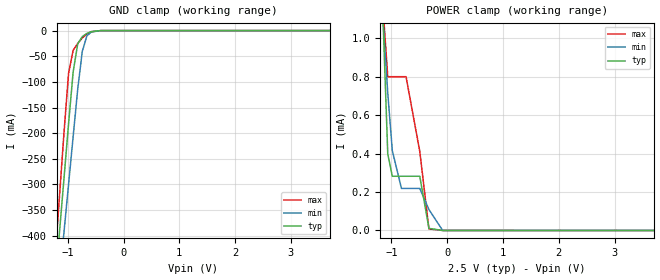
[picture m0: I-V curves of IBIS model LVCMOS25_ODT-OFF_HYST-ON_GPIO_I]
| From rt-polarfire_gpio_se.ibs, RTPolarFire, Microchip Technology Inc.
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|   Model LVCMOS25_ODT-OFF_HYST-ON_GPIO_I
[Model]   LVCMOS25_ODT-OFF_HYST-ON_GPIO_I
Model_type   Input
Vinl =   0.7
Vinh =   1.7
|   typ   min   max
C_comp_pullup   2.605e-12   2.605e-12   2.76e-12
C_comp_pulldown  2.605e-12   2.605e-12   2.76e-12
[Model Spec]
Vinh+   1.313   1.247   1.378
Vinh-   1.313   1.247   1.378
Vinl+   1.188   1.128   1.247
Vinl-   1.188   1.128   1.247
[Temperature Range]  25C   125C   -55C
[Voltage Range]  2.5   2.375   2.625
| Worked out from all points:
|   GND clamp passes 1 mA (typ) near -0.52 V on its own axis
|   POWER clamp passes 1 mA (typ) near -1.14 V on its own axis
[GND Clamp]
| Voltage   I(typ)   I(min)   I(max)
-2.5V     -2.154A    -2.027A    -2.413A
-1.23V    -500.3mA   -578.7mA   -450.4mA
-1.148V   -394.1mA   -485.8mA   -324.6mA
-1.066V   -288mA     -392.8mA   -199mA
-984.4mV  -181.9mA   -299.8mA   -83.61mA
-902.3mV  -80.78mA   -206.9mA   -38.62mA
-820.3mV  -25.8mA    -114.2mA   -25.13mA
-738.3mV  -11.65mA   -40.52mA   -14.41mA
-656.2mV  -5.525mA   -10.21mA   -6.635mA
-574.2mV  -1.954mA   -2.666mA   -2.194mA
-410.2mV  -41.8uA    -101uA     -33.53uA
5V        0A         0A         0A
[POWER Clamp]
| Voltage   I(typ)   I(min)   I(max)
-2.5V     56.69mA    34.41mA    86.77mA
-1.148V   1.079mA    1.084mA    1.146mA
-1.066V   399uA      715.9uA    800.8uA
-984.4mV  282.4uA    415.4uA    800.8uA
-820.3mV  282.4uA    219uA      800.8uA
-738.3mV  282.4uA    219uA      800.8uA
-492.2mV  282.4uA    219uA      411.9uA
-328.1mV  11.03uA    108.9uA    8.003uA
-82.03mV  4.148nA    88.1nA     53.54nA
5V        0A         0A         0A
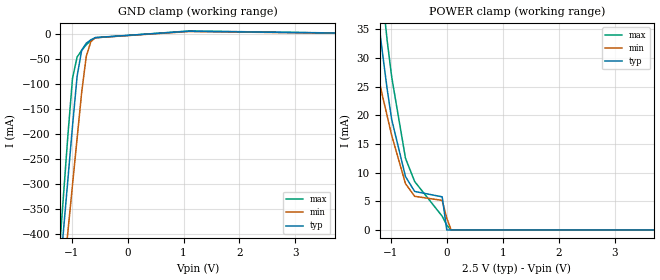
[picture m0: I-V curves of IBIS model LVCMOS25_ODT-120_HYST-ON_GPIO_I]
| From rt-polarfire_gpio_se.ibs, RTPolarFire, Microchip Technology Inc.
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|   Model LVCMOS25_ODT-120_HYST-ON_GPIO_I
[Model]   LVCMOS25_ODT-120_HYST-ON_GPIO_I
Model_type   Input
Vinl =   0.7
Vinh =   1.7
|   typ   min   max
C_comp_pullup   2.605e-12   2.605e-12   2.76e-12
C_comp_pulldown  2.605e-12   2.605e-12   2.76e-12
[Model Spec]
Vinh+   1.313   1.247   1.378
Vinh-   1.313   1.247   1.378
Vinl+   1.188   1.128   1.247
Vinl-   1.188   1.128   1.247
[Temperature Range]  25C   125C   -55C
[Voltage Range]  2.5   2.375   2.625
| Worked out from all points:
|   GND clamp passes 1 mA (typ) near -0.11 V on its own axis
|   POWER clamp passes 1 mA (typ) near -0.01 V on its own axis
[GND Clamp]
| Voltage   I(typ)   I(min)   I(max)
-2.5V     -2.156A    -2.03A     -2.415A
-1.23V    -502.5mA   -581mA     -452.4mA
-1.148V   -396.3mA   -488.1mA   -326.7mA
-1.066V   -290.3mA   -395.1mA   -201.8mA
-984.4mV  -184.4mA   -302.1mA   -88.76mA
-902.3mV  -84.93mA   -209.1mA   -46.29mA
-820.3mV  -32.45mA   -116.8mA   -32.87mA
-738.3mV  -18.55mA   -44.68mA   -21.76mA
-656.2mV  -11.66mA   -15.38mA   -13.06mA
-574.2mV  -7.219mA   -7.532mA   -7.681mA
1.094V    5.396mA    4.797mA    5.931mA
5V        0A         0A         0A
[POWER Clamp]
| Voltage   I(typ)   I(min)   I(max)
-2.5V     167mA      124.9mA    213.2mA
-1.395V   50.1mA     35.49mA    68.37mA
-1.23V    37.31mA    27.08mA    49.81mA
-1.148V   30.82mA    23.35mA    40.81mA
-1.066V   24.63mA    19.94mA    33.12mA
-984.4mV  19.28mA    16.5mA     26.71mA
-738.3mV  9.333mA    8.093mA    12.54mA
-574.2mV  6.727mA    5.873mA    8.46mA
-82.03mV  5.785mA    5.17mA     2.405mA
0V        0A         2.067mA    826.8uA
78.12mV   0A         0A         0A
5V        0A         0A         0A
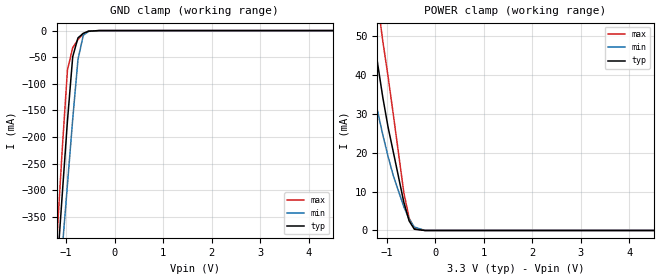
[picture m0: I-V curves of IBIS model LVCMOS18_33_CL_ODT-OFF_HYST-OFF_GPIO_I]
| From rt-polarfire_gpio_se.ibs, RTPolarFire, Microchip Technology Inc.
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|   Model LVCMOS18_33_CL_ODT-OFF_HYST-OFF_GPIO_I
[Model]   LVCMOS18_33_CL_ODT-OFF_HYST-OFF_GPIO_I
Model_type   Input
Vinl =   0.63
Vinh =   1.17
|   typ   min   max
C_comp_pullup   2.605e-12   2.605e-12   2.76e-12
C_comp_pulldown  2.605e-12   2.605e-12   2.76e-12
[Temperature Range]  25C   125C   -55C
[Voltage Range]  3.3   3.135   3.465
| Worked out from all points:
|   GND clamp passes 1 mA (typ) near -0.53 V on its own axis
|   POWER clamp passes 1 mA (typ) near -0.47 V on its own axis
[GND Clamp]
| Voltage   I(typ)   I(min)   I(max)
-3.3V     -3.213A    -2.952A    -3.676A
-1.191V   -449.3mA   -534.2mA   -390mA
-1.083V   -309.2mA   -411.4mA   -224.1mA
-974.5mV  -169.2mA   -288.7mA   -73.71mA
-866.2mV  -48.93mA   -166mA     -32.16mA
-758mV    -13.75mA   -54.29mA   -16.74mA
-649.7mV  -5.158mA   -9.147mA   -6.158mA
-541.4mV  -1.115mA   -1.518mA   -1.242mA
-324.8mV  -2.612uA   -12.67uA   -880.5nA
6.6V      0A         0A         0A
[POWER Clamp]
| Voltage   I(typ)   I(min)   I(max)
-3.3V     275.2mA    210.4mA    339.7mA
-1.516V   71.72mA    51.19mA    95.6mA
-1.299V   52.29mA    37.12mA    70.48mA
-1.191V   42.98mA    30.64mA    58.82mA
-1.083V   34.17mA    24.57mA    48.66mA
-974.5mV  26.55mA    19mA       39.55mA
-866.2mV  20.14mA    14.04mA    29.74mA
-649.7mV  7.231mA    6.078mA    9.686mA
-541.4mV  2.468mA    2.939mA    3.223mA
-433.1mV  320uA      882.8uA    445.9uA
-216.6mV  124.9nA    7.814uA    30.51nA
6.6V      0A         0A         0A
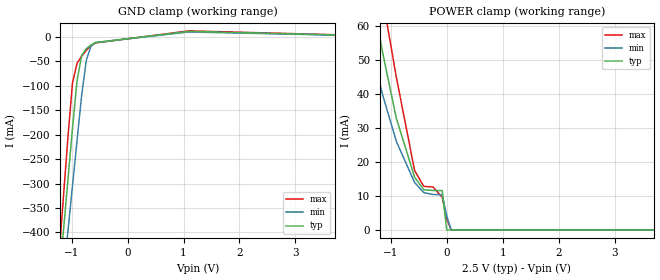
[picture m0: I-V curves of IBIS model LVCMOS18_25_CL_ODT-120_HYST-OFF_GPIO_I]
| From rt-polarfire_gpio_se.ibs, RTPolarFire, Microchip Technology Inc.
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|   Model LVCMOS18_25_CL_ODT-120_HYST-OFF_GPIO_I
[Model]   LVCMOS18_25_CL_ODT-120_HYST-OFF_GPIO_I
Model_type   Input
Vinl =   0.63
Vinh =   1.17
|   typ   min   max
C_comp_pullup   2.605e-12   2.605e-12   2.76e-12
C_comp_pulldown  2.605e-12   2.605e-12   2.76e-12
[Temperature Range]  25C   125C   -55C
[Voltage Range]  2.5   2.375   2.625
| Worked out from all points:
|   POWER clamp passes 1 mA (typ) near -0.01 V on its own axis
[GND Clamp]
| Voltage   I(typ)   I(min)   I(max)
-2.5V     -2.158A    -2.032A    -2.417A
-1.23V    -504.6mA   -583.2mA   -454.7mA
-1.148V   -398.5mA   -490.2mA   -329.3mA
-1.066V   -292.5mA   -397.2mA   -205mA
-984.4mV  -186.9mA   -304.1mA   -94.43mA
-902.3mV  -89.08mA   -211.2mA   -53.94mA
-820.3mV  -38.4mA    -119.2mA   -39.81mA
-738.3mV  -24.38mA   -48.52mA   -27.88mA
-656.2mV  -17.05mA   -20.05mA   -18.74mA
-574.2mV  -12.07mA   -11.95mA   -12.83mA
1.094V    10.78mA    9.587mA    11.85mA
5V        0A         0A         0A
[POWER Clamp]
| Voltage   I(typ)   I(min)   I(max)
-2.5V     202.8mA    160.1mA    250.2mA
-1.559V   91.03mA    68.72mA    117.5mA
-1.312V   66.98mA    50.56mA    87.14mA
-1.148V   52.21mA    39.78mA    68.24mA
-902.3mV  32.84mA    26.07mA    44.93mA
-574.2mV  15.48mA    13.92mA    17.42mA
-410.2mV  11.8mA     10.97mA    12.81mA
-246.1mV  11.6mA     10.42mA    12.62mA
-82.03mV  11.57mA    10.34mA    9.598mA
0V        0A         4.135mA    3.299mA
78.12mV   0A         0A         0A
5V        0A         0A         0A
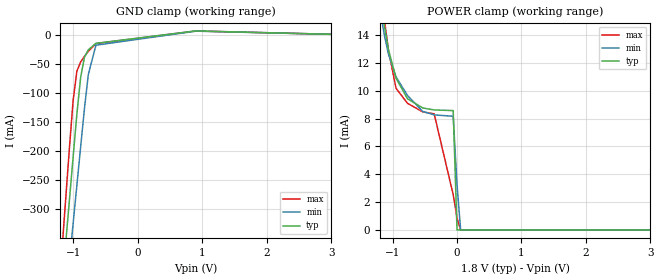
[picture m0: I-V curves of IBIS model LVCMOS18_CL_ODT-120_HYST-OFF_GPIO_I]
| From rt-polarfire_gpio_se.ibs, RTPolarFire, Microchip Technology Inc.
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|   Model LVCMOS18_CL_ODT-120_HYST-OFF_GPIO_I
[Model]   LVCMOS18_CL_ODT-120_HYST-OFF_GPIO_I
Model_type   Input
Vinl =   0.63
Vinh =   1.17
|   typ   min   max
C_comp_pullup   2.605e-12   2.605e-12   2.76e-12
C_comp_pulldown  2.605e-12   2.605e-12   2.76e-12
[Temperature Range]  25C   125C   -55C
[Voltage Range]  1.8   1.71   1.89
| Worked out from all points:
|   GND clamp passes 1 mA (typ) near -0.08 V on its own axis
|   POWER clamp passes 1 mA (typ) near -0.01 V on its own axis
[GND Clamp]
| Voltage   I(typ)   I(min)   I(max)
-1.8V     -1.241A    -1.229A    -1.329A
-1.181V   -439.9mA   -526.6mA   -377.8mA
-1.122V   -363.5mA   -459.6mA   -287.5mA
-1.063V   -287.2mA   -392.6mA   -197.9mA
-1.004V   -211mA     -325.6mA   -113.1mA
-945mV    -135.7mA   -258.7mA   -61.75mA
-885.9mV  -71.93mA   -191.8mA   -45.89mA
-826.9mV  -37.63mA   -125.4mA   -36.39mA
-767.8mV  -25.04mA   -67.73mA   -27.76mA
-649.7mV  -13.91mA   -17.14mA   -14.4mA
900mV     7.483mA    7.078mA    7.356mA
3.6V      0A         0A         0A
[POWER Clamp]
| Voltage   I(typ)   I(min)   I(max)
-1.8V     54.22mA    42.19mA    70.3mA
-1.181V   16.58mA    15.44mA    17.49mA
-1.122V   14.54mA    13.89mA    14.96mA
-1.063V   12.96mA    12.63mA    12.89mA
-945mV    10.89mA    10.99mA    10.17mA
-767.8mV  9.426mA    9.66mA     9.1mA
-531.6mV  8.764mA    8.517mA    8.482mA
-354.4mV  8.623mA    8.266mA    8.341mA
-59.06mV  8.574mA    8.168mA    2.538mA
0V        0A         3.265mA    872.6uA
56.25mV   0A         0A         0A
3.6V      0A         0A         0A
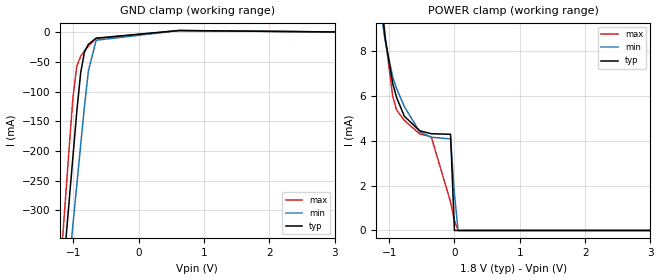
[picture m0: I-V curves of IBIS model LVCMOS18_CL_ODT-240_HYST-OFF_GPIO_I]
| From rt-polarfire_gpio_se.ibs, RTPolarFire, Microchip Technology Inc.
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|   Model LVCMOS18_CL_ODT-240_HYST-OFF_GPIO_I
[Model]   LVCMOS18_CL_ODT-240_HYST-OFF_GPIO_I
Model_type   Input
Vinl =   0.63
Vinh =   1.17
|   typ   min   max
C_comp_pullup   2.605e-12   2.605e-12   2.76e-12
C_comp_pulldown  2.605e-12   2.605e-12   2.76e-12
[Temperature Range]  25C   125C   -55C
[Voltage Range]  1.8   1.71   1.89
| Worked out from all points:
|   GND clamp passes 1 mA (typ) near -0.15 V on its own axis
|   POWER clamp passes 1 mA (typ) near -0.01 V on its own axis
[GND Clamp]
| Voltage   I(typ)   I(min)   I(max)
-1.8V     -1.24A     -1.227A    -1.328A
-1.181V   -438.2mA   -524.8mA   -376.2mA
-1.122V   -361.8mA   -457.9mA   -285.8mA
-1.063V   -285.4mA   -390.9mA   -195.8mA
-1.004V   -209.1mA   -323.9mA   -109.9mA
-945mV    -133.2mA   -257mA     -56.96mA
-885.9mV  -68.26mA   -190.1mA   -40.59mA
-826.9mV  -32.87mA   -123.6mA   -31.21mA
-767.8mV  -20.31mA   -65.07mA   -23.04mA
-649.7mV  -9.872mA   -13.38mA   -10.6mA
618.8mV   3.008mA    2.833mA    2.969mA
3.6V      0A         0A         0A
[POWER Clamp]
| Voltage   I(typ)   I(min)   I(max)
-1.8V     49.82mA    38.05mA    65.8mA
-1.122V   10.21mA    9.756mA    10.78mA
-1.063V   8.628mA    8.488mA    8.713mA
-945mV    6.559mA    6.855mA    5.987mA
-885.9mV  5.937mA    6.33mA     5.376mA
-767.8mV  5.096mA    5.528mA    4.91mA
-531.6mV  4.444mA    4.397mA    4.304mA
-354.4mV  4.313mA    4.157mA    4.171mA
-59.06mV  4.287mA    4.083mA    1.269mA
0V        0A         1.632mA    436.3uA
56.25mV   0A         0A         0A
3.6V      0A         0A         0A
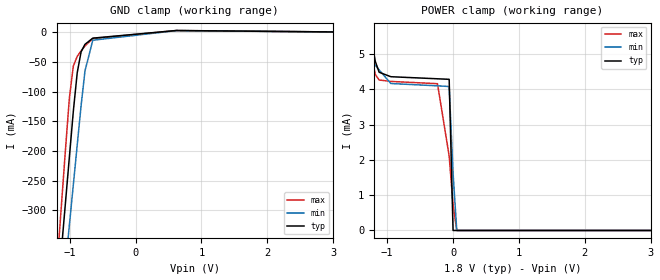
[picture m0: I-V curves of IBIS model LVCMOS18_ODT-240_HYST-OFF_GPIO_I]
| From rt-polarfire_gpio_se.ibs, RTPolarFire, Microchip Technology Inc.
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|   Model LVCMOS18_ODT-240_HYST-OFF_GPIO_I
[Model]   LVCMOS18_ODT-240_HYST-OFF_GPIO_I
Model_type   Input
Vinl =   0.63
Vinh =   1.17
|   typ   min   max
C_comp_pullup   2.605e-12   2.605e-12   2.76e-12
C_comp_pulldown  2.605e-12   2.605e-12   2.76e-12
[Temperature Range]  25C   125C   -55C
[Voltage Range]  1.8   1.71   1.89
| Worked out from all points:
|   GND clamp passes 1 mA (typ) near -0.15 V on its own axis
|   POWER clamp passes 1 mA (typ) near -0.01 V on its own axis
[GND Clamp]
| Voltage   I(typ)   I(min)   I(max)
-1.8V     -1.24A     -1.227A    -1.328A
-1.181V   -438.2mA   -524.8mA   -376.2mA
-1.122V   -361.8mA   -457.9mA   -285.8mA
-1.063V   -285.4mA   -390.9mA   -195.8mA
-1.004V   -209.1mA   -323.9mA   -109.9mA
-945mV    -133.2mA   -257mA     -56.96mA
-885.9mV  -68.26mA   -190.1mA   -40.59mA
-826.9mV  -32.87mA   -123.6mA   -31.21mA
-767.8mV  -20.31mA   -65.07mA   -23.04mA
-649.7mV  -9.872mA   -13.38mA   -10.6mA
618.8mV   3.008mA    2.833mA    2.969mA
3.6V      0A         0A         0A
[POWER Clamp]
| Voltage   I(typ)   I(min)   I(max)
-1.8V     26.41mA    22.27mA    31.7mA
-1.358V   6.209mA    6.22mA     7.171mA
-1.299V   5.416mA    5.365mA    6.158mA
-1.24V    5.416mA    4.851mA    4.973mA
-1.181V   4.797mA    4.685mA    4.427mA
-1.122V   4.487mA    4.552mA    4.268mA
-945mV    4.361mA    4.168mA    4.227mA
-236.2mV  4.302mA    4.102mA    4.163mA
-59.06mV  4.287mA    4.083mA    2.111mA
0V        0A         1.632mA    725.8uA
56.25mV   0A         0A         0A
3.6V      0A         0A         0A
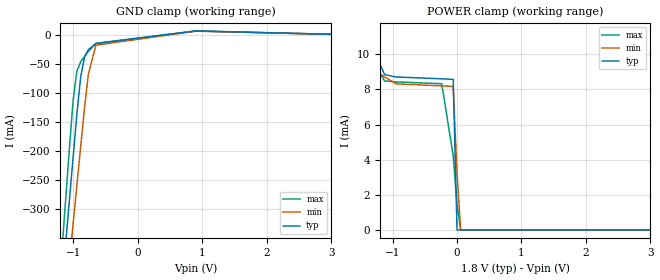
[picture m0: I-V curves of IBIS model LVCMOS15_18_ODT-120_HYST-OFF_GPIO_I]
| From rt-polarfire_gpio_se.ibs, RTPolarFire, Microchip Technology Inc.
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|   Model LVCMOS15_18_ODT-120_HYST-OFF_GPIO_I
[Model]   LVCMOS15_18_ODT-120_HYST-OFF_GPIO_I
Model_type   Input
Vinl =   0.525
Vinh =   0.975
|   typ   min   max
C_comp_pullup   2.605e-12   2.605e-12   2.76e-12
C_comp_pulldown  2.605e-12   2.605e-12   2.76e-12
[Temperature Range]  25C   125C   -55C
[Voltage Range]  1.8   1.71   1.89
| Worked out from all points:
|   GND clamp passes 1 mA (typ) near -0.08 V on its own axis
|   POWER clamp passes 1 mA (typ) near -0.01 V on its own axis
[GND Clamp]
| Voltage   I(typ)   I(min)   I(max)
-1.8V     -1.241A    -1.229A    -1.329A
-1.181V   -439.9mA   -526.6mA   -377.8mA
-1.122V   -363.5mA   -459.6mA   -287.5mA
-1.063V   -287.2mA   -392.6mA   -197.9mA
-1.004V   -211mA     -325.6mA   -113.1mA
-945mV    -135.7mA   -258.7mA   -61.75mA
-885.9mV  -71.93mA   -191.8mA   -45.89mA
-826.9mV  -37.63mA   -125.4mA   -36.39mA
-767.8mV  -25.04mA   -67.73mA   -27.76mA
-649.7mV  -13.91mA   -17.14mA   -14.4mA
900mV     7.483mA    7.078mA    7.356mA
3.6V      0A         0A         0A
[POWER Clamp]
| Voltage   I(typ)   I(min)   I(max)
-1.8V     30.73mA    26.43mA    35.88mA
-1.417V   11.83mA    11.6mA     12.67mA
-1.358V   10.56mA    10.38mA    11.4mA
-1.299V   9.784mA    9.525mA    10.38mA
-1.24V    9.784mA    9.014mA    9.189mA
-1.122V   8.845mA    8.713mA    8.482mA
-945mV    8.709mA    8.319mA    8.431mA
-236.2mV  8.604mA    8.203mA    8.325mA
-59.06mV  8.574mA    8.168mA    4.223mA
0V        0A         3.265mA    1.452mA
56.25mV   0A         0A         0A
3.6V      0A         0A         0A
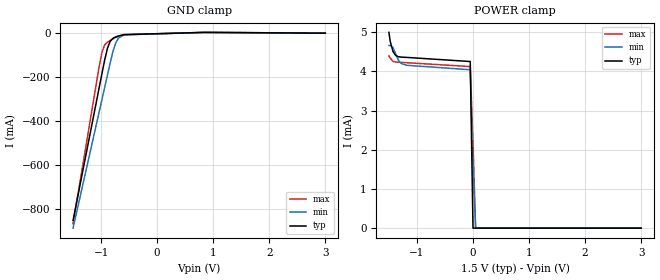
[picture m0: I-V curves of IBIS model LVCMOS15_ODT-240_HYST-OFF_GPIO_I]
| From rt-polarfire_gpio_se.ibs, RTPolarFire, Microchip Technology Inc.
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|   Model LVCMOS15_ODT-240_HYST-OFF_GPIO_I
[Model]   LVCMOS15_ODT-240_HYST-OFF_GPIO_I
Model_type   Input
Vinl =   0.525
Vinh =   0.975
|   typ   min   max
C_comp_pullup   2.605e-12   2.605e-12   2.76e-12
C_comp_pulldown  2.605e-12   2.605e-12   2.76e-12
[Temperature Range]  25C   125C   -55C
[Voltage Range]  1.5   1.425   1.575
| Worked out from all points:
|   GND clamp passes 1 mA (typ) near -0.15 V on its own axis
|   POWER clamp passes 1 mA (typ) near -0.01 V on its own axis
[GND Clamp]
| Voltage   I(typ)   I(min)   I(max)
-1.5V     -850.9mA   -886mA     -865.9mA
-1.034V   -247.2mA   -357.4mA   -151.2mA
-984.4mV  -183.7mA   -301.6mA   -87mA
-935.2mV  -121mA     -245.9mA   -52.68mA
-885.9mV  -68.26mA   -190.1mA   -40.59mA
-836.7mV  -36.64mA   -134.6mA   -32.68mA
-787.5mV  -23.23mA   -82.46mA   -25.63mA
-738.3mV  -16.97mA   -43.89mA   -19.43mA
-689.1mV  -12.65mA   -21.92mA   -14.14mA
-590.6mV  -6.685mA   -7.567mA   -6.721mA
843.8mV   3.627mA    3.427mA    3.567mA
3V        0A         0A         0A
[POWER Clamp]
| Voltage   I(typ)   I(min)   I(max)
-1.5V     4.995mA    4.66mA     4.397mA
-1.477V   4.764mA    4.66mA     4.336mA
-1.427V   4.505mA    4.605mA    4.256mA
-1.378V   4.403mA    4.442mA    4.238mA
-1.329V   4.373mA    4.279mA    4.233mA
-1.28V    4.364mA    4.2mA      4.228mA
-1.181V   4.356mA    4.155mA    4.221mA
-49.22mV  4.251mA    4.041mA    4.122mA
0V        0A         1.615mA    2.158mA
46.88mV   0A         0A         0A
3V        0A         0A         0A
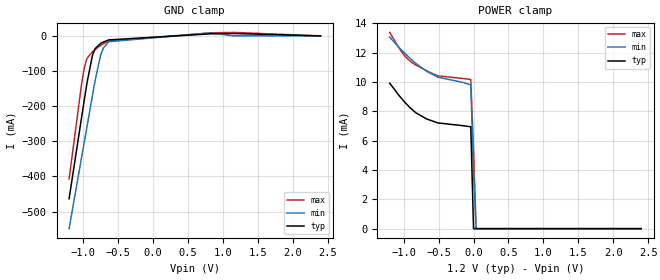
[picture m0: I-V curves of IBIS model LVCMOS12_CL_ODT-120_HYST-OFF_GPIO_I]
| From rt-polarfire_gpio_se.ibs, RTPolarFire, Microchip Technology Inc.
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|   Model LVCMOS12_CL_ODT-120_HYST-OFF_GPIO_I
[Model]   LVCMOS12_CL_ODT-120_HYST-OFF_GPIO_I
Model_type   Input
Vinl =   0.42
Vinh =   0.78
|   typ   min   max
C_comp_pullup   2.605e-12   2.605e-12   2.76e-12
C_comp_pulldown  2.605e-12   2.605e-12   2.76e-12
[Temperature Range]  25C   125C   -55C
[Voltage Range]  1.2   1.14   1.26
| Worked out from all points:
|   GND clamp passes 1 mA (typ) near -0.09 V on its own axis
|   POWER clamp passes 1 mA (typ) near -0.01 V on its own axis
[GND Clamp]
| Voltage   I(typ)   I(min)   I(max)
-1.2V     -463.6mA   -548.7mA   -407.3mA
-1.024V   -235.7mA   -348.8mA   -140.9mA
-984.4mV  -185mA     -304.1mA   -92.54mA
-945mV    -134.8mA   -259.5mA   -64.14mA
-866.2mV  -55.66mA   -170.4mA   -45.07mA
-826.9mV  -36.15mA   -126.4mA   -38.7mA
-748.1mV  -21.12mA   -54.68mA   -27.16mA
-708.7mV  -17.17mA   -34.03mA   -22.27mA
-630mV    -11.32mA   -16.44mA   -14.68mA
825mV     5.97mA     8.45mA     8.809mA
1.163V    6.854mA    0A         10.01mA
2.4V      0A         0A         0A
[POWER Clamp]
| Voltage   I(typ)   I(min)   I(max)
-1.2V     9.911mA    13.05mA    13.37mA
-1.063V   9.049mA    12.32mA    12.27mA
-984.4mV  8.612mA    11.94mA    11.76mA
-905.6mV  8.223mA    11.59mA    11.4mA
-826.9mV  7.895mA    11.26mA    11.15mA
-669.4mV  7.469mA    10.71mA    10.75mA
-511.9mV  7.204mA    10.32mA    10.41mA
-157.5mV  7.018mA    9.969mA    10.23mA
-39.38mV  6.94mA     9.792mA    10.16mA
0V        0A         3.903mA    5.315mA
37.5mV    0A         0A         0A
2.4V      0A         0A         0A
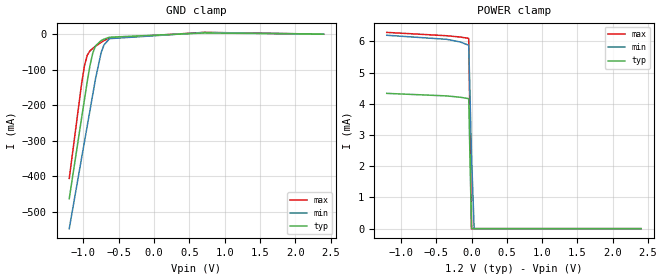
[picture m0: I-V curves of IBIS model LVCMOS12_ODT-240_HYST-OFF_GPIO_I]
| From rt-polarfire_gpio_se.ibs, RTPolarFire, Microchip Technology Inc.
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|   Model LVCMOS12_ODT-240_HYST-OFF_GPIO_I
[Model]   LVCMOS12_ODT-240_HYST-OFF_GPIO_I
Model_type   Input
Vinl =   0.42
Vinh =   0.78
|   typ   min   max
C_comp_pullup   2.605e-12   2.605e-12   2.76e-12
C_comp_pulldown  2.605e-12   2.605e-12   2.76e-12
[Temperature Range]  25C   125C   -55C
[Voltage Range]  1.2   1.14   1.26
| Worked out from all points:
|   GND clamp passes 1 mA (typ) near -0.15 V on its own axis
|   POWER clamp passes 1 mA (typ) near -0.01 V on its own axis
[GND Clamp]
| Voltage   I(typ)   I(min)   I(max)
-1.2V     -462.5mA   -546.9mA   -405.7mA
-1.024V   -234.5mA   -347.1mA   -138.1mA
-984.4mV  -183.7mA   -302.5mA   -88.76mA
-945mV    -133.2mA   -257.9mA   -59.3mA
-905.6mV  -87.18mA   -213.3mA   -46.97mA
-866.2mV  -52.86mA   -168.7mA   -39.93mA
-826.9mV  -32.87mA   -124.5mA   -33.84mA
-748.1mV  -17.99mA   -51.76mA   -22.99mA
-708.7mV  -14.25mA   -30.6mA    -18.27mA
-630mV    -8.682mA   -12.72mA   -10.98mA
712.5mV   3.294mA    4.657mA    4.872mA
2.4V      0A         0A         0A
[POWER Clamp]
| Voltage   I(typ)   I(min)   I(max)
-1.2V     4.335mA    6.197mA    6.289mA
-354.4mV  4.254mA    6.068mA    6.182mA
-157.5mV  4.211mA    5.982mA    6.14mA
-39.38mV  4.165mA    5.876mA    6.098mA
0V        0A         2.343mA    0A
37.5mV    0A         0A         0A
2.4V      0A         0A         0A
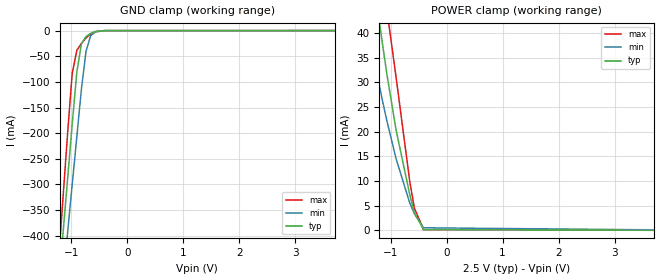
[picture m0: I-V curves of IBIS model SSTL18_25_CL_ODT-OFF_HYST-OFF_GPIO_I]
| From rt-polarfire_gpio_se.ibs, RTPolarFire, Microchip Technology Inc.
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|   Model SSTL18_25_CL_ODT-OFF_HYST-OFF_GPIO_I
[Model]   SSTL18_25_CL_ODT-OFF_HYST-OFF_GPIO_I
Model_type   Input
Vinl =   0.775
Vinh =   1.025
|   typ   min   max
C_comp_pullup   2.605e-12   2.605e-12   2.76e-12
C_comp_pulldown  2.605e-12   2.605e-12   2.76e-12
[Temperature Range]  25C   125C   -55C
[Voltage Range]  2.5   2.375   2.625
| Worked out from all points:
|   GND clamp passes 1 mA (typ) near -0.52 V on its own axis
|   POWER clamp passes 1 mA (typ) near -0.48 V on its own axis
[GND Clamp]
| Voltage   I(typ)   I(min)   I(max)
-2.5V     -2.154A    -2.027A    -2.413A
-1.23V    -500.3mA   -578.7mA   -450.4mA
-1.148V   -394.1mA   -485.8mA   -324.6mA
-1.066V   -288mA     -392.8mA   -199mA
-984.4mV  -181.9mA   -299.8mA   -83.61mA
-902.3mV  -80.78mA   -206.9mA   -38.62mA
-820.3mV  -25.8mA    -114.2mA   -25.13mA
-738.3mV  -11.65mA   -40.52mA   -14.41mA
-656.2mV  -5.525mA   -10.21mA   -6.635mA
-574.2mV  -1.954mA   -2.666mA   -2.194mA
-410.2mV  -41.8uA    -101uA     -33.53uA
5V        0A         0A         0A
[POWER Clamp]
| Voltage   I(typ)   I(min)   I(max)
-2.5V     169.7mA    124.7mA    217.9mA
-1.641V   80.72mA    56.61mA    108.1mA
-1.477V   65.83mA    45.76mA    88.91mA
-1.312V   51.56mA    35.72mA    70.16mA
-1.23V    44.7mA     31mA       61.26mA
-1.148V   38.06mA    26.49mA    52.75mA
-1.066V   31.71mA    22.23mA    44.71mA
-902.3mV  20.41mA    14.58mA    31.13mA
-656.2mV  7.231mA    5.53mA     9.886mA
-574.2mV  3.588mA    3.38mA     4.517mA
-410.2mV  170.6uA    543uA      161.8uA
5V        0A         0A         0A
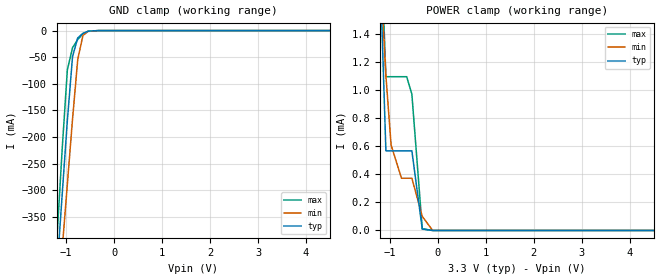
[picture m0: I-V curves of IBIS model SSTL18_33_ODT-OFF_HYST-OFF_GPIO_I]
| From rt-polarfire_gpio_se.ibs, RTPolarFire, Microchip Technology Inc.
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|   Model SSTL18_33_ODT-OFF_HYST-OFF_GPIO_I
[Model]   SSTL18_33_ODT-OFF_HYST-OFF_GPIO_I
Model_type   Input
Vinl =   0.775
Vinh =   1.025
|   typ   min   max
C_comp_pullup   2.605e-12   2.605e-12   2.76e-12
C_comp_pulldown  2.605e-12   2.605e-12   2.76e-12
[Temperature Range]  25C   125C   -55C
[Voltage Range]  3.3   3.135   3.465
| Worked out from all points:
|   GND clamp passes 1 mA (typ) near -0.53 V on its own axis
|   POWER clamp passes 1 mA (typ) near -1.12 V on its own axis
[GND Clamp]
| Voltage   I(typ)   I(min)   I(max)
-3.3V     -3.213A    -2.952A    -3.676A
-1.191V   -449.3mA   -534.2mA   -390mA
-1.083V   -309.2mA   -411.4mA   -224.1mA
-974.5mV  -169.2mA   -288.7mA   -73.71mA
-866.2mV  -48.93mA   -166mA     -32.16mA
-758mV    -13.75mA   -54.29mA   -16.74mA
-649.7mV  -5.158mA   -9.147mA   -6.158mA
-541.4mV  -1.115mA   -1.518mA   -1.242mA
-324.8mV  -2.612uA   -12.67uA   -880.5nA
6.6V      0A         0A         0A
[POWER Clamp]
| Voltage   I(typ)   I(min)   I(max)
-3.3V     119.9mA    76.08mA    170.3mA
-1.191V   1.725mA    1.78mA     2.104mA
-1.083V   567.5uA    1.105mA    1.096mA
-974.5mV  567.5uA    608.6uA    1.096mA
-758mV    567.5uA    372.3uA    1.096mA
-649.7mV  567.5uA    372.3uA    1.096mA
-541.4mV  567.5uA    372.3uA    971.3uA
-324.8mV  9.786uA    100.6uA    12.48uA
-108.3mV  2.693nA    291.5nA    1.299nA
6.6V      0A         0A         0A
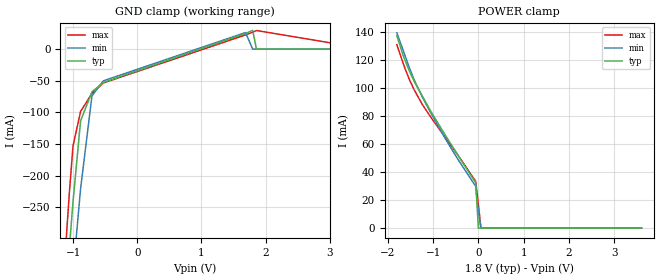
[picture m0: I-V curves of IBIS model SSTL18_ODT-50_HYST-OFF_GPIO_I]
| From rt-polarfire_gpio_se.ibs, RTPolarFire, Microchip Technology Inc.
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|   Model SSTL18_ODT-50_HYST-OFF_GPIO_I
[Model]   SSTL18_ODT-50_HYST-OFF_GPIO_I
Model_type   Input
Vinl =   0.775
Vinh =   1.025
|   typ   min   max
C_comp_pullup   2.605e-12   2.605e-12   2.76e-12
C_comp_pulldown  2.605e-12   2.605e-12   2.76e-12
[Temperature Range]  25C   125C   -55C
[Voltage Range]  1.8   1.71   1.89
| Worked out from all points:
|   POWER clamp passes 1 mA (typ) near -0.00 V on its own axis
[GND Clamp]
| Voltage   I(typ)   I(min)   I(max)
-1.8V     -1.272A    -1.259A    -1.357A
-1.181V   -470mA     -556.1mA   -408mA
-1.122V   -393.6mA   -489.1mA   -317.7mA
-1.063V   -317.2mA   -421.9mA   -230mA
-1.004V   -241.2mA   -354.8mA   -153mA
-885.9mV  -113.4mA   -220.7mA   -98.51mA
-708.7mV  -67.58mA   -74.12mA   -70.14mA
-531.6mV  -52.72mA   -50.12mA   -53.54mA
1.688V    24.74mA    26.22mA    22.43mA
1.8V      29.61mA    0A         26.86mA
1.859V    0A         0A         29.37mA
3.6V      0A         0A         0A
[POWER Clamp]
| Voltage   I(typ)   I(min)   I(max)
-1.8V     137.5mA    139.5mA    131.1mA
-1.654V   122.8mA    126.5mA    117.1mA
-1.536V   113.2mA    115.6mA    107.1mA
-1.417V   104.8mA    105.9mA    98.83mA
-1.24V    94.53mA    93.81mA    88.47mA
-1.063V   84.09mA    83.07mA    79.89mA
-708.7mV  65.27mA    62.79mA    63.71mA
-472.5mV  53.25mA    50.18mA    53.14mA
-59.06mV  32.36mA    29.86mA    33.41mA
0V        0A         11.48mA    16.76mA
56.25mV   0A         0A         0A
3.6V      0A         0A         0A
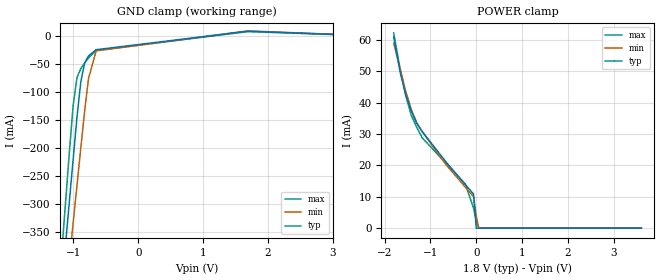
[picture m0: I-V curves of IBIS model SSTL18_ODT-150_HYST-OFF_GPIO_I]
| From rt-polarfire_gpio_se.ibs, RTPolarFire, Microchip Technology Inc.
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|   Model SSTL18_ODT-150_HYST-OFF_GPIO_I
[Model]   SSTL18_ODT-150_HYST-OFF_GPIO_I
Model_type   Input
Vinl =   0.775
Vinh =   1.025
|   typ   min   max
C_comp_pullup   2.605e-12   2.605e-12   2.76e-12
C_comp_pulldown  2.605e-12   2.605e-12   2.76e-12
[Temperature Range]  25C   125C   -55C
[Voltage Range]  1.8   1.71   1.89
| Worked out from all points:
|   POWER clamp passes 1 mA (typ) near -0.01 V on its own axis
[GND Clamp]
| Voltage   I(typ)   I(min)   I(max)
-1.8V     -1.25A     -1.237A    -1.337A
-1.181V   -448.4mA   -534.4mA   -387.8mA
-1.122V   -372.1mA   -467.4mA   -297.7mA
-1.063V   -295.8mA   -400.4mA   -208mA
-1.004V   -219.6mA   -333.4mA   -123.8mA
-945mV    -144.5mA   -266.4mA   -74.25mA
-885.9mV  -81.59mA   -199.5mA   -58.44mA
-826.9mV  -48.24mA   -133.3mA   -48.36mA
-767.8mV  -35.93mA   -76.23mA   -39.42mA
-649.7mV  -24.67mA   -26.85mA   -25.86mA
1.688V    8.309mA    8.812mA    7.524mA
3.6V      0A         0A         0A
[POWER Clamp]
| Voltage   I(typ)   I(min)   I(max)
-1.8V     60.86mA    58.91mA    62.19mA
-1.654V   49.31mA    50.49mA    50.19mA
-1.536V   42.52mA    43.56mA    42.18mA
-1.417V   37.28mA    37.85mA    35.91mA
-1.299V   33.46mA    33.66mA    32.2mA
-1.181V   30.84mA    30.76mA    28.82mA
-649.7mV  20.92mA    20.06mA    20.51mA
-236.2mV  13.85mA    13.04mA    14.01mA
-59.06mV  10.88mA    10.04mA    6.387mA
0V        0A         3.86mA     2.196mA
56.25mV   0A         0A         0A
3.6V      0A         0A         0A
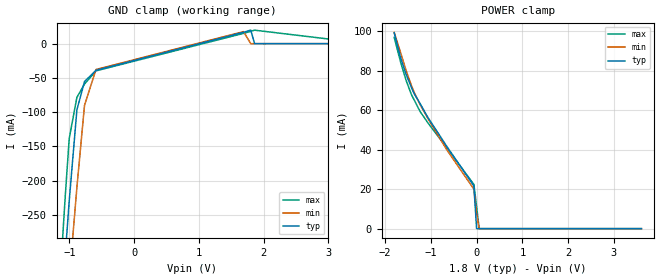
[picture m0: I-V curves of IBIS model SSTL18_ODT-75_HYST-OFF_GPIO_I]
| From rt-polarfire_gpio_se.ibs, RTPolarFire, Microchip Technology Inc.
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|   Model SSTL18_ODT-75_HYST-OFF_GPIO_I
[Model]   SSTL18_ODT-75_HYST-OFF_GPIO_I
Model_type   Input
Vinl =   0.775
Vinh =   1.025
|   typ   min   max
C_comp_pullup   2.605e-12   2.605e-12   2.76e-12
C_comp_pulldown  2.605e-12   2.605e-12   2.76e-12
[Temperature Range]  25C   125C   -55C
[Voltage Range]  1.8   1.71   1.89
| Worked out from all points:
|   POWER clamp passes 1 mA (typ) near -0.00 V on its own axis
[GND Clamp]
| Voltage   I(typ)   I(min)   I(max)
-1.8V     -1.26A     -1.248A    -1.348A
-1.181V   -458.5mA   -545.5mA   -398.7mA
-1.122V   -382.2mA   -478.5mA   -308.3mA
-1.063V   -305.9mA   -411.4mA   -219.5mA
-1.004V   -229.8mA   -344.4mA   -138.6mA
-885.9mV  -96.92mA   -210.4mA   -78.57mA
-767.8mV  -55.27mA   -90.1mA    -59.05mA
-590.6mV  -38.92mA   -37.77mA   -39.75mA
1.688V    16.54mA    17.56mA    15.01mA
1.8V      19.81mA    0A         17.99mA
1.859V    0A         0A         19.67mA
3.6V      0A         0A         0A
[POWER Clamp]
| Voltage   I(typ)   I(min)   I(max)
-1.8V     99.16mA    99.36mA    96.82mA
-1.654V   86.03mA    88.66mA    83.8mA
-1.536V   77.88mA    79.77mA    74.81mA
-1.417V   71.08mA    72.03mA    67.5mA
-1.358V   68.1mA     68.73mA    64.94mA
-1.24V    63.57mA    63.06mA    59.52mA
-1.063V   56.26mA    55.75mA    53.54mA
-649.7mV  41.6mA     39.89mA    40.88mA
-59.06mV  21.65mA    20mA       22.38mA
0V        0A         7.688mA    11.23mA
56.25mV   0A         0A         0A
3.6V      0A         0A         0A
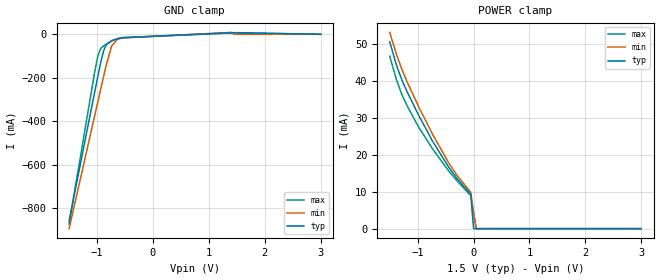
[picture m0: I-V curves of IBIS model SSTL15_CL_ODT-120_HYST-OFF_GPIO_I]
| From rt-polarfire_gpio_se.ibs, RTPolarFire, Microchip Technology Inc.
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|   Model SSTL15_CL_ODT-120_HYST-OFF_GPIO_I
[Model]   SSTL15_CL_ODT-120_HYST-OFF_GPIO_I
Model_type   Input
Vinl =   0.65
Vinh =   0.85
|   typ   min   max
C_comp_pullup   2.605e-12   2.605e-12   2.76e-12
C_comp_pulldown  2.605e-12   2.605e-12   2.76e-12
[Temperature Range]  25C   125C   -55C
[Voltage Range]  1.5   1.425   1.575
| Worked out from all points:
|   POWER clamp passes 1 mA (typ) near -0.01 V on its own axis
[GND Clamp]
| Voltage   I(typ)   I(min)   I(max)
-1.5V     -858.6mA   -894mA     -873mA
-1.034V   -255.4mA   -365.2mA   -161.2mA
-984.4mV  -192mA     -309.4mA   -98.64mA
-935.2mV  -129.9mA   -253.6mA   -66.13mA
-885.9mV  -78.61mA   -197.9mA   -54.07mA
-836.7mV  -48.33mA   -142.5mA   -45.61mA
-738.3mV  -28.71mA   -54.17mA   -31.2mA
-639.8mV  -20.45mA   -23.73mA   -20.93mA
-541.4mV  -15.52mA   -16.57mA   -15.35mA
1.406V    7.094mA    8.744mA    5.909mA
1.453V    7.758mA    0A         6.503mA
3V        0A         0A         0A
[POWER Clamp]
| Voltage   I(typ)   I(min)   I(max)
-1.5V     50.5mA     53.08mA    46.64mA
-1.378V   44.13mA    47.07mA    40.21mA
-1.28V    40.11mA    42.97mA    36.17mA
-1.181V   36.74mA    39.44mA    32.99mA
-984.4mV  30.74mA    33.06mA    27.51mA
-738.3mV  23.78mA    25.67mA    21.7mA
-443mV    16.6mA     17.75mA    15.56mA
-295.3mV  13.58mA    14.43mA    12.94mA
-49.22mV  9.228mA    9.823mA    8.95mA
0V        0A         3.79mA     4.479mA
46.88mV   0A         0A         0A
3V        0A         0A         0A
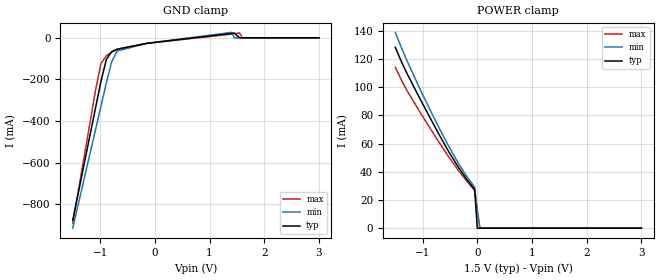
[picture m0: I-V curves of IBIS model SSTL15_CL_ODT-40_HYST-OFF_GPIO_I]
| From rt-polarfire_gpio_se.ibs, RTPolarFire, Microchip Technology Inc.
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|   Model SSTL15_CL_ODT-40_HYST-OFF_GPIO_I
[Model]   SSTL15_CL_ODT-40_HYST-OFF_GPIO_I
Model_type   Input
Vinl =   0.65
Vinh =   0.85
|   typ   min   max
C_comp_pullup   2.605e-12   2.605e-12   2.76e-12
C_comp_pulldown  2.605e-12   2.605e-12   2.76e-12
[Temperature Range]  25C   125C   -55C
[Voltage Range]  1.5   1.425   1.575
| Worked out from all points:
|   POWER clamp passes 1 mA (typ) near -0.00 V on its own axis
[GND Clamp]
| Voltage   I(typ)   I(min)   I(max)
-1.5V     -875.5mA   -913.7mA   -889.5mA
-1.083V   -335.5mA   -440.1mA   -251.6mA
-984.4mV  -209.1mA   -328.3mA   -123.7mA
-885.9mV  -103.8mA   -216.5mA   -85.54mA
-787.5mV  -66.79mA   -114.6mA   -68.83mA
-689.1mV  -54.8mA    -63.36mA   -55.33mA
-147.7mV  -26.67mA   -26.82mA   -27.07mA
1.406V    21.1mA     26.01mA    17.61mA
1.453V    23.07mA    0A         19.37mA
1.549V    0A         0A         23.28mA
1.598V    0A         0A         0A
3V        0A         0A         0A
[POWER Clamp]
| Voltage   I(typ)   I(min)   I(max)
-1.5V     128.4mA    139mA      114.3mA
-1.378V   117.4mA    127.3mA    104.4mA
-1.28V    109.4mA    118.4mA    97.33mA
-1.034V   90.81mA    97.61mA    81.52mA
-738.3mV  69.24mA    74.15mA    63.24mA
-541.4mV  55.48mA    59.45mA    51.61mA
-344.5mV  43.13mA    45.88mA    40.96mA
-196.9mV  34.85mA    36.97mA    33.55mA
-49.22mV  27.41mA    29.21mA    26.61mA
0V        0A         11.27mA    13.33mA
46.88mV   0A         0A         0A
3V        0A         0A         0A
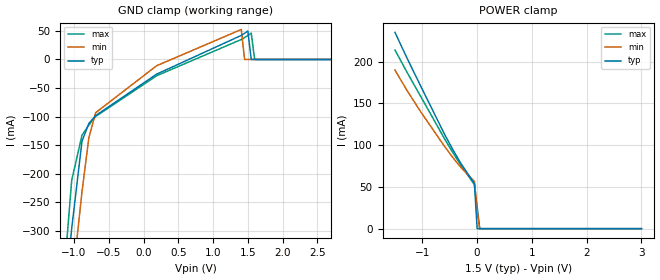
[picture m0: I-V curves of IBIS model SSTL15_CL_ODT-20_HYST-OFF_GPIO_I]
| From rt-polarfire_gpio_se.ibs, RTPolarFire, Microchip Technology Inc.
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|   Model SSTL15_CL_ODT-20_HYST-OFF_GPIO_I
[Model]   SSTL15_CL_ODT-20_HYST-OFF_GPIO_I
Model_type   Input
Vinl =   0.65
Vinh =   0.85
|   typ   min   max
C_comp_pullup   2.605e-12   2.605e-12   2.76e-12
C_comp_pulldown  2.605e-12   2.605e-12   2.76e-12
[Temperature Range]  25C   125C   -55C
[Voltage Range]  1.5   1.425   1.575
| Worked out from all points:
|   POWER clamp passes 1 mA (typ) near -0.00 V on its own axis
[GND Clamp]
| Voltage   I(typ)   I(min)   I(max)
-1.5V     -900mA     -930.3mA   -913.8mA
-1.034V   -296mA     -399.9mA   -211.6mA
-885.9mV  -143.2mA   -231.8mA   -132.7mA
-787.5mV  -112mA     -137.2mA   -114.9mA
-689.1mV  -98.26mA   -93.2mA    -99.74mA
187.5mV   -25.73mA   -11.02mA   -28.58mA
1.406V    42.12mA    52.5mA     34.91mA
1.453V    45.82mA    0A         38.38mA
1.5V      49.71mA    0A         42.03mA
1.549V    0A         0A         46.08mA
1.598V    0A         0A         0A
3V        0A         0A         0A
[POWER Clamp]
| Voltage   I(typ)   I(min)   I(max)
-1.5V     235.2mA    190mA      214.1mA
-1.28V    204.4mA    165.6mA    187.4mA
-1.034V   171.3mA    140.4mA    158.9mA
-590.6mV  112.6mA    98.21mA    107.2mA
-443mV    94.65mA    85.2mA     91.11mA
-295.3mV  78.12mA    73.29mA    75.94mA
-49.22mV  53.99mA    56.5mA     52.63mA
0V        0A         22.09mA    26.36mA
46.88mV   0A         0A         0A
3V        0A         0A         0A
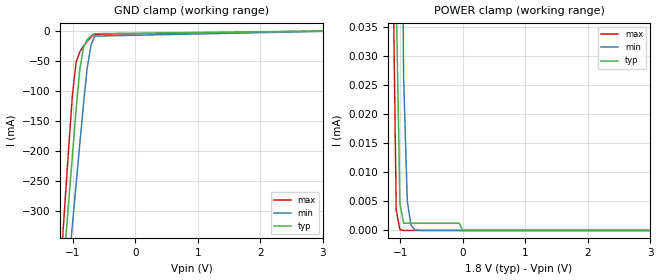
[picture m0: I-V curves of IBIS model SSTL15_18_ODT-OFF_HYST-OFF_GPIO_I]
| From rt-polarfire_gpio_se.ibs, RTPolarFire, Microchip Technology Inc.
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|   Model SSTL15_18_ODT-OFF_HYST-OFF_GPIO_I
[Model]   SSTL15_18_ODT-OFF_HYST-OFF_GPIO_I
Model_type   Input
Vinl =   0.65
Vinh =   0.85
|   typ   min   max
C_comp_pullup   2.605e-12   2.605e-12   2.76e-12
C_comp_pulldown  2.605e-12   2.605e-12   2.76e-12
[Temperature Range]  25C   125C   -55C
[Voltage Range]  1.8   1.71   1.89
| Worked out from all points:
|   GND clamp passes 1 mA (typ) near -0.53 V on its own axis
[GND Clamp]
| Voltage   I(typ)   I(min)   I(max)
-1.8V     -1.238A    -1.225A    -1.326A
-1.181V   -436.6mA   -523mA     -374.9mA
-1.122V   -360.2mA   -456.1mA   -284.4mA
-1.063V   -283.8mA   -389.1mA   -194mA
-1.004V   -207.4mA   -322.1mA   -107.1mA
-945mV    -131.1mA   -255.2mA   -52.45mA
-885.9mV  -64.84mA   -188.3mA   -35.49mA
-826.9mV  -28.05mA   -121.5mA   -26.09mA
-767.8mV  -14.97mA   -62.19mA   -17.97mA
-708.7mV  -9.067mA   -25.04mA   -11.24mA
-649.7mV  -5.157mA   -9.146mA   -6.157mA
3.6V      0A         0A         0A
[POWER Clamp]
| Voltage   I(typ)   I(min)   I(max)
-1.8V     692.2uA    1.126mA    963.1uA
-1.122V   247.5uA    171.1uA    51.59uA
-1.063V   40.35uA    168.8uA    3.466uA
-1.004V   4.6uA      104.4uA    139.5nA
-945mV    1.264uA    26.46uA    5.712nA
-885.9mV  1.264uA    5.041uA    911.6pA
-826.9mV  1.264uA    860.1nA    643.6pA
-767.8mV  1.264uA    140.8nA    596.9pA
-649.7mV  1.264uA    9.044nA    523.9pA
-59.06mV  1.264uA    4.338nA    72.98pA
0V        0A         1.735nA    25.09pA
3.6V      0A         0A         0A
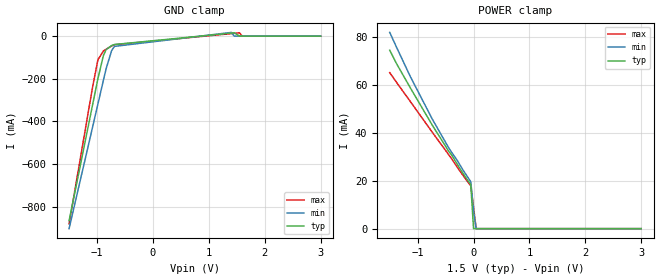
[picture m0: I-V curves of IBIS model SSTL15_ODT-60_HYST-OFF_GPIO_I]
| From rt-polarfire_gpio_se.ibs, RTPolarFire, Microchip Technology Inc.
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|   Model SSTL15_ODT-60_HYST-OFF_GPIO_I
[Model]   SSTL15_ODT-60_HYST-OFF_GPIO_I
Model_type   Input
Vinl =   0.65
Vinh =   0.85
|   typ   min   max
C_comp_pullup   2.605e-12   2.605e-12   2.76e-12
C_comp_pulldown  2.605e-12   2.605e-12   2.76e-12
[Temperature Range]  25C   125C   -55C
[Voltage Range]  1.5   1.425   1.575
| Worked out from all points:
|   POWER clamp passes 1 mA (typ) near -0.00 V on its own axis
[GND Clamp]
| Voltage   I(typ)   I(min)   I(max)
-1.5V     -866.8mA   -904mA     -882mA
-1.083V   -327mA     -430.7mA   -244mA
-984.4mV  -200.3mA   -318.9mA   -111.2mA
-885.9mV  -90.87mA   -207.3mA   -69.88mA
-836.7mV  -63.11mA   -152.3mA   -61.31mA
-738.3mV  -44.39mA   -67.75mA   -46.47mA
-689.1mV  -39.45mA   -48.31mA   -40.47mA
1.406V    14.12mA    17.42mA    11.79mA
1.453V    15.44mA    0A         12.97mA
1.549V    0A         0A         15.6mA
1.598V    0A         0A         0A
3V        0A         0A         0A
[POWER Clamp]
| Voltage   I(typ)   I(min)   I(max)
-1.5V     74.44mA    81.87mA    65.08mA
-1.378V   68.84mA    75.67mA    61.03mA
-1.132V   58.76mA    63.47mA    53.06mA
-738.3mV  43.17mA    45.7mA     40.2mA
-443mV    32.23mA    33.66mA    30.81mA
-393.7mV  30.81mA    31.89mA    29.2mA
-295.3mV  27mA       28.61mA    25.77mA
-196.9mV  23.35mA    24.77mA    22.49mA
-49.22mV  18.36mA    19.56mA    17.83mA
0V        0A         7.549mA    8.931mA
46.88mV   0A         0A         0A
3V        0A         0A         0A
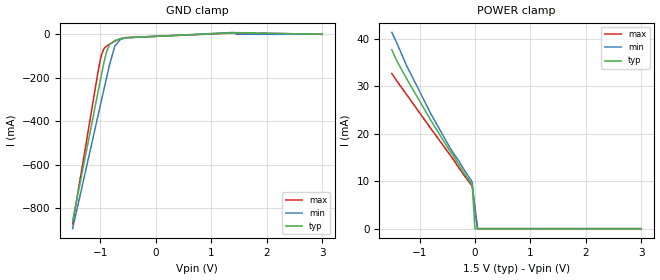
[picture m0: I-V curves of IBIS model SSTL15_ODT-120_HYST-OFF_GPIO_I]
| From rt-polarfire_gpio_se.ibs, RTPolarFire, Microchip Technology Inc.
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|   Model SSTL15_ODT-120_HYST-OFF_GPIO_I
[Model]   SSTL15_ODT-120_HYST-OFF_GPIO_I
Model_type   Input
Vinl =   0.65
Vinh =   0.85
|   typ   min   max
C_comp_pullup   2.605e-12   2.605e-12   2.76e-12
C_comp_pulldown  2.605e-12   2.605e-12   2.76e-12
[Temperature Range]  25C   125C   -55C
[Voltage Range]  1.5   1.425   1.575
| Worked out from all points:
|   POWER clamp passes 1 mA (typ) near -0.01 V on its own axis
[GND Clamp]
| Voltage   I(typ)   I(min)   I(max)
-1.5V     -858.6mA   -894mA     -873mA
-1.034V   -255.4mA   -365.2mA   -161.2mA
-984.4mV  -192mA     -309.4mA   -98.64mA
-935.2mV  -129.9mA   -253.6mA   -66.13mA
-885.9mV  -78.61mA   -197.9mA   -54.07mA
-836.7mV  -48.33mA   -142.5mA   -45.61mA
-738.3mV  -28.71mA   -54.17mA   -31.2mA
-639.8mV  -20.45mA   -23.73mA   -20.93mA
-541.4mV  -15.52mA   -16.57mA   -15.35mA
1.406V    7.094mA    8.744mA    5.909mA
1.453V    7.758mA    0A         6.503mA
3V        0A         0A         0A
[POWER Clamp]
| Voltage   I(typ)   I(min)   I(max)
-1.5V     37.76mA    41.4mA     32.73mA
-1.427V   35.78mA    39.62mA    31.44mA
-1.23V    31.58mA    34.3mA     28.23mA
-787.5mV  22.68mA    24.04mA    20.98mA
-443mV    16.19mA    16.91mA    15.45mA
-393.7mV  15.47mA    16.01mA    14.65mA
-295.3mV  13.58mA    14.37mA    12.93mA
-196.9mV  11.74mA    12.45mA    11.28mA
-49.22mV  9.228mA    9.823mA    8.945mA
0V        0A         3.79mA     4.479mA
46.88mV   0A         0A         0A
3V        0A         0A         0A
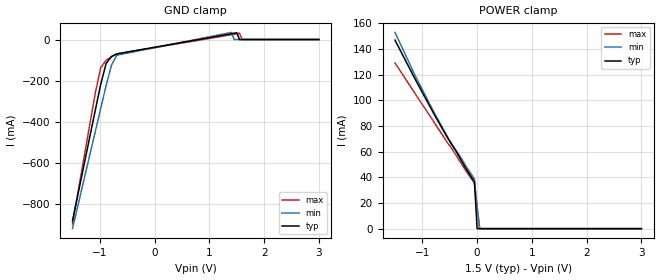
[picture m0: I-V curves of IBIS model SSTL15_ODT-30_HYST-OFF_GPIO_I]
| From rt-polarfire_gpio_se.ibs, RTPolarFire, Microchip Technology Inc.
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|   Model SSTL15_ODT-30_HYST-OFF_GPIO_I
[Model]   SSTL15_ODT-30_HYST-OFF_GPIO_I
Model_type   Input
Vinl =   0.65
Vinh =   0.85
|   typ   min   max
C_comp_pullup   2.605e-12   2.605e-12   2.76e-12
C_comp_pulldown  2.605e-12   2.605e-12   2.76e-12
[Temperature Range]  25C   125C   -55C
[Voltage Range]  1.5   1.425   1.575
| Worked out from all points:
|   POWER clamp passes 1 mA (typ) near -0.00 V on its own axis
[GND Clamp]
| Voltage   I(typ)   I(min)   I(max)
-1.5V     -884.2mA   -922.1mA   -898.2mA
-1.083V   -344.1mA   -448.2mA   -260.3mA
-984.4mV  -218.2mA   -336.2mA   -137.2mA
-885.9mV  -117.2mA   -224.4mA   -101.4mA
-787.5mV  -82.55mA   -124.9mA   -84.35mA
-689.1mV  -70.02mA   -76.55mA   -70.29mA
1.406V    28.04mA    34.67mA    23.42mA
1.453V    30.64mA    0A         25.76mA
1.5V      33.38mA    0A         28.22mA
1.549V    0A         0A         30.95mA
1.598V    0A         0A         0A
3V        0A         0A         0A
[POWER Clamp]
| Voltage   I(typ)   I(min)   I(max)
-1.5V     146.8mA    152.8mA    129mA
-1.132V   116.4mA    119.2mA    105.2mA
-787.5mV  89.29mA    90.53mA    82.91mA
-541.4mV  70.76mA    71.61mA    67mA
-443mV    64.04mA    64.56mA    61.15mA
-393.7mV  61.14mA    61.37mA    57.83mA
-295.3mV  53.46mA    55.27mA    51.07mA
-196.9mV  46.26mA    48.17mA    44.58mA
-49.22mV  36.41mA    38.62mA    35.37mA
0V        0A         14.94mA    17.71mA
46.88mV   0A         0A         0A
3V        0A         0A         0A
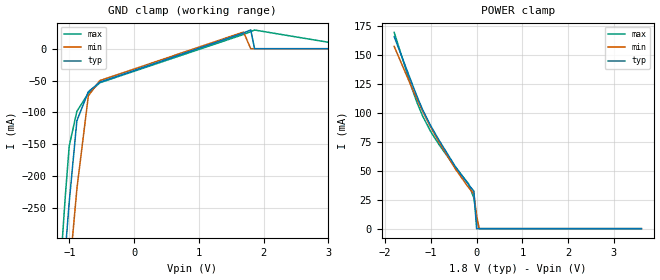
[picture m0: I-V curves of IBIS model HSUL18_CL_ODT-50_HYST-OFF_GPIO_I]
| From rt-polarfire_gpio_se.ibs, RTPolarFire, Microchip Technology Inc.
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|   Model HSUL18_CL_ODT-50_HYST-OFF_GPIO_I
[Model]   HSUL18_CL_ODT-50_HYST-OFF_GPIO_I
Model_type   Input
Vinl =   0.54
Vinh =   1.26
|   typ   min   max
C_comp_pullup   2.605e-12   2.605e-12   2.76e-12
C_comp_pulldown  2.605e-12   2.605e-12   2.76e-12
[Temperature Range]  25C   125C   -55C
[Voltage Range]  1.8   1.71   1.89
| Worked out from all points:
|   POWER clamp passes 1 mA (typ) near -0.00 V on its own axis
[GND Clamp]
| Voltage   I(typ)   I(min)   I(max)
-1.8V     -1.272A    -1.259A    -1.357A
-1.181V   -470mA     -556.1mA   -408mA
-1.122V   -393.6mA   -489.1mA   -317.7mA
-1.063V   -317.2mA   -421.9mA   -230mA
-1.004V   -241.2mA   -354.8mA   -153mA
-885.9mV  -113.4mA   -220.7mA   -98.51mA
-708.7mV  -67.58mA   -74.12mA   -70.14mA
-531.6mV  -52.72mA   -50.12mA   -53.54mA
1.688V    24.74mA    26.22mA    22.43mA
1.8V      29.61mA    0A         26.86mA
1.859V    0A         0A         29.37mA
3.6V      0A         0A         0A
[POWER Clamp]
| Voltage   I(typ)   I(min)   I(max)
-1.8V     166mA      157.5mA    169.6mA
-1.417V   126.1mA    122.1mA    121.7mA
-1.299V   114mA      111.8mA    108.7mA
-1.181V   103mA      101.7mA    97.53mA
-1.004V   89.06mA    87.84mA    83.98mA
-826.9mV  76.81mA    75.36mA    73mA
-472.5mV  54.2mA     52.12mA    53.39mA
-177.2mV  38.13mA    35.59mA    38.87mA
-59.06mV  32.36mA    29.86mA    26.42mA
0V        0A         11.48mA    9.081mA
56.25mV   0A         0A         0A
3.6V      0A         0A         0A
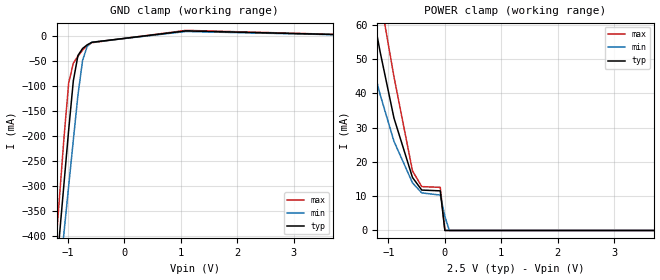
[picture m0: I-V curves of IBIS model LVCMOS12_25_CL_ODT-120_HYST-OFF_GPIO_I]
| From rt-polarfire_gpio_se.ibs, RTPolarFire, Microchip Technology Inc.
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|   LVCMOS12_25_CL_ODT-120_HYST-OFF_GPIO_I
[Model]   LVCMOS12_25_CL_ODT-120_HYST-OFF_GPIO_I
Model_type  Input
Vinl =   0.42
Vinh =   0.78
|   typ   min   max
C_comp_pullup   2.605e-12   2.605e-12   2.76e-12
C_comp_pulldown  2.605e-12   2.605e-12   2.76e-12
[Temperature Range]   25   125   -55
[Voltage Range]   2.5   2.375   2.625
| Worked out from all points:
|   GND clamp passes 1 mA (typ) near -0.06 V on its own axis
|   POWER clamp passes 1 mA (typ) near -0.01 V on its own axis
[GND Clamp]
| Voltage   I(typ)   I(min)   I(max)
-2.5V     -2.158A    -1.999A    -2.364A
-1.23V    -504.6mA   -573.7mA   -444.8mA
-1.148V   -398.5mA   -482.2mA   -322.2mA
-1.066V   -292.5mA   -390.7mA   -200.7mA
-984.4mV  -186.9mA   -299.2mA   -93.13mA
-902.3mV  -89.08mA   -207.7mA   -53.78mA
-820.3mV  -38.4mA    -117.4mA   -39.72mA
-738.3mV  -24.38mA   -48.1mA    -27.83mA
-656.2mV  -17.05mA   -19.99mA   -18.71mA
-574.2mV  -12.07mA   -11.93mA   -12.82mA
1.094V    10.78mA    9.586mA    11.85mA
5V        0A         0A         0A
[POWER Clamp]
| Voltage   I(typ)   I(min)   I(max)
-2.5V     202.8mA    159.7mA    249.5mA
-1.559V   91.03mA    68.62mA    117.2mA
-1.395V   74.77mA    56.28mA    96.95mA
-1.23V    59.44mA    44.97mA    77.37mA
-1.148V   52.21mA    39.73mA    68.15mA
-902.3mV  32.84mA    26.04mA    44.9mA
-574.2mV  15.48mA    13.91mA    17.41mA
-410.2mV  11.8mA     10.97mA    12.81mA
-82.03mV  11.57mA    10.34mA    12.59mA
0V        0A         4.135mA    0A
78.12mV   0A         0A         0A
5V        0A         0A         0A
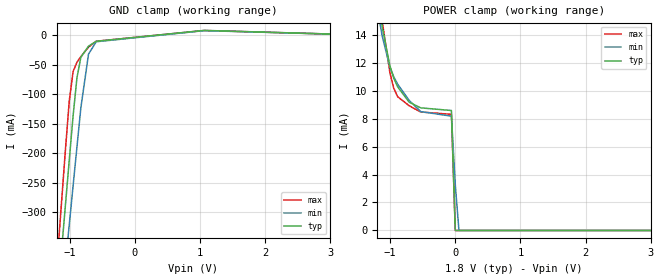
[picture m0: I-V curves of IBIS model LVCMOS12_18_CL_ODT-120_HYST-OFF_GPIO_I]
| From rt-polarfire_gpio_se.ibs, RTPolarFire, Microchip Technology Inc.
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|   LVCMOS12_18_CL_ODT-120_HYST-OFF_GPIO_I
[Model]   LVCMOS12_18_CL_ODT-120_HYST-OFF_GPIO_I
Model_type  Input
Vinl =   0.42
Vinh =   0.78
|   typ   min   max
C_comp_pullup   2.605e-12   2.605e-12   2.76e-12
C_comp_pulldown  2.605e-12   2.605e-12   2.76e-12
[Temperature Range]   25   125   -55
[Voltage Range]   1.8   1.71   1.89
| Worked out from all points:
|   GND clamp passes 1 mA (typ) near -0.08 V on its own axis
|   POWER clamp passes 1 mA (typ) near -0.01 V on its own axis
[GND Clamp]
| Voltage   I(typ)   I(min)   I(max)
-1.8V     -1.241A    -1.209A    -1.3A
-1.181V   -439.9mA   -518mA     -369.6mA
-1.122V   -363.5mA   -452.1mA   -281.3mA
-1.063V   -287.2mA   -386.2mA   -193.7mA
-1.004V   -211mA     -320.3mA   -111.1mA
-945mV    -135.7mA   -254.5mA   -61.34mA
-885.9mV  -71.93mA   -188.7mA   -45.77mA
-826.9mV  -37.63mA   -123.5mA   -36.31mA
-708.7mV  -18.58mA   -32.12mA   -20.24mA
-590.6mV  -10.42mA   -11.17mA   -10.25mA
1.069V    8.031mA    7.612mA    7.854mA
3.6V      0A         0A         0A
[POWER Clamp]
| Voltage   I(typ)   I(min)   I(max)
-1.8V     54.22mA    42.13mA    70.18mA
-1.181V   16.58mA    15.43mA    17.47mA
-1.122V   14.54mA    13.88mA    14.94mA
-1.004V   11.76mA    11.68mA    11.27mA
-945mV    10.89mA    10.99mA    10.17mA
-885.9mV  10.27mA    10.46mA    9.566mA
-708.7mV  9.171mA    9.301mA    8.914mA
-531.6mV  8.764mA    8.498mA    8.47mA
-59.06mV  8.574mA    8.168mA    8.301mA
0V        0A         3.265mA    0A
56.25mV   0A         0A         0A
3.6V      0A         0A         0A
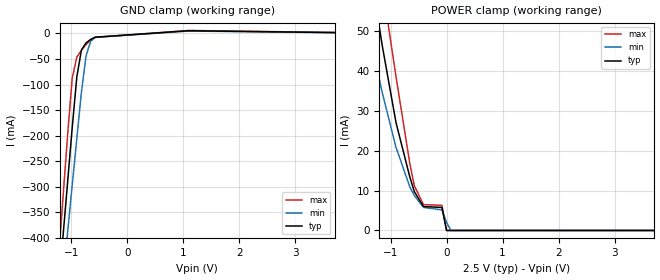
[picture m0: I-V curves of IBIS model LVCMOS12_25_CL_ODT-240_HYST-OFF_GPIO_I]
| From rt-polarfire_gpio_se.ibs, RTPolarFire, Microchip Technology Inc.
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|   LVCMOS12_25_CL_ODT-240_HYST-OFF_GPIO_I
[Model]   LVCMOS12_25_CL_ODT-240_HYST-OFF_GPIO_I
Model_type  Input
Vinl =   0.42
Vinh =   0.78
|   typ   min   max
C_comp_pullup   2.605e-12   2.605e-12   2.76e-12
C_comp_pulldown  2.605e-12   2.605e-12   2.76e-12
[Temperature Range]   25   125   -55
[Voltage Range]   2.5   2.375   2.625
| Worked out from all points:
|   GND clamp passes 1 mA (typ) near -0.11 V on its own axis
|   POWER clamp passes 1 mA (typ) near -0.01 V on its own axis
[GND Clamp]
| Voltage   I(typ)   I(min)   I(max)
-2.5V     -2.156A    -1.997A    -2.362A
-1.23V    -502.5mA   -571.5mA   -442.6mA
-1.148V   -396.3mA   -480.1mA   -319.6mA
-1.066V   -290.3mA   -388.6mA   -197.5mA
-984.4mV  -184.4mA   -297.1mA   -87.48mA
-902.3mV  -84.93mA   -205.7mA   -46.15mA
-820.3mV  -32.45mA   -115mA     -32.8mA
-738.3mV  -18.55mA   -44.29mA   -21.72mA
-656.2mV  -11.66mA   -15.34mA   -13.05mA
-574.2mV  -7.219mA   -7.526mA   -7.675mA
1.094V    5.396mA    4.796mA    5.931mA
5V        0A         0A         0A
[POWER Clamp]
| Voltage   I(typ)   I(min)   I(max)
-2.5V     196.5mA    154.3mA    242.1mA
-1.559V   85.13mA    63.41mA    110.5mA
-1.312V   61.08mA    45.31mA    80.31mA
-1.148V   46.36mA    34.56mA    61.63mA
-902.3mV  27.07mA    20.87mA    38.58mA
-656.2mV  13.44mA    10.95mA    16.83mA
-574.2mV  9.698mA    8.728mA    11.15mA
-410.2mV  5.994mA    5.783mA    6.495mA
-82.03mV  5.785mA    5.17mA     6.296mA
0V        0A         2.067mA    0A
78.12mV   0A         0A         0A
5V        0A         0A         0A
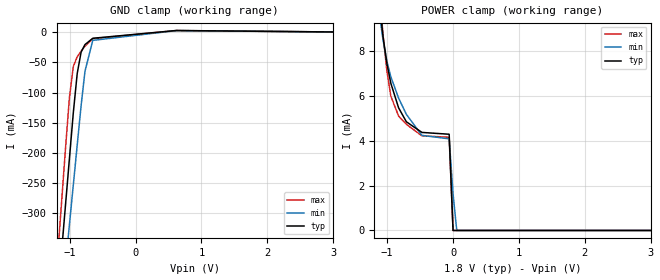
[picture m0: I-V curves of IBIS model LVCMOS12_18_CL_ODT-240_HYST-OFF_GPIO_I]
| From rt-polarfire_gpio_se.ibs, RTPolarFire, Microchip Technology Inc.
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|   LVCMOS12_18_CL_ODT-240_HYST-OFF_GPIO_I
[Model]   LVCMOS12_18_CL_ODT-240_HYST-OFF_GPIO_I
Model_type  Input
Vinl =   0.42
Vinh =   0.78
|   typ   min   max
C_comp_pullup   2.605e-12   2.605e-12   2.76e-12
C_comp_pulldown  2.605e-12   2.605e-12   2.76e-12
[Temperature Range]   25   125   -55
[Voltage Range]   1.8   1.71   1.89
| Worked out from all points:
|   GND clamp passes 1 mA (typ) near -0.15 V on its own axis
|   POWER clamp passes 1 mA (typ) near -0.01 V on its own axis
[GND Clamp]
| Voltage   I(typ)   I(min)   I(max)
-1.8V     -1.24A     -1.207A    -1.299A
-1.181V   -438.2mA   -516.2mA   -368.1mA
-1.122V   -361.8mA   -450.4mA   -279.6mA
-1.063V   -285.4mA   -384.5mA   -191.6mA
-1.004V   -209.1mA   -318.7mA   -108mA
-945mV    -133.2mA   -252.8mA   -56.56mA
-885.9mV  -68.26mA   -187mA     -40.48mA
-826.9mV  -32.87mA   -121.6mA   -31.13mA
-767.8mV  -20.31mA   -64.31mA   -22.99mA
-649.7mV  -9.872mA   -13.35mA   -10.58mA
618.8mV   3.008mA    2.833mA    2.969mA
3.6V      0A         0A         0A
[POWER Clamp]
| Voltage   I(typ)   I(min)   I(max)
-1.8V     49.82mA    37.99mA    65.68mA
-1.122V   10.21mA    9.747mA    10.77mA
-1.063V   8.628mA    8.48mA     8.704mA
-1.004V   7.429mA    7.538mA    7.094mA
-945mV    6.559mA    6.85mA     5.984mA
-826.9mV  5.463mA    5.896mA    5.096mA
-708.7mV  4.841mA    5.172mA    4.728mA
-472.5mV  4.368mA    4.236mA    4.215mA
-59.06mV  4.287mA    4.083mA    4.151mA
0V        0A         1.632mA    0A
56.25mV   0A         0A         0A
3.6V      0A         0A         0A
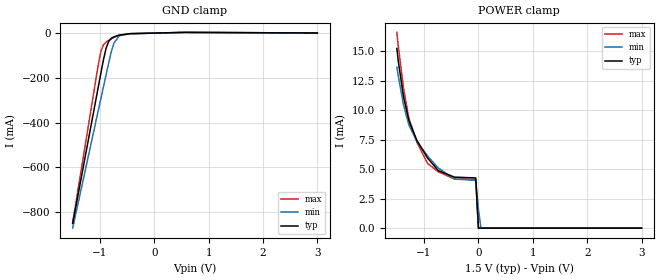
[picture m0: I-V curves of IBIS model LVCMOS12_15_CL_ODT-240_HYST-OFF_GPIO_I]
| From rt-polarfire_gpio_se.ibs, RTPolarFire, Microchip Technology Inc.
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|   LVCMOS12_15_CL_ODT-240_HYST-OFF_GPIO_I
[Model]   LVCMOS12_15_CL_ODT-240_HYST-OFF_GPIO_I
Model_type  Input
Vinl =   0.42
Vinh =   0.78
|   typ   min   max
C_comp_pullup   2.605e-12   2.605e-12   2.76e-12
C_comp_pulldown  2.605e-12   2.605e-12   2.76e-12
[Temperature Range]   25   125   -55
[Voltage Range]   1.5   1.425   1.575
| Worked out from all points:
|   GND clamp passes 1 mA (typ) near -0.15 V on its own axis
|   POWER clamp passes 1 mA (typ) near -0.01 V on its own axis
[GND Clamp]
| Voltage   I(typ)   I(min)   I(max)
-1.5V     -850.9mA   -871.6mA   -847.1mA
-1.034V   -247.2mA   -351.6mA   -148.1mA
-984.4mV  -183.7mA   -296.7mA   -85.72mA
-935.2mV  -121mA     -241.8mA   -52.39mA
-885.9mV  -68.26mA   -187mA     -40.48mA
-836.7mV  -36.64mA   -132.4mA   -32.6mA
-787.5mV  -23.23mA   -81.35mA   -25.57mA
-738.3mV  -16.97mA   -43.51mA   -19.39mA
-639.8mV  -9.261mA   -11.98mA   -9.818mA
-443mV    -3.053mA   -3.101mA   -2.895mA
562.5mV   2.816mA    2.65mA     2.783mA
3V        0A         0A         0A
[POWER Clamp]
| Voltage   I(typ)   I(min)   I(max)
-1.5V     15.22mA    13.63mA    16.58mA
-1.477V   14.24mA    12.96mA    15.55mA
-1.378V   11.13mA    10.43mA    11.86mA
-1.28V    9.114mA    8.747mA    9.341mA
-1.132V   7.429mA    7.347mA    7.265mA
-935.2mV  5.936mA    6.115mA    5.482mA
-738.3mV  4.874mA    5.099mA    4.775mA
-443mV    4.32mA     4.161mA    4.172mA
-49.22mV  4.251mA    4.041mA    4.122mA
0V        0A         1.615mA    0A
46.88mV   0A         0A         0A
3V        0A         0A         0A
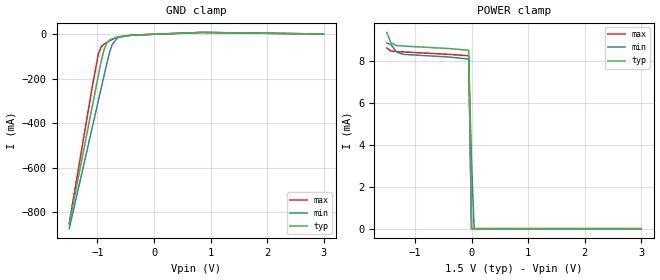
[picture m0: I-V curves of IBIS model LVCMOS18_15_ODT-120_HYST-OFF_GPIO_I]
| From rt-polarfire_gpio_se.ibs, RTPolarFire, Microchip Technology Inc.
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|   LVCMOS18_15_ODT-120_HYST-OFF_GPIO_I
[Model]   LVCMOS18_15_ODT-120_HYST-OFF_GPIO_I
Model_type  Input
Vinl =   0.63
Vinh =   1.17
|   typ   min   max
C_comp_pullup   2.605e-12   2.605e-12   2.76e-12
C_comp_pulldown  2.605e-12   2.605e-12   2.76e-12
[Temperature Range]   25   125   -55
[Voltage Range]   1.5   1.425   1.575
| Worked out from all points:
|   GND clamp passes 1 mA (typ) near -0.08 V on its own axis
|   POWER clamp passes 1 mA (typ) near -0.01 V on its own axis
[GND Clamp]
| Voltage   I(typ)   I(min)   I(max)
-1.5V     -852.5mA   -873.3mA   -848.4mA
-1.083V   -312.6mA   -408.2mA   -222.8mA
-984.4mV  -185.7mA   -298.4mA   -89.41mA
-935.2mV  -123.6mA   -243.5mA   -57.35mA
-885.9mV  -71.93mA   -188.7mA   -45.77mA
-836.7mV  -41.29mA   -134.2mA   -37.81mA
-787.5mV  -28.06mA   -83.7mA    -30.47mA
-738.3mV  -21.49mA   -46.58mA   -23.79mA
-639.8mV  -13.25mA   -15.73mA   -13.57mA
-393.7mV  -5.161mA   -5.051mA   -4.943mA
843.8mV   7.243mA    6.847mA    7.128mA
3V        0A         0A         0A
[POWER Clamp]
| Voltage   I(typ)   I(min)   I(max)
-1.5V     9.355mA    8.849mA    8.613mA
-1.427V   8.863mA    8.778mA    8.47mA
-1.329V   8.727mA    8.435mA    8.441mA
-1.23V    8.707mA    8.318mA    8.427mA
-1.181V   8.7mA      8.303mA    8.42mA
-393.7mV  8.584mA    8.18mA     8.307mA
-49.22mV  8.503mA    8.083mA    8.243mA
0V        0A         3.23mA     0A
46.88mV   0A         0A         0A
3V        0A         0A         0A
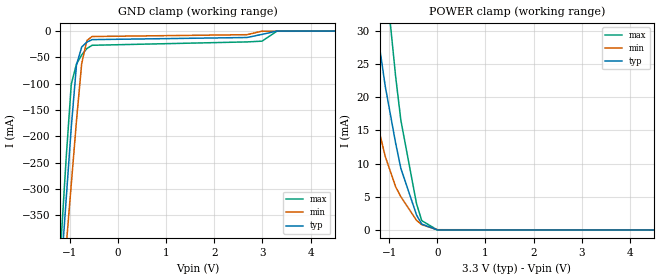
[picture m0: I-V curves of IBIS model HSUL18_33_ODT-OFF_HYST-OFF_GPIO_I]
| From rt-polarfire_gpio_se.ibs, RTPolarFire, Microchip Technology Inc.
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|   HSUL18_33_ODT-OFF_HYST-OFF_GPIO_I
[Model]   HSUL18_33_ODT-OFF_HYST-OFF_GPIO_I
Model_type  Input
Vinl =   0.54
Vinh =   1.26
|   typ   min   max
C_comp_pullup   2.605e-12   2.605e-12   2.76e-12
C_comp_pulldown  2.605e-12   2.605e-12   2.76e-12
[Temperature Range]   25   125   -55
[Voltage Range]   3.3   3.135   3.465
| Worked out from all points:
|   POWER clamp passes 1 mA (typ) near -0.33 V on its own axis
[GND Clamp]
| Voltage   I(typ)   I(min)   I(max)
-3.3V     -3.241A    -2.919A    -3.641A
-1.408V   -743.2mA   -773.9mA   -731.8mA
-1.083V   -322.3mA   -411.6mA   -243.8mA
-974.5mV  -182.3mA   -290.8mA   -100.5mA
-866.2mV  -64.02mA   -170.2mA   -62.31mA
-758mV    -30.07mA   -61.26mA   -45.14mA
-649.7mV  -20.81mA   -17.79mA   -33.01mA
-541.4mV  -16.11mA   -10.19mA   -26.85mA
2.681V    -12.07mA   -6.706mA   -20.45mA
2.991V    -6.109mA   38.53uA    -19.03mA
3.3V      142uA      0A         -201.4uA
6.6V      0A         0A         0A
[POWER Clamp]
| Voltage   I(typ)   I(min)   I(max)
-3.3V     176.4mA    117.8mA    244.3mA
-1.949V   72.64mA    43.25mA    110.4mA
-1.841V   65.11mA    38.4mA     100.8mA
-1.624V   50.82mA    29.2mA     81.84mA
-1.408V   37.91mA    20.92mA    63.59mA
-1.083V   21.65mA    11.08mA    38.77mA
-866.2mV  13.05mA    6.493mA    23.07mA
-758mV    9.269mA    5.001mA    16.51mA
-433.1mV  2.269mA    1.451mA    3.966mA
-324.8mV  889.1uA    795.6uA    1.407mA
0V        0A         37.57uA    0A
6.6V      0A         0A         0A
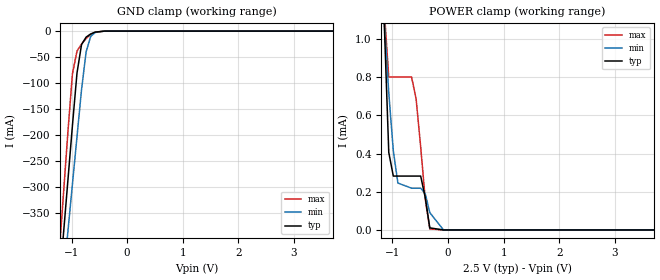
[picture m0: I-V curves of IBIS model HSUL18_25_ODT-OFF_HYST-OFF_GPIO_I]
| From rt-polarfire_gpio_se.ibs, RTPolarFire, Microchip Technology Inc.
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|   HSUL18_25_ODT-OFF_HYST-OFF_GPIO_I
[Model]   HSUL18_25_ODT-OFF_HYST-OFF_GPIO_I
Model_type  Input
Vinl =   0.54
Vinh =   1.26
|   typ   min   max
C_comp_pullup   2.605e-12   2.605e-12   2.76e-12
C_comp_pulldown  2.605e-12   2.605e-12   2.76e-12
[Temperature Range]   25   125   -55
[Voltage Range]   2.5   2.375   2.625
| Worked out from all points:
|   GND clamp passes 1 mA (typ) near -0.52 V on its own axis
|   POWER clamp passes 1 mA (typ) near -1.14 V on its own axis
[GND Clamp]
| Voltage   I(typ)   I(min)   I(max)
-2.5V     -2.154A    -1.994A    -2.361A
-1.23V    -500.3mA   -569.3mA   -440.6mA
-1.148V   -394.1mA   -477.9mA   -317.5mA
-1.066V   -288mA     -386.4mA   -194.7mA
-984.4mV  -181.9mA   -294.9mA   -82.35mA
-902.3mV  -80.78mA   -203.5mA   -38.51mA
-820.3mV  -25.8mA    -112.4mA   -25.07mA
-738.3mV  -11.65mA   -40.15mA   -14.38mA
-656.2mV  -5.525mA   -10.18mA   -6.627mA
-574.2mV  -1.954mA   -2.664mA   -2.193mA
-410.2mV  -41.8uA    -101uA     -33.53uA
5V        0A         0A         0A
[POWER Clamp]
| Voltage   I(typ)   I(min)   I(max)
-2.5V     57.18mA    34.85mA    87.29mA
-1.148V   1.09mA     1.098mA    1.154mA
-1.066V   406uA      718.7uA    801.6uA
-984.4mV  282.4uA    415.1uA    801.6uA
-902.3mV  282.4uA    245.8uA    801.6uA
-656.2mV  282.4uA    218.9uA    801.6uA
-574.2mV  282.4uA    218.9uA    686.6uA
-492.2mV  282.4uA    218.9uA    435.7uA
-410.2mV  170.3uA    190.3uA    161.6uA
-328.1mV  11.03uA    91uA       5.545uA
-82.03mV  1.223nA    116.3nA    641.1pA
5V        0A         0A         0A
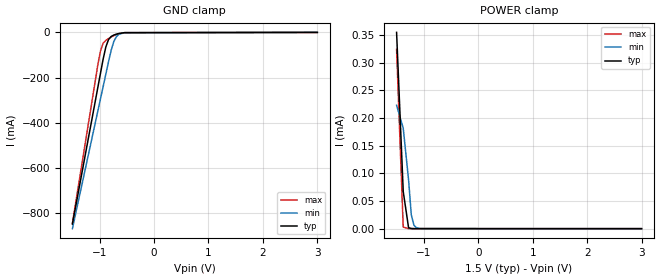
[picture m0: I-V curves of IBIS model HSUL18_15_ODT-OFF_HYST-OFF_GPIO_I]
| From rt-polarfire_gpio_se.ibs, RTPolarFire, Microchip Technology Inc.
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|   HSUL18_15_ODT-OFF_HYST-OFF_GPIO_I
[Model]   HSUL18_15_ODT-OFF_HYST-OFF_GPIO_I
Model_type  Input
Vinl =   0.54
Vinh =   1.26
|   typ   min   max
C_comp_pullup   2.605e-12   2.605e-12   2.76e-12
C_comp_pulldown  2.605e-12   2.605e-12   2.76e-12
[Temperature Range]   25   125   -55
[Voltage Range]   1.5   1.425   1.575
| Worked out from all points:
|   GND clamp passes 1 mA (typ) near -0.53 V on its own axis
[GND Clamp]
| Voltage   I(typ)   I(min)   I(max)
-1.5V     -849.3mA   -869.7mA   -845.9mA
-1.034V   -245.6mA   -349.8mA   -145.8mA
-984.4mV  -181.9mA   -294.9mA   -82.35mA
-935.2mV  -118.6mA   -240.1mA   -47.7mA
-885.9mV  -64.84mA   -185.3mA   -35.39mA
-836.7mV  -32mA      -130.5mA   -27.49mA
-787.5mV  -17.96mA   -78.8mA    -20.49mA
-738.3mV  -11.65mA   -40.15mA   -14.38mA
-689.1mV  -7.607mA   -17.8mA    -9.336mA
-639.8mV  -4.632mA   -7.754mA   -5.477mA
-541.4mV  -1.114mA   -1.517mA   -1.241mA
3V        0A         0A         0A
[POWER Clamp]
| Voltage   I(typ)   I(min)   I(max)
-1.5V     355.1uA    223.2uA    324.6uA
-1.378V   67.3uA     181.8uA    2.834uA
-1.28V    1.768uA    88.6uA     12.72nA
-1.23V    234.6nA    24.93uA    1.954nA
-1.181V   30.81nA    6.249uA    1.533nA
-1.132V   18.01nA    1.446uA    1.533nA
-1.083V   18.01nA    346nA      1.533nA
-1.034V   18.01nA    167.8nA    1.533nA
-49.22mV  10.42nA    167.8nA    1.533nA
0V        0A         67.13nA    0A
46.88mV   0A         0A         0A
3V        0A         0A         0A
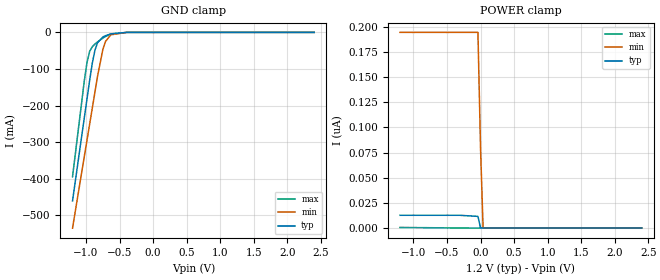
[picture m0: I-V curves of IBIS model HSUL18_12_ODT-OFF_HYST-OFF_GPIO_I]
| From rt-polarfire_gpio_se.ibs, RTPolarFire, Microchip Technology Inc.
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|   HSUL18_12_ODT-OFF_HYST-OFF_GPIO_I
[Model]   HSUL18_12_ODT-OFF_HYST-OFF_GPIO_I
Model_type  Input
Vinl =   0.54
Vinh =   1.26
|   typ   min   max
C_comp_pullup   2.605e-12   2.605e-12   2.76e-12
C_comp_pulldown  2.605e-12   2.605e-12   2.76e-12
[Temperature Range]   25   125   -55
[Voltage Range]   1.2   1.14   1.26
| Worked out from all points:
|   GND clamp passes 1 mA (typ) near -0.53 V on its own axis
[GND Clamp]
| Voltage   I(typ)   I(min)   I(max)
-1.2V     -460.9mA   -535.4mA   -394.9mA
-1.024V   -232.8mA   -338.8mA   -131.7mA
-984.4mV  -181.9mA   -294.9mA   -82.35mA
-945mV    -131.1mA   -251mA     -52.07mA
-905.6mV  -84.23mA   -207.2mA   -39.2mA
-866.2mV  -48.93mA   -163.3mA   -32.08mA
-826.9mV  -28.05mA   -119.6mA   -26.03mA
-748.1mV  -12.65mA   -46.58mA   -15.53mA
-708.7mV  -9.067mA   -24.89mA   -11.22mA
-630mV    -4.141mA   -6.6mA     -4.853mA
-393.7mV  -25.22uA   -68.77uA   -17.62uA
2.4V      0A         0A         0A
[POWER Clamp]
| Voltage   I(typ)   I(min)   I(max)
-1.2V     12.6nA     194.5nA    477.5pA
-315mV    12.6nA     194.5nA    -34.28pA
-39.38mV  11.49nA    194.5nA    -192.4pA
0V        0A         77.81nA    0A
37.5mV    0A         0A         0A
2.4V      0A         0A         0A
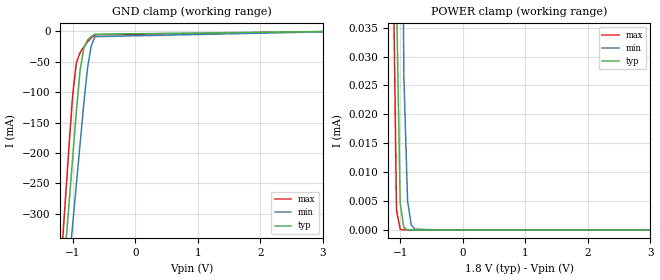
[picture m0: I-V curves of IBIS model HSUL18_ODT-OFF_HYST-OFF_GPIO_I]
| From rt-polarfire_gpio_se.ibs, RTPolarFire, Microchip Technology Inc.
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|   HSUL18_ODT-OFF_HYST-OFF_GPIO_I
[Model]   HSUL18_ODT-OFF_HYST-OFF_GPIO_I
Model_type  Input
Vinl =   0.54
Vinh =   1.26
|   typ   min   max
C_comp_pullup   2.605e-12   2.605e-12   2.76e-12
C_comp_pulldown  2.605e-12   2.605e-12   2.76e-12
[Temperature Range]   25   125   -55
[Voltage Range]   1.8   1.71   1.89
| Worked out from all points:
|   GND clamp passes 1 mA (typ) near -0.53 V on its own axis
[GND Clamp]
| Voltage   I(typ)   I(min)   I(max)
-1.8V     -1.238A    -1.205A    -1.297A
-1.181V   -436.6mA   -514.5mA   -366.8mA
-1.122V   -360.2mA   -448.6mA   -278.2mA
-1.063V   -283.8mA   -382.8mA   -189.8mA
-1.004V   -207.4mA   -316.9mA   -105.1mA
-945mV    -131.1mA   -251mA     -52.07mA
-885.9mV  -64.84mA   -185.3mA   -35.39mA
-826.9mV  -28.05mA   -119.6mA   -26.03mA
-767.8mV  -14.97mA   -61.45mA   -17.93mA
-708.7mV  -9.067mA   -24.89mA   -11.22mA
-649.7mV  -5.157mA   -9.126mA   -6.151mA
3.6V      0A         0A         0A
[POWER Clamp]
| Voltage   I(typ)   I(min)   I(max)
-1.8V     771.8uA    1.126mA    962.9uA
-1.122V   247.5uA    171.1uA    51.59uA
-1.063V   40.35uA    168.8uA    3.466uA
-1.004V   4.6uA      104.4uA    139.5nA
-945mV    421.8nA    26.46uA    5.821nA
-885.9mV  36.91nA    5.041uA    1.36nA
-826.9mV  3.957nA    860.1nA    1.36nA
-767.8mV  3.894nA    140.8nA    1.36nA
-354.4mV  3.894nA    3.711nA    1.36nA
3.6V      0A         0A         0A
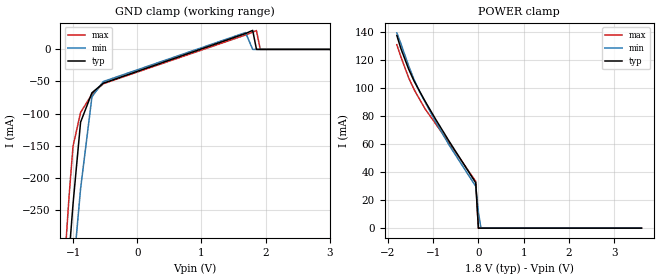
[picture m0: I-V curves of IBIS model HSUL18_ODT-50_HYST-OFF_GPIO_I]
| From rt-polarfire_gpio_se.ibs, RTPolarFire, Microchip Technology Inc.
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|   HSUL18_ODT-50_HYST-OFF_GPIO_I
[Model]   HSUL18_ODT-50_HYST-OFF_GPIO_I
Model_type  Input
Vinl =   0.54
Vinh =   1.26
|   typ   min   max
C_comp_pullup   2.605e-12   2.605e-12   2.76e-12
C_comp_pulldown  2.605e-12   2.605e-12   2.76e-12
[Temperature Range]   25   125   -55
[Voltage Range]   1.8   1.71   1.89
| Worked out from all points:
|   POWER clamp passes 1 mA (typ) near -0.00 V on its own axis
[GND Clamp]
| Voltage   I(typ)   I(min)   I(max)
-1.8V     -1.272A    -1.239A    -1.328A
-1.181V   -470mA     -547.1mA   -399.3mA
-1.063V   -317.2mA   -415.1mA   -225.5mA
-1.004V   -241.2mA   -349.1mA   -151mA
-885.9mV  -113.4mA   -217.2mA   -98.26mA
-708.7mV  -67.58mA   -73.81mA   -70.01mA
-531.6mV  -52.72mA   -50.07mA   -53.48mA
1.688V    24.74mA    26.2mA     22.42mA
1.8V      29.61mA    0A         26.85mA
1.859V    0A         0A         29.35mA
1.918V    0A         0A         0A
3.6V      0A         0A         0A
[POWER Clamp]
| Voltage   I(typ)   I(min)   I(max)
-1.8V     137.5mA    139.3mA    130.9mA
-1.713V   128.3mA    131.8mA    122.4mA
-1.536V   113.2mA    115.5mA    107mA
-1.417V   104.8mA    105.7mA    98.77mA
-1.299V   97.77mA    97.42mA    91.99mA
-1.181V   90.82mA    90.27mA    85.3mA
-945mV    77.76mA    75.96mA    74.48mA
-649.7mV  62.18mA    59.48mA    60.95mA
-59.06mV  32.36mA    29.84mA    33.37mA
0V        0A         11.47mA    0A
56.25mV   0A         0A         0A
3.6V      0A         0A         0A
